VERSION 5.8 ;
BUSBITCHARS "[]" ;
DIVIDERCHAR "/" ;
UNITS
    DATABASE MICRONS 1000 ;
END UNITS

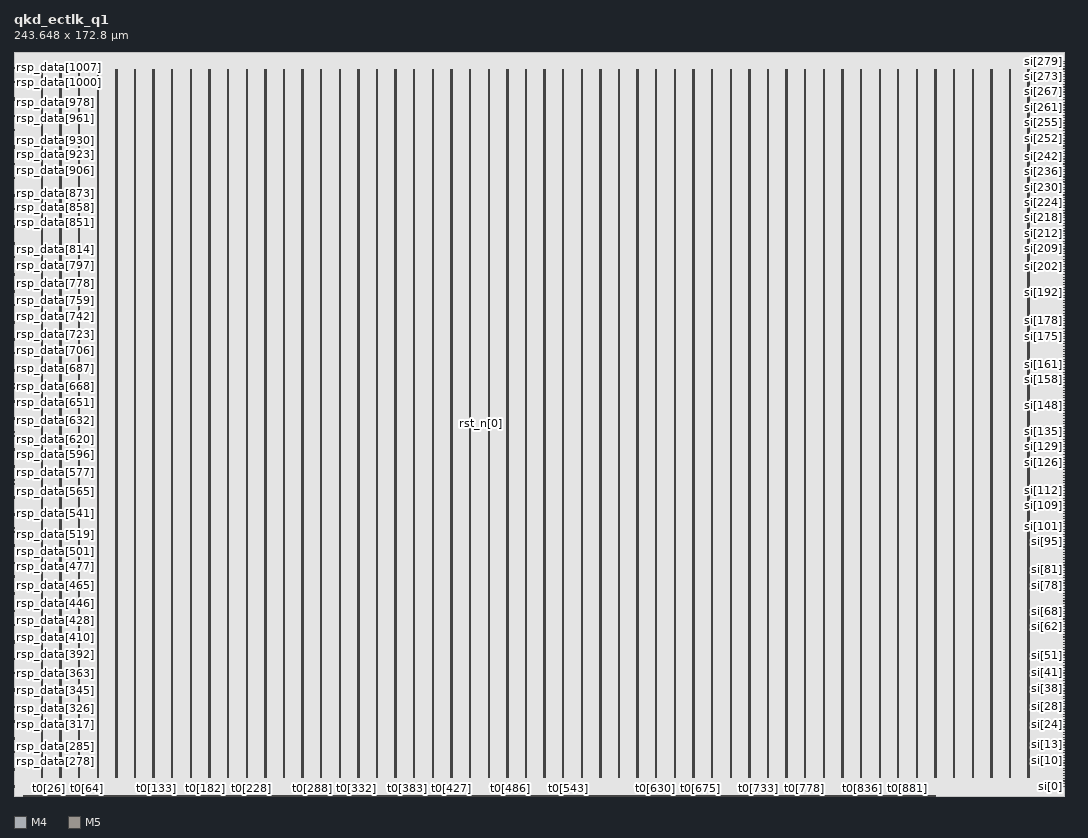
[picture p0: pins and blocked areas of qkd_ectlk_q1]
MACRO qkd_ectlk_q1
  FOREIGN qkd_ectlk_q1 0 0 ;
  CLASS BLOCK ;
  SIZE 243.648 BY 172.8 ;
  PIN cfg[0]
    DIRECTION INPUT ;
    USE SIGNAL ;
    PORT
      LAYER M4 ;
        RECT  0 2.076 0.192 2.1 ;
    END
  END cfg[0]
  PIN cfg[1]
    DIRECTION INPUT ;
    USE SIGNAL ;
    PORT
      LAYER M4 ;
        RECT  0 2.316 0.192 2.34 ;
    END
  END cfg[1]
  PIN cfg[2]
    DIRECTION INPUT ;
    USE SIGNAL ;
    PORT
      LAYER M4 ;
        RECT  0 2.556 0.192 2.58 ;
    END
  END cfg[2]
  PIN cfg[3]
    DIRECTION INPUT ;
    USE SIGNAL ;
    PORT
      LAYER M4 ;
        RECT  0 2.748 0.192 2.772 ;
    END
  END cfg[3]
  PIN cfg[4]
    DIRECTION INPUT ;
    USE SIGNAL ;
    PORT
      LAYER M4 ;
        RECT  0 2.988 0.192 3.012 ;
    END
  END cfg[4]
  PIN ck[0]
    DIRECTION INPUT ;
    USE SIGNAL ;
    PORT
      LAYER M5 ;
        RECT  108 86.16 108.048 86.64 ;
    END
  END ck[0]
  PIN rsp_data[1000]
    DIRECTION INPUT ;
    USE SIGNAL ;
    PORT
      LAYER M4 ;
        RECT  0 165.66 0.192 165.684 ;
    END
  END rsp_data[1000]
  PIN rsp_data[1001]
    DIRECTION INPUT ;
    USE SIGNAL ;
    PORT
      LAYER M4 ;
        RECT  0 165.852 0.192 165.876 ;
    END
  END rsp_data[1001]
  PIN rsp_data[1002]
    DIRECTION INPUT ;
    USE SIGNAL ;
    PORT
      LAYER M4 ;
        RECT  0 166.092 0.192 166.116 ;
    END
  END rsp_data[1002]
  PIN rsp_data[1003]
    DIRECTION INPUT ;
    USE SIGNAL ;
    PORT
      LAYER M4 ;
        RECT  0 166.332 0.192 166.356 ;
    END
  END rsp_data[1003]
  PIN rsp_data[1004]
    DIRECTION INPUT ;
    USE SIGNAL ;
    PORT
      LAYER M4 ;
        RECT  0 166.524 0.192 166.548 ;
    END
  END rsp_data[1004]
  PIN rsp_data[1005]
    DIRECTION INPUT ;
    USE SIGNAL ;
    PORT
      LAYER M4 ;
        RECT  0 166.764 0.192 166.788 ;
    END
  END rsp_data[1005]
  PIN rsp_data[1006]
    DIRECTION INPUT ;
    USE SIGNAL ;
    PORT
      LAYER M4 ;
        RECT  0 166.956 0.192 166.98 ;
    END
  END rsp_data[1006]
  PIN rsp_data[1007]
    DIRECTION INPUT ;
    USE SIGNAL ;
    PORT
      LAYER M4 ;
        RECT  0 167.196 0.192 167.22 ;
    END
  END rsp_data[1007]
  PIN rsp_data[1008]
    DIRECTION INPUT ;
    USE SIGNAL ;
    PORT
      LAYER M4 ;
        RECT  0 167.388 0.192 167.412 ;
    END
  END rsp_data[1008]
  PIN rsp_data[1009]
    DIRECTION INPUT ;
    USE SIGNAL ;
    PORT
      LAYER M4 ;
        RECT  0 167.628 0.192 167.652 ;
    END
  END rsp_data[1009]
  PIN rsp_data[1010]
    DIRECTION INPUT ;
    USE SIGNAL ;
    PORT
      LAYER M4 ;
        RECT  0 167.82 0.192 167.844 ;
    END
  END rsp_data[1010]
  PIN rsp_data[1011]
    DIRECTION INPUT ;
    USE SIGNAL ;
    PORT
      LAYER M4 ;
        RECT  0 168.06 0.192 168.084 ;
    END
  END rsp_data[1011]
  PIN rsp_data[1012]
    DIRECTION INPUT ;
    USE SIGNAL ;
    PORT
      LAYER M4 ;
        RECT  0 168.3 0.192 168.324 ;
    END
  END rsp_data[1012]
  PIN rsp_data[1013]
    DIRECTION INPUT ;
    USE SIGNAL ;
    PORT
      LAYER M4 ;
        RECT  0 168.492 0.192 168.516 ;
    END
  END rsp_data[1013]
  PIN rsp_data[1014]
    DIRECTION INPUT ;
    USE SIGNAL ;
    PORT
      LAYER M4 ;
        RECT  0 168.732 0.192 168.756 ;
    END
  END rsp_data[1014]
  PIN rsp_data[1015]
    DIRECTION INPUT ;
    USE SIGNAL ;
    PORT
      LAYER M4 ;
        RECT  0 168.924 0.192 168.948 ;
    END
  END rsp_data[1015]
  PIN rsp_data[1016]
    DIRECTION INPUT ;
    USE SIGNAL ;
    PORT
      LAYER M4 ;
        RECT  0 169.164 0.192 169.188 ;
    END
  END rsp_data[1016]
  PIN rsp_data[1017]
    DIRECTION INPUT ;
    USE SIGNAL ;
    PORT
      LAYER M4 ;
        RECT  0 169.356 0.192 169.38 ;
    END
  END rsp_data[1017]
  PIN rsp_data[1018]
    DIRECTION INPUT ;
    USE SIGNAL ;
    PORT
      LAYER M4 ;
        RECT  0 169.596 0.192 169.62 ;
    END
  END rsp_data[1018]
  PIN rsp_data[1019]
    DIRECTION INPUT ;
    USE SIGNAL ;
    PORT
      LAYER M4 ;
        RECT  0 169.788 0.192 169.812 ;
    END
  END rsp_data[1019]
  PIN rsp_data[1020]
    DIRECTION INPUT ;
    USE SIGNAL ;
    PORT
      LAYER M4 ;
        RECT  0 170.028 0.192 170.052 ;
    END
  END rsp_data[1020]
  PIN rsp_data[1021]
    DIRECTION INPUT ;
    USE SIGNAL ;
    PORT
      LAYER M4 ;
        RECT  0 170.22 0.192 170.244 ;
    END
  END rsp_data[1021]
  PIN rsp_data[1022]
    DIRECTION INPUT ;
    USE SIGNAL ;
    PORT
      LAYER M4 ;
        RECT  0 170.46 0.192 170.484 ;
    END
  END rsp_data[1022]
  PIN rsp_data[1023]
    DIRECTION INPUT ;
    USE SIGNAL ;
    PORT
      LAYER M4 ;
        RECT  0 170.7 0.192 170.724 ;
    END
  END rsp_data[1023]
  PIN rsp_data[256]
    DIRECTION INPUT ;
    USE SIGNAL ;
    PORT
      LAYER M4 ;
        RECT  0 3.18 0.192 3.204 ;
    END
  END rsp_data[256]
  PIN rsp_data[257]
    DIRECTION INPUT ;
    USE SIGNAL ;
    PORT
      LAYER M4 ;
        RECT  0 3.42 0.192 3.444 ;
    END
  END rsp_data[257]
  PIN rsp_data[258]
    DIRECTION INPUT ;
    USE SIGNAL ;
    PORT
      LAYER M4 ;
        RECT  0 3.612 0.192 3.636 ;
    END
  END rsp_data[258]
  PIN rsp_data[259]
    DIRECTION INPUT ;
    USE SIGNAL ;
    PORT
      LAYER M4 ;
        RECT  0 3.852 0.192 3.876 ;
    END
  END rsp_data[259]
  PIN rsp_data[260]
    DIRECTION INPUT ;
    USE SIGNAL ;
    PORT
      LAYER M4 ;
        RECT  0 4.044 0.192 4.068 ;
    END
  END rsp_data[260]
  PIN rsp_data[261]
    DIRECTION INPUT ;
    USE SIGNAL ;
    PORT
      LAYER M4 ;
        RECT  0 4.284 0.192 4.308 ;
    END
  END rsp_data[261]
  PIN rsp_data[262]
    DIRECTION INPUT ;
    USE SIGNAL ;
    PORT
      LAYER M4 ;
        RECT  0 4.476 0.192 4.5 ;
    END
  END rsp_data[262]
  PIN rsp_data[263]
    DIRECTION INPUT ;
    USE SIGNAL ;
    PORT
      LAYER M4 ;
        RECT  0 4.716 0.192 4.74 ;
    END
  END rsp_data[263]
  PIN rsp_data[264]
    DIRECTION INPUT ;
    USE SIGNAL ;
    PORT
      LAYER M4 ;
        RECT  0 4.956 0.192 4.98 ;
    END
  END rsp_data[264]
  PIN rsp_data[265]
    DIRECTION INPUT ;
    USE SIGNAL ;
    PORT
      LAYER M4 ;
        RECT  0 5.148 0.192 5.172 ;
    END
  END rsp_data[265]
  PIN rsp_data[266]
    DIRECTION INPUT ;
    USE SIGNAL ;
    PORT
      LAYER M4 ;
        RECT  0 5.388 0.192 5.412 ;
    END
  END rsp_data[266]
  PIN rsp_data[267]
    DIRECTION INPUT ;
    USE SIGNAL ;
    PORT
      LAYER M4 ;
        RECT  0 5.58 0.192 5.604 ;
    END
  END rsp_data[267]
  PIN rsp_data[268]
    DIRECTION INPUT ;
    USE SIGNAL ;
    PORT
      LAYER M4 ;
        RECT  0 5.82 0.192 5.844 ;
    END
  END rsp_data[268]
  PIN rsp_data[269]
    DIRECTION INPUT ;
    USE SIGNAL ;
    PORT
      LAYER M4 ;
        RECT  0 6.012 0.192 6.036 ;
    END
  END rsp_data[269]
  PIN rsp_data[270]
    DIRECTION INPUT ;
    USE SIGNAL ;
    PORT
      LAYER M4 ;
        RECT  0 6.252 0.192 6.276 ;
    END
  END rsp_data[270]
  PIN rsp_data[271]
    DIRECTION INPUT ;
    USE SIGNAL ;
    PORT
      LAYER M4 ;
        RECT  0 6.444 0.192 6.468 ;
    END
  END rsp_data[271]
  PIN rsp_data[272]
    DIRECTION INPUT ;
    USE SIGNAL ;
    PORT
      LAYER M4 ;
        RECT  0 6.684 0.192 6.708 ;
    END
  END rsp_data[272]
  PIN rsp_data[273]
    DIRECTION INPUT ;
    USE SIGNAL ;
    PORT
      LAYER M4 ;
        RECT  0 6.924 0.192 6.948 ;
    END
  END rsp_data[273]
  PIN rsp_data[274]
    DIRECTION INPUT ;
    USE SIGNAL ;
    PORT
      LAYER M4 ;
        RECT  0 7.116 0.192 7.14 ;
    END
  END rsp_data[274]
  PIN rsp_data[275]
    DIRECTION INPUT ;
    USE SIGNAL ;
    PORT
      LAYER M4 ;
        RECT  0 7.356 0.192 7.38 ;
    END
  END rsp_data[275]
  PIN rsp_data[276]
    DIRECTION INPUT ;
    USE SIGNAL ;
    PORT
      LAYER M4 ;
        RECT  0 7.548 0.192 7.572 ;
    END
  END rsp_data[276]
  PIN rsp_data[277]
    DIRECTION INPUT ;
    USE SIGNAL ;
    PORT
      LAYER M4 ;
        RECT  0 7.788 0.192 7.812 ;
    END
  END rsp_data[277]
  PIN rsp_data[278]
    DIRECTION INPUT ;
    USE SIGNAL ;
    PORT
      LAYER M4 ;
        RECT  0 7.98 0.192 8.004 ;
    END
  END rsp_data[278]
  PIN rsp_data[279]
    DIRECTION INPUT ;
    USE SIGNAL ;
    PORT
      LAYER M4 ;
        RECT  0 8.22 0.192 8.244 ;
    END
  END rsp_data[279]
  PIN rsp_data[280]
    DIRECTION INPUT ;
    USE SIGNAL ;
    PORT
      LAYER M4 ;
        RECT  0 8.412 0.192 8.436 ;
    END
  END rsp_data[280]
  PIN rsp_data[281]
    DIRECTION INPUT ;
    USE SIGNAL ;
    PORT
      LAYER M4 ;
        RECT  0 8.652 0.192 8.676 ;
    END
  END rsp_data[281]
  PIN rsp_data[282]
    DIRECTION INPUT ;
    USE SIGNAL ;
    PORT
      LAYER M4 ;
        RECT  0 8.844 0.192 8.868 ;
    END
  END rsp_data[282]
  PIN rsp_data[283]
    DIRECTION INPUT ;
    USE SIGNAL ;
    PORT
      LAYER M4 ;
        RECT  0 9.084 0.192 9.108 ;
    END
  END rsp_data[283]
  PIN rsp_data[284]
    DIRECTION INPUT ;
    USE SIGNAL ;
    PORT
      LAYER M4 ;
        RECT  0 9.324 0.192 9.348 ;
    END
  END rsp_data[284]
  PIN rsp_data[285]
    DIRECTION INPUT ;
    USE SIGNAL ;
    PORT
      LAYER M4 ;
        RECT  0 9.516 0.192 9.54 ;
    END
  END rsp_data[285]
  PIN rsp_data[286]
    DIRECTION INPUT ;
    USE SIGNAL ;
    PORT
      LAYER M4 ;
        RECT  0 9.756 0.192 9.78 ;
    END
  END rsp_data[286]
  PIN rsp_data[287]
    DIRECTION INPUT ;
    USE SIGNAL ;
    PORT
      LAYER M4 ;
        RECT  0 9.948 0.192 9.972 ;
    END
  END rsp_data[287]
  PIN rsp_data[288]
    DIRECTION INPUT ;
    USE SIGNAL ;
    PORT
      LAYER M4 ;
        RECT  0 10.188 0.192 10.212 ;
    END
  END rsp_data[288]
  PIN rsp_data[289]
    DIRECTION INPUT ;
    USE SIGNAL ;
    PORT
      LAYER M4 ;
        RECT  0 10.38 0.192 10.404 ;
    END
  END rsp_data[289]
  PIN rsp_data[290]
    DIRECTION INPUT ;
    USE SIGNAL ;
    PORT
      LAYER M4 ;
        RECT  0 10.62 0.192 10.644 ;
    END
  END rsp_data[290]
  PIN rsp_data[291]
    DIRECTION INPUT ;
    USE SIGNAL ;
    PORT
      LAYER M4 ;
        RECT  0 10.812 0.192 10.836 ;
    END
  END rsp_data[291]
  PIN rsp_data[292]
    DIRECTION INPUT ;
    USE SIGNAL ;
    PORT
      LAYER M4 ;
        RECT  0 11.052 0.192 11.076 ;
    END
  END rsp_data[292]
  PIN rsp_data[293]
    DIRECTION INPUT ;
    USE SIGNAL ;
    PORT
      LAYER M4 ;
        RECT  0 11.292 0.192 11.316 ;
    END
  END rsp_data[293]
  PIN rsp_data[294]
    DIRECTION INPUT ;
    USE SIGNAL ;
    PORT
      LAYER M4 ;
        RECT  0 11.484 0.192 11.508 ;
    END
  END rsp_data[294]
  PIN rsp_data[295]
    DIRECTION INPUT ;
    USE SIGNAL ;
    PORT
      LAYER M4 ;
        RECT  0 11.724 0.192 11.748 ;
    END
  END rsp_data[295]
  PIN rsp_data[296]
    DIRECTION INPUT ;
    USE SIGNAL ;
    PORT
      LAYER M4 ;
        RECT  0 11.916 0.192 11.94 ;
    END
  END rsp_data[296]
  PIN rsp_data[297]
    DIRECTION INPUT ;
    USE SIGNAL ;
    PORT
      LAYER M4 ;
        RECT  0 12.156 0.192 12.18 ;
    END
  END rsp_data[297]
  PIN rsp_data[298]
    DIRECTION INPUT ;
    USE SIGNAL ;
    PORT
      LAYER M4 ;
        RECT  0 12.348 0.192 12.372 ;
    END
  END rsp_data[298]
  PIN rsp_data[299]
    DIRECTION INPUT ;
    USE SIGNAL ;
    PORT
      LAYER M4 ;
        RECT  0 12.588 0.192 12.612 ;
    END
  END rsp_data[299]
  PIN rsp_data[300]
    DIRECTION INPUT ;
    USE SIGNAL ;
    PORT
      LAYER M4 ;
        RECT  0 12.78 0.192 12.804 ;
    END
  END rsp_data[300]
  PIN rsp_data[301]
    DIRECTION INPUT ;
    USE SIGNAL ;
    PORT
      LAYER M4 ;
        RECT  0 13.02 0.192 13.044 ;
    END
  END rsp_data[301]
  PIN rsp_data[302]
    DIRECTION INPUT ;
    USE SIGNAL ;
    PORT
      LAYER M4 ;
        RECT  0 13.212 0.192 13.236 ;
    END
  END rsp_data[302]
  PIN rsp_data[303]
    DIRECTION INPUT ;
    USE SIGNAL ;
    PORT
      LAYER M4 ;
        RECT  0 13.452 0.192 13.476 ;
    END
  END rsp_data[303]
  PIN rsp_data[304]
    DIRECTION INPUT ;
    USE SIGNAL ;
    PORT
      LAYER M4 ;
        RECT  0 13.692 0.192 13.716 ;
    END
  END rsp_data[304]
  PIN rsp_data[305]
    DIRECTION INPUT ;
    USE SIGNAL ;
    PORT
      LAYER M4 ;
        RECT  0 13.884 0.192 13.908 ;
    END
  END rsp_data[305]
  PIN rsp_data[306]
    DIRECTION INPUT ;
    USE SIGNAL ;
    PORT
      LAYER M4 ;
        RECT  0 14.124 0.192 14.148 ;
    END
  END rsp_data[306]
  PIN rsp_data[307]
    DIRECTION INPUT ;
    USE SIGNAL ;
    PORT
      LAYER M4 ;
        RECT  0 14.316 0.192 14.34 ;
    END
  END rsp_data[307]
  PIN rsp_data[308]
    DIRECTION INPUT ;
    USE SIGNAL ;
    PORT
      LAYER M4 ;
        RECT  0 14.556 0.192 14.58 ;
    END
  END rsp_data[308]
  PIN rsp_data[309]
    DIRECTION INPUT ;
    USE SIGNAL ;
    PORT
      LAYER M4 ;
        RECT  0 14.748 0.192 14.772 ;
    END
  END rsp_data[309]
  PIN rsp_data[310]
    DIRECTION INPUT ;
    USE SIGNAL ;
    PORT
      LAYER M4 ;
        RECT  0 14.988 0.192 15.012 ;
    END
  END rsp_data[310]
  PIN rsp_data[311]
    DIRECTION INPUT ;
    USE SIGNAL ;
    PORT
      LAYER M4 ;
        RECT  0 15.18 0.192 15.204 ;
    END
  END rsp_data[311]
  PIN rsp_data[312]
    DIRECTION INPUT ;
    USE SIGNAL ;
    PORT
      LAYER M4 ;
        RECT  0 15.42 0.192 15.444 ;
    END
  END rsp_data[312]
  PIN rsp_data[313]
    DIRECTION INPUT ;
    USE SIGNAL ;
    PORT
      LAYER M4 ;
        RECT  0 15.66 0.192 15.684 ;
    END
  END rsp_data[313]
  PIN rsp_data[314]
    DIRECTION INPUT ;
    USE SIGNAL ;
    PORT
      LAYER M4 ;
        RECT  0 15.852 0.192 15.876 ;
    END
  END rsp_data[314]
  PIN rsp_data[315]
    DIRECTION INPUT ;
    USE SIGNAL ;
    PORT
      LAYER M4 ;
        RECT  0 16.092 0.192 16.116 ;
    END
  END rsp_data[315]
  PIN rsp_data[316]
    DIRECTION INPUT ;
    USE SIGNAL ;
    PORT
      LAYER M4 ;
        RECT  0 16.284 0.192 16.308 ;
    END
  END rsp_data[316]
  PIN rsp_data[317]
    DIRECTION INPUT ;
    USE SIGNAL ;
    PORT
      LAYER M4 ;
        RECT  0 16.524 0.192 16.548 ;
    END
  END rsp_data[317]
  PIN rsp_data[318]
    DIRECTION INPUT ;
    USE SIGNAL ;
    PORT
      LAYER M4 ;
        RECT  0 16.716 0.192 16.74 ;
    END
  END rsp_data[318]
  PIN rsp_data[319]
    DIRECTION INPUT ;
    USE SIGNAL ;
    PORT
      LAYER M4 ;
        RECT  0 16.956 0.192 16.98 ;
    END
  END rsp_data[319]
  PIN rsp_data[320]
    DIRECTION INPUT ;
    USE SIGNAL ;
    PORT
      LAYER M4 ;
        RECT  0 17.148 0.192 17.172 ;
    END
  END rsp_data[320]
  PIN rsp_data[321]
    DIRECTION INPUT ;
    USE SIGNAL ;
    PORT
      LAYER M4 ;
        RECT  0 17.388 0.192 17.412 ;
    END
  END rsp_data[321]
  PIN rsp_data[322]
    DIRECTION INPUT ;
    USE SIGNAL ;
    PORT
      LAYER M4 ;
        RECT  0 17.58 0.192 17.604 ;
    END
  END rsp_data[322]
  PIN rsp_data[323]
    DIRECTION INPUT ;
    USE SIGNAL ;
    PORT
      LAYER M4 ;
        RECT  0 17.82 0.192 17.844 ;
    END
  END rsp_data[323]
  PIN rsp_data[324]
    DIRECTION INPUT ;
    USE SIGNAL ;
    PORT
      LAYER M4 ;
        RECT  0 18.06 0.192 18.084 ;
    END
  END rsp_data[324]
  PIN rsp_data[325]
    DIRECTION INPUT ;
    USE SIGNAL ;
    PORT
      LAYER M4 ;
        RECT  0 18.252 0.192 18.276 ;
    END
  END rsp_data[325]
  PIN rsp_data[326]
    DIRECTION INPUT ;
    USE SIGNAL ;
    PORT
      LAYER M4 ;
        RECT  0 18.492 0.192 18.516 ;
    END
  END rsp_data[326]
  PIN rsp_data[327]
    DIRECTION INPUT ;
    USE SIGNAL ;
    PORT
      LAYER M4 ;
        RECT  0 18.684 0.192 18.708 ;
    END
  END rsp_data[327]
  PIN rsp_data[328]
    DIRECTION INPUT ;
    USE SIGNAL ;
    PORT
      LAYER M4 ;
        RECT  0 18.924 0.192 18.948 ;
    END
  END rsp_data[328]
  PIN rsp_data[329]
    DIRECTION INPUT ;
    USE SIGNAL ;
    PORT
      LAYER M4 ;
        RECT  0 19.116 0.192 19.14 ;
    END
  END rsp_data[329]
  PIN rsp_data[330]
    DIRECTION INPUT ;
    USE SIGNAL ;
    PORT
      LAYER M4 ;
        RECT  0 19.356 0.192 19.38 ;
    END
  END rsp_data[330]
  PIN rsp_data[331]
    DIRECTION INPUT ;
    USE SIGNAL ;
    PORT
      LAYER M4 ;
        RECT  0 19.548 0.192 19.572 ;
    END
  END rsp_data[331]
  PIN rsp_data[332]
    DIRECTION INPUT ;
    USE SIGNAL ;
    PORT
      LAYER M4 ;
        RECT  0 19.788 0.192 19.812 ;
    END
  END rsp_data[332]
  PIN rsp_data[333]
    DIRECTION INPUT ;
    USE SIGNAL ;
    PORT
      LAYER M4 ;
        RECT  0 19.98 0.192 20.004 ;
    END
  END rsp_data[333]
  PIN rsp_data[334]
    DIRECTION INPUT ;
    USE SIGNAL ;
    PORT
      LAYER M4 ;
        RECT  0 20.22 0.192 20.244 ;
    END
  END rsp_data[334]
  PIN rsp_data[335]
    DIRECTION INPUT ;
    USE SIGNAL ;
    PORT
      LAYER M4 ;
        RECT  0 20.46 0.192 20.484 ;
    END
  END rsp_data[335]
  PIN rsp_data[336]
    DIRECTION INPUT ;
    USE SIGNAL ;
    PORT
      LAYER M4 ;
        RECT  0 20.652 0.192 20.676 ;
    END
  END rsp_data[336]
  PIN rsp_data[337]
    DIRECTION INPUT ;
    USE SIGNAL ;
    PORT
      LAYER M4 ;
        RECT  0 20.892 0.192 20.916 ;
    END
  END rsp_data[337]
  PIN rsp_data[338]
    DIRECTION INPUT ;
    USE SIGNAL ;
    PORT
      LAYER M4 ;
        RECT  0 21.084 0.192 21.108 ;
    END
  END rsp_data[338]
  PIN rsp_data[339]
    DIRECTION INPUT ;
    USE SIGNAL ;
    PORT
      LAYER M4 ;
        RECT  0 21.324 0.192 21.348 ;
    END
  END rsp_data[339]
  PIN rsp_data[340]
    DIRECTION INPUT ;
    USE SIGNAL ;
    PORT
      LAYER M4 ;
        RECT  0 21.516 0.192 21.54 ;
    END
  END rsp_data[340]
  PIN rsp_data[341]
    DIRECTION INPUT ;
    USE SIGNAL ;
    PORT
      LAYER M4 ;
        RECT  0 21.756 0.192 21.78 ;
    END
  END rsp_data[341]
  PIN rsp_data[342]
    DIRECTION INPUT ;
    USE SIGNAL ;
    PORT
      LAYER M4 ;
        RECT  0 21.948 0.192 21.972 ;
    END
  END rsp_data[342]
  PIN rsp_data[343]
    DIRECTION INPUT ;
    USE SIGNAL ;
    PORT
      LAYER M4 ;
        RECT  0 22.188 0.192 22.212 ;
    END
  END rsp_data[343]
  PIN rsp_data[344]
    DIRECTION INPUT ;
    USE SIGNAL ;
    PORT
      LAYER M4 ;
        RECT  0 22.428 0.192 22.452 ;
    END
  END rsp_data[344]
  PIN rsp_data[345]
    DIRECTION INPUT ;
    USE SIGNAL ;
    PORT
      LAYER M4 ;
        RECT  0 22.62 0.192 22.644 ;
    END
  END rsp_data[345]
  PIN rsp_data[346]
    DIRECTION INPUT ;
    USE SIGNAL ;
    PORT
      LAYER M4 ;
        RECT  0 22.86 0.192 22.884 ;
    END
  END rsp_data[346]
  PIN rsp_data[347]
    DIRECTION INPUT ;
    USE SIGNAL ;
    PORT
      LAYER M4 ;
        RECT  0 23.052 0.192 23.076 ;
    END
  END rsp_data[347]
  PIN rsp_data[348]
    DIRECTION INPUT ;
    USE SIGNAL ;
    PORT
      LAYER M4 ;
        RECT  0 23.292 0.192 23.316 ;
    END
  END rsp_data[348]
  PIN rsp_data[349]
    DIRECTION INPUT ;
    USE SIGNAL ;
    PORT
      LAYER M4 ;
        RECT  0 23.484 0.192 23.508 ;
    END
  END rsp_data[349]
  PIN rsp_data[350]
    DIRECTION INPUT ;
    USE SIGNAL ;
    PORT
      LAYER M4 ;
        RECT  0 23.724 0.192 23.748 ;
    END
  END rsp_data[350]
  PIN rsp_data[351]
    DIRECTION INPUT ;
    USE SIGNAL ;
    PORT
      LAYER M4 ;
        RECT  0 23.916 0.192 23.94 ;
    END
  END rsp_data[351]
  PIN rsp_data[352]
    DIRECTION INPUT ;
    USE SIGNAL ;
    PORT
      LAYER M4 ;
        RECT  0 24.156 0.192 24.18 ;
    END
  END rsp_data[352]
  PIN rsp_data[353]
    DIRECTION INPUT ;
    USE SIGNAL ;
    PORT
      LAYER M4 ;
        RECT  0 24.348 0.192 24.372 ;
    END
  END rsp_data[353]
  PIN rsp_data[354]
    DIRECTION INPUT ;
    USE SIGNAL ;
    PORT
      LAYER M4 ;
        RECT  0 24.588 0.192 24.612 ;
    END
  END rsp_data[354]
  PIN rsp_data[355]
    DIRECTION INPUT ;
    USE SIGNAL ;
    PORT
      LAYER M4 ;
        RECT  0 24.828 0.192 24.852 ;
    END
  END rsp_data[355]
  PIN rsp_data[356]
    DIRECTION INPUT ;
    USE SIGNAL ;
    PORT
      LAYER M4 ;
        RECT  0 25.02 0.192 25.044 ;
    END
  END rsp_data[356]
  PIN rsp_data[357]
    DIRECTION INPUT ;
    USE SIGNAL ;
    PORT
      LAYER M4 ;
        RECT  0 25.26 0.192 25.284 ;
    END
  END rsp_data[357]
  PIN rsp_data[358]
    DIRECTION INPUT ;
    USE SIGNAL ;
    PORT
      LAYER M4 ;
        RECT  0 25.452 0.192 25.476 ;
    END
  END rsp_data[358]
  PIN rsp_data[359]
    DIRECTION INPUT ;
    USE SIGNAL ;
    PORT
      LAYER M4 ;
        RECT  0 25.692 0.192 25.716 ;
    END
  END rsp_data[359]
  PIN rsp_data[360]
    DIRECTION INPUT ;
    USE SIGNAL ;
    PORT
      LAYER M4 ;
        RECT  0 25.884 0.192 25.908 ;
    END
  END rsp_data[360]
  PIN rsp_data[361]
    DIRECTION INPUT ;
    USE SIGNAL ;
    PORT
      LAYER M4 ;
        RECT  0 26.124 0.192 26.148 ;
    END
  END rsp_data[361]
  PIN rsp_data[362]
    DIRECTION INPUT ;
    USE SIGNAL ;
    PORT
      LAYER M4 ;
        RECT  0 26.316 0.192 26.34 ;
    END
  END rsp_data[362]
  PIN rsp_data[363]
    DIRECTION INPUT ;
    USE SIGNAL ;
    PORT
      LAYER M4 ;
        RECT  0 26.556 0.192 26.58 ;
    END
  END rsp_data[363]
  PIN rsp_data[364]
    DIRECTION INPUT ;
    USE SIGNAL ;
    PORT
      LAYER M4 ;
        RECT  0 26.796 0.192 26.82 ;
    END
  END rsp_data[364]
  PIN rsp_data[365]
    DIRECTION INPUT ;
    USE SIGNAL ;
    PORT
      LAYER M4 ;
        RECT  0 26.988 0.192 27.012 ;
    END
  END rsp_data[365]
  PIN rsp_data[366]
    DIRECTION INPUT ;
    USE SIGNAL ;
    PORT
      LAYER M4 ;
        RECT  0 27.228 0.192 27.252 ;
    END
  END rsp_data[366]
  PIN rsp_data[367]
    DIRECTION INPUT ;
    USE SIGNAL ;
    PORT
      LAYER M4 ;
        RECT  0 27.42 0.192 27.444 ;
    END
  END rsp_data[367]
  PIN rsp_data[368]
    DIRECTION INPUT ;
    USE SIGNAL ;
    PORT
      LAYER M4 ;
        RECT  0 27.66 0.192 27.684 ;
    END
  END rsp_data[368]
  PIN rsp_data[369]
    DIRECTION INPUT ;
    USE SIGNAL ;
    PORT
      LAYER M4 ;
        RECT  0 27.852 0.192 27.876 ;
    END
  END rsp_data[369]
  PIN rsp_data[370]
    DIRECTION INPUT ;
    USE SIGNAL ;
    PORT
      LAYER M4 ;
        RECT  0 28.092 0.192 28.116 ;
    END
  END rsp_data[370]
  PIN rsp_data[371]
    DIRECTION INPUT ;
    USE SIGNAL ;
    PORT
      LAYER M4 ;
        RECT  0 28.284 0.192 28.308 ;
    END
  END rsp_data[371]
  PIN rsp_data[372]
    DIRECTION INPUT ;
    USE SIGNAL ;
    PORT
      LAYER M4 ;
        RECT  0 28.524 0.192 28.548 ;
    END
  END rsp_data[372]
  PIN rsp_data[373]
    DIRECTION INPUT ;
    USE SIGNAL ;
    PORT
      LAYER M4 ;
        RECT  0 28.716 0.192 28.74 ;
    END
  END rsp_data[373]
  PIN rsp_data[374]
    DIRECTION INPUT ;
    USE SIGNAL ;
    PORT
      LAYER M4 ;
        RECT  0 28.956 0.192 28.98 ;
    END
  END rsp_data[374]
  PIN rsp_data[375]
    DIRECTION INPUT ;
    USE SIGNAL ;
    PORT
      LAYER M4 ;
        RECT  0 29.196 0.192 29.22 ;
    END
  END rsp_data[375]
  PIN rsp_data[376]
    DIRECTION INPUT ;
    USE SIGNAL ;
    PORT
      LAYER M4 ;
        RECT  0 29.388 0.192 29.412 ;
    END
  END rsp_data[376]
  PIN rsp_data[377]
    DIRECTION INPUT ;
    USE SIGNAL ;
    PORT
      LAYER M4 ;
        RECT  0 29.628 0.192 29.652 ;
    END
  END rsp_data[377]
  PIN rsp_data[378]
    DIRECTION INPUT ;
    USE SIGNAL ;
    PORT
      LAYER M4 ;
        RECT  0 29.82 0.192 29.844 ;
    END
  END rsp_data[378]
  PIN rsp_data[379]
    DIRECTION INPUT ;
    USE SIGNAL ;
    PORT
      LAYER M4 ;
        RECT  0 30.06 0.192 30.084 ;
    END
  END rsp_data[379]
  PIN rsp_data[380]
    DIRECTION INPUT ;
    USE SIGNAL ;
    PORT
      LAYER M4 ;
        RECT  0 30.252 0.192 30.276 ;
    END
  END rsp_data[380]
  PIN rsp_data[381]
    DIRECTION INPUT ;
    USE SIGNAL ;
    PORT
      LAYER M4 ;
        RECT  0 30.492 0.192 30.516 ;
    END
  END rsp_data[381]
  PIN rsp_data[382]
    DIRECTION INPUT ;
    USE SIGNAL ;
    PORT
      LAYER M4 ;
        RECT  0 30.684 0.192 30.708 ;
    END
  END rsp_data[382]
  PIN rsp_data[383]
    DIRECTION INPUT ;
    USE SIGNAL ;
    PORT
      LAYER M4 ;
        RECT  0 30.924 0.192 30.948 ;
    END
  END rsp_data[383]
  PIN rsp_data[384]
    DIRECTION INPUT ;
    USE SIGNAL ;
    PORT
      LAYER M4 ;
        RECT  0 31.164 0.192 31.188 ;
    END
  END rsp_data[384]
  PIN rsp_data[385]
    DIRECTION INPUT ;
    USE SIGNAL ;
    PORT
      LAYER M4 ;
        RECT  0 31.356 0.192 31.38 ;
    END
  END rsp_data[385]
  PIN rsp_data[386]
    DIRECTION INPUT ;
    USE SIGNAL ;
    PORT
      LAYER M4 ;
        RECT  0 31.596 0.192 31.62 ;
    END
  END rsp_data[386]
  PIN rsp_data[387]
    DIRECTION INPUT ;
    USE SIGNAL ;
    PORT
      LAYER M4 ;
        RECT  0 31.788 0.192 31.812 ;
    END
  END rsp_data[387]
  PIN rsp_data[388]
    DIRECTION INPUT ;
    USE SIGNAL ;
    PORT
      LAYER M4 ;
        RECT  0 32.028 0.192 32.052 ;
    END
  END rsp_data[388]
  PIN rsp_data[389]
    DIRECTION INPUT ;
    USE SIGNAL ;
    PORT
      LAYER M4 ;
        RECT  0 32.22 0.192 32.244 ;
    END
  END rsp_data[389]
  PIN rsp_data[390]
    DIRECTION INPUT ;
    USE SIGNAL ;
    PORT
      LAYER M4 ;
        RECT  0 32.46 0.192 32.484 ;
    END
  END rsp_data[390]
  PIN rsp_data[391]
    DIRECTION INPUT ;
    USE SIGNAL ;
    PORT
      LAYER M4 ;
        RECT  0 32.652 0.192 32.676 ;
    END
  END rsp_data[391]
  PIN rsp_data[392]
    DIRECTION INPUT ;
    USE SIGNAL ;
    PORT
      LAYER M4 ;
        RECT  0 32.892 0.192 32.916 ;
    END
  END rsp_data[392]
  PIN rsp_data[393]
    DIRECTION INPUT ;
    USE SIGNAL ;
    PORT
      LAYER M4 ;
        RECT  0 33.084 0.192 33.108 ;
    END
  END rsp_data[393]
  PIN rsp_data[394]
    DIRECTION INPUT ;
    USE SIGNAL ;
    PORT
      LAYER M4 ;
        RECT  0 33.324 0.192 33.348 ;
    END
  END rsp_data[394]
  PIN rsp_data[395]
    DIRECTION INPUT ;
    USE SIGNAL ;
    PORT
      LAYER M4 ;
        RECT  0 33.564 0.192 33.588 ;
    END
  END rsp_data[395]
  PIN rsp_data[396]
    DIRECTION INPUT ;
    USE SIGNAL ;
    PORT
      LAYER M4 ;
        RECT  0 33.756 0.192 33.78 ;
    END
  END rsp_data[396]
  PIN rsp_data[397]
    DIRECTION INPUT ;
    USE SIGNAL ;
    PORT
      LAYER M4 ;
        RECT  0 33.996 0.192 34.02 ;
    END
  END rsp_data[397]
  PIN rsp_data[398]
    DIRECTION INPUT ;
    USE SIGNAL ;
    PORT
      LAYER M4 ;
        RECT  0 34.188 0.192 34.212 ;
    END
  END rsp_data[398]
  PIN rsp_data[399]
    DIRECTION INPUT ;
    USE SIGNAL ;
    PORT
      LAYER M4 ;
        RECT  0 34.428 0.192 34.452 ;
    END
  END rsp_data[399]
  PIN rsp_data[400]
    DIRECTION INPUT ;
    USE SIGNAL ;
    PORT
      LAYER M4 ;
        RECT  0 34.62 0.192 34.644 ;
    END
  END rsp_data[400]
  PIN rsp_data[401]
    DIRECTION INPUT ;
    USE SIGNAL ;
    PORT
      LAYER M4 ;
        RECT  0 34.86 0.192 34.884 ;
    END
  END rsp_data[401]
  PIN rsp_data[402]
    DIRECTION INPUT ;
    USE SIGNAL ;
    PORT
      LAYER M4 ;
        RECT  0 35.052 0.192 35.076 ;
    END
  END rsp_data[402]
  PIN rsp_data[403]
    DIRECTION INPUT ;
    USE SIGNAL ;
    PORT
      LAYER M4 ;
        RECT  0 35.292 0.192 35.316 ;
    END
  END rsp_data[403]
  PIN rsp_data[404]
    DIRECTION INPUT ;
    USE SIGNAL ;
    PORT
      LAYER M4 ;
        RECT  0 35.484 0.192 35.508 ;
    END
  END rsp_data[404]
  PIN rsp_data[405]
    DIRECTION INPUT ;
    USE SIGNAL ;
    PORT
      LAYER M4 ;
        RECT  0 35.724 0.192 35.748 ;
    END
  END rsp_data[405]
  PIN rsp_data[406]
    DIRECTION INPUT ;
    USE SIGNAL ;
    PORT
      LAYER M4 ;
        RECT  0 35.964 0.192 35.988 ;
    END
  END rsp_data[406]
  PIN rsp_data[407]
    DIRECTION INPUT ;
    USE SIGNAL ;
    PORT
      LAYER M4 ;
        RECT  0 36.156 0.192 36.18 ;
    END
  END rsp_data[407]
  PIN rsp_data[408]
    DIRECTION INPUT ;
    USE SIGNAL ;
    PORT
      LAYER M4 ;
        RECT  0 36.396 0.192 36.42 ;
    END
  END rsp_data[408]
  PIN rsp_data[409]
    DIRECTION INPUT ;
    USE SIGNAL ;
    PORT
      LAYER M4 ;
        RECT  0 36.588 0.192 36.612 ;
    END
  END rsp_data[409]
  PIN rsp_data[410]
    DIRECTION INPUT ;
    USE SIGNAL ;
    PORT
      LAYER M4 ;
        RECT  0 36.828 0.192 36.852 ;
    END
  END rsp_data[410]
  PIN rsp_data[411]
    DIRECTION INPUT ;
    USE SIGNAL ;
    PORT
      LAYER M4 ;
        RECT  0 37.02 0.192 37.044 ;
    END
  END rsp_data[411]
  PIN rsp_data[412]
    DIRECTION INPUT ;
    USE SIGNAL ;
    PORT
      LAYER M4 ;
        RECT  0 37.26 0.192 37.284 ;
    END
  END rsp_data[412]
  PIN rsp_data[413]
    DIRECTION INPUT ;
    USE SIGNAL ;
    PORT
      LAYER M4 ;
        RECT  0 37.452 0.192 37.476 ;
    END
  END rsp_data[413]
  PIN rsp_data[414]
    DIRECTION INPUT ;
    USE SIGNAL ;
    PORT
      LAYER M4 ;
        RECT  0 37.692 0.192 37.716 ;
    END
  END rsp_data[414]
  PIN rsp_data[415]
    DIRECTION INPUT ;
    USE SIGNAL ;
    PORT
      LAYER M4 ;
        RECT  0 37.932 0.192 37.956 ;
    END
  END rsp_data[415]
  PIN rsp_data[416]
    DIRECTION INPUT ;
    USE SIGNAL ;
    PORT
      LAYER M4 ;
        RECT  0 38.124 0.192 38.148 ;
    END
  END rsp_data[416]
  PIN rsp_data[417]
    DIRECTION INPUT ;
    USE SIGNAL ;
    PORT
      LAYER M4 ;
        RECT  0 38.364 0.192 38.388 ;
    END
  END rsp_data[417]
  PIN rsp_data[418]
    DIRECTION INPUT ;
    USE SIGNAL ;
    PORT
      LAYER M4 ;
        RECT  0 38.556 0.192 38.58 ;
    END
  END rsp_data[418]
  PIN rsp_data[419]
    DIRECTION INPUT ;
    USE SIGNAL ;
    PORT
      LAYER M4 ;
        RECT  0 38.796 0.192 38.82 ;
    END
  END rsp_data[419]
  PIN rsp_data[420]
    DIRECTION INPUT ;
    USE SIGNAL ;
    PORT
      LAYER M4 ;
        RECT  0 38.988 0.192 39.012 ;
    END
  END rsp_data[420]
  PIN rsp_data[421]
    DIRECTION INPUT ;
    USE SIGNAL ;
    PORT
      LAYER M4 ;
        RECT  0 39.228 0.192 39.252 ;
    END
  END rsp_data[421]
  PIN rsp_data[422]
    DIRECTION INPUT ;
    USE SIGNAL ;
    PORT
      LAYER M4 ;
        RECT  0 39.42 0.192 39.444 ;
    END
  END rsp_data[422]
  PIN rsp_data[423]
    DIRECTION INPUT ;
    USE SIGNAL ;
    PORT
      LAYER M4 ;
        RECT  0 39.66 0.192 39.684 ;
    END
  END rsp_data[423]
  PIN rsp_data[424]
    DIRECTION INPUT ;
    USE SIGNAL ;
    PORT
      LAYER M4 ;
        RECT  0 39.852 0.192 39.876 ;
    END
  END rsp_data[424]
  PIN rsp_data[425]
    DIRECTION INPUT ;
    USE SIGNAL ;
    PORT
      LAYER M4 ;
        RECT  0 40.092 0.192 40.116 ;
    END
  END rsp_data[425]
  PIN rsp_data[426]
    DIRECTION INPUT ;
    USE SIGNAL ;
    PORT
      LAYER M4 ;
        RECT  0 40.332 0.192 40.356 ;
    END
  END rsp_data[426]
  PIN rsp_data[427]
    DIRECTION INPUT ;
    USE SIGNAL ;
    PORT
      LAYER M4 ;
        RECT  0 40.524 0.192 40.548 ;
    END
  END rsp_data[427]
  PIN rsp_data[428]
    DIRECTION INPUT ;
    USE SIGNAL ;
    PORT
      LAYER M4 ;
        RECT  0 40.764 0.192 40.788 ;
    END
  END rsp_data[428]
  PIN rsp_data[429]
    DIRECTION INPUT ;
    USE SIGNAL ;
    PORT
      LAYER M4 ;
        RECT  0 40.956 0.192 40.98 ;
    END
  END rsp_data[429]
  PIN rsp_data[430]
    DIRECTION INPUT ;
    USE SIGNAL ;
    PORT
      LAYER M4 ;
        RECT  0 41.196 0.192 41.22 ;
    END
  END rsp_data[430]
  PIN rsp_data[431]
    DIRECTION INPUT ;
    USE SIGNAL ;
    PORT
      LAYER M4 ;
        RECT  0 41.388 0.192 41.412 ;
    END
  END rsp_data[431]
  PIN rsp_data[432]
    DIRECTION INPUT ;
    USE SIGNAL ;
    PORT
      LAYER M4 ;
        RECT  0 41.628 0.192 41.652 ;
    END
  END rsp_data[432]
  PIN rsp_data[433]
    DIRECTION INPUT ;
    USE SIGNAL ;
    PORT
      LAYER M4 ;
        RECT  0 41.82 0.192 41.844 ;
    END
  END rsp_data[433]
  PIN rsp_data[434]
    DIRECTION INPUT ;
    USE SIGNAL ;
    PORT
      LAYER M4 ;
        RECT  0 42.06 0.192 42.084 ;
    END
  END rsp_data[434]
  PIN rsp_data[435]
    DIRECTION INPUT ;
    USE SIGNAL ;
    PORT
      LAYER M4 ;
        RECT  0 42.3 0.192 42.324 ;
    END
  END rsp_data[435]
  PIN rsp_data[436]
    DIRECTION INPUT ;
    USE SIGNAL ;
    PORT
      LAYER M4 ;
        RECT  0 42.492 0.192 42.516 ;
    END
  END rsp_data[436]
  PIN rsp_data[437]
    DIRECTION INPUT ;
    USE SIGNAL ;
    PORT
      LAYER M4 ;
        RECT  0 42.732 0.192 42.756 ;
    END
  END rsp_data[437]
  PIN rsp_data[438]
    DIRECTION INPUT ;
    USE SIGNAL ;
    PORT
      LAYER M4 ;
        RECT  0 42.924 0.192 42.948 ;
    END
  END rsp_data[438]
  PIN rsp_data[439]
    DIRECTION INPUT ;
    USE SIGNAL ;
    PORT
      LAYER M4 ;
        RECT  0 43.164 0.192 43.188 ;
    END
  END rsp_data[439]
  PIN rsp_data[440]
    DIRECTION INPUT ;
    USE SIGNAL ;
    PORT
      LAYER M4 ;
        RECT  0 43.356 0.192 43.38 ;
    END
  END rsp_data[440]
  PIN rsp_data[441]
    DIRECTION INPUT ;
    USE SIGNAL ;
    PORT
      LAYER M4 ;
        RECT  0 43.596 0.192 43.62 ;
    END
  END rsp_data[441]
  PIN rsp_data[442]
    DIRECTION INPUT ;
    USE SIGNAL ;
    PORT
      LAYER M4 ;
        RECT  0 43.788 0.192 43.812 ;
    END
  END rsp_data[442]
  PIN rsp_data[443]
    DIRECTION INPUT ;
    USE SIGNAL ;
    PORT
      LAYER M4 ;
        RECT  0 44.028 0.192 44.052 ;
    END
  END rsp_data[443]
  PIN rsp_data[444]
    DIRECTION INPUT ;
    USE SIGNAL ;
    PORT
      LAYER M4 ;
        RECT  0 44.22 0.192 44.244 ;
    END
  END rsp_data[444]
  PIN rsp_data[445]
    DIRECTION INPUT ;
    USE SIGNAL ;
    PORT
      LAYER M4 ;
        RECT  0 44.46 0.192 44.484 ;
    END
  END rsp_data[445]
  PIN rsp_data[446]
    DIRECTION INPUT ;
    USE SIGNAL ;
    PORT
      LAYER M4 ;
        RECT  0 44.7 0.192 44.724 ;
    END
  END rsp_data[446]
  PIN rsp_data[447]
    DIRECTION INPUT ;
    USE SIGNAL ;
    PORT
      LAYER M4 ;
        RECT  0 44.892 0.192 44.916 ;
    END
  END rsp_data[447]
  PIN rsp_data[448]
    DIRECTION INPUT ;
    USE SIGNAL ;
    PORT
      LAYER M4 ;
        RECT  0 45.132 0.192 45.156 ;
    END
  END rsp_data[448]
  PIN rsp_data[449]
    DIRECTION INPUT ;
    USE SIGNAL ;
    PORT
      LAYER M4 ;
        RECT  0 45.324 0.192 45.348 ;
    END
  END rsp_data[449]
  PIN rsp_data[450]
    DIRECTION INPUT ;
    USE SIGNAL ;
    PORT
      LAYER M4 ;
        RECT  0 45.564 0.192 45.588 ;
    END
  END rsp_data[450]
  PIN rsp_data[451]
    DIRECTION INPUT ;
    USE SIGNAL ;
    PORT
      LAYER M4 ;
        RECT  0 45.756 0.192 45.78 ;
    END
  END rsp_data[451]
  PIN rsp_data[452]
    DIRECTION INPUT ;
    USE SIGNAL ;
    PORT
      LAYER M4 ;
        RECT  0 45.996 0.192 46.02 ;
    END
  END rsp_data[452]
  PIN rsp_data[453]
    DIRECTION INPUT ;
    USE SIGNAL ;
    PORT
      LAYER M4 ;
        RECT  0 46.188 0.192 46.212 ;
    END
  END rsp_data[453]
  PIN rsp_data[454]
    DIRECTION INPUT ;
    USE SIGNAL ;
    PORT
      LAYER M4 ;
        RECT  0 46.428 0.192 46.452 ;
    END
  END rsp_data[454]
  PIN rsp_data[455]
    DIRECTION INPUT ;
    USE SIGNAL ;
    PORT
      LAYER M4 ;
        RECT  0 46.668 0.192 46.692 ;
    END
  END rsp_data[455]
  PIN rsp_data[456]
    DIRECTION INPUT ;
    USE SIGNAL ;
    PORT
      LAYER M4 ;
        RECT  0 46.86 0.192 46.884 ;
    END
  END rsp_data[456]
  PIN rsp_data[457]
    DIRECTION INPUT ;
    USE SIGNAL ;
    PORT
      LAYER M4 ;
        RECT  0 47.1 0.192 47.124 ;
    END
  END rsp_data[457]
  PIN rsp_data[458]
    DIRECTION INPUT ;
    USE SIGNAL ;
    PORT
      LAYER M4 ;
        RECT  0 47.292 0.192 47.316 ;
    END
  END rsp_data[458]
  PIN rsp_data[459]
    DIRECTION INPUT ;
    USE SIGNAL ;
    PORT
      LAYER M4 ;
        RECT  0 47.532 0.192 47.556 ;
    END
  END rsp_data[459]
  PIN rsp_data[460]
    DIRECTION INPUT ;
    USE SIGNAL ;
    PORT
      LAYER M4 ;
        RECT  0 47.724 0.192 47.748 ;
    END
  END rsp_data[460]
  PIN rsp_data[461]
    DIRECTION INPUT ;
    USE SIGNAL ;
    PORT
      LAYER M4 ;
        RECT  0 47.964 0.192 47.988 ;
    END
  END rsp_data[461]
  PIN rsp_data[462]
    DIRECTION INPUT ;
    USE SIGNAL ;
    PORT
      LAYER M4 ;
        RECT  0 48.156 0.192 48.18 ;
    END
  END rsp_data[462]
  PIN rsp_data[463]
    DIRECTION INPUT ;
    USE SIGNAL ;
    PORT
      LAYER M4 ;
        RECT  0 48.396 0.192 48.42 ;
    END
  END rsp_data[463]
  PIN rsp_data[464]
    DIRECTION INPUT ;
    USE SIGNAL ;
    PORT
      LAYER M4 ;
        RECT  0 48.588 0.192 48.612 ;
    END
  END rsp_data[464]
  PIN rsp_data[465]
    DIRECTION INPUT ;
    USE SIGNAL ;
    PORT
      LAYER M4 ;
        RECT  0 48.828 0.192 48.852 ;
    END
  END rsp_data[465]
  PIN rsp_data[466]
    DIRECTION INPUT ;
    USE SIGNAL ;
    PORT
      LAYER M4 ;
        RECT  0 49.068 0.192 49.092 ;
    END
  END rsp_data[466]
  PIN rsp_data[467]
    DIRECTION INPUT ;
    USE SIGNAL ;
    PORT
      LAYER M4 ;
        RECT  0 49.26 0.192 49.284 ;
    END
  END rsp_data[467]
  PIN rsp_data[468]
    DIRECTION INPUT ;
    USE SIGNAL ;
    PORT
      LAYER M4 ;
        RECT  0 49.5 0.192 49.524 ;
    END
  END rsp_data[468]
  PIN rsp_data[469]
    DIRECTION INPUT ;
    USE SIGNAL ;
    PORT
      LAYER M4 ;
        RECT  0 49.692 0.192 49.716 ;
    END
  END rsp_data[469]
  PIN rsp_data[470]
    DIRECTION INPUT ;
    USE SIGNAL ;
    PORT
      LAYER M4 ;
        RECT  0 49.932 0.192 49.956 ;
    END
  END rsp_data[470]
  PIN rsp_data[471]
    DIRECTION INPUT ;
    USE SIGNAL ;
    PORT
      LAYER M4 ;
        RECT  0 50.124 0.192 50.148 ;
    END
  END rsp_data[471]
  PIN rsp_data[472]
    DIRECTION INPUT ;
    USE SIGNAL ;
    PORT
      LAYER M4 ;
        RECT  0 50.364 0.192 50.388 ;
    END
  END rsp_data[472]
  PIN rsp_data[473]
    DIRECTION INPUT ;
    USE SIGNAL ;
    PORT
      LAYER M4 ;
        RECT  0 50.556 0.192 50.58 ;
    END
  END rsp_data[473]
  PIN rsp_data[474]
    DIRECTION INPUT ;
    USE SIGNAL ;
    PORT
      LAYER M4 ;
        RECT  0 50.796 0.192 50.82 ;
    END
  END rsp_data[474]
  PIN rsp_data[475]
    DIRECTION INPUT ;
    USE SIGNAL ;
    PORT
      LAYER M4 ;
        RECT  0 51.036 0.192 51.06 ;
    END
  END rsp_data[475]
  PIN rsp_data[476]
    DIRECTION INPUT ;
    USE SIGNAL ;
    PORT
      LAYER M4 ;
        RECT  0 51.228 0.192 51.252 ;
    END
  END rsp_data[476]
  PIN rsp_data[477]
    DIRECTION INPUT ;
    USE SIGNAL ;
    PORT
      LAYER M4 ;
        RECT  0 51.468 0.192 51.492 ;
    END
  END rsp_data[477]
  PIN rsp_data[478]
    DIRECTION INPUT ;
    USE SIGNAL ;
    PORT
      LAYER M4 ;
        RECT  0 51.66 0.192 51.684 ;
    END
  END rsp_data[478]
  PIN rsp_data[479]
    DIRECTION INPUT ;
    USE SIGNAL ;
    PORT
      LAYER M4 ;
        RECT  0 51.9 0.192 51.924 ;
    END
  END rsp_data[479]
  PIN rsp_data[480]
    DIRECTION INPUT ;
    USE SIGNAL ;
    PORT
      LAYER M4 ;
        RECT  0 52.092 0.192 52.116 ;
    END
  END rsp_data[480]
  PIN rsp_data[481]
    DIRECTION INPUT ;
    USE SIGNAL ;
    PORT
      LAYER M4 ;
        RECT  0 52.332 0.192 52.356 ;
    END
  END rsp_data[481]
  PIN rsp_data[482]
    DIRECTION INPUT ;
    USE SIGNAL ;
    PORT
      LAYER M4 ;
        RECT  0 52.524 0.192 52.548 ;
    END
  END rsp_data[482]
  PIN rsp_data[483]
    DIRECTION INPUT ;
    USE SIGNAL ;
    PORT
      LAYER M4 ;
        RECT  0 52.764 0.192 52.788 ;
    END
  END rsp_data[483]
  PIN rsp_data[484]
    DIRECTION INPUT ;
    USE SIGNAL ;
    PORT
      LAYER M4 ;
        RECT  0 52.956 0.192 52.98 ;
    END
  END rsp_data[484]
  PIN rsp_data[485]
    DIRECTION INPUT ;
    USE SIGNAL ;
    PORT
      LAYER M4 ;
        RECT  0 53.196 0.192 53.22 ;
    END
  END rsp_data[485]
  PIN rsp_data[486]
    DIRECTION INPUT ;
    USE SIGNAL ;
    PORT
      LAYER M4 ;
        RECT  0 53.436 0.192 53.46 ;
    END
  END rsp_data[486]
  PIN rsp_data[487]
    DIRECTION INPUT ;
    USE SIGNAL ;
    PORT
      LAYER M4 ;
        RECT  0 53.628 0.192 53.652 ;
    END
  END rsp_data[487]
  PIN rsp_data[488]
    DIRECTION INPUT ;
    USE SIGNAL ;
    PORT
      LAYER M4 ;
        RECT  0 53.868 0.192 53.892 ;
    END
  END rsp_data[488]
  PIN rsp_data[489]
    DIRECTION INPUT ;
    USE SIGNAL ;
    PORT
      LAYER M4 ;
        RECT  0 54.06 0.192 54.084 ;
    END
  END rsp_data[489]
  PIN rsp_data[490]
    DIRECTION INPUT ;
    USE SIGNAL ;
    PORT
      LAYER M4 ;
        RECT  0 54.3 0.192 54.324 ;
    END
  END rsp_data[490]
  PIN rsp_data[491]
    DIRECTION INPUT ;
    USE SIGNAL ;
    PORT
      LAYER M4 ;
        RECT  0 54.492 0.192 54.516 ;
    END
  END rsp_data[491]
  PIN rsp_data[492]
    DIRECTION INPUT ;
    USE SIGNAL ;
    PORT
      LAYER M4 ;
        RECT  0 54.732 0.192 54.756 ;
    END
  END rsp_data[492]
  PIN rsp_data[493]
    DIRECTION INPUT ;
    USE SIGNAL ;
    PORT
      LAYER M4 ;
        RECT  0 54.924 0.192 54.948 ;
    END
  END rsp_data[493]
  PIN rsp_data[494]
    DIRECTION INPUT ;
    USE SIGNAL ;
    PORT
      LAYER M4 ;
        RECT  0 55.164 0.192 55.188 ;
    END
  END rsp_data[494]
  PIN rsp_data[495]
    DIRECTION INPUT ;
    USE SIGNAL ;
    PORT
      LAYER M4 ;
        RECT  0 55.356 0.192 55.38 ;
    END
  END rsp_data[495]
  PIN rsp_data[496]
    DIRECTION INPUT ;
    USE SIGNAL ;
    PORT
      LAYER M4 ;
        RECT  0 55.596 0.192 55.62 ;
    END
  END rsp_data[496]
  PIN rsp_data[497]
    DIRECTION INPUT ;
    USE SIGNAL ;
    PORT
      LAYER M4 ;
        RECT  0 55.836 0.192 55.86 ;
    END
  END rsp_data[497]
  PIN rsp_data[498]
    DIRECTION INPUT ;
    USE SIGNAL ;
    PORT
      LAYER M4 ;
        RECT  0 56.028 0.192 56.052 ;
    END
  END rsp_data[498]
  PIN rsp_data[499]
    DIRECTION INPUT ;
    USE SIGNAL ;
    PORT
      LAYER M4 ;
        RECT  0 56.268 0.192 56.292 ;
    END
  END rsp_data[499]
  PIN rsp_data[500]
    DIRECTION INPUT ;
    USE SIGNAL ;
    PORT
      LAYER M4 ;
        RECT  0 56.46 0.192 56.484 ;
    END
  END rsp_data[500]
  PIN rsp_data[501]
    DIRECTION INPUT ;
    USE SIGNAL ;
    PORT
      LAYER M4 ;
        RECT  0 56.7 0.192 56.724 ;
    END
  END rsp_data[501]
  PIN rsp_data[502]
    DIRECTION INPUT ;
    USE SIGNAL ;
    PORT
      LAYER M4 ;
        RECT  0 56.892 0.192 56.916 ;
    END
  END rsp_data[502]
  PIN rsp_data[503]
    DIRECTION INPUT ;
    USE SIGNAL ;
    PORT
      LAYER M4 ;
        RECT  0 57.132 0.192 57.156 ;
    END
  END rsp_data[503]
  PIN rsp_data[504]
    DIRECTION INPUT ;
    USE SIGNAL ;
    PORT
      LAYER M4 ;
        RECT  0 57.324 0.192 57.348 ;
    END
  END rsp_data[504]
  PIN rsp_data[505]
    DIRECTION INPUT ;
    USE SIGNAL ;
    PORT
      LAYER M4 ;
        RECT  0 57.564 0.192 57.588 ;
    END
  END rsp_data[505]
  PIN rsp_data[506]
    DIRECTION INPUT ;
    USE SIGNAL ;
    PORT
      LAYER M4 ;
        RECT  0 57.804 0.192 57.828 ;
    END
  END rsp_data[506]
  PIN rsp_data[507]
    DIRECTION INPUT ;
    USE SIGNAL ;
    PORT
      LAYER M4 ;
        RECT  0 57.996 0.192 58.02 ;
    END
  END rsp_data[507]
  PIN rsp_data[508]
    DIRECTION INPUT ;
    USE SIGNAL ;
    PORT
      LAYER M4 ;
        RECT  0 58.236 0.192 58.26 ;
    END
  END rsp_data[508]
  PIN rsp_data[509]
    DIRECTION INPUT ;
    USE SIGNAL ;
    PORT
      LAYER M4 ;
        RECT  0 58.428 0.192 58.452 ;
    END
  END rsp_data[509]
  PIN rsp_data[510]
    DIRECTION INPUT ;
    USE SIGNAL ;
    PORT
      LAYER M4 ;
        RECT  0 58.668 0.192 58.692 ;
    END
  END rsp_data[510]
  PIN rsp_data[511]
    DIRECTION INPUT ;
    USE SIGNAL ;
    PORT
      LAYER M4 ;
        RECT  0 58.86 0.192 58.884 ;
    END
  END rsp_data[511]
  PIN rsp_data[512]
    DIRECTION INPUT ;
    USE SIGNAL ;
    PORT
      LAYER M4 ;
        RECT  0 59.1 0.192 59.124 ;
    END
  END rsp_data[512]
  PIN rsp_data[513]
    DIRECTION INPUT ;
    USE SIGNAL ;
    PORT
      LAYER M4 ;
        RECT  0 59.292 0.192 59.316 ;
    END
  END rsp_data[513]
  PIN rsp_data[514]
    DIRECTION INPUT ;
    USE SIGNAL ;
    PORT
      LAYER M4 ;
        RECT  0 59.532 0.192 59.556 ;
    END
  END rsp_data[514]
  PIN rsp_data[515]
    DIRECTION INPUT ;
    USE SIGNAL ;
    PORT
      LAYER M4 ;
        RECT  0 59.724 0.192 59.748 ;
    END
  END rsp_data[515]
  PIN rsp_data[516]
    DIRECTION INPUT ;
    USE SIGNAL ;
    PORT
      LAYER M4 ;
        RECT  0 59.964 0.192 59.988 ;
    END
  END rsp_data[516]
  PIN rsp_data[517]
    DIRECTION INPUT ;
    USE SIGNAL ;
    PORT
      LAYER M4 ;
        RECT  0 60.204 0.192 60.228 ;
    END
  END rsp_data[517]
  PIN rsp_data[518]
    DIRECTION INPUT ;
    USE SIGNAL ;
    PORT
      LAYER M4 ;
        RECT  0 60.396 0.192 60.42 ;
    END
  END rsp_data[518]
  PIN rsp_data[519]
    DIRECTION INPUT ;
    USE SIGNAL ;
    PORT
      LAYER M4 ;
        RECT  0 60.636 0.192 60.66 ;
    END
  END rsp_data[519]
  PIN rsp_data[520]
    DIRECTION INPUT ;
    USE SIGNAL ;
    PORT
      LAYER M4 ;
        RECT  0 60.828 0.192 60.852 ;
    END
  END rsp_data[520]
  PIN rsp_data[521]
    DIRECTION INPUT ;
    USE SIGNAL ;
    PORT
      LAYER M4 ;
        RECT  0 61.068 0.192 61.092 ;
    END
  END rsp_data[521]
  PIN rsp_data[522]
    DIRECTION INPUT ;
    USE SIGNAL ;
    PORT
      LAYER M4 ;
        RECT  0 61.26 0.192 61.284 ;
    END
  END rsp_data[522]
  PIN rsp_data[523]
    DIRECTION INPUT ;
    USE SIGNAL ;
    PORT
      LAYER M4 ;
        RECT  0 61.5 0.192 61.524 ;
    END
  END rsp_data[523]
  PIN rsp_data[524]
    DIRECTION INPUT ;
    USE SIGNAL ;
    PORT
      LAYER M4 ;
        RECT  0 61.692 0.192 61.716 ;
    END
  END rsp_data[524]
  PIN rsp_data[525]
    DIRECTION INPUT ;
    USE SIGNAL ;
    PORT
      LAYER M4 ;
        RECT  0 61.932 0.192 61.956 ;
    END
  END rsp_data[525]
  PIN rsp_data[526]
    DIRECTION INPUT ;
    USE SIGNAL ;
    PORT
      LAYER M4 ;
        RECT  0 62.172 0.192 62.196 ;
    END
  END rsp_data[526]
  PIN rsp_data[527]
    DIRECTION INPUT ;
    USE SIGNAL ;
    PORT
      LAYER M4 ;
        RECT  0 62.364 0.192 62.388 ;
    END
  END rsp_data[527]
  PIN rsp_data[528]
    DIRECTION INPUT ;
    USE SIGNAL ;
    PORT
      LAYER M4 ;
        RECT  0 62.604 0.192 62.628 ;
    END
  END rsp_data[528]
  PIN rsp_data[529]
    DIRECTION INPUT ;
    USE SIGNAL ;
    PORT
      LAYER M4 ;
        RECT  0 62.796 0.192 62.82 ;
    END
  END rsp_data[529]
  PIN rsp_data[530]
    DIRECTION INPUT ;
    USE SIGNAL ;
    PORT
      LAYER M4 ;
        RECT  0 63.036 0.192 63.06 ;
    END
  END rsp_data[530]
  PIN rsp_data[531]
    DIRECTION INPUT ;
    USE SIGNAL ;
    PORT
      LAYER M4 ;
        RECT  0 63.228 0.192 63.252 ;
    END
  END rsp_data[531]
  PIN rsp_data[532]
    DIRECTION INPUT ;
    USE SIGNAL ;
    PORT
      LAYER M4 ;
        RECT  0 63.468 0.192 63.492 ;
    END
  END rsp_data[532]
  PIN rsp_data[533]
    DIRECTION INPUT ;
    USE SIGNAL ;
    PORT
      LAYER M4 ;
        RECT  0 63.66 0.192 63.684 ;
    END
  END rsp_data[533]
  PIN rsp_data[534]
    DIRECTION INPUT ;
    USE SIGNAL ;
    PORT
      LAYER M4 ;
        RECT  0 63.9 0.192 63.924 ;
    END
  END rsp_data[534]
  PIN rsp_data[535]
    DIRECTION INPUT ;
    USE SIGNAL ;
    PORT
      LAYER M4 ;
        RECT  0 64.092 0.192 64.116 ;
    END
  END rsp_data[535]
  PIN rsp_data[536]
    DIRECTION INPUT ;
    USE SIGNAL ;
    PORT
      LAYER M4 ;
        RECT  0 64.332 0.192 64.356 ;
    END
  END rsp_data[536]
  PIN rsp_data[537]
    DIRECTION INPUT ;
    USE SIGNAL ;
    PORT
      LAYER M4 ;
        RECT  0 64.572 0.192 64.596 ;
    END
  END rsp_data[537]
  PIN rsp_data[538]
    DIRECTION INPUT ;
    USE SIGNAL ;
    PORT
      LAYER M4 ;
        RECT  0 64.764 0.192 64.788 ;
    END
  END rsp_data[538]
  PIN rsp_data[539]
    DIRECTION INPUT ;
    USE SIGNAL ;
    PORT
      LAYER M4 ;
        RECT  0 65.004 0.192 65.028 ;
    END
  END rsp_data[539]
  PIN rsp_data[540]
    DIRECTION INPUT ;
    USE SIGNAL ;
    PORT
      LAYER M4 ;
        RECT  0 65.196 0.192 65.22 ;
    END
  END rsp_data[540]
  PIN rsp_data[541]
    DIRECTION INPUT ;
    USE SIGNAL ;
    PORT
      LAYER M4 ;
        RECT  0 65.436 0.192 65.46 ;
    END
  END rsp_data[541]
  PIN rsp_data[542]
    DIRECTION INPUT ;
    USE SIGNAL ;
    PORT
      LAYER M4 ;
        RECT  0 65.628 0.192 65.652 ;
    END
  END rsp_data[542]
  PIN rsp_data[543]
    DIRECTION INPUT ;
    USE SIGNAL ;
    PORT
      LAYER M4 ;
        RECT  0 65.868 0.192 65.892 ;
    END
  END rsp_data[543]
  PIN rsp_data[544]
    DIRECTION INPUT ;
    USE SIGNAL ;
    PORT
      LAYER M4 ;
        RECT  0 66.06 0.192 66.084 ;
    END
  END rsp_data[544]
  PIN rsp_data[545]
    DIRECTION INPUT ;
    USE SIGNAL ;
    PORT
      LAYER M4 ;
        RECT  0 66.3 0.192 66.324 ;
    END
  END rsp_data[545]
  PIN rsp_data[546]
    DIRECTION INPUT ;
    USE SIGNAL ;
    PORT
      LAYER M4 ;
        RECT  0 66.54 0.192 66.564 ;
    END
  END rsp_data[546]
  PIN rsp_data[547]
    DIRECTION INPUT ;
    USE SIGNAL ;
    PORT
      LAYER M4 ;
        RECT  0 66.732 0.192 66.756 ;
    END
  END rsp_data[547]
  PIN rsp_data[548]
    DIRECTION INPUT ;
    USE SIGNAL ;
    PORT
      LAYER M4 ;
        RECT  0 66.972 0.192 66.996 ;
    END
  END rsp_data[548]
  PIN rsp_data[549]
    DIRECTION INPUT ;
    USE SIGNAL ;
    PORT
      LAYER M4 ;
        RECT  0 67.164 0.192 67.188 ;
    END
  END rsp_data[549]
  PIN rsp_data[550]
    DIRECTION INPUT ;
    USE SIGNAL ;
    PORT
      LAYER M4 ;
        RECT  0 67.404 0.192 67.428 ;
    END
  END rsp_data[550]
  PIN rsp_data[551]
    DIRECTION INPUT ;
    USE SIGNAL ;
    PORT
      LAYER M4 ;
        RECT  0 67.596 0.192 67.62 ;
    END
  END rsp_data[551]
  PIN rsp_data[552]
    DIRECTION INPUT ;
    USE SIGNAL ;
    PORT
      LAYER M4 ;
        RECT  0 67.836 0.192 67.86 ;
    END
  END rsp_data[552]
  PIN rsp_data[553]
    DIRECTION INPUT ;
    USE SIGNAL ;
    PORT
      LAYER M4 ;
        RECT  0 68.028 0.192 68.052 ;
    END
  END rsp_data[553]
  PIN rsp_data[554]
    DIRECTION INPUT ;
    USE SIGNAL ;
    PORT
      LAYER M4 ;
        RECT  0 68.268 0.192 68.292 ;
    END
  END rsp_data[554]
  PIN rsp_data[555]
    DIRECTION INPUT ;
    USE SIGNAL ;
    PORT
      LAYER M4 ;
        RECT  0 68.46 0.192 68.484 ;
    END
  END rsp_data[555]
  PIN rsp_data[556]
    DIRECTION INPUT ;
    USE SIGNAL ;
    PORT
      LAYER M4 ;
        RECT  0 68.7 0.192 68.724 ;
    END
  END rsp_data[556]
  PIN rsp_data[557]
    DIRECTION INPUT ;
    USE SIGNAL ;
    PORT
      LAYER M4 ;
        RECT  0 68.94 0.192 68.964 ;
    END
  END rsp_data[557]
  PIN rsp_data[558]
    DIRECTION INPUT ;
    USE SIGNAL ;
    PORT
      LAYER M4 ;
        RECT  0 69.132 0.192 69.156 ;
    END
  END rsp_data[558]
  PIN rsp_data[559]
    DIRECTION INPUT ;
    USE SIGNAL ;
    PORT
      LAYER M4 ;
        RECT  0 69.372 0.192 69.396 ;
    END
  END rsp_data[559]
  PIN rsp_data[560]
    DIRECTION INPUT ;
    USE SIGNAL ;
    PORT
      LAYER M4 ;
        RECT  0 69.564 0.192 69.588 ;
    END
  END rsp_data[560]
  PIN rsp_data[561]
    DIRECTION INPUT ;
    USE SIGNAL ;
    PORT
      LAYER M4 ;
        RECT  0 69.804 0.192 69.828 ;
    END
  END rsp_data[561]
  PIN rsp_data[562]
    DIRECTION INPUT ;
    USE SIGNAL ;
    PORT
      LAYER M4 ;
        RECT  0 69.996 0.192 70.02 ;
    END
  END rsp_data[562]
  PIN rsp_data[563]
    DIRECTION INPUT ;
    USE SIGNAL ;
    PORT
      LAYER M4 ;
        RECT  0 70.236 0.192 70.26 ;
    END
  END rsp_data[563]
  PIN rsp_data[564]
    DIRECTION INPUT ;
    USE SIGNAL ;
    PORT
      LAYER M4 ;
        RECT  0 70.428 0.192 70.452 ;
    END
  END rsp_data[564]
  PIN rsp_data[565]
    DIRECTION INPUT ;
    USE SIGNAL ;
    PORT
      LAYER M4 ;
        RECT  0 70.668 0.192 70.692 ;
    END
  END rsp_data[565]
  PIN rsp_data[566]
    DIRECTION INPUT ;
    USE SIGNAL ;
    PORT
      LAYER M4 ;
        RECT  0 70.86 0.192 70.884 ;
    END
  END rsp_data[566]
  PIN rsp_data[567]
    DIRECTION INPUT ;
    USE SIGNAL ;
    PORT
      LAYER M4 ;
        RECT  0 71.1 0.192 71.124 ;
    END
  END rsp_data[567]
  PIN rsp_data[568]
    DIRECTION INPUT ;
    USE SIGNAL ;
    PORT
      LAYER M4 ;
        RECT  0 71.34 0.192 71.364 ;
    END
  END rsp_data[568]
  PIN rsp_data[569]
    DIRECTION INPUT ;
    USE SIGNAL ;
    PORT
      LAYER M4 ;
        RECT  0 71.532 0.192 71.556 ;
    END
  END rsp_data[569]
  PIN rsp_data[570]
    DIRECTION INPUT ;
    USE SIGNAL ;
    PORT
      LAYER M4 ;
        RECT  0 71.772 0.192 71.796 ;
    END
  END rsp_data[570]
  PIN rsp_data[571]
    DIRECTION INPUT ;
    USE SIGNAL ;
    PORT
      LAYER M4 ;
        RECT  0 71.964 0.192 71.988 ;
    END
  END rsp_data[571]
  PIN rsp_data[572]
    DIRECTION INPUT ;
    USE SIGNAL ;
    PORT
      LAYER M4 ;
        RECT  0 72.204 0.192 72.228 ;
    END
  END rsp_data[572]
  PIN rsp_data[573]
    DIRECTION INPUT ;
    USE SIGNAL ;
    PORT
      LAYER M4 ;
        RECT  0 72.396 0.192 72.42 ;
    END
  END rsp_data[573]
  PIN rsp_data[574]
    DIRECTION INPUT ;
    USE SIGNAL ;
    PORT
      LAYER M4 ;
        RECT  0 72.636 0.192 72.66 ;
    END
  END rsp_data[574]
  PIN rsp_data[575]
    DIRECTION INPUT ;
    USE SIGNAL ;
    PORT
      LAYER M4 ;
        RECT  0 72.828 0.192 72.852 ;
    END
  END rsp_data[575]
  PIN rsp_data[576]
    DIRECTION INPUT ;
    USE SIGNAL ;
    PORT
      LAYER M4 ;
        RECT  0 73.068 0.192 73.092 ;
    END
  END rsp_data[576]
  PIN rsp_data[577]
    DIRECTION INPUT ;
    USE SIGNAL ;
    PORT
      LAYER M4 ;
        RECT  0 73.308 0.192 73.332 ;
    END
  END rsp_data[577]
  PIN rsp_data[578]
    DIRECTION INPUT ;
    USE SIGNAL ;
    PORT
      LAYER M4 ;
        RECT  0 73.5 0.192 73.524 ;
    END
  END rsp_data[578]
  PIN rsp_data[579]
    DIRECTION INPUT ;
    USE SIGNAL ;
    PORT
      LAYER M4 ;
        RECT  0 73.74 0.192 73.764 ;
    END
  END rsp_data[579]
  PIN rsp_data[580]
    DIRECTION INPUT ;
    USE SIGNAL ;
    PORT
      LAYER M4 ;
        RECT  0 73.932 0.192 73.956 ;
    END
  END rsp_data[580]
  PIN rsp_data[581]
    DIRECTION INPUT ;
    USE SIGNAL ;
    PORT
      LAYER M4 ;
        RECT  0 74.172 0.192 74.196 ;
    END
  END rsp_data[581]
  PIN rsp_data[582]
    DIRECTION INPUT ;
    USE SIGNAL ;
    PORT
      LAYER M4 ;
        RECT  0 74.364 0.192 74.388 ;
    END
  END rsp_data[582]
  PIN rsp_data[583]
    DIRECTION INPUT ;
    USE SIGNAL ;
    PORT
      LAYER M4 ;
        RECT  0 74.604 0.192 74.628 ;
    END
  END rsp_data[583]
  PIN rsp_data[584]
    DIRECTION INPUT ;
    USE SIGNAL ;
    PORT
      LAYER M4 ;
        RECT  0 74.796 0.192 74.82 ;
    END
  END rsp_data[584]
  PIN rsp_data[585]
    DIRECTION INPUT ;
    USE SIGNAL ;
    PORT
      LAYER M4 ;
        RECT  0 75.036 0.192 75.06 ;
    END
  END rsp_data[585]
  PIN rsp_data[586]
    DIRECTION INPUT ;
    USE SIGNAL ;
    PORT
      LAYER M4 ;
        RECT  0 75.228 0.192 75.252 ;
    END
  END rsp_data[586]
  PIN rsp_data[587]
    DIRECTION INPUT ;
    USE SIGNAL ;
    PORT
      LAYER M4 ;
        RECT  0 75.468 0.192 75.492 ;
    END
  END rsp_data[587]
  PIN rsp_data[588]
    DIRECTION INPUT ;
    USE SIGNAL ;
    PORT
      LAYER M4 ;
        RECT  0 75.708 0.192 75.732 ;
    END
  END rsp_data[588]
  PIN rsp_data[589]
    DIRECTION INPUT ;
    USE SIGNAL ;
    PORT
      LAYER M4 ;
        RECT  0 75.9 0.192 75.924 ;
    END
  END rsp_data[589]
  PIN rsp_data[590]
    DIRECTION INPUT ;
    USE SIGNAL ;
    PORT
      LAYER M4 ;
        RECT  0 76.14 0.192 76.164 ;
    END
  END rsp_data[590]
  PIN rsp_data[591]
    DIRECTION INPUT ;
    USE SIGNAL ;
    PORT
      LAYER M4 ;
        RECT  0 76.332 0.192 76.356 ;
    END
  END rsp_data[591]
  PIN rsp_data[592]
    DIRECTION INPUT ;
    USE SIGNAL ;
    PORT
      LAYER M4 ;
        RECT  0 76.572 0.192 76.596 ;
    END
  END rsp_data[592]
  PIN rsp_data[593]
    DIRECTION INPUT ;
    USE SIGNAL ;
    PORT
      LAYER M4 ;
        RECT  0 76.764 0.192 76.788 ;
    END
  END rsp_data[593]
  PIN rsp_data[594]
    DIRECTION INPUT ;
    USE SIGNAL ;
    PORT
      LAYER M4 ;
        RECT  0 77.004 0.192 77.028 ;
    END
  END rsp_data[594]
  PIN rsp_data[595]
    DIRECTION INPUT ;
    USE SIGNAL ;
    PORT
      LAYER M4 ;
        RECT  0 77.196 0.192 77.22 ;
    END
  END rsp_data[595]
  PIN rsp_data[596]
    DIRECTION INPUT ;
    USE SIGNAL ;
    PORT
      LAYER M4 ;
        RECT  0 77.436 0.192 77.46 ;
    END
  END rsp_data[596]
  PIN rsp_data[597]
    DIRECTION INPUT ;
    USE SIGNAL ;
    PORT
      LAYER M4 ;
        RECT  0 77.676 0.192 77.7 ;
    END
  END rsp_data[597]
  PIN rsp_data[598]
    DIRECTION INPUT ;
    USE SIGNAL ;
    PORT
      LAYER M4 ;
        RECT  0 77.868 0.192 77.892 ;
    END
  END rsp_data[598]
  PIN rsp_data[599]
    DIRECTION INPUT ;
    USE SIGNAL ;
    PORT
      LAYER M4 ;
        RECT  0 78.108 0.192 78.132 ;
    END
  END rsp_data[599]
  PIN rsp_data[600]
    DIRECTION INPUT ;
    USE SIGNAL ;
    PORT
      LAYER M4 ;
        RECT  0 78.3 0.192 78.324 ;
    END
  END rsp_data[600]
  PIN rsp_data[601]
    DIRECTION INPUT ;
    USE SIGNAL ;
    PORT
      LAYER M4 ;
        RECT  0 78.54 0.192 78.564 ;
    END
  END rsp_data[601]
  PIN rsp_data[602]
    DIRECTION INPUT ;
    USE SIGNAL ;
    PORT
      LAYER M4 ;
        RECT  0 78.732 0.192 78.756 ;
    END
  END rsp_data[602]
  PIN rsp_data[603]
    DIRECTION INPUT ;
    USE SIGNAL ;
    PORT
      LAYER M4 ;
        RECT  0 78.972 0.192 78.996 ;
    END
  END rsp_data[603]
  PIN rsp_data[604]
    DIRECTION INPUT ;
    USE SIGNAL ;
    PORT
      LAYER M4 ;
        RECT  0 79.164 0.192 79.188 ;
    END
  END rsp_data[604]
  PIN rsp_data[605]
    DIRECTION INPUT ;
    USE SIGNAL ;
    PORT
      LAYER M4 ;
        RECT  0 79.404 0.192 79.428 ;
    END
  END rsp_data[605]
  PIN rsp_data[606]
    DIRECTION INPUT ;
    USE SIGNAL ;
    PORT
      LAYER M4 ;
        RECT  0 79.596 0.192 79.62 ;
    END
  END rsp_data[606]
  PIN rsp_data[607]
    DIRECTION INPUT ;
    USE SIGNAL ;
    PORT
      LAYER M4 ;
        RECT  0 79.836 0.192 79.86 ;
    END
  END rsp_data[607]
  PIN rsp_data[608]
    DIRECTION INPUT ;
    USE SIGNAL ;
    PORT
      LAYER M4 ;
        RECT  0 80.076 0.192 80.1 ;
    END
  END rsp_data[608]
  PIN rsp_data[609]
    DIRECTION INPUT ;
    USE SIGNAL ;
    PORT
      LAYER M4 ;
        RECT  0 80.268 0.192 80.292 ;
    END
  END rsp_data[609]
  PIN rsp_data[610]
    DIRECTION INPUT ;
    USE SIGNAL ;
    PORT
      LAYER M4 ;
        RECT  0 80.508 0.192 80.532 ;
    END
  END rsp_data[610]
  PIN rsp_data[611]
    DIRECTION INPUT ;
    USE SIGNAL ;
    PORT
      LAYER M4 ;
        RECT  0 80.7 0.192 80.724 ;
    END
  END rsp_data[611]
  PIN rsp_data[612]
    DIRECTION INPUT ;
    USE SIGNAL ;
    PORT
      LAYER M4 ;
        RECT  0 80.94 0.192 80.964 ;
    END
  END rsp_data[612]
  PIN rsp_data[613]
    DIRECTION INPUT ;
    USE SIGNAL ;
    PORT
      LAYER M4 ;
        RECT  0 81.132 0.192 81.156 ;
    END
  END rsp_data[613]
  PIN rsp_data[614]
    DIRECTION INPUT ;
    USE SIGNAL ;
    PORT
      LAYER M4 ;
        RECT  0 81.372 0.192 81.396 ;
    END
  END rsp_data[614]
  PIN rsp_data[615]
    DIRECTION INPUT ;
    USE SIGNAL ;
    PORT
      LAYER M4 ;
        RECT  0 81.564 0.192 81.588 ;
    END
  END rsp_data[615]
  PIN rsp_data[616]
    DIRECTION INPUT ;
    USE SIGNAL ;
    PORT
      LAYER M4 ;
        RECT  0 81.804 0.192 81.828 ;
    END
  END rsp_data[616]
  PIN rsp_data[617]
    DIRECTION INPUT ;
    USE SIGNAL ;
    PORT
      LAYER M4 ;
        RECT  0 82.044 0.192 82.068 ;
    END
  END rsp_data[617]
  PIN rsp_data[618]
    DIRECTION INPUT ;
    USE SIGNAL ;
    PORT
      LAYER M4 ;
        RECT  0 82.236 0.192 82.26 ;
    END
  END rsp_data[618]
  PIN rsp_data[619]
    DIRECTION INPUT ;
    USE SIGNAL ;
    PORT
      LAYER M4 ;
        RECT  0 82.476 0.192 82.5 ;
    END
  END rsp_data[619]
  PIN rsp_data[620]
    DIRECTION INPUT ;
    USE SIGNAL ;
    PORT
      LAYER M4 ;
        RECT  0 82.668 0.192 82.692 ;
    END
  END rsp_data[620]
  PIN rsp_data[621]
    DIRECTION INPUT ;
    USE SIGNAL ;
    PORT
      LAYER M4 ;
        RECT  0 82.908 0.192 82.932 ;
    END
  END rsp_data[621]
  PIN rsp_data[622]
    DIRECTION INPUT ;
    USE SIGNAL ;
    PORT
      LAYER M4 ;
        RECT  0 83.1 0.192 83.124 ;
    END
  END rsp_data[622]
  PIN rsp_data[623]
    DIRECTION INPUT ;
    USE SIGNAL ;
    PORT
      LAYER M4 ;
        RECT  0 83.34 0.192 83.364 ;
    END
  END rsp_data[623]
  PIN rsp_data[624]
    DIRECTION INPUT ;
    USE SIGNAL ;
    PORT
      LAYER M4 ;
        RECT  0 83.532 0.192 83.556 ;
    END
  END rsp_data[624]
  PIN rsp_data[625]
    DIRECTION INPUT ;
    USE SIGNAL ;
    PORT
      LAYER M4 ;
        RECT  0 83.772 0.192 83.796 ;
    END
  END rsp_data[625]
  PIN rsp_data[626]
    DIRECTION INPUT ;
    USE SIGNAL ;
    PORT
      LAYER M4 ;
        RECT  0 83.964 0.192 83.988 ;
    END
  END rsp_data[626]
  PIN rsp_data[627]
    DIRECTION INPUT ;
    USE SIGNAL ;
    PORT
      LAYER M4 ;
        RECT  0 84.204 0.192 84.228 ;
    END
  END rsp_data[627]
  PIN rsp_data[628]
    DIRECTION INPUT ;
    USE SIGNAL ;
    PORT
      LAYER M4 ;
        RECT  0 84.444 0.192 84.468 ;
    END
  END rsp_data[628]
  PIN rsp_data[629]
    DIRECTION INPUT ;
    USE SIGNAL ;
    PORT
      LAYER M4 ;
        RECT  0 84.636 0.192 84.66 ;
    END
  END rsp_data[629]
  PIN rsp_data[630]
    DIRECTION INPUT ;
    USE SIGNAL ;
    PORT
      LAYER M4 ;
        RECT  0 84.876 0.192 84.9 ;
    END
  END rsp_data[630]
  PIN rsp_data[631]
    DIRECTION INPUT ;
    USE SIGNAL ;
    PORT
      LAYER M4 ;
        RECT  0 85.068 0.192 85.092 ;
    END
  END rsp_data[631]
  PIN rsp_data[632]
    DIRECTION INPUT ;
    USE SIGNAL ;
    PORT
      LAYER M4 ;
        RECT  0 85.308 0.192 85.332 ;
    END
  END rsp_data[632]
  PIN rsp_data[633]
    DIRECTION INPUT ;
    USE SIGNAL ;
    PORT
      LAYER M4 ;
        RECT  0 85.5 0.192 85.524 ;
    END
  END rsp_data[633]
  PIN rsp_data[634]
    DIRECTION INPUT ;
    USE SIGNAL ;
    PORT
      LAYER M4 ;
        RECT  0 85.74 0.192 85.764 ;
    END
  END rsp_data[634]
  PIN rsp_data[635]
    DIRECTION INPUT ;
    USE SIGNAL ;
    PORT
      LAYER M4 ;
        RECT  0 85.932 0.192 85.956 ;
    END
  END rsp_data[635]
  PIN rsp_data[636]
    DIRECTION INPUT ;
    USE SIGNAL ;
    PORT
      LAYER M4 ;
        RECT  0 86.172 0.192 86.196 ;
    END
  END rsp_data[636]
  PIN rsp_data[637]
    DIRECTION INPUT ;
    USE SIGNAL ;
    PORT
      LAYER M4 ;
        RECT  0 86.412 0.192 86.436 ;
    END
  END rsp_data[637]
  PIN rsp_data[638]
    DIRECTION INPUT ;
    USE SIGNAL ;
    PORT
      LAYER M4 ;
        RECT  0 86.604 0.192 86.628 ;
    END
  END rsp_data[638]
  PIN rsp_data[639]
    DIRECTION INPUT ;
    USE SIGNAL ;
    PORT
      LAYER M4 ;
        RECT  0 86.844 0.192 86.868 ;
    END
  END rsp_data[639]
  PIN rsp_data[640]
    DIRECTION INPUT ;
    USE SIGNAL ;
    PORT
      LAYER M4 ;
        RECT  0 87.036 0.192 87.06 ;
    END
  END rsp_data[640]
  PIN rsp_data[641]
    DIRECTION INPUT ;
    USE SIGNAL ;
    PORT
      LAYER M4 ;
        RECT  0 87.276 0.192 87.3 ;
    END
  END rsp_data[641]
  PIN rsp_data[642]
    DIRECTION INPUT ;
    USE SIGNAL ;
    PORT
      LAYER M4 ;
        RECT  0 87.468 0.192 87.492 ;
    END
  END rsp_data[642]
  PIN rsp_data[643]
    DIRECTION INPUT ;
    USE SIGNAL ;
    PORT
      LAYER M4 ;
        RECT  0 87.708 0.192 87.732 ;
    END
  END rsp_data[643]
  PIN rsp_data[644]
    DIRECTION INPUT ;
    USE SIGNAL ;
    PORT
      LAYER M4 ;
        RECT  0 87.9 0.192 87.924 ;
    END
  END rsp_data[644]
  PIN rsp_data[645]
    DIRECTION INPUT ;
    USE SIGNAL ;
    PORT
      LAYER M4 ;
        RECT  0 88.14 0.192 88.164 ;
    END
  END rsp_data[645]
  PIN rsp_data[646]
    DIRECTION INPUT ;
    USE SIGNAL ;
    PORT
      LAYER M4 ;
        RECT  0 88.332 0.192 88.356 ;
    END
  END rsp_data[646]
  PIN rsp_data[647]
    DIRECTION INPUT ;
    USE SIGNAL ;
    PORT
      LAYER M4 ;
        RECT  0 88.572 0.192 88.596 ;
    END
  END rsp_data[647]
  PIN rsp_data[648]
    DIRECTION INPUT ;
    USE SIGNAL ;
    PORT
      LAYER M4 ;
        RECT  0 88.812 0.192 88.836 ;
    END
  END rsp_data[648]
  PIN rsp_data[649]
    DIRECTION INPUT ;
    USE SIGNAL ;
    PORT
      LAYER M4 ;
        RECT  0 89.004 0.192 89.028 ;
    END
  END rsp_data[649]
  PIN rsp_data[650]
    DIRECTION INPUT ;
    USE SIGNAL ;
    PORT
      LAYER M4 ;
        RECT  0 89.244 0.192 89.268 ;
    END
  END rsp_data[650]
  PIN rsp_data[651]
    DIRECTION INPUT ;
    USE SIGNAL ;
    PORT
      LAYER M4 ;
        RECT  0 89.436 0.192 89.46 ;
    END
  END rsp_data[651]
  PIN rsp_data[652]
    DIRECTION INPUT ;
    USE SIGNAL ;
    PORT
      LAYER M4 ;
        RECT  0 89.676 0.192 89.7 ;
    END
  END rsp_data[652]
  PIN rsp_data[653]
    DIRECTION INPUT ;
    USE SIGNAL ;
    PORT
      LAYER M4 ;
        RECT  0 89.868 0.192 89.892 ;
    END
  END rsp_data[653]
  PIN rsp_data[654]
    DIRECTION INPUT ;
    USE SIGNAL ;
    PORT
      LAYER M4 ;
        RECT  0 90.108 0.192 90.132 ;
    END
  END rsp_data[654]
  PIN rsp_data[655]
    DIRECTION INPUT ;
    USE SIGNAL ;
    PORT
      LAYER M4 ;
        RECT  0 90.3 0.192 90.324 ;
    END
  END rsp_data[655]
  PIN rsp_data[656]
    DIRECTION INPUT ;
    USE SIGNAL ;
    PORT
      LAYER M4 ;
        RECT  0 90.54 0.192 90.564 ;
    END
  END rsp_data[656]
  PIN rsp_data[657]
    DIRECTION INPUT ;
    USE SIGNAL ;
    PORT
      LAYER M4 ;
        RECT  0 90.732 0.192 90.756 ;
    END
  END rsp_data[657]
  PIN rsp_data[658]
    DIRECTION INPUT ;
    USE SIGNAL ;
    PORT
      LAYER M4 ;
        RECT  0 90.972 0.192 90.996 ;
    END
  END rsp_data[658]
  PIN rsp_data[659]
    DIRECTION INPUT ;
    USE SIGNAL ;
    PORT
      LAYER M4 ;
        RECT  0 91.212 0.192 91.236 ;
    END
  END rsp_data[659]
  PIN rsp_data[660]
    DIRECTION INPUT ;
    USE SIGNAL ;
    PORT
      LAYER M4 ;
        RECT  0 91.404 0.192 91.428 ;
    END
  END rsp_data[660]
  PIN rsp_data[661]
    DIRECTION INPUT ;
    USE SIGNAL ;
    PORT
      LAYER M4 ;
        RECT  0 91.644 0.192 91.668 ;
    END
  END rsp_data[661]
  PIN rsp_data[662]
    DIRECTION INPUT ;
    USE SIGNAL ;
    PORT
      LAYER M4 ;
        RECT  0 91.836 0.192 91.86 ;
    END
  END rsp_data[662]
  PIN rsp_data[663]
    DIRECTION INPUT ;
    USE SIGNAL ;
    PORT
      LAYER M4 ;
        RECT  0 92.076 0.192 92.1 ;
    END
  END rsp_data[663]
  PIN rsp_data[664]
    DIRECTION INPUT ;
    USE SIGNAL ;
    PORT
      LAYER M4 ;
        RECT  0 92.268 0.192 92.292 ;
    END
  END rsp_data[664]
  PIN rsp_data[665]
    DIRECTION INPUT ;
    USE SIGNAL ;
    PORT
      LAYER M4 ;
        RECT  0 92.508 0.192 92.532 ;
    END
  END rsp_data[665]
  PIN rsp_data[666]
    DIRECTION INPUT ;
    USE SIGNAL ;
    PORT
      LAYER M4 ;
        RECT  0 92.7 0.192 92.724 ;
    END
  END rsp_data[666]
  PIN rsp_data[667]
    DIRECTION INPUT ;
    USE SIGNAL ;
    PORT
      LAYER M4 ;
        RECT  0 92.94 0.192 92.964 ;
    END
  END rsp_data[667]
  PIN rsp_data[668]
    DIRECTION INPUT ;
    USE SIGNAL ;
    PORT
      LAYER M4 ;
        RECT  0 93.18 0.192 93.204 ;
    END
  END rsp_data[668]
  PIN rsp_data[669]
    DIRECTION INPUT ;
    USE SIGNAL ;
    PORT
      LAYER M4 ;
        RECT  0 93.372 0.192 93.396 ;
    END
  END rsp_data[669]
  PIN rsp_data[670]
    DIRECTION INPUT ;
    USE SIGNAL ;
    PORT
      LAYER M4 ;
        RECT  0 93.612 0.192 93.636 ;
    END
  END rsp_data[670]
  PIN rsp_data[671]
    DIRECTION INPUT ;
    USE SIGNAL ;
    PORT
      LAYER M4 ;
        RECT  0 93.804 0.192 93.828 ;
    END
  END rsp_data[671]
  PIN rsp_data[672]
    DIRECTION INPUT ;
    USE SIGNAL ;
    PORT
      LAYER M4 ;
        RECT  0 94.044 0.192 94.068 ;
    END
  END rsp_data[672]
  PIN rsp_data[673]
    DIRECTION INPUT ;
    USE SIGNAL ;
    PORT
      LAYER M4 ;
        RECT  0 94.236 0.192 94.26 ;
    END
  END rsp_data[673]
  PIN rsp_data[674]
    DIRECTION INPUT ;
    USE SIGNAL ;
    PORT
      LAYER M4 ;
        RECT  0 94.476 0.192 94.5 ;
    END
  END rsp_data[674]
  PIN rsp_data[675]
    DIRECTION INPUT ;
    USE SIGNAL ;
    PORT
      LAYER M4 ;
        RECT  0 94.668 0.192 94.692 ;
    END
  END rsp_data[675]
  PIN rsp_data[676]
    DIRECTION INPUT ;
    USE SIGNAL ;
    PORT
      LAYER M4 ;
        RECT  0 94.908 0.192 94.932 ;
    END
  END rsp_data[676]
  PIN rsp_data[677]
    DIRECTION INPUT ;
    USE SIGNAL ;
    PORT
      LAYER M4 ;
        RECT  0 95.1 0.192 95.124 ;
    END
  END rsp_data[677]
  PIN rsp_data[678]
    DIRECTION INPUT ;
    USE SIGNAL ;
    PORT
      LAYER M4 ;
        RECT  0 95.34 0.192 95.364 ;
    END
  END rsp_data[678]
  PIN rsp_data[679]
    DIRECTION INPUT ;
    USE SIGNAL ;
    PORT
      LAYER M4 ;
        RECT  0 95.58 0.192 95.604 ;
    END
  END rsp_data[679]
  PIN rsp_data[680]
    DIRECTION INPUT ;
    USE SIGNAL ;
    PORT
      LAYER M4 ;
        RECT  0 95.772 0.192 95.796 ;
    END
  END rsp_data[680]
  PIN rsp_data[681]
    DIRECTION INPUT ;
    USE SIGNAL ;
    PORT
      LAYER M4 ;
        RECT  0 96.012 0.192 96.036 ;
    END
  END rsp_data[681]
  PIN rsp_data[682]
    DIRECTION INPUT ;
    USE SIGNAL ;
    PORT
      LAYER M4 ;
        RECT  0 96.204 0.192 96.228 ;
    END
  END rsp_data[682]
  PIN rsp_data[683]
    DIRECTION INPUT ;
    USE SIGNAL ;
    PORT
      LAYER M4 ;
        RECT  0 96.444 0.192 96.468 ;
    END
  END rsp_data[683]
  PIN rsp_data[684]
    DIRECTION INPUT ;
    USE SIGNAL ;
    PORT
      LAYER M4 ;
        RECT  0 96.636 0.192 96.66 ;
    END
  END rsp_data[684]
  PIN rsp_data[685]
    DIRECTION INPUT ;
    USE SIGNAL ;
    PORT
      LAYER M4 ;
        RECT  0 96.876 0.192 96.9 ;
    END
  END rsp_data[685]
  PIN rsp_data[686]
    DIRECTION INPUT ;
    USE SIGNAL ;
    PORT
      LAYER M4 ;
        RECT  0 97.068 0.192 97.092 ;
    END
  END rsp_data[686]
  PIN rsp_data[687]
    DIRECTION INPUT ;
    USE SIGNAL ;
    PORT
      LAYER M4 ;
        RECT  0 97.308 0.192 97.332 ;
    END
  END rsp_data[687]
  PIN rsp_data[688]
    DIRECTION INPUT ;
    USE SIGNAL ;
    PORT
      LAYER M4 ;
        RECT  0 97.548 0.192 97.572 ;
    END
  END rsp_data[688]
  PIN rsp_data[689]
    DIRECTION INPUT ;
    USE SIGNAL ;
    PORT
      LAYER M4 ;
        RECT  0 97.74 0.192 97.764 ;
    END
  END rsp_data[689]
  PIN rsp_data[690]
    DIRECTION INPUT ;
    USE SIGNAL ;
    PORT
      LAYER M4 ;
        RECT  0 97.98 0.192 98.004 ;
    END
  END rsp_data[690]
  PIN rsp_data[691]
    DIRECTION INPUT ;
    USE SIGNAL ;
    PORT
      LAYER M4 ;
        RECT  0 98.172 0.192 98.196 ;
    END
  END rsp_data[691]
  PIN rsp_data[692]
    DIRECTION INPUT ;
    USE SIGNAL ;
    PORT
      LAYER M4 ;
        RECT  0 98.412 0.192 98.436 ;
    END
  END rsp_data[692]
  PIN rsp_data[693]
    DIRECTION INPUT ;
    USE SIGNAL ;
    PORT
      LAYER M4 ;
        RECT  0 98.604 0.192 98.628 ;
    END
  END rsp_data[693]
  PIN rsp_data[694]
    DIRECTION INPUT ;
    USE SIGNAL ;
    PORT
      LAYER M4 ;
        RECT  0 98.844 0.192 98.868 ;
    END
  END rsp_data[694]
  PIN rsp_data[695]
    DIRECTION INPUT ;
    USE SIGNAL ;
    PORT
      LAYER M4 ;
        RECT  0 99.036 0.192 99.06 ;
    END
  END rsp_data[695]
  PIN rsp_data[696]
    DIRECTION INPUT ;
    USE SIGNAL ;
    PORT
      LAYER M4 ;
        RECT  0 99.276 0.192 99.3 ;
    END
  END rsp_data[696]
  PIN rsp_data[697]
    DIRECTION INPUT ;
    USE SIGNAL ;
    PORT
      LAYER M4 ;
        RECT  0 99.468 0.192 99.492 ;
    END
  END rsp_data[697]
  PIN rsp_data[698]
    DIRECTION INPUT ;
    USE SIGNAL ;
    PORT
      LAYER M4 ;
        RECT  0 99.708 0.192 99.732 ;
    END
  END rsp_data[698]
  PIN rsp_data[699]
    DIRECTION INPUT ;
    USE SIGNAL ;
    PORT
      LAYER M4 ;
        RECT  0 99.948 0.192 99.972 ;
    END
  END rsp_data[699]
  PIN rsp_data[700]
    DIRECTION INPUT ;
    USE SIGNAL ;
    PORT
      LAYER M4 ;
        RECT  0 100.14 0.192 100.164 ;
    END
  END rsp_data[700]
  PIN rsp_data[701]
    DIRECTION INPUT ;
    USE SIGNAL ;
    PORT
      LAYER M4 ;
        RECT  0 100.38 0.192 100.404 ;
    END
  END rsp_data[701]
  PIN rsp_data[702]
    DIRECTION INPUT ;
    USE SIGNAL ;
    PORT
      LAYER M4 ;
        RECT  0 100.572 0.192 100.596 ;
    END
  END rsp_data[702]
  PIN rsp_data[703]
    DIRECTION INPUT ;
    USE SIGNAL ;
    PORT
      LAYER M4 ;
        RECT  0 100.812 0.192 100.836 ;
    END
  END rsp_data[703]
  PIN rsp_data[704]
    DIRECTION INPUT ;
    USE SIGNAL ;
    PORT
      LAYER M4 ;
        RECT  0 101.004 0.192 101.028 ;
    END
  END rsp_data[704]
  PIN rsp_data[705]
    DIRECTION INPUT ;
    USE SIGNAL ;
    PORT
      LAYER M4 ;
        RECT  0 101.244 0.192 101.268 ;
    END
  END rsp_data[705]
  PIN rsp_data[706]
    DIRECTION INPUT ;
    USE SIGNAL ;
    PORT
      LAYER M4 ;
        RECT  0 101.436 0.192 101.46 ;
    END
  END rsp_data[706]
  PIN rsp_data[707]
    DIRECTION INPUT ;
    USE SIGNAL ;
    PORT
      LAYER M4 ;
        RECT  0 101.676 0.192 101.7 ;
    END
  END rsp_data[707]
  PIN rsp_data[708]
    DIRECTION INPUT ;
    USE SIGNAL ;
    PORT
      LAYER M4 ;
        RECT  0 101.916 0.192 101.94 ;
    END
  END rsp_data[708]
  PIN rsp_data[709]
    DIRECTION INPUT ;
    USE SIGNAL ;
    PORT
      LAYER M4 ;
        RECT  0 102.108 0.192 102.132 ;
    END
  END rsp_data[709]
  PIN rsp_data[710]
    DIRECTION INPUT ;
    USE SIGNAL ;
    PORT
      LAYER M4 ;
        RECT  0 102.348 0.192 102.372 ;
    END
  END rsp_data[710]
  PIN rsp_data[711]
    DIRECTION INPUT ;
    USE SIGNAL ;
    PORT
      LAYER M4 ;
        RECT  0 102.54 0.192 102.564 ;
    END
  END rsp_data[711]
  PIN rsp_data[712]
    DIRECTION INPUT ;
    USE SIGNAL ;
    PORT
      LAYER M4 ;
        RECT  0 102.78 0.192 102.804 ;
    END
  END rsp_data[712]
  PIN rsp_data[713]
    DIRECTION INPUT ;
    USE SIGNAL ;
    PORT
      LAYER M4 ;
        RECT  0 102.972 0.192 102.996 ;
    END
  END rsp_data[713]
  PIN rsp_data[714]
    DIRECTION INPUT ;
    USE SIGNAL ;
    PORT
      LAYER M4 ;
        RECT  0 103.212 0.192 103.236 ;
    END
  END rsp_data[714]
  PIN rsp_data[715]
    DIRECTION INPUT ;
    USE SIGNAL ;
    PORT
      LAYER M4 ;
        RECT  0 103.404 0.192 103.428 ;
    END
  END rsp_data[715]
  PIN rsp_data[716]
    DIRECTION INPUT ;
    USE SIGNAL ;
    PORT
      LAYER M4 ;
        RECT  0 103.644 0.192 103.668 ;
    END
  END rsp_data[716]
  PIN rsp_data[717]
    DIRECTION INPUT ;
    USE SIGNAL ;
    PORT
      LAYER M4 ;
        RECT  0 103.836 0.192 103.86 ;
    END
  END rsp_data[717]
  PIN rsp_data[718]
    DIRECTION INPUT ;
    USE SIGNAL ;
    PORT
      LAYER M4 ;
        RECT  0 104.076 0.192 104.1 ;
    END
  END rsp_data[718]
  PIN rsp_data[719]
    DIRECTION INPUT ;
    USE SIGNAL ;
    PORT
      LAYER M4 ;
        RECT  0 104.316 0.192 104.34 ;
    END
  END rsp_data[719]
  PIN rsp_data[720]
    DIRECTION INPUT ;
    USE SIGNAL ;
    PORT
      LAYER M4 ;
        RECT  0 104.508 0.192 104.532 ;
    END
  END rsp_data[720]
  PIN rsp_data[721]
    DIRECTION INPUT ;
    USE SIGNAL ;
    PORT
      LAYER M4 ;
        RECT  0 104.748 0.192 104.772 ;
    END
  END rsp_data[721]
  PIN rsp_data[722]
    DIRECTION INPUT ;
    USE SIGNAL ;
    PORT
      LAYER M4 ;
        RECT  0 104.94 0.192 104.964 ;
    END
  END rsp_data[722]
  PIN rsp_data[723]
    DIRECTION INPUT ;
    USE SIGNAL ;
    PORT
      LAYER M4 ;
        RECT  0 105.18 0.192 105.204 ;
    END
  END rsp_data[723]
  PIN rsp_data[724]
    DIRECTION INPUT ;
    USE SIGNAL ;
    PORT
      LAYER M4 ;
        RECT  0 105.372 0.192 105.396 ;
    END
  END rsp_data[724]
  PIN rsp_data[725]
    DIRECTION INPUT ;
    USE SIGNAL ;
    PORT
      LAYER M4 ;
        RECT  0 105.612 0.192 105.636 ;
    END
  END rsp_data[725]
  PIN rsp_data[726]
    DIRECTION INPUT ;
    USE SIGNAL ;
    PORT
      LAYER M4 ;
        RECT  0 105.804 0.192 105.828 ;
    END
  END rsp_data[726]
  PIN rsp_data[727]
    DIRECTION INPUT ;
    USE SIGNAL ;
    PORT
      LAYER M4 ;
        RECT  0 106.044 0.192 106.068 ;
    END
  END rsp_data[727]
  PIN rsp_data[728]
    DIRECTION INPUT ;
    USE SIGNAL ;
    PORT
      LAYER M4 ;
        RECT  0 106.236 0.192 106.26 ;
    END
  END rsp_data[728]
  PIN rsp_data[729]
    DIRECTION INPUT ;
    USE SIGNAL ;
    PORT
      LAYER M4 ;
        RECT  0 106.476 0.192 106.5 ;
    END
  END rsp_data[729]
  PIN rsp_data[730]
    DIRECTION INPUT ;
    USE SIGNAL ;
    PORT
      LAYER M4 ;
        RECT  0 106.716 0.192 106.74 ;
    END
  END rsp_data[730]
  PIN rsp_data[731]
    DIRECTION INPUT ;
    USE SIGNAL ;
    PORT
      LAYER M4 ;
        RECT  0 106.908 0.192 106.932 ;
    END
  END rsp_data[731]
  PIN rsp_data[732]
    DIRECTION INPUT ;
    USE SIGNAL ;
    PORT
      LAYER M4 ;
        RECT  0 107.148 0.192 107.172 ;
    END
  END rsp_data[732]
  PIN rsp_data[733]
    DIRECTION INPUT ;
    USE SIGNAL ;
    PORT
      LAYER M4 ;
        RECT  0 107.34 0.192 107.364 ;
    END
  END rsp_data[733]
  PIN rsp_data[734]
    DIRECTION INPUT ;
    USE SIGNAL ;
    PORT
      LAYER M4 ;
        RECT  0 107.58 0.192 107.604 ;
    END
  END rsp_data[734]
  PIN rsp_data[735]
    DIRECTION INPUT ;
    USE SIGNAL ;
    PORT
      LAYER M4 ;
        RECT  0 107.772 0.192 107.796 ;
    END
  END rsp_data[735]
  PIN rsp_data[736]
    DIRECTION INPUT ;
    USE SIGNAL ;
    PORT
      LAYER M4 ;
        RECT  0 108.012 0.192 108.036 ;
    END
  END rsp_data[736]
  PIN rsp_data[737]
    DIRECTION INPUT ;
    USE SIGNAL ;
    PORT
      LAYER M4 ;
        RECT  0 108.204 0.192 108.228 ;
    END
  END rsp_data[737]
  PIN rsp_data[738]
    DIRECTION INPUT ;
    USE SIGNAL ;
    PORT
      LAYER M4 ;
        RECT  0 108.444 0.192 108.468 ;
    END
  END rsp_data[738]
  PIN rsp_data[739]
    DIRECTION INPUT ;
    USE SIGNAL ;
    PORT
      LAYER M4 ;
        RECT  0 108.684 0.192 108.708 ;
    END
  END rsp_data[739]
  PIN rsp_data[740]
    DIRECTION INPUT ;
    USE SIGNAL ;
    PORT
      LAYER M4 ;
        RECT  0 108.876 0.192 108.9 ;
    END
  END rsp_data[740]
  PIN rsp_data[741]
    DIRECTION INPUT ;
    USE SIGNAL ;
    PORT
      LAYER M4 ;
        RECT  0 109.116 0.192 109.14 ;
    END
  END rsp_data[741]
  PIN rsp_data[742]
    DIRECTION INPUT ;
    USE SIGNAL ;
    PORT
      LAYER M4 ;
        RECT  0 109.308 0.192 109.332 ;
    END
  END rsp_data[742]
  PIN rsp_data[743]
    DIRECTION INPUT ;
    USE SIGNAL ;
    PORT
      LAYER M4 ;
        RECT  0 109.548 0.192 109.572 ;
    END
  END rsp_data[743]
  PIN rsp_data[744]
    DIRECTION INPUT ;
    USE SIGNAL ;
    PORT
      LAYER M4 ;
        RECT  0 109.74 0.192 109.764 ;
    END
  END rsp_data[744]
  PIN rsp_data[745]
    DIRECTION INPUT ;
    USE SIGNAL ;
    PORT
      LAYER M4 ;
        RECT  0 109.98 0.192 110.004 ;
    END
  END rsp_data[745]
  PIN rsp_data[746]
    DIRECTION INPUT ;
    USE SIGNAL ;
    PORT
      LAYER M4 ;
        RECT  0 110.172 0.192 110.196 ;
    END
  END rsp_data[746]
  PIN rsp_data[747]
    DIRECTION INPUT ;
    USE SIGNAL ;
    PORT
      LAYER M4 ;
        RECT  0 110.412 0.192 110.436 ;
    END
  END rsp_data[747]
  PIN rsp_data[748]
    DIRECTION INPUT ;
    USE SIGNAL ;
    PORT
      LAYER M4 ;
        RECT  0 110.604 0.192 110.628 ;
    END
  END rsp_data[748]
  PIN rsp_data[749]
    DIRECTION INPUT ;
    USE SIGNAL ;
    PORT
      LAYER M4 ;
        RECT  0 110.844 0.192 110.868 ;
    END
  END rsp_data[749]
  PIN rsp_data[750]
    DIRECTION INPUT ;
    USE SIGNAL ;
    PORT
      LAYER M4 ;
        RECT  0 111.084 0.192 111.108 ;
    END
  END rsp_data[750]
  PIN rsp_data[751]
    DIRECTION INPUT ;
    USE SIGNAL ;
    PORT
      LAYER M4 ;
        RECT  0 111.276 0.192 111.3 ;
    END
  END rsp_data[751]
  PIN rsp_data[752]
    DIRECTION INPUT ;
    USE SIGNAL ;
    PORT
      LAYER M4 ;
        RECT  0 111.516 0.192 111.54 ;
    END
  END rsp_data[752]
  PIN rsp_data[753]
    DIRECTION INPUT ;
    USE SIGNAL ;
    PORT
      LAYER M4 ;
        RECT  0 111.708 0.192 111.732 ;
    END
  END rsp_data[753]
  PIN rsp_data[754]
    DIRECTION INPUT ;
    USE SIGNAL ;
    PORT
      LAYER M4 ;
        RECT  0 111.948 0.192 111.972 ;
    END
  END rsp_data[754]
  PIN rsp_data[755]
    DIRECTION INPUT ;
    USE SIGNAL ;
    PORT
      LAYER M4 ;
        RECT  0 112.14 0.192 112.164 ;
    END
  END rsp_data[755]
  PIN rsp_data[756]
    DIRECTION INPUT ;
    USE SIGNAL ;
    PORT
      LAYER M4 ;
        RECT  0 112.38 0.192 112.404 ;
    END
  END rsp_data[756]
  PIN rsp_data[757]
    DIRECTION INPUT ;
    USE SIGNAL ;
    PORT
      LAYER M4 ;
        RECT  0 112.572 0.192 112.596 ;
    END
  END rsp_data[757]
  PIN rsp_data[758]
    DIRECTION INPUT ;
    USE SIGNAL ;
    PORT
      LAYER M4 ;
        RECT  0 112.812 0.192 112.836 ;
    END
  END rsp_data[758]
  PIN rsp_data[759]
    DIRECTION INPUT ;
    USE SIGNAL ;
    PORT
      LAYER M4 ;
        RECT  0 113.052 0.192 113.076 ;
    END
  END rsp_data[759]
  PIN rsp_data[760]
    DIRECTION INPUT ;
    USE SIGNAL ;
    PORT
      LAYER M4 ;
        RECT  0 113.244 0.192 113.268 ;
    END
  END rsp_data[760]
  PIN rsp_data[761]
    DIRECTION INPUT ;
    USE SIGNAL ;
    PORT
      LAYER M4 ;
        RECT  0 113.484 0.192 113.508 ;
    END
  END rsp_data[761]
  PIN rsp_data[762]
    DIRECTION INPUT ;
    USE SIGNAL ;
    PORT
      LAYER M4 ;
        RECT  0 113.676 0.192 113.7 ;
    END
  END rsp_data[762]
  PIN rsp_data[763]
    DIRECTION INPUT ;
    USE SIGNAL ;
    PORT
      LAYER M4 ;
        RECT  0 113.916 0.192 113.94 ;
    END
  END rsp_data[763]
  PIN rsp_data[764]
    DIRECTION INPUT ;
    USE SIGNAL ;
    PORT
      LAYER M4 ;
        RECT  0 114.108 0.192 114.132 ;
    END
  END rsp_data[764]
  PIN rsp_data[765]
    DIRECTION INPUT ;
    USE SIGNAL ;
    PORT
      LAYER M4 ;
        RECT  0 114.348 0.192 114.372 ;
    END
  END rsp_data[765]
  PIN rsp_data[766]
    DIRECTION INPUT ;
    USE SIGNAL ;
    PORT
      LAYER M4 ;
        RECT  0 114.54 0.192 114.564 ;
    END
  END rsp_data[766]
  PIN rsp_data[767]
    DIRECTION INPUT ;
    USE SIGNAL ;
    PORT
      LAYER M4 ;
        RECT  0 114.78 0.192 114.804 ;
    END
  END rsp_data[767]
  PIN rsp_data[768]
    DIRECTION INPUT ;
    USE SIGNAL ;
    PORT
      LAYER M4 ;
        RECT  0 114.972 0.192 114.996 ;
    END
  END rsp_data[768]
  PIN rsp_data[769]
    DIRECTION INPUT ;
    USE SIGNAL ;
    PORT
      LAYER M4 ;
        RECT  0 115.212 0.192 115.236 ;
    END
  END rsp_data[769]
  PIN rsp_data[770]
    DIRECTION INPUT ;
    USE SIGNAL ;
    PORT
      LAYER M4 ;
        RECT  0 115.452 0.192 115.476 ;
    END
  END rsp_data[770]
  PIN rsp_data[771]
    DIRECTION INPUT ;
    USE SIGNAL ;
    PORT
      LAYER M4 ;
        RECT  0 115.644 0.192 115.668 ;
    END
  END rsp_data[771]
  PIN rsp_data[772]
    DIRECTION INPUT ;
    USE SIGNAL ;
    PORT
      LAYER M4 ;
        RECT  0 115.884 0.192 115.908 ;
    END
  END rsp_data[772]
  PIN rsp_data[773]
    DIRECTION INPUT ;
    USE SIGNAL ;
    PORT
      LAYER M4 ;
        RECT  0 116.076 0.192 116.1 ;
    END
  END rsp_data[773]
  PIN rsp_data[774]
    DIRECTION INPUT ;
    USE SIGNAL ;
    PORT
      LAYER M4 ;
        RECT  0 116.316 0.192 116.34 ;
    END
  END rsp_data[774]
  PIN rsp_data[775]
    DIRECTION INPUT ;
    USE SIGNAL ;
    PORT
      LAYER M4 ;
        RECT  0 116.508 0.192 116.532 ;
    END
  END rsp_data[775]
  PIN rsp_data[776]
    DIRECTION INPUT ;
    USE SIGNAL ;
    PORT
      LAYER M4 ;
        RECT  0 116.748 0.192 116.772 ;
    END
  END rsp_data[776]
  PIN rsp_data[777]
    DIRECTION INPUT ;
    USE SIGNAL ;
    PORT
      LAYER M4 ;
        RECT  0 116.94 0.192 116.964 ;
    END
  END rsp_data[777]
  PIN rsp_data[778]
    DIRECTION INPUT ;
    USE SIGNAL ;
    PORT
      LAYER M4 ;
        RECT  0 117.18 0.192 117.204 ;
    END
  END rsp_data[778]
  PIN rsp_data[779]
    DIRECTION INPUT ;
    USE SIGNAL ;
    PORT
      LAYER M4 ;
        RECT  0 117.42 0.192 117.444 ;
    END
  END rsp_data[779]
  PIN rsp_data[780]
    DIRECTION INPUT ;
    USE SIGNAL ;
    PORT
      LAYER M4 ;
        RECT  0 117.612 0.192 117.636 ;
    END
  END rsp_data[780]
  PIN rsp_data[781]
    DIRECTION INPUT ;
    USE SIGNAL ;
    PORT
      LAYER M4 ;
        RECT  0 117.852 0.192 117.876 ;
    END
  END rsp_data[781]
  PIN rsp_data[782]
    DIRECTION INPUT ;
    USE SIGNAL ;
    PORT
      LAYER M4 ;
        RECT  0 118.044 0.192 118.068 ;
    END
  END rsp_data[782]
  PIN rsp_data[783]
    DIRECTION INPUT ;
    USE SIGNAL ;
    PORT
      LAYER M4 ;
        RECT  0 118.284 0.192 118.308 ;
    END
  END rsp_data[783]
  PIN rsp_data[784]
    DIRECTION INPUT ;
    USE SIGNAL ;
    PORT
      LAYER M4 ;
        RECT  0 118.476 0.192 118.5 ;
    END
  END rsp_data[784]
  PIN rsp_data[785]
    DIRECTION INPUT ;
    USE SIGNAL ;
    PORT
      LAYER M4 ;
        RECT  0 118.716 0.192 118.74 ;
    END
  END rsp_data[785]
  PIN rsp_data[786]
    DIRECTION INPUT ;
    USE SIGNAL ;
    PORT
      LAYER M4 ;
        RECT  0 118.908 0.192 118.932 ;
    END
  END rsp_data[786]
  PIN rsp_data[787]
    DIRECTION INPUT ;
    USE SIGNAL ;
    PORT
      LAYER M4 ;
        RECT  0 119.148 0.192 119.172 ;
    END
  END rsp_data[787]
  PIN rsp_data[788]
    DIRECTION INPUT ;
    USE SIGNAL ;
    PORT
      LAYER M4 ;
        RECT  0 119.34 0.192 119.364 ;
    END
  END rsp_data[788]
  PIN rsp_data[789]
    DIRECTION INPUT ;
    USE SIGNAL ;
    PORT
      LAYER M4 ;
        RECT  0 119.58 0.192 119.604 ;
    END
  END rsp_data[789]
  PIN rsp_data[790]
    DIRECTION INPUT ;
    USE SIGNAL ;
    PORT
      LAYER M4 ;
        RECT  0 119.82 0.192 119.844 ;
    END
  END rsp_data[790]
  PIN rsp_data[791]
    DIRECTION INPUT ;
    USE SIGNAL ;
    PORT
      LAYER M4 ;
        RECT  0 120.012 0.192 120.036 ;
    END
  END rsp_data[791]
  PIN rsp_data[792]
    DIRECTION INPUT ;
    USE SIGNAL ;
    PORT
      LAYER M4 ;
        RECT  0 120.252 0.192 120.276 ;
    END
  END rsp_data[792]
  PIN rsp_data[793]
    DIRECTION INPUT ;
    USE SIGNAL ;
    PORT
      LAYER M4 ;
        RECT  0 120.444 0.192 120.468 ;
    END
  END rsp_data[793]
  PIN rsp_data[794]
    DIRECTION INPUT ;
    USE SIGNAL ;
    PORT
      LAYER M4 ;
        RECT  0 120.684 0.192 120.708 ;
    END
  END rsp_data[794]
  PIN rsp_data[795]
    DIRECTION INPUT ;
    USE SIGNAL ;
    PORT
      LAYER M4 ;
        RECT  0 120.876 0.192 120.9 ;
    END
  END rsp_data[795]
  PIN rsp_data[796]
    DIRECTION INPUT ;
    USE SIGNAL ;
    PORT
      LAYER M4 ;
        RECT  0 121.116 0.192 121.14 ;
    END
  END rsp_data[796]
  PIN rsp_data[797]
    DIRECTION INPUT ;
    USE SIGNAL ;
    PORT
      LAYER M4 ;
        RECT  0 121.308 0.192 121.332 ;
    END
  END rsp_data[797]
  PIN rsp_data[798]
    DIRECTION INPUT ;
    USE SIGNAL ;
    PORT
      LAYER M4 ;
        RECT  0 121.548 0.192 121.572 ;
    END
  END rsp_data[798]
  PIN rsp_data[799]
    DIRECTION INPUT ;
    USE SIGNAL ;
    PORT
      LAYER M4 ;
        RECT  0 121.74 0.192 121.764 ;
    END
  END rsp_data[799]
  PIN rsp_data[800]
    DIRECTION INPUT ;
    USE SIGNAL ;
    PORT
      LAYER M4 ;
        RECT  0 121.98 0.192 122.004 ;
    END
  END rsp_data[800]
  PIN rsp_data[801]
    DIRECTION INPUT ;
    USE SIGNAL ;
    PORT
      LAYER M4 ;
        RECT  0 122.22 0.192 122.244 ;
    END
  END rsp_data[801]
  PIN rsp_data[802]
    DIRECTION INPUT ;
    USE SIGNAL ;
    PORT
      LAYER M4 ;
        RECT  0 122.412 0.192 122.436 ;
    END
  END rsp_data[802]
  PIN rsp_data[803]
    DIRECTION INPUT ;
    USE SIGNAL ;
    PORT
      LAYER M4 ;
        RECT  0 122.652 0.192 122.676 ;
    END
  END rsp_data[803]
  PIN rsp_data[804]
    DIRECTION INPUT ;
    USE SIGNAL ;
    PORT
      LAYER M4 ;
        RECT  0 122.844 0.192 122.868 ;
    END
  END rsp_data[804]
  PIN rsp_data[805]
    DIRECTION INPUT ;
    USE SIGNAL ;
    PORT
      LAYER M4 ;
        RECT  0 123.084 0.192 123.108 ;
    END
  END rsp_data[805]
  PIN rsp_data[806]
    DIRECTION INPUT ;
    USE SIGNAL ;
    PORT
      LAYER M4 ;
        RECT  0 123.276 0.192 123.3 ;
    END
  END rsp_data[806]
  PIN rsp_data[807]
    DIRECTION INPUT ;
    USE SIGNAL ;
    PORT
      LAYER M4 ;
        RECT  0 123.516 0.192 123.54 ;
    END
  END rsp_data[807]
  PIN rsp_data[808]
    DIRECTION INPUT ;
    USE SIGNAL ;
    PORT
      LAYER M4 ;
        RECT  0 123.708 0.192 123.732 ;
    END
  END rsp_data[808]
  PIN rsp_data[809]
    DIRECTION INPUT ;
    USE SIGNAL ;
    PORT
      LAYER M4 ;
        RECT  0 123.948 0.192 123.972 ;
    END
  END rsp_data[809]
  PIN rsp_data[810]
    DIRECTION INPUT ;
    USE SIGNAL ;
    PORT
      LAYER M4 ;
        RECT  0 124.188 0.192 124.212 ;
    END
  END rsp_data[810]
  PIN rsp_data[811]
    DIRECTION INPUT ;
    USE SIGNAL ;
    PORT
      LAYER M4 ;
        RECT  0 124.38 0.192 124.404 ;
    END
  END rsp_data[811]
  PIN rsp_data[812]
    DIRECTION INPUT ;
    USE SIGNAL ;
    PORT
      LAYER M4 ;
        RECT  0 124.62 0.192 124.644 ;
    END
  END rsp_data[812]
  PIN rsp_data[813]
    DIRECTION INPUT ;
    USE SIGNAL ;
    PORT
      LAYER M4 ;
        RECT  0 124.812 0.192 124.836 ;
    END
  END rsp_data[813]
  PIN rsp_data[814]
    DIRECTION INPUT ;
    USE SIGNAL ;
    PORT
      LAYER M4 ;
        RECT  0 125.052 0.192 125.076 ;
    END
  END rsp_data[814]
  PIN rsp_data[815]
    DIRECTION INPUT ;
    USE SIGNAL ;
    PORT
      LAYER M4 ;
        RECT  0 125.244 0.192 125.268 ;
    END
  END rsp_data[815]
  PIN rsp_data[816]
    DIRECTION INPUT ;
    USE SIGNAL ;
    PORT
      LAYER M4 ;
        RECT  0 125.484 0.192 125.508 ;
    END
  END rsp_data[816]
  PIN rsp_data[817]
    DIRECTION INPUT ;
    USE SIGNAL ;
    PORT
      LAYER M4 ;
        RECT  0 125.676 0.192 125.7 ;
    END
  END rsp_data[817]
  PIN rsp_data[818]
    DIRECTION INPUT ;
    USE SIGNAL ;
    PORT
      LAYER M4 ;
        RECT  0 125.916 0.192 125.94 ;
    END
  END rsp_data[818]
  PIN rsp_data[819]
    DIRECTION INPUT ;
    USE SIGNAL ;
    PORT
      LAYER M4 ;
        RECT  0 126.108 0.192 126.132 ;
    END
  END rsp_data[819]
  PIN rsp_data[820]
    DIRECTION INPUT ;
    USE SIGNAL ;
    PORT
      LAYER M4 ;
        RECT  0 126.348 0.192 126.372 ;
    END
  END rsp_data[820]
  PIN rsp_data[821]
    DIRECTION INPUT ;
    USE SIGNAL ;
    PORT
      LAYER M4 ;
        RECT  0 126.588 0.192 126.612 ;
    END
  END rsp_data[821]
  PIN rsp_data[822]
    DIRECTION INPUT ;
    USE SIGNAL ;
    PORT
      LAYER M4 ;
        RECT  0 126.78 0.192 126.804 ;
    END
  END rsp_data[822]
  PIN rsp_data[823]
    DIRECTION INPUT ;
    USE SIGNAL ;
    PORT
      LAYER M4 ;
        RECT  0 127.02 0.192 127.044 ;
    END
  END rsp_data[823]
  PIN rsp_data[824]
    DIRECTION INPUT ;
    USE SIGNAL ;
    PORT
      LAYER M4 ;
        RECT  0 127.212 0.192 127.236 ;
    END
  END rsp_data[824]
  PIN rsp_data[825]
    DIRECTION INPUT ;
    USE SIGNAL ;
    PORT
      LAYER M4 ;
        RECT  0 127.452 0.192 127.476 ;
    END
  END rsp_data[825]
  PIN rsp_data[826]
    DIRECTION INPUT ;
    USE SIGNAL ;
    PORT
      LAYER M4 ;
        RECT  0 127.644 0.192 127.668 ;
    END
  END rsp_data[826]
  PIN rsp_data[827]
    DIRECTION INPUT ;
    USE SIGNAL ;
    PORT
      LAYER M4 ;
        RECT  0 127.884 0.192 127.908 ;
    END
  END rsp_data[827]
  PIN rsp_data[828]
    DIRECTION INPUT ;
    USE SIGNAL ;
    PORT
      LAYER M4 ;
        RECT  0 128.076 0.192 128.1 ;
    END
  END rsp_data[828]
  PIN rsp_data[829]
    DIRECTION INPUT ;
    USE SIGNAL ;
    PORT
      LAYER M4 ;
        RECT  0 128.316 0.192 128.34 ;
    END
  END rsp_data[829]
  PIN rsp_data[830]
    DIRECTION INPUT ;
    USE SIGNAL ;
    PORT
      LAYER M4 ;
        RECT  0 128.556 0.192 128.58 ;
    END
  END rsp_data[830]
  PIN rsp_data[831]
    DIRECTION INPUT ;
    USE SIGNAL ;
    PORT
      LAYER M4 ;
        RECT  0 128.748 0.192 128.772 ;
    END
  END rsp_data[831]
  PIN rsp_data[832]
    DIRECTION INPUT ;
    USE SIGNAL ;
    PORT
      LAYER M4 ;
        RECT  0 128.988 0.192 129.012 ;
    END
  END rsp_data[832]
  PIN rsp_data[833]
    DIRECTION INPUT ;
    USE SIGNAL ;
    PORT
      LAYER M4 ;
        RECT  0 129.18 0.192 129.204 ;
    END
  END rsp_data[833]
  PIN rsp_data[834]
    DIRECTION INPUT ;
    USE SIGNAL ;
    PORT
      LAYER M4 ;
        RECT  0 129.42 0.192 129.444 ;
    END
  END rsp_data[834]
  PIN rsp_data[835]
    DIRECTION INPUT ;
    USE SIGNAL ;
    PORT
      LAYER M4 ;
        RECT  0 129.612 0.192 129.636 ;
    END
  END rsp_data[835]
  PIN rsp_data[836]
    DIRECTION INPUT ;
    USE SIGNAL ;
    PORT
      LAYER M4 ;
        RECT  0 129.852 0.192 129.876 ;
    END
  END rsp_data[836]
  PIN rsp_data[837]
    DIRECTION INPUT ;
    USE SIGNAL ;
    PORT
      LAYER M4 ;
        RECT  0 130.044 0.192 130.068 ;
    END
  END rsp_data[837]
  PIN rsp_data[838]
    DIRECTION INPUT ;
    USE SIGNAL ;
    PORT
      LAYER M4 ;
        RECT  0 130.284 0.192 130.308 ;
    END
  END rsp_data[838]
  PIN rsp_data[839]
    DIRECTION INPUT ;
    USE SIGNAL ;
    PORT
      LAYER M4 ;
        RECT  0 130.476 0.192 130.5 ;
    END
  END rsp_data[839]
  PIN rsp_data[840]
    DIRECTION INPUT ;
    USE SIGNAL ;
    PORT
      LAYER M4 ;
        RECT  0 130.716 0.192 130.74 ;
    END
  END rsp_data[840]
  PIN rsp_data[841]
    DIRECTION INPUT ;
    USE SIGNAL ;
    PORT
      LAYER M4 ;
        RECT  0 130.956 0.192 130.98 ;
    END
  END rsp_data[841]
  PIN rsp_data[842]
    DIRECTION INPUT ;
    USE SIGNAL ;
    PORT
      LAYER M4 ;
        RECT  0 131.148 0.192 131.172 ;
    END
  END rsp_data[842]
  PIN rsp_data[843]
    DIRECTION INPUT ;
    USE SIGNAL ;
    PORT
      LAYER M4 ;
        RECT  0 131.388 0.192 131.412 ;
    END
  END rsp_data[843]
  PIN rsp_data[844]
    DIRECTION INPUT ;
    USE SIGNAL ;
    PORT
      LAYER M4 ;
        RECT  0 131.58 0.192 131.604 ;
    END
  END rsp_data[844]
  PIN rsp_data[845]
    DIRECTION INPUT ;
    USE SIGNAL ;
    PORT
      LAYER M4 ;
        RECT  0 131.82 0.192 131.844 ;
    END
  END rsp_data[845]
  PIN rsp_data[846]
    DIRECTION INPUT ;
    USE SIGNAL ;
    PORT
      LAYER M4 ;
        RECT  0 132.012 0.192 132.036 ;
    END
  END rsp_data[846]
  PIN rsp_data[847]
    DIRECTION INPUT ;
    USE SIGNAL ;
    PORT
      LAYER M4 ;
        RECT  0 132.252 0.192 132.276 ;
    END
  END rsp_data[847]
  PIN rsp_data[848]
    DIRECTION INPUT ;
    USE SIGNAL ;
    PORT
      LAYER M4 ;
        RECT  0 132.444 0.192 132.468 ;
    END
  END rsp_data[848]
  PIN rsp_data[849]
    DIRECTION INPUT ;
    USE SIGNAL ;
    PORT
      LAYER M4 ;
        RECT  0 132.684 0.192 132.708 ;
    END
  END rsp_data[849]
  PIN rsp_data[850]
    DIRECTION INPUT ;
    USE SIGNAL ;
    PORT
      LAYER M4 ;
        RECT  0 132.924 0.192 132.948 ;
    END
  END rsp_data[850]
  PIN rsp_data[851]
    DIRECTION INPUT ;
    USE SIGNAL ;
    PORT
      LAYER M4 ;
        RECT  0 133.116 0.192 133.14 ;
    END
  END rsp_data[851]
  PIN rsp_data[852]
    DIRECTION INPUT ;
    USE SIGNAL ;
    PORT
      LAYER M4 ;
        RECT  0 133.356 0.192 133.38 ;
    END
  END rsp_data[852]
  PIN rsp_data[853]
    DIRECTION INPUT ;
    USE SIGNAL ;
    PORT
      LAYER M4 ;
        RECT  0 133.548 0.192 133.572 ;
    END
  END rsp_data[853]
  PIN rsp_data[854]
    DIRECTION INPUT ;
    USE SIGNAL ;
    PORT
      LAYER M4 ;
        RECT  0 133.788 0.192 133.812 ;
    END
  END rsp_data[854]
  PIN rsp_data[855]
    DIRECTION INPUT ;
    USE SIGNAL ;
    PORT
      LAYER M4 ;
        RECT  0 133.98 0.192 134.004 ;
    END
  END rsp_data[855]
  PIN rsp_data[856]
    DIRECTION INPUT ;
    USE SIGNAL ;
    PORT
      LAYER M4 ;
        RECT  0 134.22 0.192 134.244 ;
    END
  END rsp_data[856]
  PIN rsp_data[857]
    DIRECTION INPUT ;
    USE SIGNAL ;
    PORT
      LAYER M4 ;
        RECT  0 134.412 0.192 134.436 ;
    END
  END rsp_data[857]
  PIN rsp_data[858]
    DIRECTION INPUT ;
    USE SIGNAL ;
    PORT
      LAYER M4 ;
        RECT  0 134.652 0.192 134.676 ;
    END
  END rsp_data[858]
  PIN rsp_data[859]
    DIRECTION INPUT ;
    USE SIGNAL ;
    PORT
      LAYER M4 ;
        RECT  0 134.844 0.192 134.868 ;
    END
  END rsp_data[859]
  PIN rsp_data[860]
    DIRECTION INPUT ;
    USE SIGNAL ;
    PORT
      LAYER M4 ;
        RECT  0 135.084 0.192 135.108 ;
    END
  END rsp_data[860]
  PIN rsp_data[861]
    DIRECTION INPUT ;
    USE SIGNAL ;
    PORT
      LAYER M4 ;
        RECT  0 135.324 0.192 135.348 ;
    END
  END rsp_data[861]
  PIN rsp_data[862]
    DIRECTION INPUT ;
    USE SIGNAL ;
    PORT
      LAYER M4 ;
        RECT  0 135.516 0.192 135.54 ;
    END
  END rsp_data[862]
  PIN rsp_data[863]
    DIRECTION INPUT ;
    USE SIGNAL ;
    PORT
      LAYER M4 ;
        RECT  0 135.756 0.192 135.78 ;
    END
  END rsp_data[863]
  PIN rsp_data[864]
    DIRECTION INPUT ;
    USE SIGNAL ;
    PORT
      LAYER M4 ;
        RECT  0 135.948 0.192 135.972 ;
    END
  END rsp_data[864]
  PIN rsp_data[865]
    DIRECTION INPUT ;
    USE SIGNAL ;
    PORT
      LAYER M4 ;
        RECT  0 136.188 0.192 136.212 ;
    END
  END rsp_data[865]
  PIN rsp_data[866]
    DIRECTION INPUT ;
    USE SIGNAL ;
    PORT
      LAYER M4 ;
        RECT  0 136.38 0.192 136.404 ;
    END
  END rsp_data[866]
  PIN rsp_data[867]
    DIRECTION INPUT ;
    USE SIGNAL ;
    PORT
      LAYER M4 ;
        RECT  0 136.62 0.192 136.644 ;
    END
  END rsp_data[867]
  PIN rsp_data[868]
    DIRECTION INPUT ;
    USE SIGNAL ;
    PORT
      LAYER M4 ;
        RECT  0 136.812 0.192 136.836 ;
    END
  END rsp_data[868]
  PIN rsp_data[869]
    DIRECTION INPUT ;
    USE SIGNAL ;
    PORT
      LAYER M4 ;
        RECT  0 137.052 0.192 137.076 ;
    END
  END rsp_data[869]
  PIN rsp_data[870]
    DIRECTION INPUT ;
    USE SIGNAL ;
    PORT
      LAYER M4 ;
        RECT  0 137.292 0.192 137.316 ;
    END
  END rsp_data[870]
  PIN rsp_data[871]
    DIRECTION INPUT ;
    USE SIGNAL ;
    PORT
      LAYER M4 ;
        RECT  0 137.484 0.192 137.508 ;
    END
  END rsp_data[871]
  PIN rsp_data[872]
    DIRECTION INPUT ;
    USE SIGNAL ;
    PORT
      LAYER M4 ;
        RECT  0 137.724 0.192 137.748 ;
    END
  END rsp_data[872]
  PIN rsp_data[873]
    DIRECTION INPUT ;
    USE SIGNAL ;
    PORT
      LAYER M4 ;
        RECT  0 137.916 0.192 137.94 ;
    END
  END rsp_data[873]
  PIN rsp_data[874]
    DIRECTION INPUT ;
    USE SIGNAL ;
    PORT
      LAYER M4 ;
        RECT  0 138.156 0.192 138.18 ;
    END
  END rsp_data[874]
  PIN rsp_data[875]
    DIRECTION INPUT ;
    USE SIGNAL ;
    PORT
      LAYER M4 ;
        RECT  0 138.348 0.192 138.372 ;
    END
  END rsp_data[875]
  PIN rsp_data[876]
    DIRECTION INPUT ;
    USE SIGNAL ;
    PORT
      LAYER M4 ;
        RECT  0 138.588 0.192 138.612 ;
    END
  END rsp_data[876]
  PIN rsp_data[877]
    DIRECTION INPUT ;
    USE SIGNAL ;
    PORT
      LAYER M4 ;
        RECT  0 138.78 0.192 138.804 ;
    END
  END rsp_data[877]
  PIN rsp_data[878]
    DIRECTION INPUT ;
    USE SIGNAL ;
    PORT
      LAYER M4 ;
        RECT  0 139.02 0.192 139.044 ;
    END
  END rsp_data[878]
  PIN rsp_data[879]
    DIRECTION INPUT ;
    USE SIGNAL ;
    PORT
      LAYER M4 ;
        RECT  0 139.212 0.192 139.236 ;
    END
  END rsp_data[879]
  PIN rsp_data[880]
    DIRECTION INPUT ;
    USE SIGNAL ;
    PORT
      LAYER M4 ;
        RECT  0 139.452 0.192 139.476 ;
    END
  END rsp_data[880]
  PIN rsp_data[881]
    DIRECTION INPUT ;
    USE SIGNAL ;
    PORT
      LAYER M4 ;
        RECT  0 139.692 0.192 139.716 ;
    END
  END rsp_data[881]
  PIN rsp_data[882]
    DIRECTION INPUT ;
    USE SIGNAL ;
    PORT
      LAYER M4 ;
        RECT  0 139.884 0.192 139.908 ;
    END
  END rsp_data[882]
  PIN rsp_data[883]
    DIRECTION INPUT ;
    USE SIGNAL ;
    PORT
      LAYER M4 ;
        RECT  0 140.124 0.192 140.148 ;
    END
  END rsp_data[883]
  PIN rsp_data[884]
    DIRECTION INPUT ;
    USE SIGNAL ;
    PORT
      LAYER M4 ;
        RECT  0 140.316 0.192 140.34 ;
    END
  END rsp_data[884]
  PIN rsp_data[885]
    DIRECTION INPUT ;
    USE SIGNAL ;
    PORT
      LAYER M4 ;
        RECT  0 140.556 0.192 140.58 ;
    END
  END rsp_data[885]
  PIN rsp_data[886]
    DIRECTION INPUT ;
    USE SIGNAL ;
    PORT
      LAYER M4 ;
        RECT  0 140.748 0.192 140.772 ;
    END
  END rsp_data[886]
  PIN rsp_data[887]
    DIRECTION INPUT ;
    USE SIGNAL ;
    PORT
      LAYER M4 ;
        RECT  0 140.988 0.192 141.012 ;
    END
  END rsp_data[887]
  PIN rsp_data[888]
    DIRECTION INPUT ;
    USE SIGNAL ;
    PORT
      LAYER M4 ;
        RECT  0 141.18 0.192 141.204 ;
    END
  END rsp_data[888]
  PIN rsp_data[889]
    DIRECTION INPUT ;
    USE SIGNAL ;
    PORT
      LAYER M4 ;
        RECT  0 141.42 0.192 141.444 ;
    END
  END rsp_data[889]
  PIN rsp_data[890]
    DIRECTION INPUT ;
    USE SIGNAL ;
    PORT
      LAYER M4 ;
        RECT  0 141.612 0.192 141.636 ;
    END
  END rsp_data[890]
  PIN rsp_data[891]
    DIRECTION INPUT ;
    USE SIGNAL ;
    PORT
      LAYER M4 ;
        RECT  0 141.852 0.192 141.876 ;
    END
  END rsp_data[891]
  PIN rsp_data[892]
    DIRECTION INPUT ;
    USE SIGNAL ;
    PORT
      LAYER M4 ;
        RECT  0 142.092 0.192 142.116 ;
    END
  END rsp_data[892]
  PIN rsp_data[893]
    DIRECTION INPUT ;
    USE SIGNAL ;
    PORT
      LAYER M4 ;
        RECT  0 142.284 0.192 142.308 ;
    END
  END rsp_data[893]
  PIN rsp_data[894]
    DIRECTION INPUT ;
    USE SIGNAL ;
    PORT
      LAYER M4 ;
        RECT  0 142.524 0.192 142.548 ;
    END
  END rsp_data[894]
  PIN rsp_data[895]
    DIRECTION INPUT ;
    USE SIGNAL ;
    PORT
      LAYER M4 ;
        RECT  0 142.716 0.192 142.74 ;
    END
  END rsp_data[895]
  PIN rsp_data[896]
    DIRECTION INPUT ;
    USE SIGNAL ;
    PORT
      LAYER M4 ;
        RECT  0 142.956 0.192 142.98 ;
    END
  END rsp_data[896]
  PIN rsp_data[897]
    DIRECTION INPUT ;
    USE SIGNAL ;
    PORT
      LAYER M4 ;
        RECT  0 143.148 0.192 143.172 ;
    END
  END rsp_data[897]
  PIN rsp_data[898]
    DIRECTION INPUT ;
    USE SIGNAL ;
    PORT
      LAYER M4 ;
        RECT  0 143.388 0.192 143.412 ;
    END
  END rsp_data[898]
  PIN rsp_data[899]
    DIRECTION INPUT ;
    USE SIGNAL ;
    PORT
      LAYER M4 ;
        RECT  0 143.58 0.192 143.604 ;
    END
  END rsp_data[899]
  PIN rsp_data[900]
    DIRECTION INPUT ;
    USE SIGNAL ;
    PORT
      LAYER M4 ;
        RECT  0 143.82 0.192 143.844 ;
    END
  END rsp_data[900]
  PIN rsp_data[901]
    DIRECTION INPUT ;
    USE SIGNAL ;
    PORT
      LAYER M4 ;
        RECT  0 144.06 0.192 144.084 ;
    END
  END rsp_data[901]
  PIN rsp_data[902]
    DIRECTION INPUT ;
    USE SIGNAL ;
    PORT
      LAYER M4 ;
        RECT  0 144.252 0.192 144.276 ;
    END
  END rsp_data[902]
  PIN rsp_data[903]
    DIRECTION INPUT ;
    USE SIGNAL ;
    PORT
      LAYER M4 ;
        RECT  0 144.492 0.192 144.516 ;
    END
  END rsp_data[903]
  PIN rsp_data[904]
    DIRECTION INPUT ;
    USE SIGNAL ;
    PORT
      LAYER M4 ;
        RECT  0 144.684 0.192 144.708 ;
    END
  END rsp_data[904]
  PIN rsp_data[905]
    DIRECTION INPUT ;
    USE SIGNAL ;
    PORT
      LAYER M4 ;
        RECT  0 144.924 0.192 144.948 ;
    END
  END rsp_data[905]
  PIN rsp_data[906]
    DIRECTION INPUT ;
    USE SIGNAL ;
    PORT
      LAYER M4 ;
        RECT  0 145.116 0.192 145.14 ;
    END
  END rsp_data[906]
  PIN rsp_data[907]
    DIRECTION INPUT ;
    USE SIGNAL ;
    PORT
      LAYER M4 ;
        RECT  0 145.356 0.192 145.38 ;
    END
  END rsp_data[907]
  PIN rsp_data[908]
    DIRECTION INPUT ;
    USE SIGNAL ;
    PORT
      LAYER M4 ;
        RECT  0 145.548 0.192 145.572 ;
    END
  END rsp_data[908]
  PIN rsp_data[909]
    DIRECTION INPUT ;
    USE SIGNAL ;
    PORT
      LAYER M4 ;
        RECT  0 145.788 0.192 145.812 ;
    END
  END rsp_data[909]
  PIN rsp_data[910]
    DIRECTION INPUT ;
    USE SIGNAL ;
    PORT
      LAYER M4 ;
        RECT  0 145.98 0.192 146.004 ;
    END
  END rsp_data[910]
  PIN rsp_data[911]
    DIRECTION INPUT ;
    USE SIGNAL ;
    PORT
      LAYER M4 ;
        RECT  0 146.22 0.192 146.244 ;
    END
  END rsp_data[911]
  PIN rsp_data[912]
    DIRECTION INPUT ;
    USE SIGNAL ;
    PORT
      LAYER M4 ;
        RECT  0 146.46 0.192 146.484 ;
    END
  END rsp_data[912]
  PIN rsp_data[913]
    DIRECTION INPUT ;
    USE SIGNAL ;
    PORT
      LAYER M4 ;
        RECT  0 146.652 0.192 146.676 ;
    END
  END rsp_data[913]
  PIN rsp_data[914]
    DIRECTION INPUT ;
    USE SIGNAL ;
    PORT
      LAYER M4 ;
        RECT  0 146.892 0.192 146.916 ;
    END
  END rsp_data[914]
  PIN rsp_data[915]
    DIRECTION INPUT ;
    USE SIGNAL ;
    PORT
      LAYER M4 ;
        RECT  0 147.084 0.192 147.108 ;
    END
  END rsp_data[915]
  PIN rsp_data[916]
    DIRECTION INPUT ;
    USE SIGNAL ;
    PORT
      LAYER M4 ;
        RECT  0 147.324 0.192 147.348 ;
    END
  END rsp_data[916]
  PIN rsp_data[917]
    DIRECTION INPUT ;
    USE SIGNAL ;
    PORT
      LAYER M4 ;
        RECT  0 147.516 0.192 147.54 ;
    END
  END rsp_data[917]
  PIN rsp_data[918]
    DIRECTION INPUT ;
    USE SIGNAL ;
    PORT
      LAYER M4 ;
        RECT  0 147.756 0.192 147.78 ;
    END
  END rsp_data[918]
  PIN rsp_data[919]
    DIRECTION INPUT ;
    USE SIGNAL ;
    PORT
      LAYER M4 ;
        RECT  0 147.948 0.192 147.972 ;
    END
  END rsp_data[919]
  PIN rsp_data[920]
    DIRECTION INPUT ;
    USE SIGNAL ;
    PORT
      LAYER M4 ;
        RECT  0 148.188 0.192 148.212 ;
    END
  END rsp_data[920]
  PIN rsp_data[921]
    DIRECTION INPUT ;
    USE SIGNAL ;
    PORT
      LAYER M4 ;
        RECT  0 148.428 0.192 148.452 ;
    END
  END rsp_data[921]
  PIN rsp_data[922]
    DIRECTION INPUT ;
    USE SIGNAL ;
    PORT
      LAYER M4 ;
        RECT  0 148.62 0.192 148.644 ;
    END
  END rsp_data[922]
  PIN rsp_data[923]
    DIRECTION INPUT ;
    USE SIGNAL ;
    PORT
      LAYER M4 ;
        RECT  0 148.86 0.192 148.884 ;
    END
  END rsp_data[923]
  PIN rsp_data[924]
    DIRECTION INPUT ;
    USE SIGNAL ;
    PORT
      LAYER M4 ;
        RECT  0 149.052 0.192 149.076 ;
    END
  END rsp_data[924]
  PIN rsp_data[925]
    DIRECTION INPUT ;
    USE SIGNAL ;
    PORT
      LAYER M4 ;
        RECT  0 149.292 0.192 149.316 ;
    END
  END rsp_data[925]
  PIN rsp_data[926]
    DIRECTION INPUT ;
    USE SIGNAL ;
    PORT
      LAYER M4 ;
        RECT  0 149.484 0.192 149.508 ;
    END
  END rsp_data[926]
  PIN rsp_data[927]
    DIRECTION INPUT ;
    USE SIGNAL ;
    PORT
      LAYER M4 ;
        RECT  0 149.724 0.192 149.748 ;
    END
  END rsp_data[927]
  PIN rsp_data[928]
    DIRECTION INPUT ;
    USE SIGNAL ;
    PORT
      LAYER M4 ;
        RECT  0 149.916 0.192 149.94 ;
    END
  END rsp_data[928]
  PIN rsp_data[929]
    DIRECTION INPUT ;
    USE SIGNAL ;
    PORT
      LAYER M4 ;
        RECT  0 150.156 0.192 150.18 ;
    END
  END rsp_data[929]
  PIN rsp_data[930]
    DIRECTION INPUT ;
    USE SIGNAL ;
    PORT
      LAYER M4 ;
        RECT  0 150.348 0.192 150.372 ;
    END
  END rsp_data[930]
  PIN rsp_data[931]
    DIRECTION INPUT ;
    USE SIGNAL ;
    PORT
      LAYER M4 ;
        RECT  0 150.588 0.192 150.612 ;
    END
  END rsp_data[931]
  PIN rsp_data[932]
    DIRECTION INPUT ;
    USE SIGNAL ;
    PORT
      LAYER M4 ;
        RECT  0 150.828 0.192 150.852 ;
    END
  END rsp_data[932]
  PIN rsp_data[933]
    DIRECTION INPUT ;
    USE SIGNAL ;
    PORT
      LAYER M4 ;
        RECT  0 151.02 0.192 151.044 ;
    END
  END rsp_data[933]
  PIN rsp_data[934]
    DIRECTION INPUT ;
    USE SIGNAL ;
    PORT
      LAYER M4 ;
        RECT  0 151.26 0.192 151.284 ;
    END
  END rsp_data[934]
  PIN rsp_data[935]
    DIRECTION INPUT ;
    USE SIGNAL ;
    PORT
      LAYER M4 ;
        RECT  0 151.452 0.192 151.476 ;
    END
  END rsp_data[935]
  PIN rsp_data[936]
    DIRECTION INPUT ;
    USE SIGNAL ;
    PORT
      LAYER M4 ;
        RECT  0 151.692 0.192 151.716 ;
    END
  END rsp_data[936]
  PIN rsp_data[937]
    DIRECTION INPUT ;
    USE SIGNAL ;
    PORT
      LAYER M4 ;
        RECT  0 151.884 0.192 151.908 ;
    END
  END rsp_data[937]
  PIN rsp_data[938]
    DIRECTION INPUT ;
    USE SIGNAL ;
    PORT
      LAYER M4 ;
        RECT  0 152.124 0.192 152.148 ;
    END
  END rsp_data[938]
  PIN rsp_data[939]
    DIRECTION INPUT ;
    USE SIGNAL ;
    PORT
      LAYER M4 ;
        RECT  0 152.316 0.192 152.34 ;
    END
  END rsp_data[939]
  PIN rsp_data[940]
    DIRECTION INPUT ;
    USE SIGNAL ;
    PORT
      LAYER M4 ;
        RECT  0 152.556 0.192 152.58 ;
    END
  END rsp_data[940]
  PIN rsp_data[941]
    DIRECTION INPUT ;
    USE SIGNAL ;
    PORT
      LAYER M4 ;
        RECT  0 152.796 0.192 152.82 ;
    END
  END rsp_data[941]
  PIN rsp_data[942]
    DIRECTION INPUT ;
    USE SIGNAL ;
    PORT
      LAYER M4 ;
        RECT  0 152.988 0.192 153.012 ;
    END
  END rsp_data[942]
  PIN rsp_data[943]
    DIRECTION INPUT ;
    USE SIGNAL ;
    PORT
      LAYER M4 ;
        RECT  0 153.228 0.192 153.252 ;
    END
  END rsp_data[943]
  PIN rsp_data[944]
    DIRECTION INPUT ;
    USE SIGNAL ;
    PORT
      LAYER M4 ;
        RECT  0 153.42 0.192 153.444 ;
    END
  END rsp_data[944]
  PIN rsp_data[945]
    DIRECTION INPUT ;
    USE SIGNAL ;
    PORT
      LAYER M4 ;
        RECT  0 153.66 0.192 153.684 ;
    END
  END rsp_data[945]
  PIN rsp_data[946]
    DIRECTION INPUT ;
    USE SIGNAL ;
    PORT
      LAYER M4 ;
        RECT  0 153.852 0.192 153.876 ;
    END
  END rsp_data[946]
  PIN rsp_data[947]
    DIRECTION INPUT ;
    USE SIGNAL ;
    PORT
      LAYER M4 ;
        RECT  0 154.092 0.192 154.116 ;
    END
  END rsp_data[947]
  PIN rsp_data[948]
    DIRECTION INPUT ;
    USE SIGNAL ;
    PORT
      LAYER M4 ;
        RECT  0 154.284 0.192 154.308 ;
    END
  END rsp_data[948]
  PIN rsp_data[949]
    DIRECTION INPUT ;
    USE SIGNAL ;
    PORT
      LAYER M4 ;
        RECT  0 154.524 0.192 154.548 ;
    END
  END rsp_data[949]
  PIN rsp_data[950]
    DIRECTION INPUT ;
    USE SIGNAL ;
    PORT
      LAYER M4 ;
        RECT  0 154.716 0.192 154.74 ;
    END
  END rsp_data[950]
  PIN rsp_data[951]
    DIRECTION INPUT ;
    USE SIGNAL ;
    PORT
      LAYER M4 ;
        RECT  0 154.956 0.192 154.98 ;
    END
  END rsp_data[951]
  PIN rsp_data[952]
    DIRECTION INPUT ;
    USE SIGNAL ;
    PORT
      LAYER M4 ;
        RECT  0 155.196 0.192 155.22 ;
    END
  END rsp_data[952]
  PIN rsp_data[953]
    DIRECTION INPUT ;
    USE SIGNAL ;
    PORT
      LAYER M4 ;
        RECT  0 155.388 0.192 155.412 ;
    END
  END rsp_data[953]
  PIN rsp_data[954]
    DIRECTION INPUT ;
    USE SIGNAL ;
    PORT
      LAYER M4 ;
        RECT  0 155.628 0.192 155.652 ;
    END
  END rsp_data[954]
  PIN rsp_data[955]
    DIRECTION INPUT ;
    USE SIGNAL ;
    PORT
      LAYER M4 ;
        RECT  0 155.82 0.192 155.844 ;
    END
  END rsp_data[955]
  PIN rsp_data[956]
    DIRECTION INPUT ;
    USE SIGNAL ;
    PORT
      LAYER M4 ;
        RECT  0 156.06 0.192 156.084 ;
    END
  END rsp_data[956]
  PIN rsp_data[957]
    DIRECTION INPUT ;
    USE SIGNAL ;
    PORT
      LAYER M4 ;
        RECT  0 156.252 0.192 156.276 ;
    END
  END rsp_data[957]
  PIN rsp_data[958]
    DIRECTION INPUT ;
    USE SIGNAL ;
    PORT
      LAYER M4 ;
        RECT  0 156.492 0.192 156.516 ;
    END
  END rsp_data[958]
  PIN rsp_data[959]
    DIRECTION INPUT ;
    USE SIGNAL ;
    PORT
      LAYER M4 ;
        RECT  0 156.684 0.192 156.708 ;
    END
  END rsp_data[959]
  PIN rsp_data[960]
    DIRECTION INPUT ;
    USE SIGNAL ;
    PORT
      LAYER M4 ;
        RECT  0 156.924 0.192 156.948 ;
    END
  END rsp_data[960]
  PIN rsp_data[961]
    DIRECTION INPUT ;
    USE SIGNAL ;
    PORT
      LAYER M4 ;
        RECT  0 157.116 0.192 157.14 ;
    END
  END rsp_data[961]
  PIN rsp_data[962]
    DIRECTION INPUT ;
    USE SIGNAL ;
    PORT
      LAYER M4 ;
        RECT  0 157.356 0.192 157.38 ;
    END
  END rsp_data[962]
  PIN rsp_data[963]
    DIRECTION INPUT ;
    USE SIGNAL ;
    PORT
      LAYER M4 ;
        RECT  0 157.596 0.192 157.62 ;
    END
  END rsp_data[963]
  PIN rsp_data[964]
    DIRECTION INPUT ;
    USE SIGNAL ;
    PORT
      LAYER M4 ;
        RECT  0 157.788 0.192 157.812 ;
    END
  END rsp_data[964]
  PIN rsp_data[965]
    DIRECTION INPUT ;
    USE SIGNAL ;
    PORT
      LAYER M4 ;
        RECT  0 158.028 0.192 158.052 ;
    END
  END rsp_data[965]
  PIN rsp_data[966]
    DIRECTION INPUT ;
    USE SIGNAL ;
    PORT
      LAYER M4 ;
        RECT  0 158.22 0.192 158.244 ;
    END
  END rsp_data[966]
  PIN rsp_data[967]
    DIRECTION INPUT ;
    USE SIGNAL ;
    PORT
      LAYER M4 ;
        RECT  0 158.46 0.192 158.484 ;
    END
  END rsp_data[967]
  PIN rsp_data[968]
    DIRECTION INPUT ;
    USE SIGNAL ;
    PORT
      LAYER M4 ;
        RECT  0 158.652 0.192 158.676 ;
    END
  END rsp_data[968]
  PIN rsp_data[969]
    DIRECTION INPUT ;
    USE SIGNAL ;
    PORT
      LAYER M4 ;
        RECT  0 158.892 0.192 158.916 ;
    END
  END rsp_data[969]
  PIN rsp_data[970]
    DIRECTION INPUT ;
    USE SIGNAL ;
    PORT
      LAYER M4 ;
        RECT  0 159.084 0.192 159.108 ;
    END
  END rsp_data[970]
  PIN rsp_data[971]
    DIRECTION INPUT ;
    USE SIGNAL ;
    PORT
      LAYER M4 ;
        RECT  0 159.324 0.192 159.348 ;
    END
  END rsp_data[971]
  PIN rsp_data[972]
    DIRECTION INPUT ;
    USE SIGNAL ;
    PORT
      LAYER M4 ;
        RECT  0 159.564 0.192 159.588 ;
    END
  END rsp_data[972]
  PIN rsp_data[973]
    DIRECTION INPUT ;
    USE SIGNAL ;
    PORT
      LAYER M4 ;
        RECT  0 159.756 0.192 159.78 ;
    END
  END rsp_data[973]
  PIN rsp_data[974]
    DIRECTION INPUT ;
    USE SIGNAL ;
    PORT
      LAYER M4 ;
        RECT  0 159.996 0.192 160.02 ;
    END
  END rsp_data[974]
  PIN rsp_data[975]
    DIRECTION INPUT ;
    USE SIGNAL ;
    PORT
      LAYER M4 ;
        RECT  0 160.188 0.192 160.212 ;
    END
  END rsp_data[975]
  PIN rsp_data[976]
    DIRECTION INPUT ;
    USE SIGNAL ;
    PORT
      LAYER M4 ;
        RECT  0 160.428 0.192 160.452 ;
    END
  END rsp_data[976]
  PIN rsp_data[977]
    DIRECTION INPUT ;
    USE SIGNAL ;
    PORT
      LAYER M4 ;
        RECT  0 160.62 0.192 160.644 ;
    END
  END rsp_data[977]
  PIN rsp_data[978]
    DIRECTION INPUT ;
    USE SIGNAL ;
    PORT
      LAYER M4 ;
        RECT  0 160.86 0.192 160.884 ;
    END
  END rsp_data[978]
  PIN rsp_data[979]
    DIRECTION INPUT ;
    USE SIGNAL ;
    PORT
      LAYER M4 ;
        RECT  0 161.052 0.192 161.076 ;
    END
  END rsp_data[979]
  PIN rsp_data[980]
    DIRECTION INPUT ;
    USE SIGNAL ;
    PORT
      LAYER M4 ;
        RECT  0 161.292 0.192 161.316 ;
    END
  END rsp_data[980]
  PIN rsp_data[981]
    DIRECTION INPUT ;
    USE SIGNAL ;
    PORT
      LAYER M4 ;
        RECT  0 161.484 0.192 161.508 ;
    END
  END rsp_data[981]
  PIN rsp_data[982]
    DIRECTION INPUT ;
    USE SIGNAL ;
    PORT
      LAYER M4 ;
        RECT  0 161.724 0.192 161.748 ;
    END
  END rsp_data[982]
  PIN rsp_data[983]
    DIRECTION INPUT ;
    USE SIGNAL ;
    PORT
      LAYER M4 ;
        RECT  0 161.964 0.192 161.988 ;
    END
  END rsp_data[983]
  PIN rsp_data[984]
    DIRECTION INPUT ;
    USE SIGNAL ;
    PORT
      LAYER M4 ;
        RECT  0 162.156 0.192 162.18 ;
    END
  END rsp_data[984]
  PIN rsp_data[985]
    DIRECTION INPUT ;
    USE SIGNAL ;
    PORT
      LAYER M4 ;
        RECT  0 162.396 0.192 162.42 ;
    END
  END rsp_data[985]
  PIN rsp_data[986]
    DIRECTION INPUT ;
    USE SIGNAL ;
    PORT
      LAYER M4 ;
        RECT  0 162.588 0.192 162.612 ;
    END
  END rsp_data[986]
  PIN rsp_data[987]
    DIRECTION INPUT ;
    USE SIGNAL ;
    PORT
      LAYER M4 ;
        RECT  0 162.828 0.192 162.852 ;
    END
  END rsp_data[987]
  PIN rsp_data[988]
    DIRECTION INPUT ;
    USE SIGNAL ;
    PORT
      LAYER M4 ;
        RECT  0 163.02 0.192 163.044 ;
    END
  END rsp_data[988]
  PIN rsp_data[989]
    DIRECTION INPUT ;
    USE SIGNAL ;
    PORT
      LAYER M4 ;
        RECT  0 163.26 0.192 163.284 ;
    END
  END rsp_data[989]
  PIN rsp_data[990]
    DIRECTION INPUT ;
    USE SIGNAL ;
    PORT
      LAYER M4 ;
        RECT  0 163.452 0.192 163.476 ;
    END
  END rsp_data[990]
  PIN rsp_data[991]
    DIRECTION INPUT ;
    USE SIGNAL ;
    PORT
      LAYER M4 ;
        RECT  0 163.692 0.192 163.716 ;
    END
  END rsp_data[991]
  PIN rsp_data[992]
    DIRECTION INPUT ;
    USE SIGNAL ;
    PORT
      LAYER M4 ;
        RECT  0 163.932 0.192 163.956 ;
    END
  END rsp_data[992]
  PIN rsp_data[993]
    DIRECTION INPUT ;
    USE SIGNAL ;
    PORT
      LAYER M4 ;
        RECT  0 164.124 0.192 164.148 ;
    END
  END rsp_data[993]
  PIN rsp_data[994]
    DIRECTION INPUT ;
    USE SIGNAL ;
    PORT
      LAYER M4 ;
        RECT  0 164.364 0.192 164.388 ;
    END
  END rsp_data[994]
  PIN rsp_data[995]
    DIRECTION INPUT ;
    USE SIGNAL ;
    PORT
      LAYER M4 ;
        RECT  0 164.556 0.192 164.58 ;
    END
  END rsp_data[995]
  PIN rsp_data[996]
    DIRECTION INPUT ;
    USE SIGNAL ;
    PORT
      LAYER M4 ;
        RECT  0 164.796 0.192 164.82 ;
    END
  END rsp_data[996]
  PIN rsp_data[997]
    DIRECTION INPUT ;
    USE SIGNAL ;
    PORT
      LAYER M4 ;
        RECT  0 164.988 0.192 165.012 ;
    END
  END rsp_data[997]
  PIN rsp_data[998]
    DIRECTION INPUT ;
    USE SIGNAL ;
    PORT
      LAYER M4 ;
        RECT  0 165.228 0.192 165.252 ;
    END
  END rsp_data[998]
  PIN rsp_data[999]
    DIRECTION INPUT ;
    USE SIGNAL ;
    PORT
      LAYER M4 ;
        RECT  0 165.42 0.192 165.444 ;
    END
  END rsp_data[999]
  PIN rst_n[0]
    DIRECTION INPUT ;
    USE SIGNAL ;
    PORT
      LAYER M5 ;
        RECT  108.396 86.304 108.42 86.496 ;
    END
  END rst_n[0]
  PIN si[0]
    DIRECTION INPUT ;
    USE SIGNAL ;
    PORT
      LAYER M4 ;
        RECT  243.456 2.268 243.648 2.292 ;
    END
  END si[0]
  PIN si[100]
    DIRECTION INPUT ;
    USE SIGNAL ;
    PORT
      LAYER M4 ;
        RECT  243.456 61.932 243.648 61.956 ;
    END
  END si[100]
  PIN si[101]
    DIRECTION INPUT ;
    USE SIGNAL ;
    PORT
      LAYER M4 ;
        RECT  243.456 62.508 243.648 62.532 ;
    END
  END si[101]
  PIN si[102]
    DIRECTION INPUT ;
    USE SIGNAL ;
    PORT
      LAYER M4 ;
        RECT  243.456 63.132 243.648 63.156 ;
    END
  END si[102]
  PIN si[103]
    DIRECTION INPUT ;
    USE SIGNAL ;
    PORT
      LAYER M4 ;
        RECT  243.456 63.708 243.648 63.732 ;
    END
  END si[103]
  PIN si[104]
    DIRECTION INPUT ;
    USE SIGNAL ;
    PORT
      LAYER M4 ;
        RECT  243.456 64.332 243.648 64.356 ;
    END
  END si[104]
  PIN si[105]
    DIRECTION INPUT ;
    USE SIGNAL ;
    PORT
      LAYER M4 ;
        RECT  243.456 64.908 243.648 64.932 ;
    END
  END si[105]
  PIN si[106]
    DIRECTION INPUT ;
    USE SIGNAL ;
    PORT
      LAYER M4 ;
        RECT  243.456 65.532 243.648 65.556 ;
    END
  END si[106]
  PIN si[107]
    DIRECTION INPUT ;
    USE SIGNAL ;
    PORT
      LAYER M4 ;
        RECT  243.456 66.108 243.648 66.132 ;
    END
  END si[107]
  PIN si[108]
    DIRECTION INPUT ;
    USE SIGNAL ;
    PORT
      LAYER M4 ;
        RECT  243.456 66.684 243.648 66.708 ;
    END
  END si[108]
  PIN si[109]
    DIRECTION INPUT ;
    USE SIGNAL ;
    PORT
      LAYER M4 ;
        RECT  243.456 67.308 243.648 67.332 ;
    END
  END si[109]
  PIN si[10]
    DIRECTION INPUT ;
    USE SIGNAL ;
    PORT
      LAYER M4 ;
        RECT  243.456 8.268 243.648 8.292 ;
    END
  END si[10]
  PIN si[110]
    DIRECTION INPUT ;
    USE SIGNAL ;
    PORT
      LAYER M4 ;
        RECT  243.456 67.884 243.648 67.908 ;
    END
  END si[110]
  PIN si[111]
    DIRECTION INPUT ;
    USE SIGNAL ;
    PORT
      LAYER M4 ;
        RECT  243.456 68.508 243.648 68.532 ;
    END
  END si[111]
  PIN si[112]
    DIRECTION INPUT ;
    USE SIGNAL ;
    PORT
      LAYER M4 ;
        RECT  243.456 69.084 243.648 69.108 ;
    END
  END si[112]
  PIN si[113]
    DIRECTION INPUT ;
    USE SIGNAL ;
    PORT
      LAYER M4 ;
        RECT  243.456 69.708 243.648 69.732 ;
    END
  END si[113]
  PIN si[114]
    DIRECTION INPUT ;
    USE SIGNAL ;
    PORT
      LAYER M4 ;
        RECT  243.456 70.284 243.648 70.308 ;
    END
  END si[114]
  PIN si[115]
    DIRECTION INPUT ;
    USE SIGNAL ;
    PORT
      LAYER M4 ;
        RECT  243.456 70.86 243.648 70.884 ;
    END
  END si[115]
  PIN si[116]
    DIRECTION INPUT ;
    USE SIGNAL ;
    PORT
      LAYER M4 ;
        RECT  243.456 71.484 243.648 71.508 ;
    END
  END si[116]
  PIN si[117]
    DIRECTION INPUT ;
    USE SIGNAL ;
    PORT
      LAYER M4 ;
        RECT  243.456 72.06 243.648 72.084 ;
    END
  END si[117]
  PIN si[118]
    DIRECTION INPUT ;
    USE SIGNAL ;
    PORT
      LAYER M4 ;
        RECT  243.456 72.684 243.648 72.708 ;
    END
  END si[118]
  PIN si[119]
    DIRECTION INPUT ;
    USE SIGNAL ;
    PORT
      LAYER M4 ;
        RECT  243.456 73.26 243.648 73.284 ;
    END
  END si[119]
  PIN si[11]
    DIRECTION INPUT ;
    USE SIGNAL ;
    PORT
      LAYER M4 ;
        RECT  243.456 8.844 243.648 8.868 ;
    END
  END si[11]
  PIN si[120]
    DIRECTION INPUT ;
    USE SIGNAL ;
    PORT
      LAYER M4 ;
        RECT  243.456 73.884 243.648 73.908 ;
    END
  END si[120]
  PIN si[121]
    DIRECTION INPUT ;
    USE SIGNAL ;
    PORT
      LAYER M4 ;
        RECT  243.456 74.46 243.648 74.484 ;
    END
  END si[121]
  PIN si[122]
    DIRECTION INPUT ;
    USE SIGNAL ;
    PORT
      LAYER M4 ;
        RECT  243.456 75.036 243.648 75.06 ;
    END
  END si[122]
  PIN si[123]
    DIRECTION INPUT ;
    USE SIGNAL ;
    PORT
      LAYER M4 ;
        RECT  243.456 75.66 243.648 75.684 ;
    END
  END si[123]
  PIN si[124]
    DIRECTION INPUT ;
    USE SIGNAL ;
    PORT
      LAYER M4 ;
        RECT  243.456 76.236 243.648 76.26 ;
    END
  END si[124]
  PIN si[125]
    DIRECTION INPUT ;
    USE SIGNAL ;
    PORT
      LAYER M4 ;
        RECT  243.456 76.86 243.648 76.884 ;
    END
  END si[125]
  PIN si[126]
    DIRECTION INPUT ;
    USE SIGNAL ;
    PORT
      LAYER M4 ;
        RECT  243.456 77.436 243.648 77.46 ;
    END
  END si[126]
  PIN si[127]
    DIRECTION INPUT ;
    USE SIGNAL ;
    PORT
      LAYER M4 ;
        RECT  243.456 78.06 243.648 78.084 ;
    END
  END si[127]
  PIN si[128]
    DIRECTION INPUT ;
    USE SIGNAL ;
    PORT
      LAYER M4 ;
        RECT  243.456 78.636 243.648 78.66 ;
    END
  END si[128]
  PIN si[129]
    DIRECTION INPUT ;
    USE SIGNAL ;
    PORT
      LAYER M4 ;
        RECT  243.456 79.212 243.648 79.236 ;
    END
  END si[129]
  PIN si[12]
    DIRECTION INPUT ;
    USE SIGNAL ;
    PORT
      LAYER M4 ;
        RECT  243.456 9.42 243.648 9.444 ;
    END
  END si[12]
  PIN si[130]
    DIRECTION INPUT ;
    USE SIGNAL ;
    PORT
      LAYER M4 ;
        RECT  243.456 79.836 243.648 79.86 ;
    END
  END si[130]
  PIN si[131]
    DIRECTION INPUT ;
    USE SIGNAL ;
    PORT
      LAYER M4 ;
        RECT  243.456 80.412 243.648 80.436 ;
    END
  END si[131]
  PIN si[132]
    DIRECTION INPUT ;
    USE SIGNAL ;
    PORT
      LAYER M4 ;
        RECT  243.456 81.036 243.648 81.06 ;
    END
  END si[132]
  PIN si[133]
    DIRECTION INPUT ;
    USE SIGNAL ;
    PORT
      LAYER M4 ;
        RECT  243.456 81.612 243.648 81.636 ;
    END
  END si[133]
  PIN si[134]
    DIRECTION INPUT ;
    USE SIGNAL ;
    PORT
      LAYER M4 ;
        RECT  243.456 82.236 243.648 82.26 ;
    END
  END si[134]
  PIN si[135]
    DIRECTION INPUT ;
    USE SIGNAL ;
    PORT
      LAYER M4 ;
        RECT  243.456 82.812 243.648 82.836 ;
    END
  END si[135]
  PIN si[136]
    DIRECTION INPUT ;
    USE SIGNAL ;
    PORT
      LAYER M4 ;
        RECT  243.456 83.388 243.648 83.412 ;
    END
  END si[136]
  PIN si[137]
    DIRECTION INPUT ;
    USE SIGNAL ;
    PORT
      LAYER M4 ;
        RECT  243.456 84.012 243.648 84.036 ;
    END
  END si[137]
  PIN si[138]
    DIRECTION INPUT ;
    USE SIGNAL ;
    PORT
      LAYER M4 ;
        RECT  243.456 84.588 243.648 84.612 ;
    END
  END si[138]
  PIN si[139]
    DIRECTION INPUT ;
    USE SIGNAL ;
    PORT
      LAYER M4 ;
        RECT  243.456 85.212 243.648 85.236 ;
    END
  END si[139]
  PIN si[13]
    DIRECTION INPUT ;
    USE SIGNAL ;
    PORT
      LAYER M4 ;
        RECT  243.456 10.044 243.648 10.068 ;
    END
  END si[13]
  PIN si[140]
    DIRECTION INPUT ;
    USE SIGNAL ;
    PORT
      LAYER M4 ;
        RECT  243.456 85.788 243.648 85.812 ;
    END
  END si[140]
  PIN si[141]
    DIRECTION INPUT ;
    USE SIGNAL ;
    PORT
      LAYER M4 ;
        RECT  243.456 86.412 243.648 86.436 ;
    END
  END si[141]
  PIN si[142]
    DIRECTION INPUT ;
    USE SIGNAL ;
    PORT
      LAYER M4 ;
        RECT  243.456 86.988 243.648 87.012 ;
    END
  END si[142]
  PIN si[143]
    DIRECTION INPUT ;
    USE SIGNAL ;
    PORT
      LAYER M4 ;
        RECT  243.456 87.564 243.648 87.588 ;
    END
  END si[143]
  PIN si[144]
    DIRECTION INPUT ;
    USE SIGNAL ;
    PORT
      LAYER M4 ;
        RECT  243.456 88.188 243.648 88.212 ;
    END
  END si[144]
  PIN si[145]
    DIRECTION INPUT ;
    USE SIGNAL ;
    PORT
      LAYER M4 ;
        RECT  243.456 88.764 243.648 88.788 ;
    END
  END si[145]
  PIN si[146]
    DIRECTION INPUT ;
    USE SIGNAL ;
    PORT
      LAYER M4 ;
        RECT  243.456 89.388 243.648 89.412 ;
    END
  END si[146]
  PIN si[147]
    DIRECTION INPUT ;
    USE SIGNAL ;
    PORT
      LAYER M4 ;
        RECT  243.456 89.964 243.648 89.988 ;
    END
  END si[147]
  PIN si[148]
    DIRECTION INPUT ;
    USE SIGNAL ;
    PORT
      LAYER M4 ;
        RECT  243.456 90.54 243.648 90.564 ;
    END
  END si[148]
  PIN si[149]
    DIRECTION INPUT ;
    USE SIGNAL ;
    PORT
      LAYER M4 ;
        RECT  243.456 91.164 243.648 91.188 ;
    END
  END si[149]
  PIN si[14]
    DIRECTION INPUT ;
    USE SIGNAL ;
    PORT
      LAYER M4 ;
        RECT  243.456 10.62 243.648 10.644 ;
    END
  END si[14]
  PIN si[150]
    DIRECTION INPUT ;
    USE SIGNAL ;
    PORT
      LAYER M4 ;
        RECT  243.456 91.74 243.648 91.764 ;
    END
  END si[150]
  PIN si[151]
    DIRECTION INPUT ;
    USE SIGNAL ;
    PORT
      LAYER M4 ;
        RECT  243.456 92.364 243.648 92.388 ;
    END
  END si[151]
  PIN si[152]
    DIRECTION INPUT ;
    USE SIGNAL ;
    PORT
      LAYER M4 ;
        RECT  243.456 92.94 243.648 92.964 ;
    END
  END si[152]
  PIN si[153]
    DIRECTION INPUT ;
    USE SIGNAL ;
    PORT
      LAYER M4 ;
        RECT  243.456 93.564 243.648 93.588 ;
    END
  END si[153]
  PIN si[154]
    DIRECTION INPUT ;
    USE SIGNAL ;
    PORT
      LAYER M4 ;
        RECT  243.456 94.14 243.648 94.164 ;
    END
  END si[154]
  PIN si[155]
    DIRECTION INPUT ;
    USE SIGNAL ;
    PORT
      LAYER M4 ;
        RECT  243.456 94.716 243.648 94.74 ;
    END
  END si[155]
  PIN si[156]
    DIRECTION INPUT ;
    USE SIGNAL ;
    PORT
      LAYER M4 ;
        RECT  243.456 95.34 243.648 95.364 ;
    END
  END si[156]
  PIN si[157]
    DIRECTION INPUT ;
    USE SIGNAL ;
    PORT
      LAYER M4 ;
        RECT  243.456 95.916 243.648 95.94 ;
    END
  END si[157]
  PIN si[158]
    DIRECTION INPUT ;
    USE SIGNAL ;
    PORT
      LAYER M4 ;
        RECT  243.456 96.54 243.648 96.564 ;
    END
  END si[158]
  PIN si[159]
    DIRECTION INPUT ;
    USE SIGNAL ;
    PORT
      LAYER M4 ;
        RECT  243.456 97.116 243.648 97.14 ;
    END
  END si[159]
  PIN si[15]
    DIRECTION INPUT ;
    USE SIGNAL ;
    PORT
      LAYER M4 ;
        RECT  243.456 11.244 243.648 11.268 ;
    END
  END si[15]
  PIN si[160]
    DIRECTION INPUT ;
    USE SIGNAL ;
    PORT
      LAYER M4 ;
        RECT  243.456 97.74 243.648 97.764 ;
    END
  END si[160]
  PIN si[161]
    DIRECTION INPUT ;
    USE SIGNAL ;
    PORT
      LAYER M4 ;
        RECT  243.456 98.316 243.648 98.34 ;
    END
  END si[161]
  PIN si[162]
    DIRECTION INPUT ;
    USE SIGNAL ;
    PORT
      LAYER M4 ;
        RECT  243.456 98.892 243.648 98.916 ;
    END
  END si[162]
  PIN si[163]
    DIRECTION INPUT ;
    USE SIGNAL ;
    PORT
      LAYER M4 ;
        RECT  243.456 99.516 243.648 99.54 ;
    END
  END si[163]
  PIN si[164]
    DIRECTION INPUT ;
    USE SIGNAL ;
    PORT
      LAYER M4 ;
        RECT  243.456 100.092 243.648 100.116 ;
    END
  END si[164]
  PIN si[165]
    DIRECTION INPUT ;
    USE SIGNAL ;
    PORT
      LAYER M4 ;
        RECT  243.456 100.716 243.648 100.74 ;
    END
  END si[165]
  PIN si[166]
    DIRECTION INPUT ;
    USE SIGNAL ;
    PORT
      LAYER M4 ;
        RECT  243.456 101.292 243.648 101.316 ;
    END
  END si[166]
  PIN si[167]
    DIRECTION INPUT ;
    USE SIGNAL ;
    PORT
      LAYER M4 ;
        RECT  243.456 101.916 243.648 101.94 ;
    END
  END si[167]
  PIN si[168]
    DIRECTION INPUT ;
    USE SIGNAL ;
    PORT
      LAYER M4 ;
        RECT  243.456 102.492 243.648 102.516 ;
    END
  END si[168]
  PIN si[169]
    DIRECTION INPUT ;
    USE SIGNAL ;
    PORT
      LAYER M4 ;
        RECT  243.456 103.068 243.648 103.092 ;
    END
  END si[169]
  PIN si[16]
    DIRECTION INPUT ;
    USE SIGNAL ;
    PORT
      LAYER M4 ;
        RECT  243.456 11.82 243.648 11.844 ;
    END
  END si[16]
  PIN si[170]
    DIRECTION INPUT ;
    USE SIGNAL ;
    PORT
      LAYER M4 ;
        RECT  243.456 103.692 243.648 103.716 ;
    END
  END si[170]
  PIN si[171]
    DIRECTION INPUT ;
    USE SIGNAL ;
    PORT
      LAYER M4 ;
        RECT  243.456 104.268 243.648 104.292 ;
    END
  END si[171]
  PIN si[172]
    DIRECTION INPUT ;
    USE SIGNAL ;
    PORT
      LAYER M4 ;
        RECT  243.456 104.892 243.648 104.916 ;
    END
  END si[172]
  PIN si[173]
    DIRECTION INPUT ;
    USE SIGNAL ;
    PORT
      LAYER M4 ;
        RECT  243.456 105.468 243.648 105.492 ;
    END
  END si[173]
  PIN si[174]
    DIRECTION INPUT ;
    USE SIGNAL ;
    PORT
      LAYER M4 ;
        RECT  243.456 106.092 243.648 106.116 ;
    END
  END si[174]
  PIN si[175]
    DIRECTION INPUT ;
    USE SIGNAL ;
    PORT
      LAYER M4 ;
        RECT  243.456 106.668 243.648 106.692 ;
    END
  END si[175]
  PIN si[176]
    DIRECTION INPUT ;
    USE SIGNAL ;
    PORT
      LAYER M4 ;
        RECT  243.456 107.244 243.648 107.268 ;
    END
  END si[176]
  PIN si[177]
    DIRECTION INPUT ;
    USE SIGNAL ;
    PORT
      LAYER M4 ;
        RECT  243.456 107.868 243.648 107.892 ;
    END
  END si[177]
  PIN si[178]
    DIRECTION INPUT ;
    USE SIGNAL ;
    PORT
      LAYER M4 ;
        RECT  243.456 108.444 243.648 108.468 ;
    END
  END si[178]
  PIN si[179]
    DIRECTION INPUT ;
    USE SIGNAL ;
    PORT
      LAYER M4 ;
        RECT  243.456 109.068 243.648 109.092 ;
    END
  END si[179]
  PIN si[17]
    DIRECTION INPUT ;
    USE SIGNAL ;
    PORT
      LAYER M4 ;
        RECT  243.456 12.444 243.648 12.468 ;
    END
  END si[17]
  PIN si[180]
    DIRECTION INPUT ;
    USE SIGNAL ;
    PORT
      LAYER M4 ;
        RECT  243.456 109.644 243.648 109.668 ;
    END
  END si[180]
  PIN si[181]
    DIRECTION INPUT ;
    USE SIGNAL ;
    PORT
      LAYER M4 ;
        RECT  243.456 110.268 243.648 110.292 ;
    END
  END si[181]
  PIN si[182]
    DIRECTION INPUT ;
    USE SIGNAL ;
    PORT
      LAYER M4 ;
        RECT  243.456 110.844 243.648 110.868 ;
    END
  END si[182]
  PIN si[183]
    DIRECTION INPUT ;
    USE SIGNAL ;
    PORT
      LAYER M4 ;
        RECT  243.456 111.42 243.648 111.444 ;
    END
  END si[183]
  PIN si[184]
    DIRECTION INPUT ;
    USE SIGNAL ;
    PORT
      LAYER M4 ;
        RECT  243.456 112.044 243.648 112.068 ;
    END
  END si[184]
  PIN si[185]
    DIRECTION INPUT ;
    USE SIGNAL ;
    PORT
      LAYER M4 ;
        RECT  243.456 112.62 243.648 112.644 ;
    END
  END si[185]
  PIN si[186]
    DIRECTION INPUT ;
    USE SIGNAL ;
    PORT
      LAYER M4 ;
        RECT  243.456 113.244 243.648 113.268 ;
    END
  END si[186]
  PIN si[187]
    DIRECTION INPUT ;
    USE SIGNAL ;
    PORT
      LAYER M4 ;
        RECT  243.456 113.82 243.648 113.844 ;
    END
  END si[187]
  PIN si[188]
    DIRECTION INPUT ;
    USE SIGNAL ;
    PORT
      LAYER M4 ;
        RECT  243.456 114.444 243.648 114.468 ;
    END
  END si[188]
  PIN si[189]
    DIRECTION INPUT ;
    USE SIGNAL ;
    PORT
      LAYER M4 ;
        RECT  243.456 115.02 243.648 115.044 ;
    END
  END si[189]
  PIN si[18]
    DIRECTION INPUT ;
    USE SIGNAL ;
    PORT
      LAYER M4 ;
        RECT  243.456 13.02 243.648 13.044 ;
    END
  END si[18]
  PIN si[190]
    DIRECTION INPUT ;
    USE SIGNAL ;
    PORT
      LAYER M4 ;
        RECT  243.456 115.596 243.648 115.62 ;
    END
  END si[190]
  PIN si[191]
    DIRECTION INPUT ;
    USE SIGNAL ;
    PORT
      LAYER M4 ;
        RECT  243.456 116.22 243.648 116.244 ;
    END
  END si[191]
  PIN si[192]
    DIRECTION INPUT ;
    USE SIGNAL ;
    PORT
      LAYER M4 ;
        RECT  243.456 116.796 243.648 116.82 ;
    END
  END si[192]
  PIN si[193]
    DIRECTION INPUT ;
    USE SIGNAL ;
    PORT
      LAYER M4 ;
        RECT  243.456 117.42 243.648 117.444 ;
    END
  END si[193]
  PIN si[194]
    DIRECTION INPUT ;
    USE SIGNAL ;
    PORT
      LAYER M4 ;
        RECT  243.456 117.996 243.648 118.02 ;
    END
  END si[194]
  PIN si[195]
    DIRECTION INPUT ;
    USE SIGNAL ;
    PORT
      LAYER M4 ;
        RECT  243.456 118.62 243.648 118.644 ;
    END
  END si[195]
  PIN si[196]
    DIRECTION INPUT ;
    USE SIGNAL ;
    PORT
      LAYER M4 ;
        RECT  243.456 119.196 243.648 119.22 ;
    END
  END si[196]
  PIN si[197]
    DIRECTION INPUT ;
    USE SIGNAL ;
    PORT
      LAYER M4 ;
        RECT  243.456 119.772 243.648 119.796 ;
    END
  END si[197]
  PIN si[198]
    DIRECTION INPUT ;
    USE SIGNAL ;
    PORT
      LAYER M4 ;
        RECT  243.456 120.396 243.648 120.42 ;
    END
  END si[198]
  PIN si[199]
    DIRECTION INPUT ;
    USE SIGNAL ;
    PORT
      LAYER M4 ;
        RECT  243.456 120.972 243.648 120.996 ;
    END
  END si[199]
  PIN si[19]
    DIRECTION INPUT ;
    USE SIGNAL ;
    PORT
      LAYER M4 ;
        RECT  243.456 13.596 243.648 13.62 ;
    END
  END si[19]
  PIN si[1]
    DIRECTION INPUT ;
    USE SIGNAL ;
    PORT
      LAYER M4 ;
        RECT  243.456 2.892 243.648 2.916 ;
    END
  END si[1]
  PIN si[200]
    DIRECTION INPUT ;
    USE SIGNAL ;
    PORT
      LAYER M4 ;
        RECT  243.456 121.596 243.648 121.62 ;
    END
  END si[200]
  PIN si[201]
    DIRECTION INPUT ;
    USE SIGNAL ;
    PORT
      LAYER M4 ;
        RECT  243.456 122.172 243.648 122.196 ;
    END
  END si[201]
  PIN si[202]
    DIRECTION INPUT ;
    USE SIGNAL ;
    PORT
      LAYER M4 ;
        RECT  243.456 122.796 243.648 122.82 ;
    END
  END si[202]
  PIN si[203]
    DIRECTION INPUT ;
    USE SIGNAL ;
    PORT
      LAYER M4 ;
        RECT  243.456 123.372 243.648 123.396 ;
    END
  END si[203]
  PIN si[204]
    DIRECTION INPUT ;
    USE SIGNAL ;
    PORT
      LAYER M4 ;
        RECT  243.456 123.948 243.648 123.972 ;
    END
  END si[204]
  PIN si[205]
    DIRECTION INPUT ;
    USE SIGNAL ;
    PORT
      LAYER M4 ;
        RECT  243.456 124.572 243.648 124.596 ;
    END
  END si[205]
  PIN si[206]
    DIRECTION INPUT ;
    USE SIGNAL ;
    PORT
      LAYER M4 ;
        RECT  243.456 125.148 243.648 125.172 ;
    END
  END si[206]
  PIN si[207]
    DIRECTION INPUT ;
    USE SIGNAL ;
    PORT
      LAYER M4 ;
        RECT  243.456 125.772 243.648 125.796 ;
    END
  END si[207]
  PIN si[208]
    DIRECTION INPUT ;
    USE SIGNAL ;
    PORT
      LAYER M4 ;
        RECT  243.456 126.348 243.648 126.372 ;
    END
  END si[208]
  PIN si[209]
    DIRECTION INPUT ;
    USE SIGNAL ;
    PORT
      LAYER M4 ;
        RECT  243.456 126.924 243.648 126.948 ;
    END
  END si[209]
  PIN si[20]
    DIRECTION INPUT ;
    USE SIGNAL ;
    PORT
      LAYER M4 ;
        RECT  243.456 14.22 243.648 14.244 ;
    END
  END si[20]
  PIN si[210]
    DIRECTION INPUT ;
    USE SIGNAL ;
    PORT
      LAYER M4 ;
        RECT  243.456 127.548 243.648 127.572 ;
    END
  END si[210]
  PIN si[211]
    DIRECTION INPUT ;
    USE SIGNAL ;
    PORT
      LAYER M4 ;
        RECT  243.456 128.124 243.648 128.148 ;
    END
  END si[211]
  PIN si[212]
    DIRECTION INPUT ;
    USE SIGNAL ;
    PORT
      LAYER M4 ;
        RECT  243.456 128.748 243.648 128.772 ;
    END
  END si[212]
  PIN si[213]
    DIRECTION INPUT ;
    USE SIGNAL ;
    PORT
      LAYER M4 ;
        RECT  243.456 129.324 243.648 129.348 ;
    END
  END si[213]
  PIN si[214]
    DIRECTION INPUT ;
    USE SIGNAL ;
    PORT
      LAYER M4 ;
        RECT  243.456 129.948 243.648 129.972 ;
    END
  END si[214]
  PIN si[215]
    DIRECTION INPUT ;
    USE SIGNAL ;
    PORT
      LAYER M4 ;
        RECT  243.456 130.524 243.648 130.548 ;
    END
  END si[215]
  PIN si[216]
    DIRECTION INPUT ;
    USE SIGNAL ;
    PORT
      LAYER M4 ;
        RECT  243.456 131.1 243.648 131.124 ;
    END
  END si[216]
  PIN si[217]
    DIRECTION INPUT ;
    USE SIGNAL ;
    PORT
      LAYER M4 ;
        RECT  243.456 131.724 243.648 131.748 ;
    END
  END si[217]
  PIN si[218]
    DIRECTION INPUT ;
    USE SIGNAL ;
    PORT
      LAYER M4 ;
        RECT  243.456 132.3 243.648 132.324 ;
    END
  END si[218]
  PIN si[219]
    DIRECTION INPUT ;
    USE SIGNAL ;
    PORT
      LAYER M4 ;
        RECT  243.456 132.924 243.648 132.948 ;
    END
  END si[219]
  PIN si[21]
    DIRECTION INPUT ;
    USE SIGNAL ;
    PORT
      LAYER M4 ;
        RECT  243.456 14.796 243.648 14.82 ;
    END
  END si[21]
  PIN si[220]
    DIRECTION INPUT ;
    USE SIGNAL ;
    PORT
      LAYER M4 ;
        RECT  243.456 133.5 243.648 133.524 ;
    END
  END si[220]
  PIN si[221]
    DIRECTION INPUT ;
    USE SIGNAL ;
    PORT
      LAYER M4 ;
        RECT  243.456 134.124 243.648 134.148 ;
    END
  END si[221]
  PIN si[222]
    DIRECTION INPUT ;
    USE SIGNAL ;
    PORT
      LAYER M4 ;
        RECT  243.456 134.7 243.648 134.724 ;
    END
  END si[222]
  PIN si[223]
    DIRECTION INPUT ;
    USE SIGNAL ;
    PORT
      LAYER M4 ;
        RECT  243.456 135.276 243.648 135.3 ;
    END
  END si[223]
  PIN si[224]
    DIRECTION INPUT ;
    USE SIGNAL ;
    PORT
      LAYER M4 ;
        RECT  243.456 135.9 243.648 135.924 ;
    END
  END si[224]
  PIN si[225]
    DIRECTION INPUT ;
    USE SIGNAL ;
    PORT
      LAYER M4 ;
        RECT  243.456 136.476 243.648 136.5 ;
    END
  END si[225]
  PIN si[226]
    DIRECTION INPUT ;
    USE SIGNAL ;
    PORT
      LAYER M4 ;
        RECT  243.456 137.1 243.648 137.124 ;
    END
  END si[226]
  PIN si[227]
    DIRECTION INPUT ;
    USE SIGNAL ;
    PORT
      LAYER M4 ;
        RECT  243.456 137.676 243.648 137.7 ;
    END
  END si[227]
  PIN si[228]
    DIRECTION INPUT ;
    USE SIGNAL ;
    PORT
      LAYER M4 ;
        RECT  243.456 138.3 243.648 138.324 ;
    END
  END si[228]
  PIN si[229]
    DIRECTION INPUT ;
    USE SIGNAL ;
    PORT
      LAYER M4 ;
        RECT  243.456 138.876 243.648 138.9 ;
    END
  END si[229]
  PIN si[22]
    DIRECTION INPUT ;
    USE SIGNAL ;
    PORT
      LAYER M4 ;
        RECT  243.456 15.42 243.648 15.444 ;
    END
  END si[22]
  PIN si[230]
    DIRECTION INPUT ;
    USE SIGNAL ;
    PORT
      LAYER M4 ;
        RECT  243.456 139.452 243.648 139.476 ;
    END
  END si[230]
  PIN si[231]
    DIRECTION INPUT ;
    USE SIGNAL ;
    PORT
      LAYER M4 ;
        RECT  243.456 140.076 243.648 140.1 ;
    END
  END si[231]
  PIN si[232]
    DIRECTION INPUT ;
    USE SIGNAL ;
    PORT
      LAYER M4 ;
        RECT  243.456 140.652 243.648 140.676 ;
    END
  END si[232]
  PIN si[233]
    DIRECTION INPUT ;
    USE SIGNAL ;
    PORT
      LAYER M4 ;
        RECT  243.456 141.276 243.648 141.3 ;
    END
  END si[233]
  PIN si[234]
    DIRECTION INPUT ;
    USE SIGNAL ;
    PORT
      LAYER M4 ;
        RECT  243.456 141.852 243.648 141.876 ;
    END
  END si[234]
  PIN si[235]
    DIRECTION INPUT ;
    USE SIGNAL ;
    PORT
      LAYER M4 ;
        RECT  243.456 142.476 243.648 142.5 ;
    END
  END si[235]
  PIN si[236]
    DIRECTION INPUT ;
    USE SIGNAL ;
    PORT
      LAYER M4 ;
        RECT  243.456 143.052 243.648 143.076 ;
    END
  END si[236]
  PIN si[237]
    DIRECTION INPUT ;
    USE SIGNAL ;
    PORT
      LAYER M4 ;
        RECT  243.456 143.628 243.648 143.652 ;
    END
  END si[237]
  PIN si[238]
    DIRECTION INPUT ;
    USE SIGNAL ;
    PORT
      LAYER M4 ;
        RECT  243.456 144.252 243.648 144.276 ;
    END
  END si[238]
  PIN si[239]
    DIRECTION INPUT ;
    USE SIGNAL ;
    PORT
      LAYER M4 ;
        RECT  243.456 144.828 243.648 144.852 ;
    END
  END si[239]
  PIN si[23]
    DIRECTION INPUT ;
    USE SIGNAL ;
    PORT
      LAYER M4 ;
        RECT  243.456 15.996 243.648 16.02 ;
    END
  END si[23]
  PIN si[240]
    DIRECTION INPUT ;
    USE SIGNAL ;
    PORT
      LAYER M4 ;
        RECT  243.456 145.452 243.648 145.476 ;
    END
  END si[240]
  PIN si[241]
    DIRECTION INPUT ;
    USE SIGNAL ;
    PORT
      LAYER M4 ;
        RECT  243.456 146.028 243.648 146.052 ;
    END
  END si[241]
  PIN si[242]
    DIRECTION INPUT ;
    USE SIGNAL ;
    PORT
      LAYER M4 ;
        RECT  243.456 146.652 243.648 146.676 ;
    END
  END si[242]
  PIN si[243]
    DIRECTION INPUT ;
    USE SIGNAL ;
    PORT
      LAYER M4 ;
        RECT  243.456 147.228 243.648 147.252 ;
    END
  END si[243]
  PIN si[244]
    DIRECTION INPUT ;
    USE SIGNAL ;
    PORT
      LAYER M4 ;
        RECT  243.456 147.804 243.648 147.828 ;
    END
  END si[244]
  PIN si[245]
    DIRECTION INPUT ;
    USE SIGNAL ;
    PORT
      LAYER M4 ;
        RECT  243.456 148.428 243.648 148.452 ;
    END
  END si[245]
  PIN si[246]
    DIRECTION INPUT ;
    USE SIGNAL ;
    PORT
      LAYER M4 ;
        RECT  243.456 149.004 243.648 149.028 ;
    END
  END si[246]
  PIN si[247]
    DIRECTION INPUT ;
    USE SIGNAL ;
    PORT
      LAYER M4 ;
        RECT  243.456 149.628 243.648 149.652 ;
    END
  END si[247]
  PIN si[248]
    DIRECTION INPUT ;
    USE SIGNAL ;
    PORT
      LAYER M4 ;
        RECT  243.456 150.204 243.648 150.228 ;
    END
  END si[248]
  PIN si[249]
    DIRECTION INPUT ;
    USE SIGNAL ;
    PORT
      LAYER M4 ;
        RECT  243.456 150.828 243.648 150.852 ;
    END
  END si[249]
  PIN si[24]
    DIRECTION INPUT ;
    USE SIGNAL ;
    PORT
      LAYER M4 ;
        RECT  243.456 16.62 243.648 16.644 ;
    END
  END si[24]
  PIN si[250]
    DIRECTION INPUT ;
    USE SIGNAL ;
    PORT
      LAYER M4 ;
        RECT  243.456 151.404 243.648 151.428 ;
    END
  END si[250]
  PIN si[251]
    DIRECTION INPUT ;
    USE SIGNAL ;
    PORT
      LAYER M4 ;
        RECT  243.456 151.98 243.648 152.004 ;
    END
  END si[251]
  PIN si[252]
    DIRECTION INPUT ;
    USE SIGNAL ;
    PORT
      LAYER M4 ;
        RECT  243.456 152.604 243.648 152.628 ;
    END
  END si[252]
  PIN si[253]
    DIRECTION INPUT ;
    USE SIGNAL ;
    PORT
      LAYER M4 ;
        RECT  243.456 153.18 243.648 153.204 ;
    END
  END si[253]
  PIN si[254]
    DIRECTION INPUT ;
    USE SIGNAL ;
    PORT
      LAYER M4 ;
        RECT  243.456 153.804 243.648 153.828 ;
    END
  END si[254]
  PIN si[255]
    DIRECTION INPUT ;
    USE SIGNAL ;
    PORT
      LAYER M4 ;
        RECT  243.456 154.38 243.648 154.404 ;
    END
  END si[255]
  PIN si[256]
    DIRECTION INPUT ;
    USE SIGNAL ;
    PORT
      LAYER M4 ;
        RECT  243.456 155.004 243.648 155.028 ;
    END
  END si[256]
  PIN si[257]
    DIRECTION INPUT ;
    USE SIGNAL ;
    PORT
      LAYER M4 ;
        RECT  243.456 155.58 243.648 155.604 ;
    END
  END si[257]
  PIN si[258]
    DIRECTION INPUT ;
    USE SIGNAL ;
    PORT
      LAYER M4 ;
        RECT  243.456 156.156 243.648 156.18 ;
    END
  END si[258]
  PIN si[259]
    DIRECTION INPUT ;
    USE SIGNAL ;
    PORT
      LAYER M4 ;
        RECT  243.456 156.78 243.648 156.804 ;
    END
  END si[259]
  PIN si[25]
    DIRECTION INPUT ;
    USE SIGNAL ;
    PORT
      LAYER M4 ;
        RECT  243.456 17.196 243.648 17.22 ;
    END
  END si[25]
  PIN si[260]
    DIRECTION INPUT ;
    USE SIGNAL ;
    PORT
      LAYER M4 ;
        RECT  243.456 157.356 243.648 157.38 ;
    END
  END si[260]
  PIN si[261]
    DIRECTION INPUT ;
    USE SIGNAL ;
    PORT
      LAYER M4 ;
        RECT  243.456 157.98 243.648 158.004 ;
    END
  END si[261]
  PIN si[262]
    DIRECTION INPUT ;
    USE SIGNAL ;
    PORT
      LAYER M4 ;
        RECT  243.456 158.556 243.648 158.58 ;
    END
  END si[262]
  PIN si[263]
    DIRECTION INPUT ;
    USE SIGNAL ;
    PORT
      LAYER M4 ;
        RECT  243.456 159.18 243.648 159.204 ;
    END
  END si[263]
  PIN si[264]
    DIRECTION INPUT ;
    USE SIGNAL ;
    PORT
      LAYER M4 ;
        RECT  243.456 159.756 243.648 159.78 ;
    END
  END si[264]
  PIN si[265]
    DIRECTION INPUT ;
    USE SIGNAL ;
    PORT
      LAYER M4 ;
        RECT  243.456 160.332 243.648 160.356 ;
    END
  END si[265]
  PIN si[266]
    DIRECTION INPUT ;
    USE SIGNAL ;
    PORT
      LAYER M4 ;
        RECT  243.456 160.956 243.648 160.98 ;
    END
  END si[266]
  PIN si[267]
    DIRECTION INPUT ;
    USE SIGNAL ;
    PORT
      LAYER M4 ;
        RECT  243.456 161.532 243.648 161.556 ;
    END
  END si[267]
  PIN si[268]
    DIRECTION INPUT ;
    USE SIGNAL ;
    PORT
      LAYER M4 ;
        RECT  243.456 162.156 243.648 162.18 ;
    END
  END si[268]
  PIN si[269]
    DIRECTION INPUT ;
    USE SIGNAL ;
    PORT
      LAYER M4 ;
        RECT  243.456 162.732 243.648 162.756 ;
    END
  END si[269]
  PIN si[26]
    DIRECTION INPUT ;
    USE SIGNAL ;
    PORT
      LAYER M4 ;
        RECT  243.456 17.772 243.648 17.796 ;
    END
  END si[26]
  PIN si[270]
    DIRECTION INPUT ;
    USE SIGNAL ;
    PORT
      LAYER M4 ;
        RECT  243.456 163.356 243.648 163.38 ;
    END
  END si[270]
  PIN si[271]
    DIRECTION INPUT ;
    USE SIGNAL ;
    PORT
      LAYER M4 ;
        RECT  243.456 163.932 243.648 163.956 ;
    END
  END si[271]
  PIN si[272]
    DIRECTION INPUT ;
    USE SIGNAL ;
    PORT
      LAYER M4 ;
        RECT  243.456 164.508 243.648 164.532 ;
    END
  END si[272]
  PIN si[273]
    DIRECTION INPUT ;
    USE SIGNAL ;
    PORT
      LAYER M4 ;
        RECT  243.456 165.132 243.648 165.156 ;
    END
  END si[273]
  PIN si[274]
    DIRECTION INPUT ;
    USE SIGNAL ;
    PORT
      LAYER M4 ;
        RECT  243.456 165.708 243.648 165.732 ;
    END
  END si[274]
  PIN si[275]
    DIRECTION INPUT ;
    USE SIGNAL ;
    PORT
      LAYER M4 ;
        RECT  243.456 166.332 243.648 166.356 ;
    END
  END si[275]
  PIN si[276]
    DIRECTION INPUT ;
    USE SIGNAL ;
    PORT
      LAYER M4 ;
        RECT  243.456 166.908 243.648 166.932 ;
    END
  END si[276]
  PIN si[277]
    DIRECTION INPUT ;
    USE SIGNAL ;
    PORT
      LAYER M4 ;
        RECT  243.456 167.484 243.648 167.508 ;
    END
  END si[277]
  PIN si[278]
    DIRECTION INPUT ;
    USE SIGNAL ;
    PORT
      LAYER M4 ;
        RECT  243.456 168.108 243.648 168.132 ;
    END
  END si[278]
  PIN si[279]
    DIRECTION INPUT ;
    USE SIGNAL ;
    PORT
      LAYER M4 ;
        RECT  243.456 168.684 243.648 168.708 ;
    END
  END si[279]
  PIN si[27]
    DIRECTION INPUT ;
    USE SIGNAL ;
    PORT
      LAYER M4 ;
        RECT  243.456 18.396 243.648 18.42 ;
    END
  END si[27]
  PIN si[280]
    DIRECTION INPUT ;
    USE SIGNAL ;
    PORT
      LAYER M4 ;
        RECT  243.456 169.308 243.648 169.332 ;
    END
  END si[280]
  PIN si[281]
    DIRECTION INPUT ;
    USE SIGNAL ;
    PORT
      LAYER M4 ;
        RECT  243.456 169.884 243.648 169.908 ;
    END
  END si[281]
  PIN si[282]
    DIRECTION INPUT ;
    USE SIGNAL ;
    PORT
      LAYER M4 ;
        RECT  243.456 170.508 243.648 170.532 ;
    END
  END si[282]
  PIN si[28]
    DIRECTION INPUT ;
    USE SIGNAL ;
    PORT
      LAYER M4 ;
        RECT  243.456 18.972 243.648 18.996 ;
    END
  END si[28]
  PIN si[29]
    DIRECTION INPUT ;
    USE SIGNAL ;
    PORT
      LAYER M4 ;
        RECT  243.456 19.596 243.648 19.62 ;
    END
  END si[29]
  PIN si[2]
    DIRECTION INPUT ;
    USE SIGNAL ;
    PORT
      LAYER M4 ;
        RECT  243.456 3.468 243.648 3.492 ;
    END
  END si[2]
  PIN si[30]
    DIRECTION INPUT ;
    USE SIGNAL ;
    PORT
      LAYER M4 ;
        RECT  243.456 20.172 243.648 20.196 ;
    END
  END si[30]
  PIN si[31]
    DIRECTION INPUT ;
    USE SIGNAL ;
    PORT
      LAYER M4 ;
        RECT  243.456 20.796 243.648 20.82 ;
    END
  END si[31]
  PIN si[32]
    DIRECTION INPUT ;
    USE SIGNAL ;
    PORT
      LAYER M4 ;
        RECT  243.456 21.372 243.648 21.396 ;
    END
  END si[32]
  PIN si[33]
    DIRECTION INPUT ;
    USE SIGNAL ;
    PORT
      LAYER M4 ;
        RECT  243.456 21.948 243.648 21.972 ;
    END
  END si[33]
  PIN si[34]
    DIRECTION INPUT ;
    USE SIGNAL ;
    PORT
      LAYER M4 ;
        RECT  243.456 22.572 243.648 22.596 ;
    END
  END si[34]
  PIN si[35]
    DIRECTION INPUT ;
    USE SIGNAL ;
    PORT
      LAYER M4 ;
        RECT  243.456 23.148 243.648 23.172 ;
    END
  END si[35]
  PIN si[36]
    DIRECTION INPUT ;
    USE SIGNAL ;
    PORT
      LAYER M4 ;
        RECT  243.456 23.772 243.648 23.796 ;
    END
  END si[36]
  PIN si[37]
    DIRECTION INPUT ;
    USE SIGNAL ;
    PORT
      LAYER M4 ;
        RECT  243.456 24.348 243.648 24.372 ;
    END
  END si[37]
  PIN si[38]
    DIRECTION INPUT ;
    USE SIGNAL ;
    PORT
      LAYER M4 ;
        RECT  243.456 24.972 243.648 24.996 ;
    END
  END si[38]
  PIN si[39]
    DIRECTION INPUT ;
    USE SIGNAL ;
    PORT
      LAYER M4 ;
        RECT  243.456 25.548 243.648 25.572 ;
    END
  END si[39]
  PIN si[3]
    DIRECTION INPUT ;
    USE SIGNAL ;
    PORT
      LAYER M4 ;
        RECT  243.456 4.092 243.648 4.116 ;
    END
  END si[3]
  PIN si[40]
    DIRECTION INPUT ;
    USE SIGNAL ;
    PORT
      LAYER M4 ;
        RECT  243.456 26.124 243.648 26.148 ;
    END
  END si[40]
  PIN si[41]
    DIRECTION INPUT ;
    USE SIGNAL ;
    PORT
      LAYER M4 ;
        RECT  243.456 26.748 243.648 26.772 ;
    END
  END si[41]
  PIN si[42]
    DIRECTION INPUT ;
    USE SIGNAL ;
    PORT
      LAYER M4 ;
        RECT  243.456 27.324 243.648 27.348 ;
    END
  END si[42]
  PIN si[43]
    DIRECTION INPUT ;
    USE SIGNAL ;
    PORT
      LAYER M4 ;
        RECT  243.456 27.948 243.648 27.972 ;
    END
  END si[43]
  PIN si[44]
    DIRECTION INPUT ;
    USE SIGNAL ;
    PORT
      LAYER M4 ;
        RECT  243.456 28.524 243.648 28.548 ;
    END
  END si[44]
  PIN si[45]
    DIRECTION INPUT ;
    USE SIGNAL ;
    PORT
      LAYER M4 ;
        RECT  243.456 29.148 243.648 29.172 ;
    END
  END si[45]
  PIN si[46]
    DIRECTION INPUT ;
    USE SIGNAL ;
    PORT
      LAYER M4 ;
        RECT  243.456 29.724 243.648 29.748 ;
    END
  END si[46]
  PIN si[47]
    DIRECTION INPUT ;
    USE SIGNAL ;
    PORT
      LAYER M4 ;
        RECT  243.456 30.3 243.648 30.324 ;
    END
  END si[47]
  PIN si[48]
    DIRECTION INPUT ;
    USE SIGNAL ;
    PORT
      LAYER M4 ;
        RECT  243.456 30.924 243.648 30.948 ;
    END
  END si[48]
  PIN si[49]
    DIRECTION INPUT ;
    USE SIGNAL ;
    PORT
      LAYER M4 ;
        RECT  243.456 31.5 243.648 31.524 ;
    END
  END si[49]
  PIN si[4]
    DIRECTION INPUT ;
    USE SIGNAL ;
    PORT
      LAYER M4 ;
        RECT  243.456 4.668 243.648 4.692 ;
    END
  END si[4]
  PIN si[50]
    DIRECTION INPUT ;
    USE SIGNAL ;
    PORT
      LAYER M4 ;
        RECT  243.456 32.124 243.648 32.148 ;
    END
  END si[50]
  PIN si[51]
    DIRECTION INPUT ;
    USE SIGNAL ;
    PORT
      LAYER M4 ;
        RECT  243.456 32.7 243.648 32.724 ;
    END
  END si[51]
  PIN si[52]
    DIRECTION INPUT ;
    USE SIGNAL ;
    PORT
      LAYER M4 ;
        RECT  243.456 33.324 243.648 33.348 ;
    END
  END si[52]
  PIN si[53]
    DIRECTION INPUT ;
    USE SIGNAL ;
    PORT
      LAYER M4 ;
        RECT  243.456 33.9 243.648 33.924 ;
    END
  END si[53]
  PIN si[54]
    DIRECTION INPUT ;
    USE SIGNAL ;
    PORT
      LAYER M4 ;
        RECT  243.456 34.476 243.648 34.5 ;
    END
  END si[54]
  PIN si[55]
    DIRECTION INPUT ;
    USE SIGNAL ;
    PORT
      LAYER M4 ;
        RECT  243.456 35.1 243.648 35.124 ;
    END
  END si[55]
  PIN si[56]
    DIRECTION INPUT ;
    USE SIGNAL ;
    PORT
      LAYER M4 ;
        RECT  243.456 35.676 243.648 35.7 ;
    END
  END si[56]
  PIN si[57]
    DIRECTION INPUT ;
    USE SIGNAL ;
    PORT
      LAYER M4 ;
        RECT  243.456 36.3 243.648 36.324 ;
    END
  END si[57]
  PIN si[58]
    DIRECTION INPUT ;
    USE SIGNAL ;
    PORT
      LAYER M4 ;
        RECT  243.456 36.876 243.648 36.9 ;
    END
  END si[58]
  PIN si[59]
    DIRECTION INPUT ;
    USE SIGNAL ;
    PORT
      LAYER M4 ;
        RECT  243.456 37.5 243.648 37.524 ;
    END
  END si[59]
  PIN si[5]
    DIRECTION INPUT ;
    USE SIGNAL ;
    PORT
      LAYER M4 ;
        RECT  243.456 5.292 243.648 5.316 ;
    END
  END si[5]
  PIN si[60]
    DIRECTION INPUT ;
    USE SIGNAL ;
    PORT
      LAYER M4 ;
        RECT  243.456 38.076 243.648 38.1 ;
    END
  END si[60]
  PIN si[61]
    DIRECTION INPUT ;
    USE SIGNAL ;
    PORT
      LAYER M4 ;
        RECT  243.456 38.652 243.648 38.676 ;
    END
  END si[61]
  PIN si[62]
    DIRECTION INPUT ;
    USE SIGNAL ;
    PORT
      LAYER M4 ;
        RECT  243.456 39.276 243.648 39.3 ;
    END
  END si[62]
  PIN si[63]
    DIRECTION INPUT ;
    USE SIGNAL ;
    PORT
      LAYER M4 ;
        RECT  243.456 39.852 243.648 39.876 ;
    END
  END si[63]
  PIN si[64]
    DIRECTION INPUT ;
    USE SIGNAL ;
    PORT
      LAYER M4 ;
        RECT  243.456 40.476 243.648 40.5 ;
    END
  END si[64]
  PIN si[65]
    DIRECTION INPUT ;
    USE SIGNAL ;
    PORT
      LAYER M4 ;
        RECT  243.456 41.052 243.648 41.076 ;
    END
  END si[65]
  PIN si[66]
    DIRECTION INPUT ;
    USE SIGNAL ;
    PORT
      LAYER M4 ;
        RECT  243.456 41.676 243.648 41.7 ;
    END
  END si[66]
  PIN si[67]
    DIRECTION INPUT ;
    USE SIGNAL ;
    PORT
      LAYER M4 ;
        RECT  243.456 42.252 243.648 42.276 ;
    END
  END si[67]
  PIN si[68]
    DIRECTION INPUT ;
    USE SIGNAL ;
    PORT
      LAYER M4 ;
        RECT  243.456 42.828 243.648 42.852 ;
    END
  END si[68]
  PIN si[69]
    DIRECTION INPUT ;
    USE SIGNAL ;
    PORT
      LAYER M4 ;
        RECT  243.456 43.452 243.648 43.476 ;
    END
  END si[69]
  PIN si[6]
    DIRECTION INPUT ;
    USE SIGNAL ;
    PORT
      LAYER M4 ;
        RECT  243.456 5.868 243.648 5.892 ;
    END
  END si[6]
  PIN si[70]
    DIRECTION INPUT ;
    USE SIGNAL ;
    PORT
      LAYER M4 ;
        RECT  243.456 44.028 243.648 44.052 ;
    END
  END si[70]
  PIN si[71]
    DIRECTION INPUT ;
    USE SIGNAL ;
    PORT
      LAYER M4 ;
        RECT  243.456 44.652 243.648 44.676 ;
    END
  END si[71]
  PIN si[72]
    DIRECTION INPUT ;
    USE SIGNAL ;
    PORT
      LAYER M4 ;
        RECT  243.456 45.228 243.648 45.252 ;
    END
  END si[72]
  PIN si[73]
    DIRECTION INPUT ;
    USE SIGNAL ;
    PORT
      LAYER M4 ;
        RECT  243.456 45.852 243.648 45.876 ;
    END
  END si[73]
  PIN si[74]
    DIRECTION INPUT ;
    USE SIGNAL ;
    PORT
      LAYER M4 ;
        RECT  243.456 46.428 243.648 46.452 ;
    END
  END si[74]
  PIN si[75]
    DIRECTION INPUT ;
    USE SIGNAL ;
    PORT
      LAYER M4 ;
        RECT  243.456 47.004 243.648 47.028 ;
    END
  END si[75]
  PIN si[76]
    DIRECTION INPUT ;
    USE SIGNAL ;
    PORT
      LAYER M4 ;
        RECT  243.456 47.628 243.648 47.652 ;
    END
  END si[76]
  PIN si[77]
    DIRECTION INPUT ;
    USE SIGNAL ;
    PORT
      LAYER M4 ;
        RECT  243.456 48.204 243.648 48.228 ;
    END
  END si[77]
  PIN si[78]
    DIRECTION INPUT ;
    USE SIGNAL ;
    PORT
      LAYER M4 ;
        RECT  243.456 48.828 243.648 48.852 ;
    END
  END si[78]
  PIN si[79]
    DIRECTION INPUT ;
    USE SIGNAL ;
    PORT
      LAYER M4 ;
        RECT  243.456 49.404 243.648 49.428 ;
    END
  END si[79]
  PIN si[7]
    DIRECTION INPUT ;
    USE SIGNAL ;
    PORT
      LAYER M4 ;
        RECT  243.456 6.444 243.648 6.468 ;
    END
  END si[7]
  PIN si[80]
    DIRECTION INPUT ;
    USE SIGNAL ;
    PORT
      LAYER M4 ;
        RECT  243.456 49.98 243.648 50.004 ;
    END
  END si[80]
  PIN si[81]
    DIRECTION INPUT ;
    USE SIGNAL ;
    PORT
      LAYER M4 ;
        RECT  243.456 50.604 243.648 50.628 ;
    END
  END si[81]
  PIN si[82]
    DIRECTION INPUT ;
    USE SIGNAL ;
    PORT
      LAYER M4 ;
        RECT  243.456 51.18 243.648 51.204 ;
    END
  END si[82]
  PIN si[83]
    DIRECTION INPUT ;
    USE SIGNAL ;
    PORT
      LAYER M4 ;
        RECT  243.456 51.804 243.648 51.828 ;
    END
  END si[83]
  PIN si[84]
    DIRECTION INPUT ;
    USE SIGNAL ;
    PORT
      LAYER M4 ;
        RECT  243.456 52.38 243.648 52.404 ;
    END
  END si[84]
  PIN si[85]
    DIRECTION INPUT ;
    USE SIGNAL ;
    PORT
      LAYER M4 ;
        RECT  243.456 53.004 243.648 53.028 ;
    END
  END si[85]
  PIN si[86]
    DIRECTION INPUT ;
    USE SIGNAL ;
    PORT
      LAYER M4 ;
        RECT  243.456 53.58 243.648 53.604 ;
    END
  END si[86]
  PIN si[87]
    DIRECTION INPUT ;
    USE SIGNAL ;
    PORT
      LAYER M4 ;
        RECT  243.456 54.156 243.648 54.18 ;
    END
  END si[87]
  PIN si[88]
    DIRECTION INPUT ;
    USE SIGNAL ;
    PORT
      LAYER M4 ;
        RECT  243.456 54.78 243.648 54.804 ;
    END
  END si[88]
  PIN si[89]
    DIRECTION INPUT ;
    USE SIGNAL ;
    PORT
      LAYER M4 ;
        RECT  243.456 55.356 243.648 55.38 ;
    END
  END si[89]
  PIN si[8]
    DIRECTION INPUT ;
    USE SIGNAL ;
    PORT
      LAYER M4 ;
        RECT  243.456 7.068 243.648 7.092 ;
    END
  END si[8]
  PIN si[90]
    DIRECTION INPUT ;
    USE SIGNAL ;
    PORT
      LAYER M4 ;
        RECT  243.456 55.98 243.648 56.004 ;
    END
  END si[90]
  PIN si[91]
    DIRECTION INPUT ;
    USE SIGNAL ;
    PORT
      LAYER M4 ;
        RECT  243.456 56.556 243.648 56.58 ;
    END
  END si[91]
  PIN si[92]
    DIRECTION INPUT ;
    USE SIGNAL ;
    PORT
      LAYER M4 ;
        RECT  243.456 57.18 243.648 57.204 ;
    END
  END si[92]
  PIN si[93]
    DIRECTION INPUT ;
    USE SIGNAL ;
    PORT
      LAYER M4 ;
        RECT  243.456 57.756 243.648 57.78 ;
    END
  END si[93]
  PIN si[94]
    DIRECTION INPUT ;
    USE SIGNAL ;
    PORT
      LAYER M4 ;
        RECT  243.456 58.332 243.648 58.356 ;
    END
  END si[94]
  PIN si[95]
    DIRECTION INPUT ;
    USE SIGNAL ;
    PORT
      LAYER M4 ;
        RECT  243.456 58.956 243.648 58.98 ;
    END
  END si[95]
  PIN si[96]
    DIRECTION INPUT ;
    USE SIGNAL ;
    PORT
      LAYER M4 ;
        RECT  243.456 59.532 243.648 59.556 ;
    END
  END si[96]
  PIN si[97]
    DIRECTION INPUT ;
    USE SIGNAL ;
    PORT
      LAYER M4 ;
        RECT  243.456 60.156 243.648 60.18 ;
    END
  END si[97]
  PIN si[98]
    DIRECTION INPUT ;
    USE SIGNAL ;
    PORT
      LAYER M4 ;
        RECT  243.456 60.732 243.648 60.756 ;
    END
  END si[98]
  PIN si[99]
    DIRECTION INPUT ;
    USE SIGNAL ;
    PORT
      LAYER M4 ;
        RECT  243.456 61.356 243.648 61.38 ;
    END
  END si[99]
  PIN si[9]
    DIRECTION INPUT ;
    USE SIGNAL ;
    PORT
      LAYER M4 ;
        RECT  243.456 7.644 243.648 7.668 ;
    END
  END si[9]
  PIN t0[0]
    DIRECTION OUTPUT ;
    USE SIGNAL ;
    PORT
      LAYER M5 ;
        RECT  2.124 0 2.148 0.192 ;
    END
  END t0[0]
  PIN t0[100]
    DIRECTION OUTPUT ;
    USE SIGNAL ;
    PORT
      LAYER M5 ;
        RECT  25.404 0 25.428 0.192 ;
    END
  END t0[100]
  PIN t0[101]
    DIRECTION OUTPUT ;
    USE SIGNAL ;
    PORT
      LAYER M5 ;
        RECT  25.644 0 25.668 0.192 ;
    END
  END t0[101]
  PIN t0[102]
    DIRECTION OUTPUT ;
    USE SIGNAL ;
    PORT
      LAYER M5 ;
        RECT  25.884 0 25.908 0.192 ;
    END
  END t0[102]
  PIN t0[103]
    DIRECTION OUTPUT ;
    USE SIGNAL ;
    PORT
      LAYER M5 ;
        RECT  26.124 0 26.148 0.192 ;
    END
  END t0[103]
  PIN t0[104]
    DIRECTION OUTPUT ;
    USE SIGNAL ;
    PORT
      LAYER M5 ;
        RECT  26.316 0 26.34 0.192 ;
    END
  END t0[104]
  PIN t0[105]
    DIRECTION OUTPUT ;
    USE SIGNAL ;
    PORT
      LAYER M5 ;
        RECT  26.556 0 26.58 0.192 ;
    END
  END t0[105]
  PIN t0[106]
    DIRECTION OUTPUT ;
    USE SIGNAL ;
    PORT
      LAYER M5 ;
        RECT  26.796 0 26.82 0.192 ;
    END
  END t0[106]
  PIN t0[107]
    DIRECTION OUTPUT ;
    USE SIGNAL ;
    PORT
      LAYER M5 ;
        RECT  27.036 0 27.06 0.192 ;
    END
  END t0[107]
  PIN t0[108]
    DIRECTION OUTPUT ;
    USE SIGNAL ;
    PORT
      LAYER M5 ;
        RECT  27.276 0 27.3 0.192 ;
    END
  END t0[108]
  PIN t0[109]
    DIRECTION OUTPUT ;
    USE SIGNAL ;
    PORT
      LAYER M5 ;
        RECT  27.516 0 27.54 0.192 ;
    END
  END t0[109]
  PIN t0[10]
    DIRECTION OUTPUT ;
    USE SIGNAL ;
    PORT
      LAYER M5 ;
        RECT  4.428 0 4.452 0.192 ;
    END
  END t0[10]
  PIN t0[110]
    DIRECTION OUTPUT ;
    USE SIGNAL ;
    PORT
      LAYER M5 ;
        RECT  27.708 0 27.732 0.192 ;
    END
  END t0[110]
  PIN t0[111]
    DIRECTION OUTPUT ;
    USE SIGNAL ;
    PORT
      LAYER M5 ;
        RECT  27.948 0 27.972 0.192 ;
    END
  END t0[111]
  PIN t0[112]
    DIRECTION OUTPUT ;
    USE SIGNAL ;
    PORT
      LAYER M5 ;
        RECT  28.188 0 28.212 0.192 ;
    END
  END t0[112]
  PIN t0[113]
    DIRECTION OUTPUT ;
    USE SIGNAL ;
    PORT
      LAYER M5 ;
        RECT  28.428 0 28.452 0.192 ;
    END
  END t0[113]
  PIN t0[114]
    DIRECTION OUTPUT ;
    USE SIGNAL ;
    PORT
      LAYER M5 ;
        RECT  28.668 0 28.692 0.192 ;
    END
  END t0[114]
  PIN t0[115]
    DIRECTION OUTPUT ;
    USE SIGNAL ;
    PORT
      LAYER M5 ;
        RECT  28.908 0 28.932 0.192 ;
    END
  END t0[115]
  PIN t0[116]
    DIRECTION OUTPUT ;
    USE SIGNAL ;
    PORT
      LAYER M5 ;
        RECT  29.148 0 29.172 0.192 ;
    END
  END t0[116]
  PIN t0[117]
    DIRECTION OUTPUT ;
    USE SIGNAL ;
    PORT
      LAYER M5 ;
        RECT  29.34 0 29.364 0.192 ;
    END
  END t0[117]
  PIN t0[118]
    DIRECTION OUTPUT ;
    USE SIGNAL ;
    PORT
      LAYER M5 ;
        RECT  29.58 0 29.604 0.192 ;
    END
  END t0[118]
  PIN t0[119]
    DIRECTION OUTPUT ;
    USE SIGNAL ;
    PORT
      LAYER M5 ;
        RECT  29.82 0 29.844 0.192 ;
    END
  END t0[119]
  PIN t0[11]
    DIRECTION OUTPUT ;
    USE SIGNAL ;
    PORT
      LAYER M5 ;
        RECT  4.668 0 4.692 0.192 ;
    END
  END t0[11]
  PIN t0[120]
    DIRECTION OUTPUT ;
    USE SIGNAL ;
    PORT
      LAYER M5 ;
        RECT  30.06 0 30.084 0.192 ;
    END
  END t0[120]
  PIN t0[121]
    DIRECTION OUTPUT ;
    USE SIGNAL ;
    PORT
      LAYER M5 ;
        RECT  30.3 0 30.324 0.192 ;
    END
  END t0[121]
  PIN t0[122]
    DIRECTION OUTPUT ;
    USE SIGNAL ;
    PORT
      LAYER M5 ;
        RECT  30.54 0 30.564 0.192 ;
    END
  END t0[122]
  PIN t0[123]
    DIRECTION OUTPUT ;
    USE SIGNAL ;
    PORT
      LAYER M5 ;
        RECT  30.78 0 30.804 0.192 ;
    END
  END t0[123]
  PIN t0[124]
    DIRECTION OUTPUT ;
    USE SIGNAL ;
    PORT
      LAYER M5 ;
        RECT  30.972 0 30.996 0.192 ;
    END
  END t0[124]
  PIN t0[125]
    DIRECTION OUTPUT ;
    USE SIGNAL ;
    PORT
      LAYER M5 ;
        RECT  31.212 0 31.236 0.192 ;
    END
  END t0[125]
  PIN t0[126]
    DIRECTION OUTPUT ;
    USE SIGNAL ;
    PORT
      LAYER M5 ;
        RECT  31.452 0 31.476 0.192 ;
    END
  END t0[126]
  PIN t0[127]
    DIRECTION OUTPUT ;
    USE SIGNAL ;
    PORT
      LAYER M5 ;
        RECT  31.692 0 31.716 0.192 ;
    END
  END t0[127]
  PIN t0[128]
    DIRECTION OUTPUT ;
    USE SIGNAL ;
    PORT
      LAYER M5 ;
        RECT  31.932 0 31.956 0.192 ;
    END
  END t0[128]
  PIN t0[129]
    DIRECTION OUTPUT ;
    USE SIGNAL ;
    PORT
      LAYER M5 ;
        RECT  32.172 0 32.196 0.192 ;
    END
  END t0[129]
  PIN t0[12]
    DIRECTION OUTPUT ;
    USE SIGNAL ;
    PORT
      LAYER M5 ;
        RECT  4.908 0 4.932 0.192 ;
    END
  END t0[12]
  PIN t0[130]
    DIRECTION OUTPUT ;
    USE SIGNAL ;
    PORT
      LAYER M5 ;
        RECT  32.412 0 32.436 0.192 ;
    END
  END t0[130]
  PIN t0[131]
    DIRECTION OUTPUT ;
    USE SIGNAL ;
    PORT
      LAYER M5 ;
        RECT  32.604 0 32.628 0.192 ;
    END
  END t0[131]
  PIN t0[132]
    DIRECTION OUTPUT ;
    USE SIGNAL ;
    PORT
      LAYER M5 ;
        RECT  32.844 0 32.868 0.192 ;
    END
  END t0[132]
  PIN t0[133]
    DIRECTION OUTPUT ;
    USE SIGNAL ;
    PORT
      LAYER M5 ;
        RECT  33.084 0 33.108 0.192 ;
    END
  END t0[133]
  PIN t0[134]
    DIRECTION OUTPUT ;
    USE SIGNAL ;
    PORT
      LAYER M5 ;
        RECT  33.324 0 33.348 0.192 ;
    END
  END t0[134]
  PIN t0[135]
    DIRECTION OUTPUT ;
    USE SIGNAL ;
    PORT
      LAYER M5 ;
        RECT  33.564 0 33.588 0.192 ;
    END
  END t0[135]
  PIN t0[136]
    DIRECTION OUTPUT ;
    USE SIGNAL ;
    PORT
      LAYER M5 ;
        RECT  33.804 0 33.828 0.192 ;
    END
  END t0[136]
  PIN t0[137]
    DIRECTION OUTPUT ;
    USE SIGNAL ;
    PORT
      LAYER M5 ;
        RECT  34.044 0 34.068 0.192 ;
    END
  END t0[137]
  PIN t0[138]
    DIRECTION OUTPUT ;
    USE SIGNAL ;
    PORT
      LAYER M5 ;
        RECT  34.236 0 34.26 0.192 ;
    END
  END t0[138]
  PIN t0[139]
    DIRECTION OUTPUT ;
    USE SIGNAL ;
    PORT
      LAYER M5 ;
        RECT  34.476 0 34.5 0.192 ;
    END
  END t0[139]
  PIN t0[13]
    DIRECTION OUTPUT ;
    USE SIGNAL ;
    PORT
      LAYER M5 ;
        RECT  5.148 0 5.172 0.192 ;
    END
  END t0[13]
  PIN t0[140]
    DIRECTION OUTPUT ;
    USE SIGNAL ;
    PORT
      LAYER M5 ;
        RECT  34.716 0 34.74 0.192 ;
    END
  END t0[140]
  PIN t0[141]
    DIRECTION OUTPUT ;
    USE SIGNAL ;
    PORT
      LAYER M5 ;
        RECT  34.956 0 34.98 0.192 ;
    END
  END t0[141]
  PIN t0[142]
    DIRECTION OUTPUT ;
    USE SIGNAL ;
    PORT
      LAYER M5 ;
        RECT  35.196 0 35.22 0.192 ;
    END
  END t0[142]
  PIN t0[143]
    DIRECTION OUTPUT ;
    USE SIGNAL ;
    PORT
      LAYER M5 ;
        RECT  35.436 0 35.46 0.192 ;
    END
  END t0[143]
  PIN t0[144]
    DIRECTION OUTPUT ;
    USE SIGNAL ;
    PORT
      LAYER M5 ;
        RECT  35.628 0 35.652 0.192 ;
    END
  END t0[144]
  PIN t0[145]
    DIRECTION OUTPUT ;
    USE SIGNAL ;
    PORT
      LAYER M5 ;
        RECT  35.868 0 35.892 0.192 ;
    END
  END t0[145]
  PIN t0[146]
    DIRECTION OUTPUT ;
    USE SIGNAL ;
    PORT
      LAYER M5 ;
        RECT  36.108 0 36.132 0.192 ;
    END
  END t0[146]
  PIN t0[147]
    DIRECTION OUTPUT ;
    USE SIGNAL ;
    PORT
      LAYER M5 ;
        RECT  36.348 0 36.372 0.192 ;
    END
  END t0[147]
  PIN t0[148]
    DIRECTION OUTPUT ;
    USE SIGNAL ;
    PORT
      LAYER M5 ;
        RECT  36.588 0 36.612 0.192 ;
    END
  END t0[148]
  PIN t0[149]
    DIRECTION OUTPUT ;
    USE SIGNAL ;
    PORT
      LAYER M5 ;
        RECT  36.828 0 36.852 0.192 ;
    END
  END t0[149]
  PIN t0[14]
    DIRECTION OUTPUT ;
    USE SIGNAL ;
    PORT
      LAYER M5 ;
        RECT  5.388 0 5.412 0.192 ;
    END
  END t0[14]
  PIN t0[150]
    DIRECTION OUTPUT ;
    USE SIGNAL ;
    PORT
      LAYER M5 ;
        RECT  37.068 0 37.092 0.192 ;
    END
  END t0[150]
  PIN t0[151]
    DIRECTION OUTPUT ;
    USE SIGNAL ;
    PORT
      LAYER M5 ;
        RECT  37.26 0 37.284 0.192 ;
    END
  END t0[151]
  PIN t0[152]
    DIRECTION OUTPUT ;
    USE SIGNAL ;
    PORT
      LAYER M5 ;
        RECT  37.5 0 37.524 0.192 ;
    END
  END t0[152]
  PIN t0[153]
    DIRECTION OUTPUT ;
    USE SIGNAL ;
    PORT
      LAYER M5 ;
        RECT  37.74 0 37.764 0.192 ;
    END
  END t0[153]
  PIN t0[154]
    DIRECTION OUTPUT ;
    USE SIGNAL ;
    PORT
      LAYER M5 ;
        RECT  37.98 0 38.004 0.192 ;
    END
  END t0[154]
  PIN t0[155]
    DIRECTION OUTPUT ;
    USE SIGNAL ;
    PORT
      LAYER M5 ;
        RECT  38.22 0 38.244 0.192 ;
    END
  END t0[155]
  PIN t0[156]
    DIRECTION OUTPUT ;
    USE SIGNAL ;
    PORT
      LAYER M5 ;
        RECT  38.46 0 38.484 0.192 ;
    END
  END t0[156]
  PIN t0[157]
    DIRECTION OUTPUT ;
    USE SIGNAL ;
    PORT
      LAYER M5 ;
        RECT  38.7 0 38.724 0.192 ;
    END
  END t0[157]
  PIN t0[158]
    DIRECTION OUTPUT ;
    USE SIGNAL ;
    PORT
      LAYER M5 ;
        RECT  38.892 0 38.916 0.192 ;
    END
  END t0[158]
  PIN t0[159]
    DIRECTION OUTPUT ;
    USE SIGNAL ;
    PORT
      LAYER M5 ;
        RECT  39.132 0 39.156 0.192 ;
    END
  END t0[159]
  PIN t0[15]
    DIRECTION OUTPUT ;
    USE SIGNAL ;
    PORT
      LAYER M5 ;
        RECT  5.58 0 5.604 0.192 ;
    END
  END t0[15]
  PIN t0[160]
    DIRECTION OUTPUT ;
    USE SIGNAL ;
    PORT
      LAYER M5 ;
        RECT  39.372 0 39.396 0.192 ;
    END
  END t0[160]
  PIN t0[161]
    DIRECTION OUTPUT ;
    USE SIGNAL ;
    PORT
      LAYER M5 ;
        RECT  39.612 0 39.636 0.192 ;
    END
  END t0[161]
  PIN t0[162]
    DIRECTION OUTPUT ;
    USE SIGNAL ;
    PORT
      LAYER M5 ;
        RECT  39.852 0 39.876 0.192 ;
    END
  END t0[162]
  PIN t0[163]
    DIRECTION OUTPUT ;
    USE SIGNAL ;
    PORT
      LAYER M5 ;
        RECT  40.092 0 40.116 0.192 ;
    END
  END t0[163]
  PIN t0[164]
    DIRECTION OUTPUT ;
    USE SIGNAL ;
    PORT
      LAYER M5 ;
        RECT  40.332 0 40.356 0.192 ;
    END
  END t0[164]
  PIN t0[165]
    DIRECTION OUTPUT ;
    USE SIGNAL ;
    PORT
      LAYER M5 ;
        RECT  40.524 0 40.548 0.192 ;
    END
  END t0[165]
  PIN t0[166]
    DIRECTION OUTPUT ;
    USE SIGNAL ;
    PORT
      LAYER M5 ;
        RECT  40.764 0 40.788 0.192 ;
    END
  END t0[166]
  PIN t0[167]
    DIRECTION OUTPUT ;
    USE SIGNAL ;
    PORT
      LAYER M5 ;
        RECT  41.004 0 41.028 0.192 ;
    END
  END t0[167]
  PIN t0[168]
    DIRECTION OUTPUT ;
    USE SIGNAL ;
    PORT
      LAYER M5 ;
        RECT  41.244 0 41.268 0.192 ;
    END
  END t0[168]
  PIN t0[169]
    DIRECTION OUTPUT ;
    USE SIGNAL ;
    PORT
      LAYER M5 ;
        RECT  41.484 0 41.508 0.192 ;
    END
  END t0[169]
  PIN t0[16]
    DIRECTION OUTPUT ;
    USE SIGNAL ;
    PORT
      LAYER M5 ;
        RECT  5.82 0 5.844 0.192 ;
    END
  END t0[16]
  PIN t0[170]
    DIRECTION OUTPUT ;
    USE SIGNAL ;
    PORT
      LAYER M5 ;
        RECT  41.724 0 41.748 0.192 ;
    END
  END t0[170]
  PIN t0[171]
    DIRECTION OUTPUT ;
    USE SIGNAL ;
    PORT
      LAYER M5 ;
        RECT  41.964 0 41.988 0.192 ;
    END
  END t0[171]
  PIN t0[172]
    DIRECTION OUTPUT ;
    USE SIGNAL ;
    PORT
      LAYER M5 ;
        RECT  42.156 0 42.18 0.192 ;
    END
  END t0[172]
  PIN t0[173]
    DIRECTION OUTPUT ;
    USE SIGNAL ;
    PORT
      LAYER M5 ;
        RECT  42.396 0 42.42 0.192 ;
    END
  END t0[173]
  PIN t0[174]
    DIRECTION OUTPUT ;
    USE SIGNAL ;
    PORT
      LAYER M5 ;
        RECT  42.636 0 42.66 0.192 ;
    END
  END t0[174]
  PIN t0[175]
    DIRECTION OUTPUT ;
    USE SIGNAL ;
    PORT
      LAYER M5 ;
        RECT  42.876 0 42.9 0.192 ;
    END
  END t0[175]
  PIN t0[176]
    DIRECTION OUTPUT ;
    USE SIGNAL ;
    PORT
      LAYER M5 ;
        RECT  43.116 0 43.14 0.192 ;
    END
  END t0[176]
  PIN t0[177]
    DIRECTION OUTPUT ;
    USE SIGNAL ;
    PORT
      LAYER M5 ;
        RECT  43.356 0 43.38 0.192 ;
    END
  END t0[177]
  PIN t0[178]
    DIRECTION OUTPUT ;
    USE SIGNAL ;
    PORT
      LAYER M5 ;
        RECT  43.596 0 43.62 0.192 ;
    END
  END t0[178]
  PIN t0[179]
    DIRECTION OUTPUT ;
    USE SIGNAL ;
    PORT
      LAYER M5 ;
        RECT  43.788 0 43.812 0.192 ;
    END
  END t0[179]
  PIN t0[17]
    DIRECTION OUTPUT ;
    USE SIGNAL ;
    PORT
      LAYER M5 ;
        RECT  6.06 0 6.084 0.192 ;
    END
  END t0[17]
  PIN t0[180]
    DIRECTION OUTPUT ;
    USE SIGNAL ;
    PORT
      LAYER M5 ;
        RECT  44.028 0 44.052 0.192 ;
    END
  END t0[180]
  PIN t0[181]
    DIRECTION OUTPUT ;
    USE SIGNAL ;
    PORT
      LAYER M5 ;
        RECT  44.268 0 44.292 0.192 ;
    END
  END t0[181]
  PIN t0[182]
    DIRECTION OUTPUT ;
    USE SIGNAL ;
    PORT
      LAYER M5 ;
        RECT  44.508 0 44.532 0.192 ;
    END
  END t0[182]
  PIN t0[183]
    DIRECTION OUTPUT ;
    USE SIGNAL ;
    PORT
      LAYER M5 ;
        RECT  44.748 0 44.772 0.192 ;
    END
  END t0[183]
  PIN t0[184]
    DIRECTION OUTPUT ;
    USE SIGNAL ;
    PORT
      LAYER M5 ;
        RECT  44.988 0 45.012 0.192 ;
    END
  END t0[184]
  PIN t0[185]
    DIRECTION OUTPUT ;
    USE SIGNAL ;
    PORT
      LAYER M5 ;
        RECT  45.18 0 45.204 0.192 ;
    END
  END t0[185]
  PIN t0[186]
    DIRECTION OUTPUT ;
    USE SIGNAL ;
    PORT
      LAYER M5 ;
        RECT  45.42 0 45.444 0.192 ;
    END
  END t0[186]
  PIN t0[187]
    DIRECTION OUTPUT ;
    USE SIGNAL ;
    PORT
      LAYER M5 ;
        RECT  45.66 0 45.684 0.192 ;
    END
  END t0[187]
  PIN t0[188]
    DIRECTION OUTPUT ;
    USE SIGNAL ;
    PORT
      LAYER M5 ;
        RECT  45.9 0 45.924 0.192 ;
    END
  END t0[188]
  PIN t0[189]
    DIRECTION OUTPUT ;
    USE SIGNAL ;
    PORT
      LAYER M5 ;
        RECT  46.14 0 46.164 0.192 ;
    END
  END t0[189]
  PIN t0[18]
    DIRECTION OUTPUT ;
    USE SIGNAL ;
    PORT
      LAYER M5 ;
        RECT  6.3 0 6.324 0.192 ;
    END
  END t0[18]
  PIN t0[190]
    DIRECTION OUTPUT ;
    USE SIGNAL ;
    PORT
      LAYER M5 ;
        RECT  46.38 0 46.404 0.192 ;
    END
  END t0[190]
  PIN t0[191]
    DIRECTION OUTPUT ;
    USE SIGNAL ;
    PORT
      LAYER M5 ;
        RECT  46.62 0 46.644 0.192 ;
    END
  END t0[191]
  PIN t0[192]
    DIRECTION OUTPUT ;
    USE SIGNAL ;
    PORT
      LAYER M5 ;
        RECT  46.812 0 46.836 0.192 ;
    END
  END t0[192]
  PIN t0[193]
    DIRECTION OUTPUT ;
    USE SIGNAL ;
    PORT
      LAYER M5 ;
        RECT  47.052 0 47.076 0.192 ;
    END
  END t0[193]
  PIN t0[194]
    DIRECTION OUTPUT ;
    USE SIGNAL ;
    PORT
      LAYER M5 ;
        RECT  47.292 0 47.316 0.192 ;
    END
  END t0[194]
  PIN t0[195]
    DIRECTION OUTPUT ;
    USE SIGNAL ;
    PORT
      LAYER M5 ;
        RECT  47.532 0 47.556 0.192 ;
    END
  END t0[195]
  PIN t0[196]
    DIRECTION OUTPUT ;
    USE SIGNAL ;
    PORT
      LAYER M5 ;
        RECT  47.772 0 47.796 0.192 ;
    END
  END t0[196]
  PIN t0[197]
    DIRECTION OUTPUT ;
    USE SIGNAL ;
    PORT
      LAYER M5 ;
        RECT  48.012 0 48.036 0.192 ;
    END
  END t0[197]
  PIN t0[198]
    DIRECTION OUTPUT ;
    USE SIGNAL ;
    PORT
      LAYER M5 ;
        RECT  48.252 0 48.276 0.192 ;
    END
  END t0[198]
  PIN t0[199]
    DIRECTION OUTPUT ;
    USE SIGNAL ;
    PORT
      LAYER M5 ;
        RECT  48.444 0 48.468 0.192 ;
    END
  END t0[199]
  PIN t0[19]
    DIRECTION OUTPUT ;
    USE SIGNAL ;
    PORT
      LAYER M5 ;
        RECT  6.54 0 6.564 0.192 ;
    END
  END t0[19]
  PIN t0[1]
    DIRECTION OUTPUT ;
    USE SIGNAL ;
    PORT
      LAYER M5 ;
        RECT  2.316 0 2.34 0.192 ;
    END
  END t0[1]
  PIN t0[200]
    DIRECTION OUTPUT ;
    USE SIGNAL ;
    PORT
      LAYER M5 ;
        RECT  48.684 0 48.708 0.192 ;
    END
  END t0[200]
  PIN t0[201]
    DIRECTION OUTPUT ;
    USE SIGNAL ;
    PORT
      LAYER M5 ;
        RECT  48.924 0 48.948 0.192 ;
    END
  END t0[201]
  PIN t0[202]
    DIRECTION OUTPUT ;
    USE SIGNAL ;
    PORT
      LAYER M5 ;
        RECT  49.164 0 49.188 0.192 ;
    END
  END t0[202]
  PIN t0[203]
    DIRECTION OUTPUT ;
    USE SIGNAL ;
    PORT
      LAYER M5 ;
        RECT  49.404 0 49.428 0.192 ;
    END
  END t0[203]
  PIN t0[204]
    DIRECTION OUTPUT ;
    USE SIGNAL ;
    PORT
      LAYER M5 ;
        RECT  49.644 0 49.668 0.192 ;
    END
  END t0[204]
  PIN t0[205]
    DIRECTION OUTPUT ;
    USE SIGNAL ;
    PORT
      LAYER M5 ;
        RECT  49.884 0 49.908 0.192 ;
    END
  END t0[205]
  PIN t0[206]
    DIRECTION OUTPUT ;
    USE SIGNAL ;
    PORT
      LAYER M5 ;
        RECT  50.076 0 50.1 0.192 ;
    END
  END t0[206]
  PIN t0[207]
    DIRECTION OUTPUT ;
    USE SIGNAL ;
    PORT
      LAYER M5 ;
        RECT  50.316 0 50.34 0.192 ;
    END
  END t0[207]
  PIN t0[208]
    DIRECTION OUTPUT ;
    USE SIGNAL ;
    PORT
      LAYER M5 ;
        RECT  50.556 0 50.58 0.192 ;
    END
  END t0[208]
  PIN t0[209]
    DIRECTION OUTPUT ;
    USE SIGNAL ;
    PORT
      LAYER M5 ;
        RECT  50.796 0 50.82 0.192 ;
    END
  END t0[209]
  PIN t0[20]
    DIRECTION OUTPUT ;
    USE SIGNAL ;
    PORT
      LAYER M5 ;
        RECT  6.78 0 6.804 0.192 ;
    END
  END t0[20]
  PIN t0[210]
    DIRECTION OUTPUT ;
    USE SIGNAL ;
    PORT
      LAYER M5 ;
        RECT  51.036 0 51.06 0.192 ;
    END
  END t0[210]
  PIN t0[211]
    DIRECTION OUTPUT ;
    USE SIGNAL ;
    PORT
      LAYER M5 ;
        RECT  51.276 0 51.3 0.192 ;
    END
  END t0[211]
  PIN t0[212]
    DIRECTION OUTPUT ;
    USE SIGNAL ;
    PORT
      LAYER M5 ;
        RECT  51.516 0 51.54 0.192 ;
    END
  END t0[212]
  PIN t0[213]
    DIRECTION OUTPUT ;
    USE SIGNAL ;
    PORT
      LAYER M5 ;
        RECT  51.708 0 51.732 0.192 ;
    END
  END t0[213]
  PIN t0[214]
    DIRECTION OUTPUT ;
    USE SIGNAL ;
    PORT
      LAYER M5 ;
        RECT  51.948 0 51.972 0.192 ;
    END
  END t0[214]
  PIN t0[215]
    DIRECTION OUTPUT ;
    USE SIGNAL ;
    PORT
      LAYER M5 ;
        RECT  52.188 0 52.212 0.192 ;
    END
  END t0[215]
  PIN t0[216]
    DIRECTION OUTPUT ;
    USE SIGNAL ;
    PORT
      LAYER M5 ;
        RECT  52.428 0 52.452 0.192 ;
    END
  END t0[216]
  PIN t0[217]
    DIRECTION OUTPUT ;
    USE SIGNAL ;
    PORT
      LAYER M5 ;
        RECT  52.668 0 52.692 0.192 ;
    END
  END t0[217]
  PIN t0[218]
    DIRECTION OUTPUT ;
    USE SIGNAL ;
    PORT
      LAYER M5 ;
        RECT  52.908 0 52.932 0.192 ;
    END
  END t0[218]
  PIN t0[219]
    DIRECTION OUTPUT ;
    USE SIGNAL ;
    PORT
      LAYER M5 ;
        RECT  53.148 0 53.172 0.192 ;
    END
  END t0[219]
  PIN t0[21]
    DIRECTION OUTPUT ;
    USE SIGNAL ;
    PORT
      LAYER M5 ;
        RECT  7.02 0 7.044 0.192 ;
    END
  END t0[21]
  PIN t0[220]
    DIRECTION OUTPUT ;
    USE SIGNAL ;
    PORT
      LAYER M5 ;
        RECT  53.34 0 53.364 0.192 ;
    END
  END t0[220]
  PIN t0[221]
    DIRECTION OUTPUT ;
    USE SIGNAL ;
    PORT
      LAYER M5 ;
        RECT  53.58 0 53.604 0.192 ;
    END
  END t0[221]
  PIN t0[222]
    DIRECTION OUTPUT ;
    USE SIGNAL ;
    PORT
      LAYER M5 ;
        RECT  53.82 0 53.844 0.192 ;
    END
  END t0[222]
  PIN t0[223]
    DIRECTION OUTPUT ;
    USE SIGNAL ;
    PORT
      LAYER M5 ;
        RECT  54.06 0 54.084 0.192 ;
    END
  END t0[223]
  PIN t0[224]
    DIRECTION OUTPUT ;
    USE SIGNAL ;
    PORT
      LAYER M5 ;
        RECT  54.3 0 54.324 0.192 ;
    END
  END t0[224]
  PIN t0[225]
    DIRECTION OUTPUT ;
    USE SIGNAL ;
    PORT
      LAYER M5 ;
        RECT  54.54 0 54.564 0.192 ;
    END
  END t0[225]
  PIN t0[226]
    DIRECTION OUTPUT ;
    USE SIGNAL ;
    PORT
      LAYER M5 ;
        RECT  54.732 0 54.756 0.192 ;
    END
  END t0[226]
  PIN t0[227]
    DIRECTION OUTPUT ;
    USE SIGNAL ;
    PORT
      LAYER M5 ;
        RECT  54.972 0 54.996 0.192 ;
    END
  END t0[227]
  PIN t0[228]
    DIRECTION OUTPUT ;
    USE SIGNAL ;
    PORT
      LAYER M5 ;
        RECT  55.212 0 55.236 0.192 ;
    END
  END t0[228]
  PIN t0[229]
    DIRECTION OUTPUT ;
    USE SIGNAL ;
    PORT
      LAYER M5 ;
        RECT  55.452 0 55.476 0.192 ;
    END
  END t0[229]
  PIN t0[22]
    DIRECTION OUTPUT ;
    USE SIGNAL ;
    PORT
      LAYER M5 ;
        RECT  7.212 0 7.236 0.192 ;
    END
  END t0[22]
  PIN t0[230]
    DIRECTION OUTPUT ;
    USE SIGNAL ;
    PORT
      LAYER M5 ;
        RECT  55.692 0 55.716 0.192 ;
    END
  END t0[230]
  PIN t0[231]
    DIRECTION OUTPUT ;
    USE SIGNAL ;
    PORT
      LAYER M5 ;
        RECT  55.932 0 55.956 0.192 ;
    END
  END t0[231]
  PIN t0[232]
    DIRECTION OUTPUT ;
    USE SIGNAL ;
    PORT
      LAYER M5 ;
        RECT  56.172 0 56.196 0.192 ;
    END
  END t0[232]
  PIN t0[233]
    DIRECTION OUTPUT ;
    USE SIGNAL ;
    PORT
      LAYER M5 ;
        RECT  56.364 0 56.388 0.192 ;
    END
  END t0[233]
  PIN t0[234]
    DIRECTION OUTPUT ;
    USE SIGNAL ;
    PORT
      LAYER M5 ;
        RECT  56.604 0 56.628 0.192 ;
    END
  END t0[234]
  PIN t0[235]
    DIRECTION OUTPUT ;
    USE SIGNAL ;
    PORT
      LAYER M5 ;
        RECT  56.844 0 56.868 0.192 ;
    END
  END t0[235]
  PIN t0[236]
    DIRECTION OUTPUT ;
    USE SIGNAL ;
    PORT
      LAYER M5 ;
        RECT  57.084 0 57.108 0.192 ;
    END
  END t0[236]
  PIN t0[237]
    DIRECTION OUTPUT ;
    USE SIGNAL ;
    PORT
      LAYER M5 ;
        RECT  57.324 0 57.348 0.192 ;
    END
  END t0[237]
  PIN t0[238]
    DIRECTION OUTPUT ;
    USE SIGNAL ;
    PORT
      LAYER M5 ;
        RECT  57.564 0 57.588 0.192 ;
    END
  END t0[238]
  PIN t0[239]
    DIRECTION OUTPUT ;
    USE SIGNAL ;
    PORT
      LAYER M5 ;
        RECT  57.804 0 57.828 0.192 ;
    END
  END t0[239]
  PIN t0[23]
    DIRECTION OUTPUT ;
    USE SIGNAL ;
    PORT
      LAYER M5 ;
        RECT  7.452 0 7.476 0.192 ;
    END
  END t0[23]
  PIN t0[240]
    DIRECTION OUTPUT ;
    USE SIGNAL ;
    PORT
      LAYER M5 ;
        RECT  57.996 0 58.02 0.192 ;
    END
  END t0[240]
  PIN t0[241]
    DIRECTION OUTPUT ;
    USE SIGNAL ;
    PORT
      LAYER M5 ;
        RECT  58.236 0 58.26 0.192 ;
    END
  END t0[241]
  PIN t0[242]
    DIRECTION OUTPUT ;
    USE SIGNAL ;
    PORT
      LAYER M5 ;
        RECT  58.476 0 58.5 0.192 ;
    END
  END t0[242]
  PIN t0[243]
    DIRECTION OUTPUT ;
    USE SIGNAL ;
    PORT
      LAYER M5 ;
        RECT  58.716 0 58.74 0.192 ;
    END
  END t0[243]
  PIN t0[244]
    DIRECTION OUTPUT ;
    USE SIGNAL ;
    PORT
      LAYER M5 ;
        RECT  58.956 0 58.98 0.192 ;
    END
  END t0[244]
  PIN t0[245]
    DIRECTION OUTPUT ;
    USE SIGNAL ;
    PORT
      LAYER M5 ;
        RECT  59.196 0 59.22 0.192 ;
    END
  END t0[245]
  PIN t0[246]
    DIRECTION OUTPUT ;
    USE SIGNAL ;
    PORT
      LAYER M5 ;
        RECT  59.436 0 59.46 0.192 ;
    END
  END t0[246]
  PIN t0[247]
    DIRECTION OUTPUT ;
    USE SIGNAL ;
    PORT
      LAYER M5 ;
        RECT  59.628 0 59.652 0.192 ;
    END
  END t0[247]
  PIN t0[248]
    DIRECTION OUTPUT ;
    USE SIGNAL ;
    PORT
      LAYER M5 ;
        RECT  59.868 0 59.892 0.192 ;
    END
  END t0[248]
  PIN t0[249]
    DIRECTION OUTPUT ;
    USE SIGNAL ;
    PORT
      LAYER M5 ;
        RECT  60.108 0 60.132 0.192 ;
    END
  END t0[249]
  PIN t0[24]
    DIRECTION OUTPUT ;
    USE SIGNAL ;
    PORT
      LAYER M5 ;
        RECT  7.692 0 7.716 0.192 ;
    END
  END t0[24]
  PIN t0[250]
    DIRECTION OUTPUT ;
    USE SIGNAL ;
    PORT
      LAYER M5 ;
        RECT  60.348 0 60.372 0.192 ;
    END
  END t0[250]
  PIN t0[251]
    DIRECTION OUTPUT ;
    USE SIGNAL ;
    PORT
      LAYER M5 ;
        RECT  60.588 0 60.612 0.192 ;
    END
  END t0[251]
  PIN t0[252]
    DIRECTION OUTPUT ;
    USE SIGNAL ;
    PORT
      LAYER M5 ;
        RECT  60.828 0 60.852 0.192 ;
    END
  END t0[252]
  PIN t0[253]
    DIRECTION OUTPUT ;
    USE SIGNAL ;
    PORT
      LAYER M5 ;
        RECT  61.068 0 61.092 0.192 ;
    END
  END t0[253]
  PIN t0[254]
    DIRECTION OUTPUT ;
    USE SIGNAL ;
    PORT
      LAYER M5 ;
        RECT  61.26 0 61.284 0.192 ;
    END
  END t0[254]
  PIN t0[255]
    DIRECTION OUTPUT ;
    USE SIGNAL ;
    PORT
      LAYER M5 ;
        RECT  61.5 0 61.524 0.192 ;
    END
  END t0[255]
  PIN t0[256]
    DIRECTION OUTPUT ;
    USE SIGNAL ;
    PORT
      LAYER M5 ;
        RECT  61.74 0 61.764 0.192 ;
    END
  END t0[256]
  PIN t0[257]
    DIRECTION OUTPUT ;
    USE SIGNAL ;
    PORT
      LAYER M5 ;
        RECT  61.98 0 62.004 0.192 ;
    END
  END t0[257]
  PIN t0[258]
    DIRECTION OUTPUT ;
    USE SIGNAL ;
    PORT
      LAYER M5 ;
        RECT  62.22 0 62.244 0.192 ;
    END
  END t0[258]
  PIN t0[259]
    DIRECTION OUTPUT ;
    USE SIGNAL ;
    PORT
      LAYER M5 ;
        RECT  62.46 0 62.484 0.192 ;
    END
  END t0[259]
  PIN t0[25]
    DIRECTION OUTPUT ;
    USE SIGNAL ;
    PORT
      LAYER M5 ;
        RECT  7.932 0 7.956 0.192 ;
    END
  END t0[25]
  PIN t0[260]
    DIRECTION OUTPUT ;
    USE SIGNAL ;
    PORT
      LAYER M5 ;
        RECT  62.652 0 62.676 0.192 ;
    END
  END t0[260]
  PIN t0[261]
    DIRECTION OUTPUT ;
    USE SIGNAL ;
    PORT
      LAYER M5 ;
        RECT  62.892 0 62.916 0.192 ;
    END
  END t0[261]
  PIN t0[262]
    DIRECTION OUTPUT ;
    USE SIGNAL ;
    PORT
      LAYER M5 ;
        RECT  63.132 0 63.156 0.192 ;
    END
  END t0[262]
  PIN t0[263]
    DIRECTION OUTPUT ;
    USE SIGNAL ;
    PORT
      LAYER M5 ;
        RECT  63.372 0 63.396 0.192 ;
    END
  END t0[263]
  PIN t0[264]
    DIRECTION OUTPUT ;
    USE SIGNAL ;
    PORT
      LAYER M5 ;
        RECT  63.612 0 63.636 0.192 ;
    END
  END t0[264]
  PIN t0[265]
    DIRECTION OUTPUT ;
    USE SIGNAL ;
    PORT
      LAYER M5 ;
        RECT  63.852 0 63.876 0.192 ;
    END
  END t0[265]
  PIN t0[266]
    DIRECTION OUTPUT ;
    USE SIGNAL ;
    PORT
      LAYER M5 ;
        RECT  64.092 0 64.116 0.192 ;
    END
  END t0[266]
  PIN t0[267]
    DIRECTION OUTPUT ;
    USE SIGNAL ;
    PORT
      LAYER M5 ;
        RECT  64.284 0 64.308 0.192 ;
    END
  END t0[267]
  PIN t0[268]
    DIRECTION OUTPUT ;
    USE SIGNAL ;
    PORT
      LAYER M5 ;
        RECT  64.524 0 64.548 0.192 ;
    END
  END t0[268]
  PIN t0[269]
    DIRECTION OUTPUT ;
    USE SIGNAL ;
    PORT
      LAYER M5 ;
        RECT  64.764 0 64.788 0.192 ;
    END
  END t0[269]
  PIN t0[26]
    DIRECTION OUTPUT ;
    USE SIGNAL ;
    PORT
      LAYER M5 ;
        RECT  8.172 0 8.196 0.192 ;
    END
  END t0[26]
  PIN t0[270]
    DIRECTION OUTPUT ;
    USE SIGNAL ;
    PORT
      LAYER M5 ;
        RECT  65.004 0 65.028 0.192 ;
    END
  END t0[270]
  PIN t0[271]
    DIRECTION OUTPUT ;
    USE SIGNAL ;
    PORT
      LAYER M5 ;
        RECT  65.244 0 65.268 0.192 ;
    END
  END t0[271]
  PIN t0[272]
    DIRECTION OUTPUT ;
    USE SIGNAL ;
    PORT
      LAYER M5 ;
        RECT  65.484 0 65.508 0.192 ;
    END
  END t0[272]
  PIN t0[273]
    DIRECTION OUTPUT ;
    USE SIGNAL ;
    PORT
      LAYER M5 ;
        RECT  65.724 0 65.748 0.192 ;
    END
  END t0[273]
  PIN t0[274]
    DIRECTION OUTPUT ;
    USE SIGNAL ;
    PORT
      LAYER M5 ;
        RECT  65.916 0 65.94 0.192 ;
    END
  END t0[274]
  PIN t0[275]
    DIRECTION OUTPUT ;
    USE SIGNAL ;
    PORT
      LAYER M5 ;
        RECT  66.156 0 66.18 0.192 ;
    END
  END t0[275]
  PIN t0[276]
    DIRECTION OUTPUT ;
    USE SIGNAL ;
    PORT
      LAYER M5 ;
        RECT  66.396 0 66.42 0.192 ;
    END
  END t0[276]
  PIN t0[277]
    DIRECTION OUTPUT ;
    USE SIGNAL ;
    PORT
      LAYER M5 ;
        RECT  66.636 0 66.66 0.192 ;
    END
  END t0[277]
  PIN t0[278]
    DIRECTION OUTPUT ;
    USE SIGNAL ;
    PORT
      LAYER M5 ;
        RECT  66.876 0 66.9 0.192 ;
    END
  END t0[278]
  PIN t0[279]
    DIRECTION OUTPUT ;
    USE SIGNAL ;
    PORT
      LAYER M5 ;
        RECT  67.116 0 67.14 0.192 ;
    END
  END t0[279]
  PIN t0[27]
    DIRECTION OUTPUT ;
    USE SIGNAL ;
    PORT
      LAYER M5 ;
        RECT  8.412 0 8.436 0.192 ;
    END
  END t0[27]
  PIN t0[280]
    DIRECTION OUTPUT ;
    USE SIGNAL ;
    PORT
      LAYER M5 ;
        RECT  67.356 0 67.38 0.192 ;
    END
  END t0[280]
  PIN t0[281]
    DIRECTION OUTPUT ;
    USE SIGNAL ;
    PORT
      LAYER M5 ;
        RECT  67.548 0 67.572 0.192 ;
    END
  END t0[281]
  PIN t0[282]
    DIRECTION OUTPUT ;
    USE SIGNAL ;
    PORT
      LAYER M5 ;
        RECT  67.788 0 67.812 0.192 ;
    END
  END t0[282]
  PIN t0[283]
    DIRECTION OUTPUT ;
    USE SIGNAL ;
    PORT
      LAYER M5 ;
        RECT  68.028 0 68.052 0.192 ;
    END
  END t0[283]
  PIN t0[284]
    DIRECTION OUTPUT ;
    USE SIGNAL ;
    PORT
      LAYER M5 ;
        RECT  68.268 0 68.292 0.192 ;
    END
  END t0[284]
  PIN t0[285]
    DIRECTION OUTPUT ;
    USE SIGNAL ;
    PORT
      LAYER M5 ;
        RECT  68.508 0 68.532 0.192 ;
    END
  END t0[285]
  PIN t0[286]
    DIRECTION OUTPUT ;
    USE SIGNAL ;
    PORT
      LAYER M5 ;
        RECT  68.748 0 68.772 0.192 ;
    END
  END t0[286]
  PIN t0[287]
    DIRECTION OUTPUT ;
    USE SIGNAL ;
    PORT
      LAYER M5 ;
        RECT  68.988 0 69.012 0.192 ;
    END
  END t0[287]
  PIN t0[288]
    DIRECTION OUTPUT ;
    USE SIGNAL ;
    PORT
      LAYER M5 ;
        RECT  69.18 0 69.204 0.192 ;
    END
  END t0[288]
  PIN t0[289]
    DIRECTION OUTPUT ;
    USE SIGNAL ;
    PORT
      LAYER M5 ;
        RECT  69.42 0 69.444 0.192 ;
    END
  END t0[289]
  PIN t0[28]
    DIRECTION OUTPUT ;
    USE SIGNAL ;
    PORT
      LAYER M5 ;
        RECT  8.604 0 8.628 0.192 ;
    END
  END t0[28]
  PIN t0[290]
    DIRECTION OUTPUT ;
    USE SIGNAL ;
    PORT
      LAYER M5 ;
        RECT  69.66 0 69.684 0.192 ;
    END
  END t0[290]
  PIN t0[291]
    DIRECTION OUTPUT ;
    USE SIGNAL ;
    PORT
      LAYER M5 ;
        RECT  69.9 0 69.924 0.192 ;
    END
  END t0[291]
  PIN t0[292]
    DIRECTION OUTPUT ;
    USE SIGNAL ;
    PORT
      LAYER M5 ;
        RECT  70.14 0 70.164 0.192 ;
    END
  END t0[292]
  PIN t0[293]
    DIRECTION OUTPUT ;
    USE SIGNAL ;
    PORT
      LAYER M5 ;
        RECT  70.38 0 70.404 0.192 ;
    END
  END t0[293]
  PIN t0[294]
    DIRECTION OUTPUT ;
    USE SIGNAL ;
    PORT
      LAYER M5 ;
        RECT  70.62 0 70.644 0.192 ;
    END
  END t0[294]
  PIN t0[295]
    DIRECTION OUTPUT ;
    USE SIGNAL ;
    PORT
      LAYER M5 ;
        RECT  70.812 0 70.836 0.192 ;
    END
  END t0[295]
  PIN t0[296]
    DIRECTION OUTPUT ;
    USE SIGNAL ;
    PORT
      LAYER M5 ;
        RECT  71.052 0 71.076 0.192 ;
    END
  END t0[296]
  PIN t0[297]
    DIRECTION OUTPUT ;
    USE SIGNAL ;
    PORT
      LAYER M5 ;
        RECT  71.292 0 71.316 0.192 ;
    END
  END t0[297]
  PIN t0[298]
    DIRECTION OUTPUT ;
    USE SIGNAL ;
    PORT
      LAYER M5 ;
        RECT  71.532 0 71.556 0.192 ;
    END
  END t0[298]
  PIN t0[299]
    DIRECTION OUTPUT ;
    USE SIGNAL ;
    PORT
      LAYER M5 ;
        RECT  71.772 0 71.796 0.192 ;
    END
  END t0[299]
  PIN t0[29]
    DIRECTION OUTPUT ;
    USE SIGNAL ;
    PORT
      LAYER M5 ;
        RECT  8.844 0 8.868 0.192 ;
    END
  END t0[29]
  PIN t0[2]
    DIRECTION OUTPUT ;
    USE SIGNAL ;
    PORT
      LAYER M5 ;
        RECT  2.556 0 2.58 0.192 ;
    END
  END t0[2]
  PIN t0[300]
    DIRECTION OUTPUT ;
    USE SIGNAL ;
    PORT
      LAYER M5 ;
        RECT  72.012 0 72.036 0.192 ;
    END
  END t0[300]
  PIN t0[301]
    DIRECTION OUTPUT ;
    USE SIGNAL ;
    PORT
      LAYER M5 ;
        RECT  72.204 0 72.228 0.192 ;
    END
  END t0[301]
  PIN t0[302]
    DIRECTION OUTPUT ;
    USE SIGNAL ;
    PORT
      LAYER M5 ;
        RECT  72.444 0 72.468 0.192 ;
    END
  END t0[302]
  PIN t0[303]
    DIRECTION OUTPUT ;
    USE SIGNAL ;
    PORT
      LAYER M5 ;
        RECT  72.684 0 72.708 0.192 ;
    END
  END t0[303]
  PIN t0[304]
    DIRECTION OUTPUT ;
    USE SIGNAL ;
    PORT
      LAYER M5 ;
        RECT  72.924 0 72.948 0.192 ;
    END
  END t0[304]
  PIN t0[305]
    DIRECTION OUTPUT ;
    USE SIGNAL ;
    PORT
      LAYER M5 ;
        RECT  73.164 0 73.188 0.192 ;
    END
  END t0[305]
  PIN t0[306]
    DIRECTION OUTPUT ;
    USE SIGNAL ;
    PORT
      LAYER M5 ;
        RECT  73.404 0 73.428 0.192 ;
    END
  END t0[306]
  PIN t0[307]
    DIRECTION OUTPUT ;
    USE SIGNAL ;
    PORT
      LAYER M5 ;
        RECT  73.644 0 73.668 0.192 ;
    END
  END t0[307]
  PIN t0[308]
    DIRECTION OUTPUT ;
    USE SIGNAL ;
    PORT
      LAYER M5 ;
        RECT  73.836 0 73.86 0.192 ;
    END
  END t0[308]
  PIN t0[309]
    DIRECTION OUTPUT ;
    USE SIGNAL ;
    PORT
      LAYER M5 ;
        RECT  74.076 0 74.1 0.192 ;
    END
  END t0[309]
  PIN t0[30]
    DIRECTION OUTPUT ;
    USE SIGNAL ;
    PORT
      LAYER M5 ;
        RECT  9.084 0 9.108 0.192 ;
    END
  END t0[30]
  PIN t0[310]
    DIRECTION OUTPUT ;
    USE SIGNAL ;
    PORT
      LAYER M5 ;
        RECT  74.316 0 74.34 0.192 ;
    END
  END t0[310]
  PIN t0[311]
    DIRECTION OUTPUT ;
    USE SIGNAL ;
    PORT
      LAYER M5 ;
        RECT  74.556 0 74.58 0.192 ;
    END
  END t0[311]
  PIN t0[312]
    DIRECTION OUTPUT ;
    USE SIGNAL ;
    PORT
      LAYER M5 ;
        RECT  74.796 0 74.82 0.192 ;
    END
  END t0[312]
  PIN t0[313]
    DIRECTION OUTPUT ;
    USE SIGNAL ;
    PORT
      LAYER M5 ;
        RECT  75.036 0 75.06 0.192 ;
    END
  END t0[313]
  PIN t0[314]
    DIRECTION OUTPUT ;
    USE SIGNAL ;
    PORT
      LAYER M5 ;
        RECT  75.276 0 75.3 0.192 ;
    END
  END t0[314]
  PIN t0[315]
    DIRECTION OUTPUT ;
    USE SIGNAL ;
    PORT
      LAYER M5 ;
        RECT  75.468 0 75.492 0.192 ;
    END
  END t0[315]
  PIN t0[316]
    DIRECTION OUTPUT ;
    USE SIGNAL ;
    PORT
      LAYER M5 ;
        RECT  75.708 0 75.732 0.192 ;
    END
  END t0[316]
  PIN t0[317]
    DIRECTION OUTPUT ;
    USE SIGNAL ;
    PORT
      LAYER M5 ;
        RECT  75.948 0 75.972 0.192 ;
    END
  END t0[317]
  PIN t0[318]
    DIRECTION OUTPUT ;
    USE SIGNAL ;
    PORT
      LAYER M5 ;
        RECT  76.188 0 76.212 0.192 ;
    END
  END t0[318]
  PIN t0[319]
    DIRECTION OUTPUT ;
    USE SIGNAL ;
    PORT
      LAYER M5 ;
        RECT  76.428 0 76.452 0.192 ;
    END
  END t0[319]
  PIN t0[31]
    DIRECTION OUTPUT ;
    USE SIGNAL ;
    PORT
      LAYER M5 ;
        RECT  9.324 0 9.348 0.192 ;
    END
  END t0[31]
  PIN t0[320]
    DIRECTION OUTPUT ;
    USE SIGNAL ;
    PORT
      LAYER M5 ;
        RECT  76.668 0 76.692 0.192 ;
    END
  END t0[320]
  PIN t0[321]
    DIRECTION OUTPUT ;
    USE SIGNAL ;
    PORT
      LAYER M5 ;
        RECT  76.908 0 76.932 0.192 ;
    END
  END t0[321]
  PIN t0[322]
    DIRECTION OUTPUT ;
    USE SIGNAL ;
    PORT
      LAYER M5 ;
        RECT  77.1 0 77.124 0.192 ;
    END
  END t0[322]
  PIN t0[323]
    DIRECTION OUTPUT ;
    USE SIGNAL ;
    PORT
      LAYER M5 ;
        RECT  77.34 0 77.364 0.192 ;
    END
  END t0[323]
  PIN t0[324]
    DIRECTION OUTPUT ;
    USE SIGNAL ;
    PORT
      LAYER M5 ;
        RECT  77.58 0 77.604 0.192 ;
    END
  END t0[324]
  PIN t0[325]
    DIRECTION OUTPUT ;
    USE SIGNAL ;
    PORT
      LAYER M5 ;
        RECT  77.82 0 77.844 0.192 ;
    END
  END t0[325]
  PIN t0[326]
    DIRECTION OUTPUT ;
    USE SIGNAL ;
    PORT
      LAYER M5 ;
        RECT  78.06 0 78.084 0.192 ;
    END
  END t0[326]
  PIN t0[327]
    DIRECTION OUTPUT ;
    USE SIGNAL ;
    PORT
      LAYER M5 ;
        RECT  78.3 0 78.324 0.192 ;
    END
  END t0[327]
  PIN t0[328]
    DIRECTION OUTPUT ;
    USE SIGNAL ;
    PORT
      LAYER M5 ;
        RECT  78.54 0 78.564 0.192 ;
    END
  END t0[328]
  PIN t0[329]
    DIRECTION OUTPUT ;
    USE SIGNAL ;
    PORT
      LAYER M5 ;
        RECT  78.732 0 78.756 0.192 ;
    END
  END t0[329]
  PIN t0[32]
    DIRECTION OUTPUT ;
    USE SIGNAL ;
    PORT
      LAYER M5 ;
        RECT  9.564 0 9.588 0.192 ;
    END
  END t0[32]
  PIN t0[330]
    DIRECTION OUTPUT ;
    USE SIGNAL ;
    PORT
      LAYER M5 ;
        RECT  78.972 0 78.996 0.192 ;
    END
  END t0[330]
  PIN t0[331]
    DIRECTION OUTPUT ;
    USE SIGNAL ;
    PORT
      LAYER M5 ;
        RECT  79.212 0 79.236 0.192 ;
    END
  END t0[331]
  PIN t0[332]
    DIRECTION OUTPUT ;
    USE SIGNAL ;
    PORT
      LAYER M5 ;
        RECT  79.452 0 79.476 0.192 ;
    END
  END t0[332]
  PIN t0[333]
    DIRECTION OUTPUT ;
    USE SIGNAL ;
    PORT
      LAYER M5 ;
        RECT  79.692 0 79.716 0.192 ;
    END
  END t0[333]
  PIN t0[334]
    DIRECTION OUTPUT ;
    USE SIGNAL ;
    PORT
      LAYER M5 ;
        RECT  79.932 0 79.956 0.192 ;
    END
  END t0[334]
  PIN t0[335]
    DIRECTION OUTPUT ;
    USE SIGNAL ;
    PORT
      LAYER M5 ;
        RECT  80.172 0 80.196 0.192 ;
    END
  END t0[335]
  PIN t0[336]
    DIRECTION OUTPUT ;
    USE SIGNAL ;
    PORT
      LAYER M5 ;
        RECT  80.364 0 80.388 0.192 ;
    END
  END t0[336]
  PIN t0[337]
    DIRECTION OUTPUT ;
    USE SIGNAL ;
    PORT
      LAYER M5 ;
        RECT  80.604 0 80.628 0.192 ;
    END
  END t0[337]
  PIN t0[338]
    DIRECTION OUTPUT ;
    USE SIGNAL ;
    PORT
      LAYER M5 ;
        RECT  80.844 0 80.868 0.192 ;
    END
  END t0[338]
  PIN t0[339]
    DIRECTION OUTPUT ;
    USE SIGNAL ;
    PORT
      LAYER M5 ;
        RECT  81.084 0 81.108 0.192 ;
    END
  END t0[339]
  PIN t0[33]
    DIRECTION OUTPUT ;
    USE SIGNAL ;
    PORT
      LAYER M5 ;
        RECT  9.804 0 9.828 0.192 ;
    END
  END t0[33]
  PIN t0[340]
    DIRECTION OUTPUT ;
    USE SIGNAL ;
    PORT
      LAYER M5 ;
        RECT  81.324 0 81.348 0.192 ;
    END
  END t0[340]
  PIN t0[341]
    DIRECTION OUTPUT ;
    USE SIGNAL ;
    PORT
      LAYER M5 ;
        RECT  81.564 0 81.588 0.192 ;
    END
  END t0[341]
  PIN t0[342]
    DIRECTION OUTPUT ;
    USE SIGNAL ;
    PORT
      LAYER M5 ;
        RECT  81.756 0 81.78 0.192 ;
    END
  END t0[342]
  PIN t0[343]
    DIRECTION OUTPUT ;
    USE SIGNAL ;
    PORT
      LAYER M5 ;
        RECT  81.996 0 82.02 0.192 ;
    END
  END t0[343]
  PIN t0[344]
    DIRECTION OUTPUT ;
    USE SIGNAL ;
    PORT
      LAYER M5 ;
        RECT  82.236 0 82.26 0.192 ;
    END
  END t0[344]
  PIN t0[345]
    DIRECTION OUTPUT ;
    USE SIGNAL ;
    PORT
      LAYER M5 ;
        RECT  82.476 0 82.5 0.192 ;
    END
  END t0[345]
  PIN t0[346]
    DIRECTION OUTPUT ;
    USE SIGNAL ;
    PORT
      LAYER M5 ;
        RECT  82.716 0 82.74 0.192 ;
    END
  END t0[346]
  PIN t0[347]
    DIRECTION OUTPUT ;
    USE SIGNAL ;
    PORT
      LAYER M5 ;
        RECT  82.956 0 82.98 0.192 ;
    END
  END t0[347]
  PIN t0[348]
    DIRECTION OUTPUT ;
    USE SIGNAL ;
    PORT
      LAYER M5 ;
        RECT  83.196 0 83.22 0.192 ;
    END
  END t0[348]
  PIN t0[349]
    DIRECTION OUTPUT ;
    USE SIGNAL ;
    PORT
      LAYER M5 ;
        RECT  83.388 0 83.412 0.192 ;
    END
  END t0[349]
  PIN t0[34]
    DIRECTION OUTPUT ;
    USE SIGNAL ;
    PORT
      LAYER M5 ;
        RECT  10.044 0 10.068 0.192 ;
    END
  END t0[34]
  PIN t0[350]
    DIRECTION OUTPUT ;
    USE SIGNAL ;
    PORT
      LAYER M5 ;
        RECT  83.628 0 83.652 0.192 ;
    END
  END t0[350]
  PIN t0[351]
    DIRECTION OUTPUT ;
    USE SIGNAL ;
    PORT
      LAYER M5 ;
        RECT  83.868 0 83.892 0.192 ;
    END
  END t0[351]
  PIN t0[352]
    DIRECTION OUTPUT ;
    USE SIGNAL ;
    PORT
      LAYER M5 ;
        RECT  84.108 0 84.132 0.192 ;
    END
  END t0[352]
  PIN t0[353]
    DIRECTION OUTPUT ;
    USE SIGNAL ;
    PORT
      LAYER M5 ;
        RECT  84.348 0 84.372 0.192 ;
    END
  END t0[353]
  PIN t0[354]
    DIRECTION OUTPUT ;
    USE SIGNAL ;
    PORT
      LAYER M5 ;
        RECT  84.588 0 84.612 0.192 ;
    END
  END t0[354]
  PIN t0[355]
    DIRECTION OUTPUT ;
    USE SIGNAL ;
    PORT
      LAYER M5 ;
        RECT  84.828 0 84.852 0.192 ;
    END
  END t0[355]
  PIN t0[356]
    DIRECTION OUTPUT ;
    USE SIGNAL ;
    PORT
      LAYER M5 ;
        RECT  85.02 0 85.044 0.192 ;
    END
  END t0[356]
  PIN t0[357]
    DIRECTION OUTPUT ;
    USE SIGNAL ;
    PORT
      LAYER M5 ;
        RECT  85.26 0 85.284 0.192 ;
    END
  END t0[357]
  PIN t0[358]
    DIRECTION OUTPUT ;
    USE SIGNAL ;
    PORT
      LAYER M5 ;
        RECT  85.5 0 85.524 0.192 ;
    END
  END t0[358]
  PIN t0[359]
    DIRECTION OUTPUT ;
    USE SIGNAL ;
    PORT
      LAYER M5 ;
        RECT  85.74 0 85.764 0.192 ;
    END
  END t0[359]
  PIN t0[35]
    DIRECTION OUTPUT ;
    USE SIGNAL ;
    PORT
      LAYER M5 ;
        RECT  10.236 0 10.26 0.192 ;
    END
  END t0[35]
  PIN t0[360]
    DIRECTION OUTPUT ;
    USE SIGNAL ;
    PORT
      LAYER M5 ;
        RECT  85.98 0 86.004 0.192 ;
    END
  END t0[360]
  PIN t0[361]
    DIRECTION OUTPUT ;
    USE SIGNAL ;
    PORT
      LAYER M5 ;
        RECT  86.22 0 86.244 0.192 ;
    END
  END t0[361]
  PIN t0[362]
    DIRECTION OUTPUT ;
    USE SIGNAL ;
    PORT
      LAYER M5 ;
        RECT  86.46 0 86.484 0.192 ;
    END
  END t0[362]
  PIN t0[363]
    DIRECTION OUTPUT ;
    USE SIGNAL ;
    PORT
      LAYER M5 ;
        RECT  86.652 0 86.676 0.192 ;
    END
  END t0[363]
  PIN t0[364]
    DIRECTION OUTPUT ;
    USE SIGNAL ;
    PORT
      LAYER M5 ;
        RECT  86.892 0 86.916 0.192 ;
    END
  END t0[364]
  PIN t0[365]
    DIRECTION OUTPUT ;
    USE SIGNAL ;
    PORT
      LAYER M5 ;
        RECT  87.132 0 87.156 0.192 ;
    END
  END t0[365]
  PIN t0[366]
    DIRECTION OUTPUT ;
    USE SIGNAL ;
    PORT
      LAYER M5 ;
        RECT  87.372 0 87.396 0.192 ;
    END
  END t0[366]
  PIN t0[367]
    DIRECTION OUTPUT ;
    USE SIGNAL ;
    PORT
      LAYER M5 ;
        RECT  87.612 0 87.636 0.192 ;
    END
  END t0[367]
  PIN t0[368]
    DIRECTION OUTPUT ;
    USE SIGNAL ;
    PORT
      LAYER M5 ;
        RECT  87.852 0 87.876 0.192 ;
    END
  END t0[368]
  PIN t0[369]
    DIRECTION OUTPUT ;
    USE SIGNAL ;
    PORT
      LAYER M5 ;
        RECT  88.092 0 88.116 0.192 ;
    END
  END t0[369]
  PIN t0[36]
    DIRECTION OUTPUT ;
    USE SIGNAL ;
    PORT
      LAYER M5 ;
        RECT  10.476 0 10.5 0.192 ;
    END
  END t0[36]
  PIN t0[370]
    DIRECTION OUTPUT ;
    USE SIGNAL ;
    PORT
      LAYER M5 ;
        RECT  88.284 0 88.308 0.192 ;
    END
  END t0[370]
  PIN t0[371]
    DIRECTION OUTPUT ;
    USE SIGNAL ;
    PORT
      LAYER M5 ;
        RECT  88.524 0 88.548 0.192 ;
    END
  END t0[371]
  PIN t0[372]
    DIRECTION OUTPUT ;
    USE SIGNAL ;
    PORT
      LAYER M5 ;
        RECT  88.764 0 88.788 0.192 ;
    END
  END t0[372]
  PIN t0[373]
    DIRECTION OUTPUT ;
    USE SIGNAL ;
    PORT
      LAYER M5 ;
        RECT  89.004 0 89.028 0.192 ;
    END
  END t0[373]
  PIN t0[374]
    DIRECTION OUTPUT ;
    USE SIGNAL ;
    PORT
      LAYER M5 ;
        RECT  89.244 0 89.268 0.192 ;
    END
  END t0[374]
  PIN t0[375]
    DIRECTION OUTPUT ;
    USE SIGNAL ;
    PORT
      LAYER M5 ;
        RECT  89.484 0 89.508 0.192 ;
    END
  END t0[375]
  PIN t0[376]
    DIRECTION OUTPUT ;
    USE SIGNAL ;
    PORT
      LAYER M5 ;
        RECT  89.724 0 89.748 0.192 ;
    END
  END t0[376]
  PIN t0[377]
    DIRECTION OUTPUT ;
    USE SIGNAL ;
    PORT
      LAYER M5 ;
        RECT  89.916 0 89.94 0.192 ;
    END
  END t0[377]
  PIN t0[378]
    DIRECTION OUTPUT ;
    USE SIGNAL ;
    PORT
      LAYER M5 ;
        RECT  90.156 0 90.18 0.192 ;
    END
  END t0[378]
  PIN t0[379]
    DIRECTION OUTPUT ;
    USE SIGNAL ;
    PORT
      LAYER M5 ;
        RECT  90.396 0 90.42 0.192 ;
    END
  END t0[379]
  PIN t0[37]
    DIRECTION OUTPUT ;
    USE SIGNAL ;
    PORT
      LAYER M5 ;
        RECT  10.716 0 10.74 0.192 ;
    END
  END t0[37]
  PIN t0[380]
    DIRECTION OUTPUT ;
    USE SIGNAL ;
    PORT
      LAYER M5 ;
        RECT  90.636 0 90.66 0.192 ;
    END
  END t0[380]
  PIN t0[381]
    DIRECTION OUTPUT ;
    USE SIGNAL ;
    PORT
      LAYER M5 ;
        RECT  90.876 0 90.9 0.192 ;
    END
  END t0[381]
  PIN t0[382]
    DIRECTION OUTPUT ;
    USE SIGNAL ;
    PORT
      LAYER M5 ;
        RECT  91.116 0 91.14 0.192 ;
    END
  END t0[382]
  PIN t0[383]
    DIRECTION OUTPUT ;
    USE SIGNAL ;
    PORT
      LAYER M5 ;
        RECT  91.308 0 91.332 0.192 ;
    END
  END t0[383]
  PIN t0[384]
    DIRECTION OUTPUT ;
    USE SIGNAL ;
    PORT
      LAYER M5 ;
        RECT  91.548 0 91.572 0.192 ;
    END
  END t0[384]
  PIN t0[385]
    DIRECTION OUTPUT ;
    USE SIGNAL ;
    PORT
      LAYER M5 ;
        RECT  91.788 0 91.812 0.192 ;
    END
  END t0[385]
  PIN t0[386]
    DIRECTION OUTPUT ;
    USE SIGNAL ;
    PORT
      LAYER M5 ;
        RECT  92.028 0 92.052 0.192 ;
    END
  END t0[386]
  PIN t0[387]
    DIRECTION OUTPUT ;
    USE SIGNAL ;
    PORT
      LAYER M5 ;
        RECT  92.268 0 92.292 0.192 ;
    END
  END t0[387]
  PIN t0[388]
    DIRECTION OUTPUT ;
    USE SIGNAL ;
    PORT
      LAYER M5 ;
        RECT  92.508 0 92.532 0.192 ;
    END
  END t0[388]
  PIN t0[389]
    DIRECTION OUTPUT ;
    USE SIGNAL ;
    PORT
      LAYER M5 ;
        RECT  92.748 0 92.772 0.192 ;
    END
  END t0[389]
  PIN t0[38]
    DIRECTION OUTPUT ;
    USE SIGNAL ;
    PORT
      LAYER M5 ;
        RECT  10.956 0 10.98 0.192 ;
    END
  END t0[38]
  PIN t0[390]
    DIRECTION OUTPUT ;
    USE SIGNAL ;
    PORT
      LAYER M5 ;
        RECT  92.94 0 92.964 0.192 ;
    END
  END t0[390]
  PIN t0[391]
    DIRECTION OUTPUT ;
    USE SIGNAL ;
    PORT
      LAYER M5 ;
        RECT  93.18 0 93.204 0.192 ;
    END
  END t0[391]
  PIN t0[392]
    DIRECTION OUTPUT ;
    USE SIGNAL ;
    PORT
      LAYER M5 ;
        RECT  93.42 0 93.444 0.192 ;
    END
  END t0[392]
  PIN t0[393]
    DIRECTION OUTPUT ;
    USE SIGNAL ;
    PORT
      LAYER M5 ;
        RECT  93.66 0 93.684 0.192 ;
    END
  END t0[393]
  PIN t0[394]
    DIRECTION OUTPUT ;
    USE SIGNAL ;
    PORT
      LAYER M5 ;
        RECT  93.9 0 93.924 0.192 ;
    END
  END t0[394]
  PIN t0[395]
    DIRECTION OUTPUT ;
    USE SIGNAL ;
    PORT
      LAYER M5 ;
        RECT  94.14 0 94.164 0.192 ;
    END
  END t0[395]
  PIN t0[396]
    DIRECTION OUTPUT ;
    USE SIGNAL ;
    PORT
      LAYER M5 ;
        RECT  94.38 0 94.404 0.192 ;
    END
  END t0[396]
  PIN t0[397]
    DIRECTION OUTPUT ;
    USE SIGNAL ;
    PORT
      LAYER M5 ;
        RECT  94.572 0 94.596 0.192 ;
    END
  END t0[397]
  PIN t0[398]
    DIRECTION OUTPUT ;
    USE SIGNAL ;
    PORT
      LAYER M5 ;
        RECT  94.812 0 94.836 0.192 ;
    END
  END t0[398]
  PIN t0[399]
    DIRECTION OUTPUT ;
    USE SIGNAL ;
    PORT
      LAYER M5 ;
        RECT  95.052 0 95.076 0.192 ;
    END
  END t0[399]
  PIN t0[39]
    DIRECTION OUTPUT ;
    USE SIGNAL ;
    PORT
      LAYER M5 ;
        RECT  11.196 0 11.22 0.192 ;
    END
  END t0[39]
  PIN t0[3]
    DIRECTION OUTPUT ;
    USE SIGNAL ;
    PORT
      LAYER M5 ;
        RECT  2.796 0 2.82 0.192 ;
    END
  END t0[3]
  PIN t0[400]
    DIRECTION OUTPUT ;
    USE SIGNAL ;
    PORT
      LAYER M5 ;
        RECT  95.292 0 95.316 0.192 ;
    END
  END t0[400]
  PIN t0[401]
    DIRECTION OUTPUT ;
    USE SIGNAL ;
    PORT
      LAYER M5 ;
        RECT  95.532 0 95.556 0.192 ;
    END
  END t0[401]
  PIN t0[402]
    DIRECTION OUTPUT ;
    USE SIGNAL ;
    PORT
      LAYER M5 ;
        RECT  95.772 0 95.796 0.192 ;
    END
  END t0[402]
  PIN t0[403]
    DIRECTION OUTPUT ;
    USE SIGNAL ;
    PORT
      LAYER M5 ;
        RECT  96.012 0 96.036 0.192 ;
    END
  END t0[403]
  PIN t0[404]
    DIRECTION OUTPUT ;
    USE SIGNAL ;
    PORT
      LAYER M5 ;
        RECT  96.204 0 96.228 0.192 ;
    END
  END t0[404]
  PIN t0[405]
    DIRECTION OUTPUT ;
    USE SIGNAL ;
    PORT
      LAYER M5 ;
        RECT  96.444 0 96.468 0.192 ;
    END
  END t0[405]
  PIN t0[406]
    DIRECTION OUTPUT ;
    USE SIGNAL ;
    PORT
      LAYER M5 ;
        RECT  96.684 0 96.708 0.192 ;
    END
  END t0[406]
  PIN t0[407]
    DIRECTION OUTPUT ;
    USE SIGNAL ;
    PORT
      LAYER M5 ;
        RECT  96.924 0 96.948 0.192 ;
    END
  END t0[407]
  PIN t0[408]
    DIRECTION OUTPUT ;
    USE SIGNAL ;
    PORT
      LAYER M5 ;
        RECT  97.164 0 97.188 0.192 ;
    END
  END t0[408]
  PIN t0[409]
    DIRECTION OUTPUT ;
    USE SIGNAL ;
    PORT
      LAYER M5 ;
        RECT  97.404 0 97.428 0.192 ;
    END
  END t0[409]
  PIN t0[40]
    DIRECTION OUTPUT ;
    USE SIGNAL ;
    PORT
      LAYER M5 ;
        RECT  11.436 0 11.46 0.192 ;
    END
  END t0[40]
  PIN t0[410]
    DIRECTION OUTPUT ;
    USE SIGNAL ;
    PORT
      LAYER M5 ;
        RECT  97.644 0 97.668 0.192 ;
    END
  END t0[410]
  PIN t0[411]
    DIRECTION OUTPUT ;
    USE SIGNAL ;
    PORT
      LAYER M5 ;
        RECT  97.836 0 97.86 0.192 ;
    END
  END t0[411]
  PIN t0[412]
    DIRECTION OUTPUT ;
    USE SIGNAL ;
    PORT
      LAYER M5 ;
        RECT  98.076 0 98.1 0.192 ;
    END
  END t0[412]
  PIN t0[413]
    DIRECTION OUTPUT ;
    USE SIGNAL ;
    PORT
      LAYER M5 ;
        RECT  98.316 0 98.34 0.192 ;
    END
  END t0[413]
  PIN t0[414]
    DIRECTION OUTPUT ;
    USE SIGNAL ;
    PORT
      LAYER M5 ;
        RECT  98.556 0 98.58 0.192 ;
    END
  END t0[414]
  PIN t0[415]
    DIRECTION OUTPUT ;
    USE SIGNAL ;
    PORT
      LAYER M5 ;
        RECT  98.796 0 98.82 0.192 ;
    END
  END t0[415]
  PIN t0[416]
    DIRECTION OUTPUT ;
    USE SIGNAL ;
    PORT
      LAYER M5 ;
        RECT  99.036 0 99.06 0.192 ;
    END
  END t0[416]
  PIN t0[417]
    DIRECTION OUTPUT ;
    USE SIGNAL ;
    PORT
      LAYER M5 ;
        RECT  99.228 0 99.252 0.192 ;
    END
  END t0[417]
  PIN t0[418]
    DIRECTION OUTPUT ;
    USE SIGNAL ;
    PORT
      LAYER M5 ;
        RECT  99.468 0 99.492 0.192 ;
    END
  END t0[418]
  PIN t0[419]
    DIRECTION OUTPUT ;
    USE SIGNAL ;
    PORT
      LAYER M5 ;
        RECT  99.708 0 99.732 0.192 ;
    END
  END t0[419]
  PIN t0[41]
    DIRECTION OUTPUT ;
    USE SIGNAL ;
    PORT
      LAYER M5 ;
        RECT  11.676 0 11.7 0.192 ;
    END
  END t0[41]
  PIN t0[420]
    DIRECTION OUTPUT ;
    USE SIGNAL ;
    PORT
      LAYER M5 ;
        RECT  99.948 0 99.972 0.192 ;
    END
  END t0[420]
  PIN t0[421]
    DIRECTION OUTPUT ;
    USE SIGNAL ;
    PORT
      LAYER M5 ;
        RECT  100.188 0 100.212 0.192 ;
    END
  END t0[421]
  PIN t0[422]
    DIRECTION OUTPUT ;
    USE SIGNAL ;
    PORT
      LAYER M5 ;
        RECT  100.428 0 100.452 0.192 ;
    END
  END t0[422]
  PIN t0[423]
    DIRECTION OUTPUT ;
    USE SIGNAL ;
    PORT
      LAYER M5 ;
        RECT  100.668 0 100.692 0.192 ;
    END
  END t0[423]
  PIN t0[424]
    DIRECTION OUTPUT ;
    USE SIGNAL ;
    PORT
      LAYER M5 ;
        RECT  100.86 0 100.884 0.192 ;
    END
  END t0[424]
  PIN t0[425]
    DIRECTION OUTPUT ;
    USE SIGNAL ;
    PORT
      LAYER M5 ;
        RECT  101.1 0 101.124 0.192 ;
    END
  END t0[425]
  PIN t0[426]
    DIRECTION OUTPUT ;
    USE SIGNAL ;
    PORT
      LAYER M5 ;
        RECT  101.34 0 101.364 0.192 ;
    END
  END t0[426]
  PIN t0[427]
    DIRECTION OUTPUT ;
    USE SIGNAL ;
    PORT
      LAYER M5 ;
        RECT  101.58 0 101.604 0.192 ;
    END
  END t0[427]
  PIN t0[428]
    DIRECTION OUTPUT ;
    USE SIGNAL ;
    PORT
      LAYER M5 ;
        RECT  101.82 0 101.844 0.192 ;
    END
  END t0[428]
  PIN t0[429]
    DIRECTION OUTPUT ;
    USE SIGNAL ;
    PORT
      LAYER M5 ;
        RECT  102.06 0 102.084 0.192 ;
    END
  END t0[429]
  PIN t0[42]
    DIRECTION OUTPUT ;
    USE SIGNAL ;
    PORT
      LAYER M5 ;
        RECT  11.868 0 11.892 0.192 ;
    END
  END t0[42]
  PIN t0[430]
    DIRECTION OUTPUT ;
    USE SIGNAL ;
    PORT
      LAYER M5 ;
        RECT  102.3 0 102.324 0.192 ;
    END
  END t0[430]
  PIN t0[431]
    DIRECTION OUTPUT ;
    USE SIGNAL ;
    PORT
      LAYER M5 ;
        RECT  102.492 0 102.516 0.192 ;
    END
  END t0[431]
  PIN t0[432]
    DIRECTION OUTPUT ;
    USE SIGNAL ;
    PORT
      LAYER M5 ;
        RECT  102.732 0 102.756 0.192 ;
    END
  END t0[432]
  PIN t0[433]
    DIRECTION OUTPUT ;
    USE SIGNAL ;
    PORT
      LAYER M5 ;
        RECT  102.972 0 102.996 0.192 ;
    END
  END t0[433]
  PIN t0[434]
    DIRECTION OUTPUT ;
    USE SIGNAL ;
    PORT
      LAYER M5 ;
        RECT  103.212 0 103.236 0.192 ;
    END
  END t0[434]
  PIN t0[435]
    DIRECTION OUTPUT ;
    USE SIGNAL ;
    PORT
      LAYER M5 ;
        RECT  103.452 0 103.476 0.192 ;
    END
  END t0[435]
  PIN t0[436]
    DIRECTION OUTPUT ;
    USE SIGNAL ;
    PORT
      LAYER M5 ;
        RECT  103.692 0 103.716 0.192 ;
    END
  END t0[436]
  PIN t0[437]
    DIRECTION OUTPUT ;
    USE SIGNAL ;
    PORT
      LAYER M5 ;
        RECT  103.932 0 103.956 0.192 ;
    END
  END t0[437]
  PIN t0[438]
    DIRECTION OUTPUT ;
    USE SIGNAL ;
    PORT
      LAYER M5 ;
        RECT  104.124 0 104.148 0.192 ;
    END
  END t0[438]
  PIN t0[439]
    DIRECTION OUTPUT ;
    USE SIGNAL ;
    PORT
      LAYER M5 ;
        RECT  104.364 0 104.388 0.192 ;
    END
  END t0[439]
  PIN t0[43]
    DIRECTION OUTPUT ;
    USE SIGNAL ;
    PORT
      LAYER M5 ;
        RECT  12.108 0 12.132 0.192 ;
    END
  END t0[43]
  PIN t0[440]
    DIRECTION OUTPUT ;
    USE SIGNAL ;
    PORT
      LAYER M5 ;
        RECT  104.604 0 104.628 0.192 ;
    END
  END t0[440]
  PIN t0[441]
    DIRECTION OUTPUT ;
    USE SIGNAL ;
    PORT
      LAYER M5 ;
        RECT  104.844 0 104.868 0.192 ;
    END
  END t0[441]
  PIN t0[442]
    DIRECTION OUTPUT ;
    USE SIGNAL ;
    PORT
      LAYER M5 ;
        RECT  105.084 0 105.108 0.192 ;
    END
  END t0[442]
  PIN t0[443]
    DIRECTION OUTPUT ;
    USE SIGNAL ;
    PORT
      LAYER M5 ;
        RECT  105.324 0 105.348 0.192 ;
    END
  END t0[443]
  PIN t0[444]
    DIRECTION OUTPUT ;
    USE SIGNAL ;
    PORT
      LAYER M5 ;
        RECT  105.564 0 105.588 0.192 ;
    END
  END t0[444]
  PIN t0[445]
    DIRECTION OUTPUT ;
    USE SIGNAL ;
    PORT
      LAYER M5 ;
        RECT  105.756 0 105.78 0.192 ;
    END
  END t0[445]
  PIN t0[446]
    DIRECTION OUTPUT ;
    USE SIGNAL ;
    PORT
      LAYER M5 ;
        RECT  105.996 0 106.02 0.192 ;
    END
  END t0[446]
  PIN t0[447]
    DIRECTION OUTPUT ;
    USE SIGNAL ;
    PORT
      LAYER M5 ;
        RECT  106.236 0 106.26 0.192 ;
    END
  END t0[447]
  PIN t0[448]
    DIRECTION OUTPUT ;
    USE SIGNAL ;
    PORT
      LAYER M5 ;
        RECT  106.476 0 106.5 0.192 ;
    END
  END t0[448]
  PIN t0[449]
    DIRECTION OUTPUT ;
    USE SIGNAL ;
    PORT
      LAYER M5 ;
        RECT  106.716 0 106.74 0.192 ;
    END
  END t0[449]
  PIN t0[44]
    DIRECTION OUTPUT ;
    USE SIGNAL ;
    PORT
      LAYER M5 ;
        RECT  12.348 0 12.372 0.192 ;
    END
  END t0[44]
  PIN t0[450]
    DIRECTION OUTPUT ;
    USE SIGNAL ;
    PORT
      LAYER M5 ;
        RECT  106.956 0 106.98 0.192 ;
    END
  END t0[450]
  PIN t0[451]
    DIRECTION OUTPUT ;
    USE SIGNAL ;
    PORT
      LAYER M5 ;
        RECT  107.196 0 107.22 0.192 ;
    END
  END t0[451]
  PIN t0[452]
    DIRECTION OUTPUT ;
    USE SIGNAL ;
    PORT
      LAYER M5 ;
        RECT  107.388 0 107.412 0.192 ;
    END
  END t0[452]
  PIN t0[453]
    DIRECTION OUTPUT ;
    USE SIGNAL ;
    PORT
      LAYER M5 ;
        RECT  107.628 0 107.652 0.192 ;
    END
  END t0[453]
  PIN t0[454]
    DIRECTION OUTPUT ;
    USE SIGNAL ;
    PORT
      LAYER M5 ;
        RECT  107.868 0 107.892 0.192 ;
    END
  END t0[454]
  PIN t0[455]
    DIRECTION OUTPUT ;
    USE SIGNAL ;
    PORT
      LAYER M5 ;
        RECT  108.108 0 108.132 0.192 ;
    END
  END t0[455]
  PIN t0[456]
    DIRECTION OUTPUT ;
    USE SIGNAL ;
    PORT
      LAYER M5 ;
        RECT  108.348 0 108.372 0.192 ;
    END
  END t0[456]
  PIN t0[457]
    DIRECTION OUTPUT ;
    USE SIGNAL ;
    PORT
      LAYER M5 ;
        RECT  108.588 0 108.612 0.192 ;
    END
  END t0[457]
  PIN t0[458]
    DIRECTION OUTPUT ;
    USE SIGNAL ;
    PORT
      LAYER M5 ;
        RECT  108.78 0 108.804 0.192 ;
    END
  END t0[458]
  PIN t0[459]
    DIRECTION OUTPUT ;
    USE SIGNAL ;
    PORT
      LAYER M5 ;
        RECT  109.02 0 109.044 0.192 ;
    END
  END t0[459]
  PIN t0[45]
    DIRECTION OUTPUT ;
    USE SIGNAL ;
    PORT
      LAYER M5 ;
        RECT  12.588 0 12.612 0.192 ;
    END
  END t0[45]
  PIN t0[460]
    DIRECTION OUTPUT ;
    USE SIGNAL ;
    PORT
      LAYER M5 ;
        RECT  109.26 0 109.284 0.192 ;
    END
  END t0[460]
  PIN t0[461]
    DIRECTION OUTPUT ;
    USE SIGNAL ;
    PORT
      LAYER M5 ;
        RECT  109.5 0 109.524 0.192 ;
    END
  END t0[461]
  PIN t0[462]
    DIRECTION OUTPUT ;
    USE SIGNAL ;
    PORT
      LAYER M5 ;
        RECT  109.74 0 109.764 0.192 ;
    END
  END t0[462]
  PIN t0[463]
    DIRECTION OUTPUT ;
    USE SIGNAL ;
    PORT
      LAYER M5 ;
        RECT  109.98 0 110.004 0.192 ;
    END
  END t0[463]
  PIN t0[464]
    DIRECTION OUTPUT ;
    USE SIGNAL ;
    PORT
      LAYER M5 ;
        RECT  110.22 0 110.244 0.192 ;
    END
  END t0[464]
  PIN t0[465]
    DIRECTION OUTPUT ;
    USE SIGNAL ;
    PORT
      LAYER M5 ;
        RECT  110.412 0 110.436 0.192 ;
    END
  END t0[465]
  PIN t0[466]
    DIRECTION OUTPUT ;
    USE SIGNAL ;
    PORT
      LAYER M5 ;
        RECT  110.652 0 110.676 0.192 ;
    END
  END t0[466]
  PIN t0[467]
    DIRECTION OUTPUT ;
    USE SIGNAL ;
    PORT
      LAYER M5 ;
        RECT  110.892 0 110.916 0.192 ;
    END
  END t0[467]
  PIN t0[468]
    DIRECTION OUTPUT ;
    USE SIGNAL ;
    PORT
      LAYER M5 ;
        RECT  111.132 0 111.156 0.192 ;
    END
  END t0[468]
  PIN t0[469]
    DIRECTION OUTPUT ;
    USE SIGNAL ;
    PORT
      LAYER M5 ;
        RECT  111.372 0 111.396 0.192 ;
    END
  END t0[469]
  PIN t0[46]
    DIRECTION OUTPUT ;
    USE SIGNAL ;
    PORT
      LAYER M5 ;
        RECT  12.828 0 12.852 0.192 ;
    END
  END t0[46]
  PIN t0[470]
    DIRECTION OUTPUT ;
    USE SIGNAL ;
    PORT
      LAYER M5 ;
        RECT  111.612 0 111.636 0.192 ;
    END
  END t0[470]
  PIN t0[471]
    DIRECTION OUTPUT ;
    USE SIGNAL ;
    PORT
      LAYER M5 ;
        RECT  111.852 0 111.876 0.192 ;
    END
  END t0[471]
  PIN t0[472]
    DIRECTION OUTPUT ;
    USE SIGNAL ;
    PORT
      LAYER M5 ;
        RECT  112.044 0 112.068 0.192 ;
    END
  END t0[472]
  PIN t0[473]
    DIRECTION OUTPUT ;
    USE SIGNAL ;
    PORT
      LAYER M5 ;
        RECT  112.284 0 112.308 0.192 ;
    END
  END t0[473]
  PIN t0[474]
    DIRECTION OUTPUT ;
    USE SIGNAL ;
    PORT
      LAYER M5 ;
        RECT  112.524 0 112.548 0.192 ;
    END
  END t0[474]
  PIN t0[475]
    DIRECTION OUTPUT ;
    USE SIGNAL ;
    PORT
      LAYER M5 ;
        RECT  112.764 0 112.788 0.192 ;
    END
  END t0[475]
  PIN t0[476]
    DIRECTION OUTPUT ;
    USE SIGNAL ;
    PORT
      LAYER M5 ;
        RECT  113.004 0 113.028 0.192 ;
    END
  END t0[476]
  PIN t0[477]
    DIRECTION OUTPUT ;
    USE SIGNAL ;
    PORT
      LAYER M5 ;
        RECT  113.244 0 113.268 0.192 ;
    END
  END t0[477]
  PIN t0[478]
    DIRECTION OUTPUT ;
    USE SIGNAL ;
    PORT
      LAYER M5 ;
        RECT  113.484 0 113.508 0.192 ;
    END
  END t0[478]
  PIN t0[479]
    DIRECTION OUTPUT ;
    USE SIGNAL ;
    PORT
      LAYER M5 ;
        RECT  113.676 0 113.7 0.192 ;
    END
  END t0[479]
  PIN t0[47]
    DIRECTION OUTPUT ;
    USE SIGNAL ;
    PORT
      LAYER M5 ;
        RECT  13.068 0 13.092 0.192 ;
    END
  END t0[47]
  PIN t0[480]
    DIRECTION OUTPUT ;
    USE SIGNAL ;
    PORT
      LAYER M5 ;
        RECT  113.916 0 113.94 0.192 ;
    END
  END t0[480]
  PIN t0[481]
    DIRECTION OUTPUT ;
    USE SIGNAL ;
    PORT
      LAYER M5 ;
        RECT  114.156 0 114.18 0.192 ;
    END
  END t0[481]
  PIN t0[482]
    DIRECTION OUTPUT ;
    USE SIGNAL ;
    PORT
      LAYER M5 ;
        RECT  114.396 0 114.42 0.192 ;
    END
  END t0[482]
  PIN t0[483]
    DIRECTION OUTPUT ;
    USE SIGNAL ;
    PORT
      LAYER M5 ;
        RECT  114.636 0 114.66 0.192 ;
    END
  END t0[483]
  PIN t0[484]
    DIRECTION OUTPUT ;
    USE SIGNAL ;
    PORT
      LAYER M5 ;
        RECT  114.876 0 114.9 0.192 ;
    END
  END t0[484]
  PIN t0[485]
    DIRECTION OUTPUT ;
    USE SIGNAL ;
    PORT
      LAYER M5 ;
        RECT  115.116 0 115.14 0.192 ;
    END
  END t0[485]
  PIN t0[486]
    DIRECTION OUTPUT ;
    USE SIGNAL ;
    PORT
      LAYER M5 ;
        RECT  115.308 0 115.332 0.192 ;
    END
  END t0[486]
  PIN t0[487]
    DIRECTION OUTPUT ;
    USE SIGNAL ;
    PORT
      LAYER M5 ;
        RECT  115.548 0 115.572 0.192 ;
    END
  END t0[487]
  PIN t0[488]
    DIRECTION OUTPUT ;
    USE SIGNAL ;
    PORT
      LAYER M5 ;
        RECT  115.788 0 115.812 0.192 ;
    END
  END t0[488]
  PIN t0[489]
    DIRECTION OUTPUT ;
    USE SIGNAL ;
    PORT
      LAYER M5 ;
        RECT  116.028 0 116.052 0.192 ;
    END
  END t0[489]
  PIN t0[48]
    DIRECTION OUTPUT ;
    USE SIGNAL ;
    PORT
      LAYER M5 ;
        RECT  13.308 0 13.332 0.192 ;
    END
  END t0[48]
  PIN t0[490]
    DIRECTION OUTPUT ;
    USE SIGNAL ;
    PORT
      LAYER M5 ;
        RECT  116.268 0 116.292 0.192 ;
    END
  END t0[490]
  PIN t0[491]
    DIRECTION OUTPUT ;
    USE SIGNAL ;
    PORT
      LAYER M5 ;
        RECT  116.508 0 116.532 0.192 ;
    END
  END t0[491]
  PIN t0[492]
    DIRECTION OUTPUT ;
    USE SIGNAL ;
    PORT
      LAYER M5 ;
        RECT  116.748 0 116.772 0.192 ;
    END
  END t0[492]
  PIN t0[493]
    DIRECTION OUTPUT ;
    USE SIGNAL ;
    PORT
      LAYER M5 ;
        RECT  116.94 0 116.964 0.192 ;
    END
  END t0[493]
  PIN t0[494]
    DIRECTION OUTPUT ;
    USE SIGNAL ;
    PORT
      LAYER M5 ;
        RECT  117.18 0 117.204 0.192 ;
    END
  END t0[494]
  PIN t0[495]
    DIRECTION OUTPUT ;
    USE SIGNAL ;
    PORT
      LAYER M5 ;
        RECT  117.42 0 117.444 0.192 ;
    END
  END t0[495]
  PIN t0[496]
    DIRECTION OUTPUT ;
    USE SIGNAL ;
    PORT
      LAYER M5 ;
        RECT  117.66 0 117.684 0.192 ;
    END
  END t0[496]
  PIN t0[497]
    DIRECTION OUTPUT ;
    USE SIGNAL ;
    PORT
      LAYER M5 ;
        RECT  117.9 0 117.924 0.192 ;
    END
  END t0[497]
  PIN t0[498]
    DIRECTION OUTPUT ;
    USE SIGNAL ;
    PORT
      LAYER M5 ;
        RECT  118.14 0 118.164 0.192 ;
    END
  END t0[498]
  PIN t0[499]
    DIRECTION OUTPUT ;
    USE SIGNAL ;
    PORT
      LAYER M5 ;
        RECT  118.332 0 118.356 0.192 ;
    END
  END t0[499]
  PIN t0[49]
    DIRECTION OUTPUT ;
    USE SIGNAL ;
    PORT
      LAYER M5 ;
        RECT  13.5 0 13.524 0.192 ;
    END
  END t0[49]
  PIN t0[4]
    DIRECTION OUTPUT ;
    USE SIGNAL ;
    PORT
      LAYER M5 ;
        RECT  3.036 0 3.06 0.192 ;
    END
  END t0[4]
  PIN t0[500]
    DIRECTION OUTPUT ;
    USE SIGNAL ;
    PORT
      LAYER M5 ;
        RECT  118.572 0 118.596 0.192 ;
    END
  END t0[500]
  PIN t0[501]
    DIRECTION OUTPUT ;
    USE SIGNAL ;
    PORT
      LAYER M5 ;
        RECT  118.812 0 118.836 0.192 ;
    END
  END t0[501]
  PIN t0[502]
    DIRECTION OUTPUT ;
    USE SIGNAL ;
    PORT
      LAYER M5 ;
        RECT  119.052 0 119.076 0.192 ;
    END
  END t0[502]
  PIN t0[503]
    DIRECTION OUTPUT ;
    USE SIGNAL ;
    PORT
      LAYER M5 ;
        RECT  119.292 0 119.316 0.192 ;
    END
  END t0[503]
  PIN t0[504]
    DIRECTION OUTPUT ;
    USE SIGNAL ;
    PORT
      LAYER M5 ;
        RECT  119.532 0 119.556 0.192 ;
    END
  END t0[504]
  PIN t0[505]
    DIRECTION OUTPUT ;
    USE SIGNAL ;
    PORT
      LAYER M5 ;
        RECT  119.772 0 119.796 0.192 ;
    END
  END t0[505]
  PIN t0[506]
    DIRECTION OUTPUT ;
    USE SIGNAL ;
    PORT
      LAYER M5 ;
        RECT  119.964 0 119.988 0.192 ;
    END
  END t0[506]
  PIN t0[507]
    DIRECTION OUTPUT ;
    USE SIGNAL ;
    PORT
      LAYER M5 ;
        RECT  120.204 0 120.228 0.192 ;
    END
  END t0[507]
  PIN t0[508]
    DIRECTION OUTPUT ;
    USE SIGNAL ;
    PORT
      LAYER M5 ;
        RECT  120.444 0 120.468 0.192 ;
    END
  END t0[508]
  PIN t0[509]
    DIRECTION OUTPUT ;
    USE SIGNAL ;
    PORT
      LAYER M5 ;
        RECT  120.684 0 120.708 0.192 ;
    END
  END t0[509]
  PIN t0[50]
    DIRECTION OUTPUT ;
    USE SIGNAL ;
    PORT
      LAYER M5 ;
        RECT  13.74 0 13.764 0.192 ;
    END
  END t0[50]
  PIN t0[510]
    DIRECTION OUTPUT ;
    USE SIGNAL ;
    PORT
      LAYER M5 ;
        RECT  120.924 0 120.948 0.192 ;
    END
  END t0[510]
  PIN t0[511]
    DIRECTION OUTPUT ;
    USE SIGNAL ;
    PORT
      LAYER M5 ;
        RECT  121.164 0 121.188 0.192 ;
    END
  END t0[511]
  PIN t0[512]
    DIRECTION OUTPUT ;
    USE SIGNAL ;
    PORT
      LAYER M5 ;
        RECT  121.404 0 121.428 0.192 ;
    END
  END t0[512]
  PIN t0[513]
    DIRECTION OUTPUT ;
    USE SIGNAL ;
    PORT
      LAYER M5 ;
        RECT  121.596 0 121.62 0.192 ;
    END
  END t0[513]
  PIN t0[514]
    DIRECTION OUTPUT ;
    USE SIGNAL ;
    PORT
      LAYER M5 ;
        RECT  121.836 0 121.86 0.192 ;
    END
  END t0[514]
  PIN t0[515]
    DIRECTION OUTPUT ;
    USE SIGNAL ;
    PORT
      LAYER M5 ;
        RECT  122.076 0 122.1 0.192 ;
    END
  END t0[515]
  PIN t0[516]
    DIRECTION OUTPUT ;
    USE SIGNAL ;
    PORT
      LAYER M5 ;
        RECT  122.316 0 122.34 0.192 ;
    END
  END t0[516]
  PIN t0[517]
    DIRECTION OUTPUT ;
    USE SIGNAL ;
    PORT
      LAYER M5 ;
        RECT  122.556 0 122.58 0.192 ;
    END
  END t0[517]
  PIN t0[518]
    DIRECTION OUTPUT ;
    USE SIGNAL ;
    PORT
      LAYER M5 ;
        RECT  122.796 0 122.82 0.192 ;
    END
  END t0[518]
  PIN t0[519]
    DIRECTION OUTPUT ;
    USE SIGNAL ;
    PORT
      LAYER M5 ;
        RECT  123.036 0 123.06 0.192 ;
    END
  END t0[519]
  PIN t0[51]
    DIRECTION OUTPUT ;
    USE SIGNAL ;
    PORT
      LAYER M5 ;
        RECT  13.98 0 14.004 0.192 ;
    END
  END t0[51]
  PIN t0[520]
    DIRECTION OUTPUT ;
    USE SIGNAL ;
    PORT
      LAYER M5 ;
        RECT  123.228 0 123.252 0.192 ;
    END
  END t0[520]
  PIN t0[521]
    DIRECTION OUTPUT ;
    USE SIGNAL ;
    PORT
      LAYER M5 ;
        RECT  123.468 0 123.492 0.192 ;
    END
  END t0[521]
  PIN t0[522]
    DIRECTION OUTPUT ;
    USE SIGNAL ;
    PORT
      LAYER M5 ;
        RECT  123.708 0 123.732 0.192 ;
    END
  END t0[522]
  PIN t0[523]
    DIRECTION OUTPUT ;
    USE SIGNAL ;
    PORT
      LAYER M5 ;
        RECT  123.948 0 123.972 0.192 ;
    END
  END t0[523]
  PIN t0[524]
    DIRECTION OUTPUT ;
    USE SIGNAL ;
    PORT
      LAYER M5 ;
        RECT  124.188 0 124.212 0.192 ;
    END
  END t0[524]
  PIN t0[525]
    DIRECTION OUTPUT ;
    USE SIGNAL ;
    PORT
      LAYER M5 ;
        RECT  124.428 0 124.452 0.192 ;
    END
  END t0[525]
  PIN t0[526]
    DIRECTION OUTPUT ;
    USE SIGNAL ;
    PORT
      LAYER M5 ;
        RECT  124.668 0 124.692 0.192 ;
    END
  END t0[526]
  PIN t0[527]
    DIRECTION OUTPUT ;
    USE SIGNAL ;
    PORT
      LAYER M5 ;
        RECT  124.86 0 124.884 0.192 ;
    END
  END t0[527]
  PIN t0[528]
    DIRECTION OUTPUT ;
    USE SIGNAL ;
    PORT
      LAYER M5 ;
        RECT  125.1 0 125.124 0.192 ;
    END
  END t0[528]
  PIN t0[529]
    DIRECTION OUTPUT ;
    USE SIGNAL ;
    PORT
      LAYER M5 ;
        RECT  125.34 0 125.364 0.192 ;
    END
  END t0[529]
  PIN t0[52]
    DIRECTION OUTPUT ;
    USE SIGNAL ;
    PORT
      LAYER M5 ;
        RECT  14.22 0 14.244 0.192 ;
    END
  END t0[52]
  PIN t0[530]
    DIRECTION OUTPUT ;
    USE SIGNAL ;
    PORT
      LAYER M5 ;
        RECT  125.58 0 125.604 0.192 ;
    END
  END t0[530]
  PIN t0[531]
    DIRECTION OUTPUT ;
    USE SIGNAL ;
    PORT
      LAYER M5 ;
        RECT  125.82 0 125.844 0.192 ;
    END
  END t0[531]
  PIN t0[532]
    DIRECTION OUTPUT ;
    USE SIGNAL ;
    PORT
      LAYER M5 ;
        RECT  126.06 0 126.084 0.192 ;
    END
  END t0[532]
  PIN t0[533]
    DIRECTION OUTPUT ;
    USE SIGNAL ;
    PORT
      LAYER M5 ;
        RECT  126.252 0 126.276 0.192 ;
    END
  END t0[533]
  PIN t0[534]
    DIRECTION OUTPUT ;
    USE SIGNAL ;
    PORT
      LAYER M5 ;
        RECT  126.492 0 126.516 0.192 ;
    END
  END t0[534]
  PIN t0[535]
    DIRECTION OUTPUT ;
    USE SIGNAL ;
    PORT
      LAYER M5 ;
        RECT  126.732 0 126.756 0.192 ;
    END
  END t0[535]
  PIN t0[536]
    DIRECTION OUTPUT ;
    USE SIGNAL ;
    PORT
      LAYER M5 ;
        RECT  126.972 0 126.996 0.192 ;
    END
  END t0[536]
  PIN t0[537]
    DIRECTION OUTPUT ;
    USE SIGNAL ;
    PORT
      LAYER M5 ;
        RECT  127.212 0 127.236 0.192 ;
    END
  END t0[537]
  PIN t0[538]
    DIRECTION OUTPUT ;
    USE SIGNAL ;
    PORT
      LAYER M5 ;
        RECT  127.452 0 127.476 0.192 ;
    END
  END t0[538]
  PIN t0[539]
    DIRECTION OUTPUT ;
    USE SIGNAL ;
    PORT
      LAYER M5 ;
        RECT  127.692 0 127.716 0.192 ;
    END
  END t0[539]
  PIN t0[53]
    DIRECTION OUTPUT ;
    USE SIGNAL ;
    PORT
      LAYER M5 ;
        RECT  14.46 0 14.484 0.192 ;
    END
  END t0[53]
  PIN t0[540]
    DIRECTION OUTPUT ;
    USE SIGNAL ;
    PORT
      LAYER M5 ;
        RECT  127.884 0 127.908 0.192 ;
    END
  END t0[540]
  PIN t0[541]
    DIRECTION OUTPUT ;
    USE SIGNAL ;
    PORT
      LAYER M5 ;
        RECT  128.124 0 128.148 0.192 ;
    END
  END t0[541]
  PIN t0[542]
    DIRECTION OUTPUT ;
    USE SIGNAL ;
    PORT
      LAYER M5 ;
        RECT  128.364 0 128.388 0.192 ;
    END
  END t0[542]
  PIN t0[543]
    DIRECTION OUTPUT ;
    USE SIGNAL ;
    PORT
      LAYER M5 ;
        RECT  128.604 0 128.628 0.192 ;
    END
  END t0[543]
  PIN t0[544]
    DIRECTION OUTPUT ;
    USE SIGNAL ;
    PORT
      LAYER M5 ;
        RECT  128.844 0 128.868 0.192 ;
    END
  END t0[544]
  PIN t0[545]
    DIRECTION OUTPUT ;
    USE SIGNAL ;
    PORT
      LAYER M5 ;
        RECT  129.084 0 129.108 0.192 ;
    END
  END t0[545]
  PIN t0[546]
    DIRECTION OUTPUT ;
    USE SIGNAL ;
    PORT
      LAYER M5 ;
        RECT  129.324 0 129.348 0.192 ;
    END
  END t0[546]
  PIN t0[547]
    DIRECTION OUTPUT ;
    USE SIGNAL ;
    PORT
      LAYER M5 ;
        RECT  129.516 0 129.54 0.192 ;
    END
  END t0[547]
  PIN t0[548]
    DIRECTION OUTPUT ;
    USE SIGNAL ;
    PORT
      LAYER M5 ;
        RECT  129.756 0 129.78 0.192 ;
    END
  END t0[548]
  PIN t0[549]
    DIRECTION OUTPUT ;
    USE SIGNAL ;
    PORT
      LAYER M5 ;
        RECT  129.996 0 130.02 0.192 ;
    END
  END t0[549]
  PIN t0[54]
    DIRECTION OUTPUT ;
    USE SIGNAL ;
    PORT
      LAYER M5 ;
        RECT  14.7 0 14.724 0.192 ;
    END
  END t0[54]
  PIN t0[550]
    DIRECTION OUTPUT ;
    USE SIGNAL ;
    PORT
      LAYER M5 ;
        RECT  130.236 0 130.26 0.192 ;
    END
  END t0[550]
  PIN t0[551]
    DIRECTION OUTPUT ;
    USE SIGNAL ;
    PORT
      LAYER M5 ;
        RECT  130.476 0 130.5 0.192 ;
    END
  END t0[551]
  PIN t0[552]
    DIRECTION OUTPUT ;
    USE SIGNAL ;
    PORT
      LAYER M5 ;
        RECT  130.716 0 130.74 0.192 ;
    END
  END t0[552]
  PIN t0[553]
    DIRECTION OUTPUT ;
    USE SIGNAL ;
    PORT
      LAYER M5 ;
        RECT  130.956 0 130.98 0.192 ;
    END
  END t0[553]
  PIN t0[554]
    DIRECTION OUTPUT ;
    USE SIGNAL ;
    PORT
      LAYER M5 ;
        RECT  131.148 0 131.172 0.192 ;
    END
  END t0[554]
  PIN t0[555]
    DIRECTION OUTPUT ;
    USE SIGNAL ;
    PORT
      LAYER M5 ;
        RECT  131.388 0 131.412 0.192 ;
    END
  END t0[555]
  PIN t0[556]
    DIRECTION OUTPUT ;
    USE SIGNAL ;
    PORT
      LAYER M5 ;
        RECT  131.628 0 131.652 0.192 ;
    END
  END t0[556]
  PIN t0[557]
    DIRECTION OUTPUT ;
    USE SIGNAL ;
    PORT
      LAYER M5 ;
        RECT  131.868 0 131.892 0.192 ;
    END
  END t0[557]
  PIN t0[558]
    DIRECTION OUTPUT ;
    USE SIGNAL ;
    PORT
      LAYER M5 ;
        RECT  132.108 0 132.132 0.192 ;
    END
  END t0[558]
  PIN t0[559]
    DIRECTION OUTPUT ;
    USE SIGNAL ;
    PORT
      LAYER M5 ;
        RECT  132.348 0 132.372 0.192 ;
    END
  END t0[559]
  PIN t0[55]
    DIRECTION OUTPUT ;
    USE SIGNAL ;
    PORT
      LAYER M5 ;
        RECT  14.94 0 14.964 0.192 ;
    END
  END t0[55]
  PIN t0[560]
    DIRECTION OUTPUT ;
    USE SIGNAL ;
    PORT
      LAYER M5 ;
        RECT  132.588 0 132.612 0.192 ;
    END
  END t0[560]
  PIN t0[561]
    DIRECTION OUTPUT ;
    USE SIGNAL ;
    PORT
      LAYER M5 ;
        RECT  132.78 0 132.804 0.192 ;
    END
  END t0[561]
  PIN t0[562]
    DIRECTION OUTPUT ;
    USE SIGNAL ;
    PORT
      LAYER M5 ;
        RECT  133.02 0 133.044 0.192 ;
    END
  END t0[562]
  PIN t0[563]
    DIRECTION OUTPUT ;
    USE SIGNAL ;
    PORT
      LAYER M5 ;
        RECT  133.26 0 133.284 0.192 ;
    END
  END t0[563]
  PIN t0[564]
    DIRECTION OUTPUT ;
    USE SIGNAL ;
    PORT
      LAYER M5 ;
        RECT  133.5 0 133.524 0.192 ;
    END
  END t0[564]
  PIN t0[565]
    DIRECTION OUTPUT ;
    USE SIGNAL ;
    PORT
      LAYER M5 ;
        RECT  133.74 0 133.764 0.192 ;
    END
  END t0[565]
  PIN t0[566]
    DIRECTION OUTPUT ;
    USE SIGNAL ;
    PORT
      LAYER M5 ;
        RECT  133.98 0 134.004 0.192 ;
    END
  END t0[566]
  PIN t0[567]
    DIRECTION OUTPUT ;
    USE SIGNAL ;
    PORT
      LAYER M5 ;
        RECT  134.22 0 134.244 0.192 ;
    END
  END t0[567]
  PIN t0[568]
    DIRECTION OUTPUT ;
    USE SIGNAL ;
    PORT
      LAYER M5 ;
        RECT  134.412 0 134.436 0.192 ;
    END
  END t0[568]
  PIN t0[569]
    DIRECTION OUTPUT ;
    USE SIGNAL ;
    PORT
      LAYER M5 ;
        RECT  134.652 0 134.676 0.192 ;
    END
  END t0[569]
  PIN t0[56]
    DIRECTION OUTPUT ;
    USE SIGNAL ;
    PORT
      LAYER M5 ;
        RECT  15.132 0 15.156 0.192 ;
    END
  END t0[56]
  PIN t0[570]
    DIRECTION OUTPUT ;
    USE SIGNAL ;
    PORT
      LAYER M5 ;
        RECT  134.892 0 134.916 0.192 ;
    END
  END t0[570]
  PIN t0[571]
    DIRECTION OUTPUT ;
    USE SIGNAL ;
    PORT
      LAYER M5 ;
        RECT  135.132 0 135.156 0.192 ;
    END
  END t0[571]
  PIN t0[572]
    DIRECTION OUTPUT ;
    USE SIGNAL ;
    PORT
      LAYER M5 ;
        RECT  135.372 0 135.396 0.192 ;
    END
  END t0[572]
  PIN t0[573]
    DIRECTION OUTPUT ;
    USE SIGNAL ;
    PORT
      LAYER M5 ;
        RECT  135.612 0 135.636 0.192 ;
    END
  END t0[573]
  PIN t0[574]
    DIRECTION OUTPUT ;
    USE SIGNAL ;
    PORT
      LAYER M5 ;
        RECT  135.804 0 135.828 0.192 ;
    END
  END t0[574]
  PIN t0[575]
    DIRECTION OUTPUT ;
    USE SIGNAL ;
    PORT
      LAYER M5 ;
        RECT  136.044 0 136.068 0.192 ;
    END
  END t0[575]
  PIN t0[576]
    DIRECTION OUTPUT ;
    USE SIGNAL ;
    PORT
      LAYER M5 ;
        RECT  136.284 0 136.308 0.192 ;
    END
  END t0[576]
  PIN t0[577]
    DIRECTION OUTPUT ;
    USE SIGNAL ;
    PORT
      LAYER M5 ;
        RECT  136.524 0 136.548 0.192 ;
    END
  END t0[577]
  PIN t0[578]
    DIRECTION OUTPUT ;
    USE SIGNAL ;
    PORT
      LAYER M5 ;
        RECT  136.764 0 136.788 0.192 ;
    END
  END t0[578]
  PIN t0[579]
    DIRECTION OUTPUT ;
    USE SIGNAL ;
    PORT
      LAYER M5 ;
        RECT  137.004 0 137.028 0.192 ;
    END
  END t0[579]
  PIN t0[57]
    DIRECTION OUTPUT ;
    USE SIGNAL ;
    PORT
      LAYER M5 ;
        RECT  15.372 0 15.396 0.192 ;
    END
  END t0[57]
  PIN t0[580]
    DIRECTION OUTPUT ;
    USE SIGNAL ;
    PORT
      LAYER M5 ;
        RECT  137.244 0 137.268 0.192 ;
    END
  END t0[580]
  PIN t0[581]
    DIRECTION OUTPUT ;
    USE SIGNAL ;
    PORT
      LAYER M5 ;
        RECT  137.436 0 137.46 0.192 ;
    END
  END t0[581]
  PIN t0[582]
    DIRECTION OUTPUT ;
    USE SIGNAL ;
    PORT
      LAYER M5 ;
        RECT  137.676 0 137.7 0.192 ;
    END
  END t0[582]
  PIN t0[583]
    DIRECTION OUTPUT ;
    USE SIGNAL ;
    PORT
      LAYER M5 ;
        RECT  137.916 0 137.94 0.192 ;
    END
  END t0[583]
  PIN t0[584]
    DIRECTION OUTPUT ;
    USE SIGNAL ;
    PORT
      LAYER M5 ;
        RECT  138.156 0 138.18 0.192 ;
    END
  END t0[584]
  PIN t0[585]
    DIRECTION OUTPUT ;
    USE SIGNAL ;
    PORT
      LAYER M5 ;
        RECT  138.396 0 138.42 0.192 ;
    END
  END t0[585]
  PIN t0[586]
    DIRECTION OUTPUT ;
    USE SIGNAL ;
    PORT
      LAYER M5 ;
        RECT  138.636 0 138.66 0.192 ;
    END
  END t0[586]
  PIN t0[587]
    DIRECTION OUTPUT ;
    USE SIGNAL ;
    PORT
      LAYER M5 ;
        RECT  138.876 0 138.9 0.192 ;
    END
  END t0[587]
  PIN t0[588]
    DIRECTION OUTPUT ;
    USE SIGNAL ;
    PORT
      LAYER M5 ;
        RECT  139.068 0 139.092 0.192 ;
    END
  END t0[588]
  PIN t0[589]
    DIRECTION OUTPUT ;
    USE SIGNAL ;
    PORT
      LAYER M5 ;
        RECT  139.308 0 139.332 0.192 ;
    END
  END t0[589]
  PIN t0[58]
    DIRECTION OUTPUT ;
    USE SIGNAL ;
    PORT
      LAYER M5 ;
        RECT  15.612 0 15.636 0.192 ;
    END
  END t0[58]
  PIN t0[590]
    DIRECTION OUTPUT ;
    USE SIGNAL ;
    PORT
      LAYER M5 ;
        RECT  139.548 0 139.572 0.192 ;
    END
  END t0[590]
  PIN t0[591]
    DIRECTION OUTPUT ;
    USE SIGNAL ;
    PORT
      LAYER M5 ;
        RECT  139.788 0 139.812 0.192 ;
    END
  END t0[591]
  PIN t0[592]
    DIRECTION OUTPUT ;
    USE SIGNAL ;
    PORT
      LAYER M5 ;
        RECT  140.028 0 140.052 0.192 ;
    END
  END t0[592]
  PIN t0[593]
    DIRECTION OUTPUT ;
    USE SIGNAL ;
    PORT
      LAYER M5 ;
        RECT  140.268 0 140.292 0.192 ;
    END
  END t0[593]
  PIN t0[594]
    DIRECTION OUTPUT ;
    USE SIGNAL ;
    PORT
      LAYER M5 ;
        RECT  140.508 0 140.532 0.192 ;
    END
  END t0[594]
  PIN t0[595]
    DIRECTION OUTPUT ;
    USE SIGNAL ;
    PORT
      LAYER M5 ;
        RECT  140.7 0 140.724 0.192 ;
    END
  END t0[595]
  PIN t0[596]
    DIRECTION OUTPUT ;
    USE SIGNAL ;
    PORT
      LAYER M5 ;
        RECT  140.94 0 140.964 0.192 ;
    END
  END t0[596]
  PIN t0[597]
    DIRECTION OUTPUT ;
    USE SIGNAL ;
    PORT
      LAYER M5 ;
        RECT  141.18 0 141.204 0.192 ;
    END
  END t0[597]
  PIN t0[598]
    DIRECTION OUTPUT ;
    USE SIGNAL ;
    PORT
      LAYER M5 ;
        RECT  141.42 0 141.444 0.192 ;
    END
  END t0[598]
  PIN t0[599]
    DIRECTION OUTPUT ;
    USE SIGNAL ;
    PORT
      LAYER M5 ;
        RECT  141.66 0 141.684 0.192 ;
    END
  END t0[599]
  PIN t0[59]
    DIRECTION OUTPUT ;
    USE SIGNAL ;
    PORT
      LAYER M5 ;
        RECT  15.852 0 15.876 0.192 ;
    END
  END t0[59]
  PIN t0[5]
    DIRECTION OUTPUT ;
    USE SIGNAL ;
    PORT
      LAYER M5 ;
        RECT  3.276 0 3.3 0.192 ;
    END
  END t0[5]
  PIN t0[600]
    DIRECTION OUTPUT ;
    USE SIGNAL ;
    PORT
      LAYER M5 ;
        RECT  141.9 0 141.924 0.192 ;
    END
  END t0[600]
  PIN t0[601]
    DIRECTION OUTPUT ;
    USE SIGNAL ;
    PORT
      LAYER M5 ;
        RECT  142.14 0 142.164 0.192 ;
    END
  END t0[601]
  PIN t0[602]
    DIRECTION OUTPUT ;
    USE SIGNAL ;
    PORT
      LAYER M5 ;
        RECT  142.332 0 142.356 0.192 ;
    END
  END t0[602]
  PIN t0[603]
    DIRECTION OUTPUT ;
    USE SIGNAL ;
    PORT
      LAYER M5 ;
        RECT  142.572 0 142.596 0.192 ;
    END
  END t0[603]
  PIN t0[604]
    DIRECTION OUTPUT ;
    USE SIGNAL ;
    PORT
      LAYER M5 ;
        RECT  142.812 0 142.836 0.192 ;
    END
  END t0[604]
  PIN t0[605]
    DIRECTION OUTPUT ;
    USE SIGNAL ;
    PORT
      LAYER M5 ;
        RECT  143.052 0 143.076 0.192 ;
    END
  END t0[605]
  PIN t0[606]
    DIRECTION OUTPUT ;
    USE SIGNAL ;
    PORT
      LAYER M5 ;
        RECT  143.292 0 143.316 0.192 ;
    END
  END t0[606]
  PIN t0[607]
    DIRECTION OUTPUT ;
    USE SIGNAL ;
    PORT
      LAYER M5 ;
        RECT  143.532 0 143.556 0.192 ;
    END
  END t0[607]
  PIN t0[608]
    DIRECTION OUTPUT ;
    USE SIGNAL ;
    PORT
      LAYER M5 ;
        RECT  143.772 0 143.796 0.192 ;
    END
  END t0[608]
  PIN t0[609]
    DIRECTION OUTPUT ;
    USE SIGNAL ;
    PORT
      LAYER M5 ;
        RECT  143.964 0 143.988 0.192 ;
    END
  END t0[609]
  PIN t0[60]
    DIRECTION OUTPUT ;
    USE SIGNAL ;
    PORT
      LAYER M5 ;
        RECT  16.092 0 16.116 0.192 ;
    END
  END t0[60]
  PIN t0[610]
    DIRECTION OUTPUT ;
    USE SIGNAL ;
    PORT
      LAYER M5 ;
        RECT  144.204 0 144.228 0.192 ;
    END
  END t0[610]
  PIN t0[611]
    DIRECTION OUTPUT ;
    USE SIGNAL ;
    PORT
      LAYER M5 ;
        RECT  144.444 0 144.468 0.192 ;
    END
  END t0[611]
  PIN t0[612]
    DIRECTION OUTPUT ;
    USE SIGNAL ;
    PORT
      LAYER M5 ;
        RECT  144.684 0 144.708 0.192 ;
    END
  END t0[612]
  PIN t0[613]
    DIRECTION OUTPUT ;
    USE SIGNAL ;
    PORT
      LAYER M5 ;
        RECT  144.924 0 144.948 0.192 ;
    END
  END t0[613]
  PIN t0[614]
    DIRECTION OUTPUT ;
    USE SIGNAL ;
    PORT
      LAYER M5 ;
        RECT  145.164 0 145.188 0.192 ;
    END
  END t0[614]
  PIN t0[615]
    DIRECTION OUTPUT ;
    USE SIGNAL ;
    PORT
      LAYER M5 ;
        RECT  145.356 0 145.38 0.192 ;
    END
  END t0[615]
  PIN t0[616]
    DIRECTION OUTPUT ;
    USE SIGNAL ;
    PORT
      LAYER M5 ;
        RECT  145.596 0 145.62 0.192 ;
    END
  END t0[616]
  PIN t0[617]
    DIRECTION OUTPUT ;
    USE SIGNAL ;
    PORT
      LAYER M5 ;
        RECT  145.836 0 145.86 0.192 ;
    END
  END t0[617]
  PIN t0[618]
    DIRECTION OUTPUT ;
    USE SIGNAL ;
    PORT
      LAYER M5 ;
        RECT  146.076 0 146.1 0.192 ;
    END
  END t0[618]
  PIN t0[619]
    DIRECTION OUTPUT ;
    USE SIGNAL ;
    PORT
      LAYER M5 ;
        RECT  146.316 0 146.34 0.192 ;
    END
  END t0[619]
  PIN t0[61]
    DIRECTION OUTPUT ;
    USE SIGNAL ;
    PORT
      LAYER M5 ;
        RECT  16.332 0 16.356 0.192 ;
    END
  END t0[61]
  PIN t0[620]
    DIRECTION OUTPUT ;
    USE SIGNAL ;
    PORT
      LAYER M5 ;
        RECT  146.556 0 146.58 0.192 ;
    END
  END t0[620]
  PIN t0[621]
    DIRECTION OUTPUT ;
    USE SIGNAL ;
    PORT
      LAYER M5 ;
        RECT  146.796 0 146.82 0.192 ;
    END
  END t0[621]
  PIN t0[622]
    DIRECTION OUTPUT ;
    USE SIGNAL ;
    PORT
      LAYER M5 ;
        RECT  146.988 0 147.012 0.192 ;
    END
  END t0[622]
  PIN t0[623]
    DIRECTION OUTPUT ;
    USE SIGNAL ;
    PORT
      LAYER M5 ;
        RECT  147.228 0 147.252 0.192 ;
    END
  END t0[623]
  PIN t0[624]
    DIRECTION OUTPUT ;
    USE SIGNAL ;
    PORT
      LAYER M5 ;
        RECT  147.468 0 147.492 0.192 ;
    END
  END t0[624]
  PIN t0[625]
    DIRECTION OUTPUT ;
    USE SIGNAL ;
    PORT
      LAYER M5 ;
        RECT  147.708 0 147.732 0.192 ;
    END
  END t0[625]
  PIN t0[626]
    DIRECTION OUTPUT ;
    USE SIGNAL ;
    PORT
      LAYER M5 ;
        RECT  147.948 0 147.972 0.192 ;
    END
  END t0[626]
  PIN t0[627]
    DIRECTION OUTPUT ;
    USE SIGNAL ;
    PORT
      LAYER M5 ;
        RECT  148.188 0 148.212 0.192 ;
    END
  END t0[627]
  PIN t0[628]
    DIRECTION OUTPUT ;
    USE SIGNAL ;
    PORT
      LAYER M5 ;
        RECT  148.428 0 148.452 0.192 ;
    END
  END t0[628]
  PIN t0[629]
    DIRECTION OUTPUT ;
    USE SIGNAL ;
    PORT
      LAYER M5 ;
        RECT  148.62 0 148.644 0.192 ;
    END
  END t0[629]
  PIN t0[62]
    DIRECTION OUTPUT ;
    USE SIGNAL ;
    PORT
      LAYER M5 ;
        RECT  16.572 0 16.596 0.192 ;
    END
  END t0[62]
  PIN t0[630]
    DIRECTION OUTPUT ;
    USE SIGNAL ;
    PORT
      LAYER M5 ;
        RECT  148.86 0 148.884 0.192 ;
    END
  END t0[630]
  PIN t0[631]
    DIRECTION OUTPUT ;
    USE SIGNAL ;
    PORT
      LAYER M5 ;
        RECT  149.1 0 149.124 0.192 ;
    END
  END t0[631]
  PIN t0[632]
    DIRECTION OUTPUT ;
    USE SIGNAL ;
    PORT
      LAYER M5 ;
        RECT  149.34 0 149.364 0.192 ;
    END
  END t0[632]
  PIN t0[633]
    DIRECTION OUTPUT ;
    USE SIGNAL ;
    PORT
      LAYER M5 ;
        RECT  149.58 0 149.604 0.192 ;
    END
  END t0[633]
  PIN t0[634]
    DIRECTION OUTPUT ;
    USE SIGNAL ;
    PORT
      LAYER M5 ;
        RECT  149.82 0 149.844 0.192 ;
    END
  END t0[634]
  PIN t0[635]
    DIRECTION OUTPUT ;
    USE SIGNAL ;
    PORT
      LAYER M5 ;
        RECT  150.06 0 150.084 0.192 ;
    END
  END t0[635]
  PIN t0[636]
    DIRECTION OUTPUT ;
    USE SIGNAL ;
    PORT
      LAYER M5 ;
        RECT  150.252 0 150.276 0.192 ;
    END
  END t0[636]
  PIN t0[637]
    DIRECTION OUTPUT ;
    USE SIGNAL ;
    PORT
      LAYER M5 ;
        RECT  150.492 0 150.516 0.192 ;
    END
  END t0[637]
  PIN t0[638]
    DIRECTION OUTPUT ;
    USE SIGNAL ;
    PORT
      LAYER M5 ;
        RECT  150.732 0 150.756 0.192 ;
    END
  END t0[638]
  PIN t0[639]
    DIRECTION OUTPUT ;
    USE SIGNAL ;
    PORT
      LAYER M5 ;
        RECT  150.972 0 150.996 0.192 ;
    END
  END t0[639]
  PIN t0[63]
    DIRECTION OUTPUT ;
    USE SIGNAL ;
    PORT
      LAYER M5 ;
        RECT  16.764 0 16.788 0.192 ;
    END
  END t0[63]
  PIN t0[640]
    DIRECTION OUTPUT ;
    USE SIGNAL ;
    PORT
      LAYER M5 ;
        RECT  151.212 0 151.236 0.192 ;
    END
  END t0[640]
  PIN t0[641]
    DIRECTION OUTPUT ;
    USE SIGNAL ;
    PORT
      LAYER M5 ;
        RECT  151.452 0 151.476 0.192 ;
    END
  END t0[641]
  PIN t0[642]
    DIRECTION OUTPUT ;
    USE SIGNAL ;
    PORT
      LAYER M5 ;
        RECT  151.692 0 151.716 0.192 ;
    END
  END t0[642]
  PIN t0[643]
    DIRECTION OUTPUT ;
    USE SIGNAL ;
    PORT
      LAYER M5 ;
        RECT  151.884 0 151.908 0.192 ;
    END
  END t0[643]
  PIN t0[644]
    DIRECTION OUTPUT ;
    USE SIGNAL ;
    PORT
      LAYER M5 ;
        RECT  152.124 0 152.148 0.192 ;
    END
  END t0[644]
  PIN t0[645]
    DIRECTION OUTPUT ;
    USE SIGNAL ;
    PORT
      LAYER M5 ;
        RECT  152.364 0 152.388 0.192 ;
    END
  END t0[645]
  PIN t0[646]
    DIRECTION OUTPUT ;
    USE SIGNAL ;
    PORT
      LAYER M5 ;
        RECT  152.604 0 152.628 0.192 ;
    END
  END t0[646]
  PIN t0[647]
    DIRECTION OUTPUT ;
    USE SIGNAL ;
    PORT
      LAYER M5 ;
        RECT  152.844 0 152.868 0.192 ;
    END
  END t0[647]
  PIN t0[648]
    DIRECTION OUTPUT ;
    USE SIGNAL ;
    PORT
      LAYER M5 ;
        RECT  153.084 0 153.108 0.192 ;
    END
  END t0[648]
  PIN t0[649]
    DIRECTION OUTPUT ;
    USE SIGNAL ;
    PORT
      LAYER M5 ;
        RECT  153.324 0 153.348 0.192 ;
    END
  END t0[649]
  PIN t0[64]
    DIRECTION OUTPUT ;
    USE SIGNAL ;
    PORT
      LAYER M5 ;
        RECT  17.004 0 17.028 0.192 ;
    END
  END t0[64]
  PIN t0[650]
    DIRECTION OUTPUT ;
    USE SIGNAL ;
    PORT
      LAYER M5 ;
        RECT  153.516 0 153.54 0.192 ;
    END
  END t0[650]
  PIN t0[651]
    DIRECTION OUTPUT ;
    USE SIGNAL ;
    PORT
      LAYER M5 ;
        RECT  153.756 0 153.78 0.192 ;
    END
  END t0[651]
  PIN t0[652]
    DIRECTION OUTPUT ;
    USE SIGNAL ;
    PORT
      LAYER M5 ;
        RECT  153.996 0 154.02 0.192 ;
    END
  END t0[652]
  PIN t0[653]
    DIRECTION OUTPUT ;
    USE SIGNAL ;
    PORT
      LAYER M5 ;
        RECT  154.236 0 154.26 0.192 ;
    END
  END t0[653]
  PIN t0[654]
    DIRECTION OUTPUT ;
    USE SIGNAL ;
    PORT
      LAYER M5 ;
        RECT  154.476 0 154.5 0.192 ;
    END
  END t0[654]
  PIN t0[655]
    DIRECTION OUTPUT ;
    USE SIGNAL ;
    PORT
      LAYER M5 ;
        RECT  154.716 0 154.74 0.192 ;
    END
  END t0[655]
  PIN t0[656]
    DIRECTION OUTPUT ;
    USE SIGNAL ;
    PORT
      LAYER M5 ;
        RECT  154.908 0 154.932 0.192 ;
    END
  END t0[656]
  PIN t0[657]
    DIRECTION OUTPUT ;
    USE SIGNAL ;
    PORT
      LAYER M5 ;
        RECT  155.148 0 155.172 0.192 ;
    END
  END t0[657]
  PIN t0[658]
    DIRECTION OUTPUT ;
    USE SIGNAL ;
    PORT
      LAYER M5 ;
        RECT  155.388 0 155.412 0.192 ;
    END
  END t0[658]
  PIN t0[659]
    DIRECTION OUTPUT ;
    USE SIGNAL ;
    PORT
      LAYER M5 ;
        RECT  155.628 0 155.652 0.192 ;
    END
  END t0[659]
  PIN t0[65]
    DIRECTION OUTPUT ;
    USE SIGNAL ;
    PORT
      LAYER M5 ;
        RECT  17.244 0 17.268 0.192 ;
    END
  END t0[65]
  PIN t0[660]
    DIRECTION OUTPUT ;
    USE SIGNAL ;
    PORT
      LAYER M5 ;
        RECT  155.868 0 155.892 0.192 ;
    END
  END t0[660]
  PIN t0[661]
    DIRECTION OUTPUT ;
    USE SIGNAL ;
    PORT
      LAYER M5 ;
        RECT  156.108 0 156.132 0.192 ;
    END
  END t0[661]
  PIN t0[662]
    DIRECTION OUTPUT ;
    USE SIGNAL ;
    PORT
      LAYER M5 ;
        RECT  156.348 0 156.372 0.192 ;
    END
  END t0[662]
  PIN t0[663]
    DIRECTION OUTPUT ;
    USE SIGNAL ;
    PORT
      LAYER M5 ;
        RECT  156.54 0 156.564 0.192 ;
    END
  END t0[663]
  PIN t0[664]
    DIRECTION OUTPUT ;
    USE SIGNAL ;
    PORT
      LAYER M5 ;
        RECT  156.78 0 156.804 0.192 ;
    END
  END t0[664]
  PIN t0[665]
    DIRECTION OUTPUT ;
    USE SIGNAL ;
    PORT
      LAYER M5 ;
        RECT  157.02 0 157.044 0.192 ;
    END
  END t0[665]
  PIN t0[666]
    DIRECTION OUTPUT ;
    USE SIGNAL ;
    PORT
      LAYER M5 ;
        RECT  157.26 0 157.284 0.192 ;
    END
  END t0[666]
  PIN t0[667]
    DIRECTION OUTPUT ;
    USE SIGNAL ;
    PORT
      LAYER M5 ;
        RECT  157.5 0 157.524 0.192 ;
    END
  END t0[667]
  PIN t0[668]
    DIRECTION OUTPUT ;
    USE SIGNAL ;
    PORT
      LAYER M5 ;
        RECT  157.74 0 157.764 0.192 ;
    END
  END t0[668]
  PIN t0[669]
    DIRECTION OUTPUT ;
    USE SIGNAL ;
    PORT
      LAYER M5 ;
        RECT  157.98 0 158.004 0.192 ;
    END
  END t0[669]
  PIN t0[66]
    DIRECTION OUTPUT ;
    USE SIGNAL ;
    PORT
      LAYER M5 ;
        RECT  17.484 0 17.508 0.192 ;
    END
  END t0[66]
  PIN t0[670]
    DIRECTION OUTPUT ;
    USE SIGNAL ;
    PORT
      LAYER M5 ;
        RECT  158.172 0 158.196 0.192 ;
    END
  END t0[670]
  PIN t0[671]
    DIRECTION OUTPUT ;
    USE SIGNAL ;
    PORT
      LAYER M5 ;
        RECT  158.412 0 158.436 0.192 ;
    END
  END t0[671]
  PIN t0[672]
    DIRECTION OUTPUT ;
    USE SIGNAL ;
    PORT
      LAYER M5 ;
        RECT  158.652 0 158.676 0.192 ;
    END
  END t0[672]
  PIN t0[673]
    DIRECTION OUTPUT ;
    USE SIGNAL ;
    PORT
      LAYER M5 ;
        RECT  158.892 0 158.916 0.192 ;
    END
  END t0[673]
  PIN t0[674]
    DIRECTION OUTPUT ;
    USE SIGNAL ;
    PORT
      LAYER M5 ;
        RECT  159.132 0 159.156 0.192 ;
    END
  END t0[674]
  PIN t0[675]
    DIRECTION OUTPUT ;
    USE SIGNAL ;
    PORT
      LAYER M5 ;
        RECT  159.372 0 159.396 0.192 ;
    END
  END t0[675]
  PIN t0[676]
    DIRECTION OUTPUT ;
    USE SIGNAL ;
    PORT
      LAYER M5 ;
        RECT  159.612 0 159.636 0.192 ;
    END
  END t0[676]
  PIN t0[677]
    DIRECTION OUTPUT ;
    USE SIGNAL ;
    PORT
      LAYER M5 ;
        RECT  159.804 0 159.828 0.192 ;
    END
  END t0[677]
  PIN t0[678]
    DIRECTION OUTPUT ;
    USE SIGNAL ;
    PORT
      LAYER M5 ;
        RECT  160.044 0 160.068 0.192 ;
    END
  END t0[678]
  PIN t0[679]
    DIRECTION OUTPUT ;
    USE SIGNAL ;
    PORT
      LAYER M5 ;
        RECT  160.284 0 160.308 0.192 ;
    END
  END t0[679]
  PIN t0[67]
    DIRECTION OUTPUT ;
    USE SIGNAL ;
    PORT
      LAYER M5 ;
        RECT  17.724 0 17.748 0.192 ;
    END
  END t0[67]
  PIN t0[680]
    DIRECTION OUTPUT ;
    USE SIGNAL ;
    PORT
      LAYER M5 ;
        RECT  160.524 0 160.548 0.192 ;
    END
  END t0[680]
  PIN t0[681]
    DIRECTION OUTPUT ;
    USE SIGNAL ;
    PORT
      LAYER M5 ;
        RECT  160.764 0 160.788 0.192 ;
    END
  END t0[681]
  PIN t0[682]
    DIRECTION OUTPUT ;
    USE SIGNAL ;
    PORT
      LAYER M5 ;
        RECT  161.004 0 161.028 0.192 ;
    END
  END t0[682]
  PIN t0[683]
    DIRECTION OUTPUT ;
    USE SIGNAL ;
    PORT
      LAYER M5 ;
        RECT  161.244 0 161.268 0.192 ;
    END
  END t0[683]
  PIN t0[684]
    DIRECTION OUTPUT ;
    USE SIGNAL ;
    PORT
      LAYER M5 ;
        RECT  161.436 0 161.46 0.192 ;
    END
  END t0[684]
  PIN t0[685]
    DIRECTION OUTPUT ;
    USE SIGNAL ;
    PORT
      LAYER M5 ;
        RECT  161.676 0 161.7 0.192 ;
    END
  END t0[685]
  PIN t0[686]
    DIRECTION OUTPUT ;
    USE SIGNAL ;
    PORT
      LAYER M5 ;
        RECT  161.916 0 161.94 0.192 ;
    END
  END t0[686]
  PIN t0[687]
    DIRECTION OUTPUT ;
    USE SIGNAL ;
    PORT
      LAYER M5 ;
        RECT  162.156 0 162.18 0.192 ;
    END
  END t0[687]
  PIN t0[688]
    DIRECTION OUTPUT ;
    USE SIGNAL ;
    PORT
      LAYER M5 ;
        RECT  162.396 0 162.42 0.192 ;
    END
  END t0[688]
  PIN t0[689]
    DIRECTION OUTPUT ;
    USE SIGNAL ;
    PORT
      LAYER M5 ;
        RECT  162.636 0 162.66 0.192 ;
    END
  END t0[689]
  PIN t0[68]
    DIRECTION OUTPUT ;
    USE SIGNAL ;
    PORT
      LAYER M5 ;
        RECT  17.964 0 17.988 0.192 ;
    END
  END t0[68]
  PIN t0[690]
    DIRECTION OUTPUT ;
    USE SIGNAL ;
    PORT
      LAYER M5 ;
        RECT  162.828 0 162.852 0.192 ;
    END
  END t0[690]
  PIN t0[691]
    DIRECTION OUTPUT ;
    USE SIGNAL ;
    PORT
      LAYER M5 ;
        RECT  163.068 0 163.092 0.192 ;
    END
  END t0[691]
  PIN t0[692]
    DIRECTION OUTPUT ;
    USE SIGNAL ;
    PORT
      LAYER M5 ;
        RECT  163.308 0 163.332 0.192 ;
    END
  END t0[692]
  PIN t0[693]
    DIRECTION OUTPUT ;
    USE SIGNAL ;
    PORT
      LAYER M5 ;
        RECT  163.548 0 163.572 0.192 ;
    END
  END t0[693]
  PIN t0[694]
    DIRECTION OUTPUT ;
    USE SIGNAL ;
    PORT
      LAYER M5 ;
        RECT  163.788 0 163.812 0.192 ;
    END
  END t0[694]
  PIN t0[695]
    DIRECTION OUTPUT ;
    USE SIGNAL ;
    PORT
      LAYER M5 ;
        RECT  164.028 0 164.052 0.192 ;
    END
  END t0[695]
  PIN t0[696]
    DIRECTION OUTPUT ;
    USE SIGNAL ;
    PORT
      LAYER M5 ;
        RECT  164.268 0 164.292 0.192 ;
    END
  END t0[696]
  PIN t0[697]
    DIRECTION OUTPUT ;
    USE SIGNAL ;
    PORT
      LAYER M5 ;
        RECT  164.46 0 164.484 0.192 ;
    END
  END t0[697]
  PIN t0[698]
    DIRECTION OUTPUT ;
    USE SIGNAL ;
    PORT
      LAYER M5 ;
        RECT  164.7 0 164.724 0.192 ;
    END
  END t0[698]
  PIN t0[699]
    DIRECTION OUTPUT ;
    USE SIGNAL ;
    PORT
      LAYER M5 ;
        RECT  164.94 0 164.964 0.192 ;
    END
  END t0[699]
  PIN t0[69]
    DIRECTION OUTPUT ;
    USE SIGNAL ;
    PORT
      LAYER M5 ;
        RECT  18.156 0 18.18 0.192 ;
    END
  END t0[69]
  PIN t0[6]
    DIRECTION OUTPUT ;
    USE SIGNAL ;
    PORT
      LAYER M5 ;
        RECT  3.516 0 3.54 0.192 ;
    END
  END t0[6]
  PIN t0[700]
    DIRECTION OUTPUT ;
    USE SIGNAL ;
    PORT
      LAYER M5 ;
        RECT  165.18 0 165.204 0.192 ;
    END
  END t0[700]
  PIN t0[701]
    DIRECTION OUTPUT ;
    USE SIGNAL ;
    PORT
      LAYER M5 ;
        RECT  165.42 0 165.444 0.192 ;
    END
  END t0[701]
  PIN t0[702]
    DIRECTION OUTPUT ;
    USE SIGNAL ;
    PORT
      LAYER M5 ;
        RECT  165.66 0 165.684 0.192 ;
    END
  END t0[702]
  PIN t0[703]
    DIRECTION OUTPUT ;
    USE SIGNAL ;
    PORT
      LAYER M5 ;
        RECT  165.9 0 165.924 0.192 ;
    END
  END t0[703]
  PIN t0[704]
    DIRECTION OUTPUT ;
    USE SIGNAL ;
    PORT
      LAYER M5 ;
        RECT  166.092 0 166.116 0.192 ;
    END
  END t0[704]
  PIN t0[705]
    DIRECTION OUTPUT ;
    USE SIGNAL ;
    PORT
      LAYER M5 ;
        RECT  166.332 0 166.356 0.192 ;
    END
  END t0[705]
  PIN t0[706]
    DIRECTION OUTPUT ;
    USE SIGNAL ;
    PORT
      LAYER M5 ;
        RECT  166.572 0 166.596 0.192 ;
    END
  END t0[706]
  PIN t0[707]
    DIRECTION OUTPUT ;
    USE SIGNAL ;
    PORT
      LAYER M5 ;
        RECT  166.812 0 166.836 0.192 ;
    END
  END t0[707]
  PIN t0[708]
    DIRECTION OUTPUT ;
    USE SIGNAL ;
    PORT
      LAYER M5 ;
        RECT  167.052 0 167.076 0.192 ;
    END
  END t0[708]
  PIN t0[709]
    DIRECTION OUTPUT ;
    USE SIGNAL ;
    PORT
      LAYER M5 ;
        RECT  167.292 0 167.316 0.192 ;
    END
  END t0[709]
  PIN t0[70]
    DIRECTION OUTPUT ;
    USE SIGNAL ;
    PORT
      LAYER M5 ;
        RECT  18.396 0 18.42 0.192 ;
    END
  END t0[70]
  PIN t0[710]
    DIRECTION OUTPUT ;
    USE SIGNAL ;
    PORT
      LAYER M5 ;
        RECT  167.532 0 167.556 0.192 ;
    END
  END t0[710]
  PIN t0[711]
    DIRECTION OUTPUT ;
    USE SIGNAL ;
    PORT
      LAYER M5 ;
        RECT  167.724 0 167.748 0.192 ;
    END
  END t0[711]
  PIN t0[712]
    DIRECTION OUTPUT ;
    USE SIGNAL ;
    PORT
      LAYER M5 ;
        RECT  167.964 0 167.988 0.192 ;
    END
  END t0[712]
  PIN t0[713]
    DIRECTION OUTPUT ;
    USE SIGNAL ;
    PORT
      LAYER M5 ;
        RECT  168.204 0 168.228 0.192 ;
    END
  END t0[713]
  PIN t0[714]
    DIRECTION OUTPUT ;
    USE SIGNAL ;
    PORT
      LAYER M5 ;
        RECT  168.444 0 168.468 0.192 ;
    END
  END t0[714]
  PIN t0[715]
    DIRECTION OUTPUT ;
    USE SIGNAL ;
    PORT
      LAYER M5 ;
        RECT  168.684 0 168.708 0.192 ;
    END
  END t0[715]
  PIN t0[716]
    DIRECTION OUTPUT ;
    USE SIGNAL ;
    PORT
      LAYER M5 ;
        RECT  168.924 0 168.948 0.192 ;
    END
  END t0[716]
  PIN t0[717]
    DIRECTION OUTPUT ;
    USE SIGNAL ;
    PORT
      LAYER M5 ;
        RECT  169.164 0 169.188 0.192 ;
    END
  END t0[717]
  PIN t0[718]
    DIRECTION OUTPUT ;
    USE SIGNAL ;
    PORT
      LAYER M5 ;
        RECT  169.356 0 169.38 0.192 ;
    END
  END t0[718]
  PIN t0[719]
    DIRECTION OUTPUT ;
    USE SIGNAL ;
    PORT
      LAYER M5 ;
        RECT  169.596 0 169.62 0.192 ;
    END
  END t0[719]
  PIN t0[71]
    DIRECTION OUTPUT ;
    USE SIGNAL ;
    PORT
      LAYER M5 ;
        RECT  18.636 0 18.66 0.192 ;
    END
  END t0[71]
  PIN t0[720]
    DIRECTION OUTPUT ;
    USE SIGNAL ;
    PORT
      LAYER M5 ;
        RECT  169.836 0 169.86 0.192 ;
    END
  END t0[720]
  PIN t0[721]
    DIRECTION OUTPUT ;
    USE SIGNAL ;
    PORT
      LAYER M5 ;
        RECT  170.076 0 170.1 0.192 ;
    END
  END t0[721]
  PIN t0[722]
    DIRECTION OUTPUT ;
    USE SIGNAL ;
    PORT
      LAYER M5 ;
        RECT  170.316 0 170.34 0.192 ;
    END
  END t0[722]
  PIN t0[723]
    DIRECTION OUTPUT ;
    USE SIGNAL ;
    PORT
      LAYER M5 ;
        RECT  170.556 0 170.58 0.192 ;
    END
  END t0[723]
  PIN t0[724]
    DIRECTION OUTPUT ;
    USE SIGNAL ;
    PORT
      LAYER M5 ;
        RECT  170.796 0 170.82 0.192 ;
    END
  END t0[724]
  PIN t0[725]
    DIRECTION OUTPUT ;
    USE SIGNAL ;
    PORT
      LAYER M5 ;
        RECT  170.988 0 171.012 0.192 ;
    END
  END t0[725]
  PIN t0[726]
    DIRECTION OUTPUT ;
    USE SIGNAL ;
    PORT
      LAYER M5 ;
        RECT  171.228 0 171.252 0.192 ;
    END
  END t0[726]
  PIN t0[727]
    DIRECTION OUTPUT ;
    USE SIGNAL ;
    PORT
      LAYER M5 ;
        RECT  171.468 0 171.492 0.192 ;
    END
  END t0[727]
  PIN t0[728]
    DIRECTION OUTPUT ;
    USE SIGNAL ;
    PORT
      LAYER M5 ;
        RECT  171.708 0 171.732 0.192 ;
    END
  END t0[728]
  PIN t0[729]
    DIRECTION OUTPUT ;
    USE SIGNAL ;
    PORT
      LAYER M5 ;
        RECT  171.948 0 171.972 0.192 ;
    END
  END t0[729]
  PIN t0[72]
    DIRECTION OUTPUT ;
    USE SIGNAL ;
    PORT
      LAYER M5 ;
        RECT  18.876 0 18.9 0.192 ;
    END
  END t0[72]
  PIN t0[730]
    DIRECTION OUTPUT ;
    USE SIGNAL ;
    PORT
      LAYER M5 ;
        RECT  172.188 0 172.212 0.192 ;
    END
  END t0[730]
  PIN t0[731]
    DIRECTION OUTPUT ;
    USE SIGNAL ;
    PORT
      LAYER M5 ;
        RECT  172.38 0 172.404 0.192 ;
    END
  END t0[731]
  PIN t0[732]
    DIRECTION OUTPUT ;
    USE SIGNAL ;
    PORT
      LAYER M5 ;
        RECT  172.62 0 172.644 0.192 ;
    END
  END t0[732]
  PIN t0[733]
    DIRECTION OUTPUT ;
    USE SIGNAL ;
    PORT
      LAYER M5 ;
        RECT  172.86 0 172.884 0.192 ;
    END
  END t0[733]
  PIN t0[734]
    DIRECTION OUTPUT ;
    USE SIGNAL ;
    PORT
      LAYER M5 ;
        RECT  173.1 0 173.124 0.192 ;
    END
  END t0[734]
  PIN t0[735]
    DIRECTION OUTPUT ;
    USE SIGNAL ;
    PORT
      LAYER M5 ;
        RECT  173.34 0 173.364 0.192 ;
    END
  END t0[735]
  PIN t0[736]
    DIRECTION OUTPUT ;
    USE SIGNAL ;
    PORT
      LAYER M5 ;
        RECT  173.58 0 173.604 0.192 ;
    END
  END t0[736]
  PIN t0[737]
    DIRECTION OUTPUT ;
    USE SIGNAL ;
    PORT
      LAYER M5 ;
        RECT  173.82 0 173.844 0.192 ;
    END
  END t0[737]
  PIN t0[738]
    DIRECTION OUTPUT ;
    USE SIGNAL ;
    PORT
      LAYER M5 ;
        RECT  174.012 0 174.036 0.192 ;
    END
  END t0[738]
  PIN t0[739]
    DIRECTION OUTPUT ;
    USE SIGNAL ;
    PORT
      LAYER M5 ;
        RECT  174.252 0 174.276 0.192 ;
    END
  END t0[739]
  PIN t0[73]
    DIRECTION OUTPUT ;
    USE SIGNAL ;
    PORT
      LAYER M5 ;
        RECT  19.116 0 19.14 0.192 ;
    END
  END t0[73]
  PIN t0[740]
    DIRECTION OUTPUT ;
    USE SIGNAL ;
    PORT
      LAYER M5 ;
        RECT  174.492 0 174.516 0.192 ;
    END
  END t0[740]
  PIN t0[741]
    DIRECTION OUTPUT ;
    USE SIGNAL ;
    PORT
      LAYER M5 ;
        RECT  174.732 0 174.756 0.192 ;
    END
  END t0[741]
  PIN t0[742]
    DIRECTION OUTPUT ;
    USE SIGNAL ;
    PORT
      LAYER M5 ;
        RECT  174.972 0 174.996 0.192 ;
    END
  END t0[742]
  PIN t0[743]
    DIRECTION OUTPUT ;
    USE SIGNAL ;
    PORT
      LAYER M5 ;
        RECT  175.212 0 175.236 0.192 ;
    END
  END t0[743]
  PIN t0[744]
    DIRECTION OUTPUT ;
    USE SIGNAL ;
    PORT
      LAYER M5 ;
        RECT  175.452 0 175.476 0.192 ;
    END
  END t0[744]
  PIN t0[745]
    DIRECTION OUTPUT ;
    USE SIGNAL ;
    PORT
      LAYER M5 ;
        RECT  175.644 0 175.668 0.192 ;
    END
  END t0[745]
  PIN t0[746]
    DIRECTION OUTPUT ;
    USE SIGNAL ;
    PORT
      LAYER M5 ;
        RECT  175.884 0 175.908 0.192 ;
    END
  END t0[746]
  PIN t0[747]
    DIRECTION OUTPUT ;
    USE SIGNAL ;
    PORT
      LAYER M5 ;
        RECT  176.124 0 176.148 0.192 ;
    END
  END t0[747]
  PIN t0[748]
    DIRECTION OUTPUT ;
    USE SIGNAL ;
    PORT
      LAYER M5 ;
        RECT  176.364 0 176.388 0.192 ;
    END
  END t0[748]
  PIN t0[749]
    DIRECTION OUTPUT ;
    USE SIGNAL ;
    PORT
      LAYER M5 ;
        RECT  176.604 0 176.628 0.192 ;
    END
  END t0[749]
  PIN t0[74]
    DIRECTION OUTPUT ;
    USE SIGNAL ;
    PORT
      LAYER M5 ;
        RECT  19.356 0 19.38 0.192 ;
    END
  END t0[74]
  PIN t0[750]
    DIRECTION OUTPUT ;
    USE SIGNAL ;
    PORT
      LAYER M5 ;
        RECT  176.844 0 176.868 0.192 ;
    END
  END t0[750]
  PIN t0[751]
    DIRECTION OUTPUT ;
    USE SIGNAL ;
    PORT
      LAYER M5 ;
        RECT  177.084 0 177.108 0.192 ;
    END
  END t0[751]
  PIN t0[752]
    DIRECTION OUTPUT ;
    USE SIGNAL ;
    PORT
      LAYER M5 ;
        RECT  177.276 0 177.3 0.192 ;
    END
  END t0[752]
  PIN t0[753]
    DIRECTION OUTPUT ;
    USE SIGNAL ;
    PORT
      LAYER M5 ;
        RECT  177.516 0 177.54 0.192 ;
    END
  END t0[753]
  PIN t0[754]
    DIRECTION OUTPUT ;
    USE SIGNAL ;
    PORT
      LAYER M5 ;
        RECT  177.756 0 177.78 0.192 ;
    END
  END t0[754]
  PIN t0[755]
    DIRECTION OUTPUT ;
    USE SIGNAL ;
    PORT
      LAYER M5 ;
        RECT  177.996 0 178.02 0.192 ;
    END
  END t0[755]
  PIN t0[756]
    DIRECTION OUTPUT ;
    USE SIGNAL ;
    PORT
      LAYER M5 ;
        RECT  178.236 0 178.26 0.192 ;
    END
  END t0[756]
  PIN t0[757]
    DIRECTION OUTPUT ;
    USE SIGNAL ;
    PORT
      LAYER M5 ;
        RECT  178.476 0 178.5 0.192 ;
    END
  END t0[757]
  PIN t0[758]
    DIRECTION OUTPUT ;
    USE SIGNAL ;
    PORT
      LAYER M5 ;
        RECT  178.716 0 178.74 0.192 ;
    END
  END t0[758]
  PIN t0[759]
    DIRECTION OUTPUT ;
    USE SIGNAL ;
    PORT
      LAYER M5 ;
        RECT  178.908 0 178.932 0.192 ;
    END
  END t0[759]
  PIN t0[75]
    DIRECTION OUTPUT ;
    USE SIGNAL ;
    PORT
      LAYER M5 ;
        RECT  19.596 0 19.62 0.192 ;
    END
  END t0[75]
  PIN t0[760]
    DIRECTION OUTPUT ;
    USE SIGNAL ;
    PORT
      LAYER M5 ;
        RECT  179.148 0 179.172 0.192 ;
    END
  END t0[760]
  PIN t0[761]
    DIRECTION OUTPUT ;
    USE SIGNAL ;
    PORT
      LAYER M5 ;
        RECT  179.388 0 179.412 0.192 ;
    END
  END t0[761]
  PIN t0[762]
    DIRECTION OUTPUT ;
    USE SIGNAL ;
    PORT
      LAYER M5 ;
        RECT  179.628 0 179.652 0.192 ;
    END
  END t0[762]
  PIN t0[763]
    DIRECTION OUTPUT ;
    USE SIGNAL ;
    PORT
      LAYER M5 ;
        RECT  179.868 0 179.892 0.192 ;
    END
  END t0[763]
  PIN t0[764]
    DIRECTION OUTPUT ;
    USE SIGNAL ;
    PORT
      LAYER M5 ;
        RECT  180.108 0 180.132 0.192 ;
    END
  END t0[764]
  PIN t0[765]
    DIRECTION OUTPUT ;
    USE SIGNAL ;
    PORT
      LAYER M5 ;
        RECT  180.348 0 180.372 0.192 ;
    END
  END t0[765]
  PIN t0[766]
    DIRECTION OUTPUT ;
    USE SIGNAL ;
    PORT
      LAYER M5 ;
        RECT  180.54 0 180.564 0.192 ;
    END
  END t0[766]
  PIN t0[767]
    DIRECTION OUTPUT ;
    USE SIGNAL ;
    PORT
      LAYER M5 ;
        RECT  180.78 0 180.804 0.192 ;
    END
  END t0[767]
  PIN t0[768]
    DIRECTION OUTPUT ;
    USE SIGNAL ;
    PORT
      LAYER M5 ;
        RECT  181.02 0 181.044 0.192 ;
    END
  END t0[768]
  PIN t0[769]
    DIRECTION OUTPUT ;
    USE SIGNAL ;
    PORT
      LAYER M5 ;
        RECT  181.26 0 181.284 0.192 ;
    END
  END t0[769]
  PIN t0[76]
    DIRECTION OUTPUT ;
    USE SIGNAL ;
    PORT
      LAYER M5 ;
        RECT  19.788 0 19.812 0.192 ;
    END
  END t0[76]
  PIN t0[770]
    DIRECTION OUTPUT ;
    USE SIGNAL ;
    PORT
      LAYER M5 ;
        RECT  181.5 0 181.524 0.192 ;
    END
  END t0[770]
  PIN t0[771]
    DIRECTION OUTPUT ;
    USE SIGNAL ;
    PORT
      LAYER M5 ;
        RECT  181.74 0 181.764 0.192 ;
    END
  END t0[771]
  PIN t0[772]
    DIRECTION OUTPUT ;
    USE SIGNAL ;
    PORT
      LAYER M5 ;
        RECT  181.932 0 181.956 0.192 ;
    END
  END t0[772]
  PIN t0[773]
    DIRECTION OUTPUT ;
    USE SIGNAL ;
    PORT
      LAYER M5 ;
        RECT  182.172 0 182.196 0.192 ;
    END
  END t0[773]
  PIN t0[774]
    DIRECTION OUTPUT ;
    USE SIGNAL ;
    PORT
      LAYER M5 ;
        RECT  182.412 0 182.436 0.192 ;
    END
  END t0[774]
  PIN t0[775]
    DIRECTION OUTPUT ;
    USE SIGNAL ;
    PORT
      LAYER M5 ;
        RECT  182.652 0 182.676 0.192 ;
    END
  END t0[775]
  PIN t0[776]
    DIRECTION OUTPUT ;
    USE SIGNAL ;
    PORT
      LAYER M5 ;
        RECT  182.892 0 182.916 0.192 ;
    END
  END t0[776]
  PIN t0[777]
    DIRECTION OUTPUT ;
    USE SIGNAL ;
    PORT
      LAYER M5 ;
        RECT  183.132 0 183.156 0.192 ;
    END
  END t0[777]
  PIN t0[778]
    DIRECTION OUTPUT ;
    USE SIGNAL ;
    PORT
      LAYER M5 ;
        RECT  183.372 0 183.396 0.192 ;
    END
  END t0[778]
  PIN t0[779]
    DIRECTION OUTPUT ;
    USE SIGNAL ;
    PORT
      LAYER M5 ;
        RECT  183.564 0 183.588 0.192 ;
    END
  END t0[779]
  PIN t0[77]
    DIRECTION OUTPUT ;
    USE SIGNAL ;
    PORT
      LAYER M5 ;
        RECT  20.028 0 20.052 0.192 ;
    END
  END t0[77]
  PIN t0[780]
    DIRECTION OUTPUT ;
    USE SIGNAL ;
    PORT
      LAYER M5 ;
        RECT  183.804 0 183.828 0.192 ;
    END
  END t0[780]
  PIN t0[781]
    DIRECTION OUTPUT ;
    USE SIGNAL ;
    PORT
      LAYER M5 ;
        RECT  184.044 0 184.068 0.192 ;
    END
  END t0[781]
  PIN t0[782]
    DIRECTION OUTPUT ;
    USE SIGNAL ;
    PORT
      LAYER M5 ;
        RECT  184.284 0 184.308 0.192 ;
    END
  END t0[782]
  PIN t0[783]
    DIRECTION OUTPUT ;
    USE SIGNAL ;
    PORT
      LAYER M5 ;
        RECT  184.524 0 184.548 0.192 ;
    END
  END t0[783]
  PIN t0[784]
    DIRECTION OUTPUT ;
    USE SIGNAL ;
    PORT
      LAYER M5 ;
        RECT  184.764 0 184.788 0.192 ;
    END
  END t0[784]
  PIN t0[785]
    DIRECTION OUTPUT ;
    USE SIGNAL ;
    PORT
      LAYER M5 ;
        RECT  185.004 0 185.028 0.192 ;
    END
  END t0[785]
  PIN t0[786]
    DIRECTION OUTPUT ;
    USE SIGNAL ;
    PORT
      LAYER M5 ;
        RECT  185.196 0 185.22 0.192 ;
    END
  END t0[786]
  PIN t0[787]
    DIRECTION OUTPUT ;
    USE SIGNAL ;
    PORT
      LAYER M5 ;
        RECT  185.436 0 185.46 0.192 ;
    END
  END t0[787]
  PIN t0[788]
    DIRECTION OUTPUT ;
    USE SIGNAL ;
    PORT
      LAYER M5 ;
        RECT  185.676 0 185.7 0.192 ;
    END
  END t0[788]
  PIN t0[789]
    DIRECTION OUTPUT ;
    USE SIGNAL ;
    PORT
      LAYER M5 ;
        RECT  185.916 0 185.94 0.192 ;
    END
  END t0[789]
  PIN t0[78]
    DIRECTION OUTPUT ;
    USE SIGNAL ;
    PORT
      LAYER M5 ;
        RECT  20.268 0 20.292 0.192 ;
    END
  END t0[78]
  PIN t0[790]
    DIRECTION OUTPUT ;
    USE SIGNAL ;
    PORT
      LAYER M5 ;
        RECT  186.156 0 186.18 0.192 ;
    END
  END t0[790]
  PIN t0[791]
    DIRECTION OUTPUT ;
    USE SIGNAL ;
    PORT
      LAYER M5 ;
        RECT  186.396 0 186.42 0.192 ;
    END
  END t0[791]
  PIN t0[792]
    DIRECTION OUTPUT ;
    USE SIGNAL ;
    PORT
      LAYER M5 ;
        RECT  186.636 0 186.66 0.192 ;
    END
  END t0[792]
  PIN t0[793]
    DIRECTION OUTPUT ;
    USE SIGNAL ;
    PORT
      LAYER M5 ;
        RECT  186.828 0 186.852 0.192 ;
    END
  END t0[793]
  PIN t0[794]
    DIRECTION OUTPUT ;
    USE SIGNAL ;
    PORT
      LAYER M5 ;
        RECT  187.068 0 187.092 0.192 ;
    END
  END t0[794]
  PIN t0[795]
    DIRECTION OUTPUT ;
    USE SIGNAL ;
    PORT
      LAYER M5 ;
        RECT  187.308 0 187.332 0.192 ;
    END
  END t0[795]
  PIN t0[796]
    DIRECTION OUTPUT ;
    USE SIGNAL ;
    PORT
      LAYER M5 ;
        RECT  187.548 0 187.572 0.192 ;
    END
  END t0[796]
  PIN t0[797]
    DIRECTION OUTPUT ;
    USE SIGNAL ;
    PORT
      LAYER M5 ;
        RECT  187.788 0 187.812 0.192 ;
    END
  END t0[797]
  PIN t0[798]
    DIRECTION OUTPUT ;
    USE SIGNAL ;
    PORT
      LAYER M5 ;
        RECT  188.028 0 188.052 0.192 ;
    END
  END t0[798]
  PIN t0[799]
    DIRECTION OUTPUT ;
    USE SIGNAL ;
    PORT
      LAYER M5 ;
        RECT  188.268 0 188.292 0.192 ;
    END
  END t0[799]
  PIN t0[79]
    DIRECTION OUTPUT ;
    USE SIGNAL ;
    PORT
      LAYER M5 ;
        RECT  20.508 0 20.532 0.192 ;
    END
  END t0[79]
  PIN t0[7]
    DIRECTION OUTPUT ;
    USE SIGNAL ;
    PORT
      LAYER M5 ;
        RECT  3.756 0 3.78 0.192 ;
    END
  END t0[7]
  PIN t0[800]
    DIRECTION OUTPUT ;
    USE SIGNAL ;
    PORT
      LAYER M5 ;
        RECT  188.46 0 188.484 0.192 ;
    END
  END t0[800]
  PIN t0[801]
    DIRECTION OUTPUT ;
    USE SIGNAL ;
    PORT
      LAYER M5 ;
        RECT  188.7 0 188.724 0.192 ;
    END
  END t0[801]
  PIN t0[802]
    DIRECTION OUTPUT ;
    USE SIGNAL ;
    PORT
      LAYER M5 ;
        RECT  188.94 0 188.964 0.192 ;
    END
  END t0[802]
  PIN t0[803]
    DIRECTION OUTPUT ;
    USE SIGNAL ;
    PORT
      LAYER M5 ;
        RECT  189.18 0 189.204 0.192 ;
    END
  END t0[803]
  PIN t0[804]
    DIRECTION OUTPUT ;
    USE SIGNAL ;
    PORT
      LAYER M5 ;
        RECT  189.42 0 189.444 0.192 ;
    END
  END t0[804]
  PIN t0[805]
    DIRECTION OUTPUT ;
    USE SIGNAL ;
    PORT
      LAYER M5 ;
        RECT  189.66 0 189.684 0.192 ;
    END
  END t0[805]
  PIN t0[806]
    DIRECTION OUTPUT ;
    USE SIGNAL ;
    PORT
      LAYER M5 ;
        RECT  189.852 0 189.876 0.192 ;
    END
  END t0[806]
  PIN t0[807]
    DIRECTION OUTPUT ;
    USE SIGNAL ;
    PORT
      LAYER M5 ;
        RECT  190.092 0 190.116 0.192 ;
    END
  END t0[807]
  PIN t0[808]
    DIRECTION OUTPUT ;
    USE SIGNAL ;
    PORT
      LAYER M5 ;
        RECT  190.332 0 190.356 0.192 ;
    END
  END t0[808]
  PIN t0[809]
    DIRECTION OUTPUT ;
    USE SIGNAL ;
    PORT
      LAYER M5 ;
        RECT  190.572 0 190.596 0.192 ;
    END
  END t0[809]
  PIN t0[80]
    DIRECTION OUTPUT ;
    USE SIGNAL ;
    PORT
      LAYER M5 ;
        RECT  20.748 0 20.772 0.192 ;
    END
  END t0[80]
  PIN t0[810]
    DIRECTION OUTPUT ;
    USE SIGNAL ;
    PORT
      LAYER M5 ;
        RECT  190.812 0 190.836 0.192 ;
    END
  END t0[810]
  PIN t0[811]
    DIRECTION OUTPUT ;
    USE SIGNAL ;
    PORT
      LAYER M5 ;
        RECT  191.052 0 191.076 0.192 ;
    END
  END t0[811]
  PIN t0[812]
    DIRECTION OUTPUT ;
    USE SIGNAL ;
    PORT
      LAYER M5 ;
        RECT  191.292 0 191.316 0.192 ;
    END
  END t0[812]
  PIN t0[813]
    DIRECTION OUTPUT ;
    USE SIGNAL ;
    PORT
      LAYER M5 ;
        RECT  191.484 0 191.508 0.192 ;
    END
  END t0[813]
  PIN t0[814]
    DIRECTION OUTPUT ;
    USE SIGNAL ;
    PORT
      LAYER M5 ;
        RECT  191.724 0 191.748 0.192 ;
    END
  END t0[814]
  PIN t0[815]
    DIRECTION OUTPUT ;
    USE SIGNAL ;
    PORT
      LAYER M5 ;
        RECT  191.964 0 191.988 0.192 ;
    END
  END t0[815]
  PIN t0[816]
    DIRECTION OUTPUT ;
    USE SIGNAL ;
    PORT
      LAYER M5 ;
        RECT  192.204 0 192.228 0.192 ;
    END
  END t0[816]
  PIN t0[817]
    DIRECTION OUTPUT ;
    USE SIGNAL ;
    PORT
      LAYER M5 ;
        RECT  192.444 0 192.468 0.192 ;
    END
  END t0[817]
  PIN t0[818]
    DIRECTION OUTPUT ;
    USE SIGNAL ;
    PORT
      LAYER M5 ;
        RECT  192.684 0 192.708 0.192 ;
    END
  END t0[818]
  PIN t0[819]
    DIRECTION OUTPUT ;
    USE SIGNAL ;
    PORT
      LAYER M5 ;
        RECT  192.924 0 192.948 0.192 ;
    END
  END t0[819]
  PIN t0[81]
    DIRECTION OUTPUT ;
    USE SIGNAL ;
    PORT
      LAYER M5 ;
        RECT  20.988 0 21.012 0.192 ;
    END
  END t0[81]
  PIN t0[820]
    DIRECTION OUTPUT ;
    USE SIGNAL ;
    PORT
      LAYER M5 ;
        RECT  193.116 0 193.14 0.192 ;
    END
  END t0[820]
  PIN t0[821]
    DIRECTION OUTPUT ;
    USE SIGNAL ;
    PORT
      LAYER M5 ;
        RECT  193.356 0 193.38 0.192 ;
    END
  END t0[821]
  PIN t0[822]
    DIRECTION OUTPUT ;
    USE SIGNAL ;
    PORT
      LAYER M5 ;
        RECT  193.596 0 193.62 0.192 ;
    END
  END t0[822]
  PIN t0[823]
    DIRECTION OUTPUT ;
    USE SIGNAL ;
    PORT
      LAYER M5 ;
        RECT  193.836 0 193.86 0.192 ;
    END
  END t0[823]
  PIN t0[824]
    DIRECTION OUTPUT ;
    USE SIGNAL ;
    PORT
      LAYER M5 ;
        RECT  194.076 0 194.1 0.192 ;
    END
  END t0[824]
  PIN t0[825]
    DIRECTION OUTPUT ;
    USE SIGNAL ;
    PORT
      LAYER M5 ;
        RECT  194.316 0 194.34 0.192 ;
    END
  END t0[825]
  PIN t0[826]
    DIRECTION OUTPUT ;
    USE SIGNAL ;
    PORT
      LAYER M5 ;
        RECT  194.556 0 194.58 0.192 ;
    END
  END t0[826]
  PIN t0[827]
    DIRECTION OUTPUT ;
    USE SIGNAL ;
    PORT
      LAYER M5 ;
        RECT  194.748 0 194.772 0.192 ;
    END
  END t0[827]
  PIN t0[828]
    DIRECTION OUTPUT ;
    USE SIGNAL ;
    PORT
      LAYER M5 ;
        RECT  194.988 0 195.012 0.192 ;
    END
  END t0[828]
  PIN t0[829]
    DIRECTION OUTPUT ;
    USE SIGNAL ;
    PORT
      LAYER M5 ;
        RECT  195.228 0 195.252 0.192 ;
    END
  END t0[829]
  PIN t0[82]
    DIRECTION OUTPUT ;
    USE SIGNAL ;
    PORT
      LAYER M5 ;
        RECT  21.228 0 21.252 0.192 ;
    END
  END t0[82]
  PIN t0[830]
    DIRECTION OUTPUT ;
    USE SIGNAL ;
    PORT
      LAYER M5 ;
        RECT  195.468 0 195.492 0.192 ;
    END
  END t0[830]
  PIN t0[831]
    DIRECTION OUTPUT ;
    USE SIGNAL ;
    PORT
      LAYER M5 ;
        RECT  195.708 0 195.732 0.192 ;
    END
  END t0[831]
  PIN t0[832]
    DIRECTION OUTPUT ;
    USE SIGNAL ;
    PORT
      LAYER M5 ;
        RECT  195.948 0 195.972 0.192 ;
    END
  END t0[832]
  PIN t0[833]
    DIRECTION OUTPUT ;
    USE SIGNAL ;
    PORT
      LAYER M5 ;
        RECT  196.188 0 196.212 0.192 ;
    END
  END t0[833]
  PIN t0[834]
    DIRECTION OUTPUT ;
    USE SIGNAL ;
    PORT
      LAYER M5 ;
        RECT  196.38 0 196.404 0.192 ;
    END
  END t0[834]
  PIN t0[835]
    DIRECTION OUTPUT ;
    USE SIGNAL ;
    PORT
      LAYER M5 ;
        RECT  196.62 0 196.644 0.192 ;
    END
  END t0[835]
  PIN t0[836]
    DIRECTION OUTPUT ;
    USE SIGNAL ;
    PORT
      LAYER M5 ;
        RECT  196.86 0 196.884 0.192 ;
    END
  END t0[836]
  PIN t0[837]
    DIRECTION OUTPUT ;
    USE SIGNAL ;
    PORT
      LAYER M5 ;
        RECT  197.1 0 197.124 0.192 ;
    END
  END t0[837]
  PIN t0[838]
    DIRECTION OUTPUT ;
    USE SIGNAL ;
    PORT
      LAYER M5 ;
        RECT  197.34 0 197.364 0.192 ;
    END
  END t0[838]
  PIN t0[839]
    DIRECTION OUTPUT ;
    USE SIGNAL ;
    PORT
      LAYER M5 ;
        RECT  197.58 0 197.604 0.192 ;
    END
  END t0[839]
  PIN t0[83]
    DIRECTION OUTPUT ;
    USE SIGNAL ;
    PORT
      LAYER M5 ;
        RECT  21.42 0 21.444 0.192 ;
    END
  END t0[83]
  PIN t0[840]
    DIRECTION OUTPUT ;
    USE SIGNAL ;
    PORT
      LAYER M5 ;
        RECT  197.82 0 197.844 0.192 ;
    END
  END t0[840]
  PIN t0[841]
    DIRECTION OUTPUT ;
    USE SIGNAL ;
    PORT
      LAYER M5 ;
        RECT  198.012 0 198.036 0.192 ;
    END
  END t0[841]
  PIN t0[842]
    DIRECTION OUTPUT ;
    USE SIGNAL ;
    PORT
      LAYER M5 ;
        RECT  198.252 0 198.276 0.192 ;
    END
  END t0[842]
  PIN t0[843]
    DIRECTION OUTPUT ;
    USE SIGNAL ;
    PORT
      LAYER M5 ;
        RECT  198.492 0 198.516 0.192 ;
    END
  END t0[843]
  PIN t0[844]
    DIRECTION OUTPUT ;
    USE SIGNAL ;
    PORT
      LAYER M5 ;
        RECT  198.732 0 198.756 0.192 ;
    END
  END t0[844]
  PIN t0[845]
    DIRECTION OUTPUT ;
    USE SIGNAL ;
    PORT
      LAYER M5 ;
        RECT  198.972 0 198.996 0.192 ;
    END
  END t0[845]
  PIN t0[846]
    DIRECTION OUTPUT ;
    USE SIGNAL ;
    PORT
      LAYER M5 ;
        RECT  199.212 0 199.236 0.192 ;
    END
  END t0[846]
  PIN t0[847]
    DIRECTION OUTPUT ;
    USE SIGNAL ;
    PORT
      LAYER M5 ;
        RECT  199.404 0 199.428 0.192 ;
    END
  END t0[847]
  PIN t0[848]
    DIRECTION OUTPUT ;
    USE SIGNAL ;
    PORT
      LAYER M5 ;
        RECT  199.644 0 199.668 0.192 ;
    END
  END t0[848]
  PIN t0[849]
    DIRECTION OUTPUT ;
    USE SIGNAL ;
    PORT
      LAYER M5 ;
        RECT  199.884 0 199.908 0.192 ;
    END
  END t0[849]
  PIN t0[84]
    DIRECTION OUTPUT ;
    USE SIGNAL ;
    PORT
      LAYER M5 ;
        RECT  21.66 0 21.684 0.192 ;
    END
  END t0[84]
  PIN t0[850]
    DIRECTION OUTPUT ;
    USE SIGNAL ;
    PORT
      LAYER M5 ;
        RECT  200.124 0 200.148 0.192 ;
    END
  END t0[850]
  PIN t0[851]
    DIRECTION OUTPUT ;
    USE SIGNAL ;
    PORT
      LAYER M5 ;
        RECT  200.364 0 200.388 0.192 ;
    END
  END t0[851]
  PIN t0[852]
    DIRECTION OUTPUT ;
    USE SIGNAL ;
    PORT
      LAYER M5 ;
        RECT  200.604 0 200.628 0.192 ;
    END
  END t0[852]
  PIN t0[853]
    DIRECTION OUTPUT ;
    USE SIGNAL ;
    PORT
      LAYER M5 ;
        RECT  200.844 0 200.868 0.192 ;
    END
  END t0[853]
  PIN t0[854]
    DIRECTION OUTPUT ;
    USE SIGNAL ;
    PORT
      LAYER M5 ;
        RECT  201.036 0 201.06 0.192 ;
    END
  END t0[854]
  PIN t0[855]
    DIRECTION OUTPUT ;
    USE SIGNAL ;
    PORT
      LAYER M5 ;
        RECT  201.276 0 201.3 0.192 ;
    END
  END t0[855]
  PIN t0[856]
    DIRECTION OUTPUT ;
    USE SIGNAL ;
    PORT
      LAYER M5 ;
        RECT  201.516 0 201.54 0.192 ;
    END
  END t0[856]
  PIN t0[857]
    DIRECTION OUTPUT ;
    USE SIGNAL ;
    PORT
      LAYER M5 ;
        RECT  201.756 0 201.78 0.192 ;
    END
  END t0[857]
  PIN t0[858]
    DIRECTION OUTPUT ;
    USE SIGNAL ;
    PORT
      LAYER M5 ;
        RECT  201.996 0 202.02 0.192 ;
    END
  END t0[858]
  PIN t0[859]
    DIRECTION OUTPUT ;
    USE SIGNAL ;
    PORT
      LAYER M5 ;
        RECT  202.236 0 202.26 0.192 ;
    END
  END t0[859]
  PIN t0[85]
    DIRECTION OUTPUT ;
    USE SIGNAL ;
    PORT
      LAYER M5 ;
        RECT  21.9 0 21.924 0.192 ;
    END
  END t0[85]
  PIN t0[860]
    DIRECTION OUTPUT ;
    USE SIGNAL ;
    PORT
      LAYER M5 ;
        RECT  202.476 0 202.5 0.192 ;
    END
  END t0[860]
  PIN t0[861]
    DIRECTION OUTPUT ;
    USE SIGNAL ;
    PORT
      LAYER M5 ;
        RECT  202.668 0 202.692 0.192 ;
    END
  END t0[861]
  PIN t0[862]
    DIRECTION OUTPUT ;
    USE SIGNAL ;
    PORT
      LAYER M5 ;
        RECT  202.908 0 202.932 0.192 ;
    END
  END t0[862]
  PIN t0[863]
    DIRECTION OUTPUT ;
    USE SIGNAL ;
    PORT
      LAYER M5 ;
        RECT  203.148 0 203.172 0.192 ;
    END
  END t0[863]
  PIN t0[864]
    DIRECTION OUTPUT ;
    USE SIGNAL ;
    PORT
      LAYER M5 ;
        RECT  203.388 0 203.412 0.192 ;
    END
  END t0[864]
  PIN t0[865]
    DIRECTION OUTPUT ;
    USE SIGNAL ;
    PORT
      LAYER M5 ;
        RECT  203.628 0 203.652 0.192 ;
    END
  END t0[865]
  PIN t0[866]
    DIRECTION OUTPUT ;
    USE SIGNAL ;
    PORT
      LAYER M5 ;
        RECT  203.868 0 203.892 0.192 ;
    END
  END t0[866]
  PIN t0[867]
    DIRECTION OUTPUT ;
    USE SIGNAL ;
    PORT
      LAYER M5 ;
        RECT  204.108 0 204.132 0.192 ;
    END
  END t0[867]
  PIN t0[868]
    DIRECTION OUTPUT ;
    USE SIGNAL ;
    PORT
      LAYER M5 ;
        RECT  204.3 0 204.324 0.192 ;
    END
  END t0[868]
  PIN t0[869]
    DIRECTION OUTPUT ;
    USE SIGNAL ;
    PORT
      LAYER M5 ;
        RECT  204.54 0 204.564 0.192 ;
    END
  END t0[869]
  PIN t0[86]
    DIRECTION OUTPUT ;
    USE SIGNAL ;
    PORT
      LAYER M5 ;
        RECT  22.14 0 22.164 0.192 ;
    END
  END t0[86]
  PIN t0[870]
    DIRECTION OUTPUT ;
    USE SIGNAL ;
    PORT
      LAYER M5 ;
        RECT  204.78 0 204.804 0.192 ;
    END
  END t0[870]
  PIN t0[871]
    DIRECTION OUTPUT ;
    USE SIGNAL ;
    PORT
      LAYER M5 ;
        RECT  205.02 0 205.044 0.192 ;
    END
  END t0[871]
  PIN t0[872]
    DIRECTION OUTPUT ;
    USE SIGNAL ;
    PORT
      LAYER M5 ;
        RECT  205.26 0 205.284 0.192 ;
    END
  END t0[872]
  PIN t0[873]
    DIRECTION OUTPUT ;
    USE SIGNAL ;
    PORT
      LAYER M5 ;
        RECT  205.5 0 205.524 0.192 ;
    END
  END t0[873]
  PIN t0[874]
    DIRECTION OUTPUT ;
    USE SIGNAL ;
    PORT
      LAYER M5 ;
        RECT  205.74 0 205.764 0.192 ;
    END
  END t0[874]
  PIN t0[875]
    DIRECTION OUTPUT ;
    USE SIGNAL ;
    PORT
      LAYER M5 ;
        RECT  205.932 0 205.956 0.192 ;
    END
  END t0[875]
  PIN t0[876]
    DIRECTION OUTPUT ;
    USE SIGNAL ;
    PORT
      LAYER M5 ;
        RECT  206.172 0 206.196 0.192 ;
    END
  END t0[876]
  PIN t0[877]
    DIRECTION OUTPUT ;
    USE SIGNAL ;
    PORT
      LAYER M5 ;
        RECT  206.412 0 206.436 0.192 ;
    END
  END t0[877]
  PIN t0[878]
    DIRECTION OUTPUT ;
    USE SIGNAL ;
    PORT
      LAYER M5 ;
        RECT  206.652 0 206.676 0.192 ;
    END
  END t0[878]
  PIN t0[879]
    DIRECTION OUTPUT ;
    USE SIGNAL ;
    PORT
      LAYER M5 ;
        RECT  206.892 0 206.916 0.192 ;
    END
  END t0[879]
  PIN t0[87]
    DIRECTION OUTPUT ;
    USE SIGNAL ;
    PORT
      LAYER M5 ;
        RECT  22.38 0 22.404 0.192 ;
    END
  END t0[87]
  PIN t0[880]
    DIRECTION OUTPUT ;
    USE SIGNAL ;
    PORT
      LAYER M5 ;
        RECT  207.132 0 207.156 0.192 ;
    END
  END t0[880]
  PIN t0[881]
    DIRECTION OUTPUT ;
    USE SIGNAL ;
    PORT
      LAYER M5 ;
        RECT  207.372 0 207.396 0.192 ;
    END
  END t0[881]
  PIN t0[882]
    DIRECTION OUTPUT ;
    USE SIGNAL ;
    PORT
      LAYER M5 ;
        RECT  207.564 0 207.588 0.192 ;
    END
  END t0[882]
  PIN t0[883]
    DIRECTION OUTPUT ;
    USE SIGNAL ;
    PORT
      LAYER M5 ;
        RECT  207.804 0 207.828 0.192 ;
    END
  END t0[883]
  PIN t0[884]
    DIRECTION OUTPUT ;
    USE SIGNAL ;
    PORT
      LAYER M5 ;
        RECT  208.044 0 208.068 0.192 ;
    END
  END t0[884]
  PIN t0[885]
    DIRECTION OUTPUT ;
    USE SIGNAL ;
    PORT
      LAYER M5 ;
        RECT  208.284 0 208.308 0.192 ;
    END
  END t0[885]
  PIN t0[886]
    DIRECTION OUTPUT ;
    USE SIGNAL ;
    PORT
      LAYER M5 ;
        RECT  208.524 0 208.548 0.192 ;
    END
  END t0[886]
  PIN t0[887]
    DIRECTION OUTPUT ;
    USE SIGNAL ;
    PORT
      LAYER M5 ;
        RECT  208.764 0 208.788 0.192 ;
    END
  END t0[887]
  PIN t0[888]
    DIRECTION OUTPUT ;
    USE SIGNAL ;
    PORT
      LAYER M5 ;
        RECT  208.956 0 208.98 0.192 ;
    END
  END t0[888]
  PIN t0[889]
    DIRECTION OUTPUT ;
    USE SIGNAL ;
    PORT
      LAYER M5 ;
        RECT  209.196 0 209.22 0.192 ;
    END
  END t0[889]
  PIN t0[88]
    DIRECTION OUTPUT ;
    USE SIGNAL ;
    PORT
      LAYER M5 ;
        RECT  22.62 0 22.644 0.192 ;
    END
  END t0[88]
  PIN t0[890]
    DIRECTION OUTPUT ;
    USE SIGNAL ;
    PORT
      LAYER M5 ;
        RECT  209.436 0 209.46 0.192 ;
    END
  END t0[890]
  PIN t0[891]
    DIRECTION OUTPUT ;
    USE SIGNAL ;
    PORT
      LAYER M5 ;
        RECT  209.676 0 209.7 0.192 ;
    END
  END t0[891]
  PIN t0[892]
    DIRECTION OUTPUT ;
    USE SIGNAL ;
    PORT
      LAYER M5 ;
        RECT  209.916 0 209.94 0.192 ;
    END
  END t0[892]
  PIN t0[893]
    DIRECTION OUTPUT ;
    USE SIGNAL ;
    PORT
      LAYER M5 ;
        RECT  210.156 0 210.18 0.192 ;
    END
  END t0[893]
  PIN t0[894]
    DIRECTION OUTPUT ;
    USE SIGNAL ;
    PORT
      LAYER M5 ;
        RECT  210.396 0 210.42 0.192 ;
    END
  END t0[894]
  PIN t0[895]
    DIRECTION OUTPUT ;
    USE SIGNAL ;
    PORT
      LAYER M5 ;
        RECT  210.588 0 210.612 0.192 ;
    END
  END t0[895]
  PIN t0[896]
    DIRECTION OUTPUT ;
    USE SIGNAL ;
    PORT
      LAYER M5 ;
        RECT  210.828 0 210.852 0.192 ;
    END
  END t0[896]
  PIN t0[897]
    DIRECTION OUTPUT ;
    USE SIGNAL ;
    PORT
      LAYER M5 ;
        RECT  211.068 0 211.092 0.192 ;
    END
  END t0[897]
  PIN t0[898]
    DIRECTION OUTPUT ;
    USE SIGNAL ;
    PORT
      LAYER M5 ;
        RECT  211.308 0 211.332 0.192 ;
    END
  END t0[898]
  PIN t0[899]
    DIRECTION OUTPUT ;
    USE SIGNAL ;
    PORT
      LAYER M5 ;
        RECT  211.548 0 211.572 0.192 ;
    END
  END t0[899]
  PIN t0[89]
    DIRECTION OUTPUT ;
    USE SIGNAL ;
    PORT
      LAYER M5 ;
        RECT  22.86 0 22.884 0.192 ;
    END
  END t0[89]
  PIN t0[8]
    DIRECTION OUTPUT ;
    USE SIGNAL ;
    PORT
      LAYER M5 ;
        RECT  3.948 0 3.972 0.192 ;
    END
  END t0[8]
  PIN t0[900]
    DIRECTION OUTPUT ;
    USE SIGNAL ;
    PORT
      LAYER M5 ;
        RECT  211.788 0 211.812 0.192 ;
    END
  END t0[900]
  PIN t0[901]
    DIRECTION OUTPUT ;
    USE SIGNAL ;
    PORT
      LAYER M5 ;
        RECT  212.028 0 212.052 0.192 ;
    END
  END t0[901]
  PIN t0[902]
    DIRECTION OUTPUT ;
    USE SIGNAL ;
    PORT
      LAYER M5 ;
        RECT  212.22 0 212.244 0.192 ;
    END
  END t0[902]
  PIN t0[903]
    DIRECTION OUTPUT ;
    USE SIGNAL ;
    PORT
      LAYER M5 ;
        RECT  212.46 0 212.484 0.192 ;
    END
  END t0[903]
  PIN t0[904]
    DIRECTION OUTPUT ;
    USE SIGNAL ;
    PORT
      LAYER M5 ;
        RECT  212.7 0 212.724 0.192 ;
    END
  END t0[904]
  PIN t0[905]
    DIRECTION OUTPUT ;
    USE SIGNAL ;
    PORT
      LAYER M5 ;
        RECT  212.94 0 212.964 0.192 ;
    END
  END t0[905]
  PIN t0[906]
    DIRECTION OUTPUT ;
    USE SIGNAL ;
    PORT
      LAYER M5 ;
        RECT  213.18 0 213.204 0.192 ;
    END
  END t0[906]
  PIN t0[907]
    DIRECTION OUTPUT ;
    USE SIGNAL ;
    PORT
      LAYER M5 ;
        RECT  213.42 0 213.444 0.192 ;
    END
  END t0[907]
  PIN t0[908]
    DIRECTION OUTPUT ;
    USE SIGNAL ;
    PORT
      LAYER M5 ;
        RECT  213.66 0 213.684 0.192 ;
    END
  END t0[908]
  PIN t0[909]
    DIRECTION OUTPUT ;
    USE SIGNAL ;
    PORT
      LAYER M5 ;
        RECT  213.852 0 213.876 0.192 ;
    END
  END t0[909]
  PIN t0[90]
    DIRECTION OUTPUT ;
    USE SIGNAL ;
    PORT
      LAYER M5 ;
        RECT  23.052 0 23.076 0.192 ;
    END
  END t0[90]
  PIN t0[91]
    DIRECTION OUTPUT ;
    USE SIGNAL ;
    PORT
      LAYER M5 ;
        RECT  23.292 0 23.316 0.192 ;
    END
  END t0[91]
  PIN t0[92]
    DIRECTION OUTPUT ;
    USE SIGNAL ;
    PORT
      LAYER M5 ;
        RECT  23.532 0 23.556 0.192 ;
    END
  END t0[92]
  PIN t0[93]
    DIRECTION OUTPUT ;
    USE SIGNAL ;
    PORT
      LAYER M5 ;
        RECT  23.772 0 23.796 0.192 ;
    END
  END t0[93]
  PIN t0[94]
    DIRECTION OUTPUT ;
    USE SIGNAL ;
    PORT
      LAYER M5 ;
        RECT  24.012 0 24.036 0.192 ;
    END
  END t0[94]
  PIN t0[95]
    DIRECTION OUTPUT ;
    USE SIGNAL ;
    PORT
      LAYER M5 ;
        RECT  24.252 0 24.276 0.192 ;
    END
  END t0[95]
  PIN t0[96]
    DIRECTION OUTPUT ;
    USE SIGNAL ;
    PORT
      LAYER M5 ;
        RECT  24.492 0 24.516 0.192 ;
    END
  END t0[96]
  PIN t0[97]
    DIRECTION OUTPUT ;
    USE SIGNAL ;
    PORT
      LAYER M5 ;
        RECT  24.684 0 24.708 0.192 ;
    END
  END t0[97]
  PIN t0[98]
    DIRECTION OUTPUT ;
    USE SIGNAL ;
    PORT
      LAYER M5 ;
        RECT  24.924 0 24.948 0.192 ;
    END
  END t0[98]
  PIN t0[99]
    DIRECTION OUTPUT ;
    USE SIGNAL ;
    PORT
      LAYER M5 ;
        RECT  25.164 0 25.188 0.192 ;
    END
  END t0[99]
  PIN t0[9]
    DIRECTION OUTPUT ;
    USE SIGNAL ;
    PORT
      LAYER M5 ;
        RECT  4.188 0 4.212 0.192 ;
    END
  END t0[9]
  PIN VDD
    DIRECTION INOUT ;
    USE POWER ;
    PORT
      LAYER M5 ;
        RECT  235.476 4.311 235.596 168.489 ;
        RECT  231.156 4.311 231.276 168.489 ;
        RECT  226.836 4.311 226.956 168.489 ;
        RECT  222.516 4.311 222.636 168.489 ;
        RECT  218.196 4.311 218.316 168.489 ;
        RECT  213.876 4.311 213.996 168.489 ;
        RECT  209.556 4.311 209.676 168.489 ;
        RECT  205.236 4.311 205.356 168.489 ;
        RECT  200.916 4.311 201.036 168.489 ;
        RECT  196.596 4.311 196.716 168.489 ;
        RECT  192.276 4.311 192.396 168.489 ;
        RECT  187.956 4.311 188.076 168.489 ;
        RECT  183.636 4.311 183.756 168.489 ;
        RECT  179.316 4.311 179.436 168.489 ;
        RECT  174.996 4.311 175.116 168.489 ;
        RECT  170.676 4.311 170.796 168.489 ;
        RECT  166.356 4.311 166.476 168.489 ;
        RECT  162.036 4.311 162.156 168.489 ;
        RECT  157.716 4.311 157.836 168.489 ;
        RECT  153.396 4.311 153.516 168.489 ;
        RECT  149.076 4.311 149.196 168.489 ;
        RECT  144.756 4.311 144.876 168.489 ;
        RECT  140.436 4.311 140.556 168.489 ;
        RECT  136.116 4.311 136.236 168.489 ;
        RECT  131.796 4.311 131.916 168.489 ;
        RECT  127.476 4.311 127.596 168.489 ;
        RECT  123.156 4.311 123.276 168.489 ;
        RECT  118.836 4.311 118.956 168.489 ;
        RECT  114.516 4.311 114.636 168.489 ;
        RECT  110.196 4.311 110.316 168.489 ;
        RECT  105.876 4.311 105.996 168.489 ;
        RECT  101.556 4.311 101.676 168.489 ;
        RECT  97.236 4.311 97.356 168.489 ;
        RECT  92.916 4.311 93.036 168.489 ;
        RECT  88.596 4.311 88.716 168.489 ;
        RECT  84.276 4.311 84.396 168.489 ;
        RECT  79.956 4.311 80.076 168.489 ;
        RECT  75.636 4.311 75.756 168.489 ;
        RECT  71.316 4.311 71.436 168.489 ;
        RECT  66.996 4.311 67.116 168.489 ;
        RECT  62.676 4.311 62.796 168.489 ;
        RECT  58.356 4.311 58.476 168.489 ;
        RECT  54.036 4.311 54.156 168.489 ;
        RECT  49.716 4.311 49.836 168.489 ;
        RECT  45.396 4.311 45.516 168.489 ;
        RECT  41.076 4.311 41.196 168.489 ;
        RECT  36.756 4.311 36.876 168.489 ;
        RECT  32.436 4.311 32.556 168.489 ;
        RECT  28.116 4.311 28.236 168.489 ;
        RECT  23.796 4.311 23.916 168.489 ;
        RECT  19.476 4.311 19.596 168.489 ;
        RECT  15.156 4.311 15.276 168.489 ;
        RECT  10.836 4.311 10.956 168.489 ;
        RECT  6.516 4.311 6.636 168.489 ;
    END
  END VDD
  PIN VSS
    DIRECTION INOUT ;
    USE GROUND ;
    PORT
      LAYER M5 ;
        RECT  235.284 4.297 235.404 168.503 ;
        RECT  230.964 4.297 231.084 168.503 ;
        RECT  226.644 4.297 226.764 168.489 ;
        RECT  222.324 4.297 222.444 168.489 ;
        RECT  218.004 4.297 218.124 168.489 ;
        RECT  213.684 4.297 213.804 168.489 ;
        RECT  209.364 4.297 209.484 168.489 ;
        RECT  205.044 4.297 205.164 168.489 ;
        RECT  200.724 4.297 200.844 168.489 ;
        RECT  196.404 4.297 196.524 168.489 ;
        RECT  192.084 4.297 192.204 168.489 ;
        RECT  187.764 4.297 187.884 168.489 ;
        RECT  183.444 4.297 183.564 168.489 ;
        RECT  179.124 4.297 179.244 168.489 ;
        RECT  174.804 4.297 174.924 168.489 ;
        RECT  170.484 4.297 170.604 168.489 ;
        RECT  166.164 4.297 166.284 168.489 ;
        RECT  161.844 4.297 161.964 168.489 ;
        RECT  157.524 4.297 157.644 168.489 ;
        RECT  153.204 4.297 153.324 168.489 ;
        RECT  148.884 4.297 149.004 168.489 ;
        RECT  144.564 4.297 144.684 168.489 ;
        RECT  140.244 4.297 140.364 168.489 ;
        RECT  135.924 4.297 136.044 168.489 ;
        RECT  131.604 4.297 131.724 168.489 ;
        RECT  127.284 4.297 127.404 168.503 ;
        RECT  122.964 4.297 123.084 168.503 ;
        RECT  118.644 4.297 118.764 168.503 ;
        RECT  114.324 4.297 114.444 168.503 ;
        RECT  110.004 4.297 110.124 168.489 ;
        RECT  105.684 4.297 105.804 168.489 ;
        RECT  101.364 4.297 101.484 168.489 ;
        RECT  97.044 4.297 97.164 168.489 ;
        RECT  92.724 4.297 92.844 168.489 ;
        RECT  88.404 4.297 88.524 168.489 ;
        RECT  84.084 4.297 84.204 168.489 ;
        RECT  79.764 4.297 79.884 168.489 ;
        RECT  75.444 4.297 75.564 168.489 ;
        RECT  71.124 4.297 71.244 168.489 ;
        RECT  66.804 4.297 66.924 168.489 ;
        RECT  62.484 4.297 62.604 168.489 ;
        RECT  58.164 4.297 58.284 168.489 ;
        RECT  53.844 4.297 53.964 168.489 ;
        RECT  49.524 4.297 49.644 168.489 ;
        RECT  45.204 4.297 45.324 168.489 ;
        RECT  40.884 4.297 41.004 168.489 ;
        RECT  36.564 4.297 36.684 168.489 ;
        RECT  32.244 4.297 32.364 168.489 ;
        RECT  27.924 4.297 28.044 168.489 ;
        RECT  23.604 4.297 23.724 168.489 ;
        RECT  19.284 4.297 19.404 168.489 ;
        RECT  14.964 4.297 15.084 168.489 ;
        RECT  10.644 4.297 10.764 168.503 ;
        RECT  6.324 4.297 6.444 168.503 ;
    END
  END VSS
  OBS
    LAYER RVTN ;
     RECT  0 0 243.648 172.463 ;
    LAYER RVTP ;
     RECT  0 0 243.648 172.463 ;
    LAYER M1 ;
     RECT  0 0 243.648 172.463 ;
    LAYER M2 ;
     RECT  0 0 243.648 172.463 ;
    LAYER M3 ;
     RECT  0 0 243.648 172.463 ;
    LAYER M4 ;
     RECT  0 0 243.648 172.463 ;
    LAYER M5 ;
     RECT  0 0 243.648 172.463 ;
  END
END qkd_ectlk_q1
END LIBRARY
